# OpenTallas tools/mem_compiler/s81_pma_gen.py: S81 SerDes analog PMA ABSTRACT ot_s81_pma_txm (assumed footprint/timing)
VERSION 5.7 ;
BUSBITCHARS "[]" ;
DIVIDERCHAR "/" ;
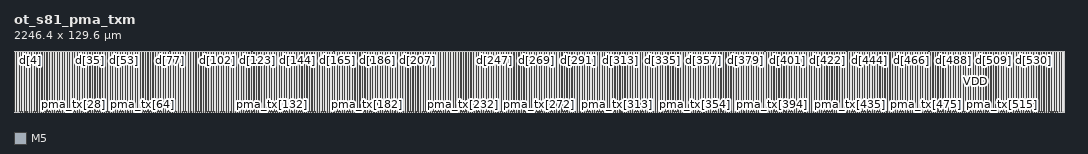
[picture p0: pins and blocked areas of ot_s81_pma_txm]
MACRO ot_s81_pma_txm
  FOREIGN ot_s81_pma_txm 0 0 ;
  SYMMETRY X Y ;
  SIZE 2246.400 BY 129.600 ;
  CLASS BLOCK ;
  PIN ck
    DIRECTION INPUT ;
    USE CLOCK ;
    SHAPE ABUTMENT ;
    PORT
      LAYER M5 ;
      RECT 11.412 129.408 11.436 129.600 ;
    END
  END ck
  PIN d_v
    DIRECTION INPUT ;
    USE SIGNAL ;
    SHAPE ABUTMENT ;
    PORT
      LAYER M5 ;
      RECT 15.492 129.408 15.516 129.600 ;
    END
  END d_v
  PIN d[0]
    DIRECTION INPUT ;
    USE SIGNAL ;
    SHAPE ABUTMENT ;
    PORT
      LAYER M5 ;
      RECT 19.572 129.408 19.596 129.600 ;
    END
  END d[0]
  PIN d[1]
    DIRECTION INPUT ;
    USE SIGNAL ;
    SHAPE ABUTMENT ;
    PORT
      LAYER M5 ;
      RECT 23.652 129.408 23.676 129.600 ;
    END
  END d[1]
  PIN d[2]
    DIRECTION INPUT ;
    USE SIGNAL ;
    SHAPE ABUTMENT ;
    PORT
      LAYER M5 ;
      RECT 27.732 129.408 27.756 129.600 ;
    END
  END d[2]
  PIN d[3]
    DIRECTION INPUT ;
    USE SIGNAL ;
    SHAPE ABUTMENT ;
    PORT
      LAYER M5 ;
      RECT 31.812 129.408 31.836 129.600 ;
    END
  END d[3]
  PIN d[4]
    DIRECTION INPUT ;
    USE SIGNAL ;
    SHAPE ABUTMENT ;
    PORT
      LAYER M5 ;
      RECT 35.892 129.408 35.916 129.600 ;
    END
  END d[4]
  PIN d[5]
    DIRECTION INPUT ;
    USE SIGNAL ;
    SHAPE ABUTMENT ;
    PORT
      LAYER M5 ;
      RECT 39.972 129.408 39.996 129.600 ;
    END
  END d[5]
  PIN d[6]
    DIRECTION INPUT ;
    USE SIGNAL ;
    SHAPE ABUTMENT ;
    PORT
      LAYER M5 ;
      RECT 44.052 129.408 44.076 129.600 ;
    END
  END d[6]
  PIN d[7]
    DIRECTION INPUT ;
    USE SIGNAL ;
    SHAPE ABUTMENT ;
    PORT
      LAYER M5 ;
      RECT 48.132 129.408 48.156 129.600 ;
    END
  END d[7]
  PIN d[8]
    DIRECTION INPUT ;
    USE SIGNAL ;
    SHAPE ABUTMENT ;
    PORT
      LAYER M5 ;
      RECT 52.212 129.408 52.236 129.600 ;
    END
  END d[8]
  PIN d[9]
    DIRECTION INPUT ;
    USE SIGNAL ;
    SHAPE ABUTMENT ;
    PORT
      LAYER M5 ;
      RECT 56.292 129.408 56.316 129.600 ;
    END
  END d[9]
  PIN d[10]
    DIRECTION INPUT ;
    USE SIGNAL ;
    SHAPE ABUTMENT ;
    PORT
      LAYER M5 ;
      RECT 60.372 129.408 60.396 129.600 ;
    END
  END d[10]
  PIN d[11]
    DIRECTION INPUT ;
    USE SIGNAL ;
    SHAPE ABUTMENT ;
    PORT
      LAYER M5 ;
      RECT 64.452 129.408 64.476 129.600 ;
    END
  END d[11]
  PIN d[12]
    DIRECTION INPUT ;
    USE SIGNAL ;
    SHAPE ABUTMENT ;
    PORT
      LAYER M5 ;
      RECT 68.532 129.408 68.556 129.600 ;
    END
  END d[12]
  PIN d[13]
    DIRECTION INPUT ;
    USE SIGNAL ;
    SHAPE ABUTMENT ;
    PORT
      LAYER M5 ;
      RECT 72.612 129.408 72.636 129.600 ;
    END
  END d[13]
  PIN d[14]
    DIRECTION INPUT ;
    USE SIGNAL ;
    SHAPE ABUTMENT ;
    PORT
      LAYER M5 ;
      RECT 76.692 129.408 76.716 129.600 ;
    END
  END d[14]
  PIN d[15]
    DIRECTION INPUT ;
    USE SIGNAL ;
    SHAPE ABUTMENT ;
    PORT
      LAYER M5 ;
      RECT 80.772 129.408 80.796 129.600 ;
    END
  END d[15]
  PIN d[16]
    DIRECTION INPUT ;
    USE SIGNAL ;
    SHAPE ABUTMENT ;
    PORT
      LAYER M5 ;
      RECT 84.852 129.408 84.876 129.600 ;
    END
  END d[16]
  PIN d[17]
    DIRECTION INPUT ;
    USE SIGNAL ;
    SHAPE ABUTMENT ;
    PORT
      LAYER M5 ;
      RECT 88.932 129.408 88.956 129.600 ;
    END
  END d[17]
  PIN d[18]
    DIRECTION INPUT ;
    USE SIGNAL ;
    SHAPE ABUTMENT ;
    PORT
      LAYER M5 ;
      RECT 93.012 129.408 93.036 129.600 ;
    END
  END d[18]
  PIN d[19]
    DIRECTION INPUT ;
    USE SIGNAL ;
    SHAPE ABUTMENT ;
    PORT
      LAYER M5 ;
      RECT 97.092 129.408 97.116 129.600 ;
    END
  END d[19]
  PIN d[20]
    DIRECTION INPUT ;
    USE SIGNAL ;
    SHAPE ABUTMENT ;
    PORT
      LAYER M5 ;
      RECT 101.172 129.408 101.196 129.600 ;
    END
  END d[20]
  PIN d[21]
    DIRECTION INPUT ;
    USE SIGNAL ;
    SHAPE ABUTMENT ;
    PORT
      LAYER M5 ;
      RECT 105.252 129.408 105.276 129.600 ;
    END
  END d[21]
  PIN d[22]
    DIRECTION INPUT ;
    USE SIGNAL ;
    SHAPE ABUTMENT ;
    PORT
      LAYER M5 ;
      RECT 109.332 129.408 109.356 129.600 ;
    END
  END d[22]
  PIN d[23]
    DIRECTION INPUT ;
    USE SIGNAL ;
    SHAPE ABUTMENT ;
    PORT
      LAYER M5 ;
      RECT 113.412 129.408 113.436 129.600 ;
    END
  END d[23]
  PIN d[24]
    DIRECTION INPUT ;
    USE SIGNAL ;
    SHAPE ABUTMENT ;
    PORT
      LAYER M5 ;
      RECT 117.492 129.408 117.516 129.600 ;
    END
  END d[24]
  PIN d[25]
    DIRECTION INPUT ;
    USE SIGNAL ;
    SHAPE ABUTMENT ;
    PORT
      LAYER M5 ;
      RECT 121.572 129.408 121.596 129.600 ;
    END
  END d[25]
  PIN d[26]
    DIRECTION INPUT ;
    USE SIGNAL ;
    SHAPE ABUTMENT ;
    PORT
      LAYER M5 ;
      RECT 125.652 129.408 125.676 129.600 ;
    END
  END d[26]
  PIN d[27]
    DIRECTION INPUT ;
    USE SIGNAL ;
    SHAPE ABUTMENT ;
    PORT
      LAYER M5 ;
      RECT 129.732 129.408 129.756 129.600 ;
    END
  END d[27]
  PIN d[28]
    DIRECTION INPUT ;
    USE SIGNAL ;
    SHAPE ABUTMENT ;
    PORT
      LAYER M5 ;
      RECT 133.812 129.408 133.836 129.600 ;
    END
  END d[28]
  PIN d[29]
    DIRECTION INPUT ;
    USE SIGNAL ;
    SHAPE ABUTMENT ;
    PORT
      LAYER M5 ;
      RECT 137.892 129.408 137.916 129.600 ;
    END
  END d[29]
  PIN d[30]
    DIRECTION INPUT ;
    USE SIGNAL ;
    SHAPE ABUTMENT ;
    PORT
      LAYER M5 ;
      RECT 141.972 129.408 141.996 129.600 ;
    END
  END d[30]
  PIN d[31]
    DIRECTION INPUT ;
    USE SIGNAL ;
    SHAPE ABUTMENT ;
    PORT
      LAYER M5 ;
      RECT 146.052 129.408 146.076 129.600 ;
    END
  END d[31]
  PIN d[32]
    DIRECTION INPUT ;
    USE SIGNAL ;
    SHAPE ABUTMENT ;
    PORT
      LAYER M5 ;
      RECT 150.132 129.408 150.156 129.600 ;
    END
  END d[32]
  PIN d[33]
    DIRECTION INPUT ;
    USE SIGNAL ;
    SHAPE ABUTMENT ;
    PORT
      LAYER M5 ;
      RECT 154.212 129.408 154.236 129.600 ;
    END
  END d[33]
  PIN d[34]
    DIRECTION INPUT ;
    USE SIGNAL ;
    SHAPE ABUTMENT ;
    PORT
      LAYER M5 ;
      RECT 158.292 129.408 158.316 129.600 ;
    END
  END d[34]
  PIN d[35]
    DIRECTION INPUT ;
    USE SIGNAL ;
    SHAPE ABUTMENT ;
    PORT
      LAYER M5 ;
      RECT 162.372 129.408 162.396 129.600 ;
    END
  END d[35]
  PIN d[36]
    DIRECTION INPUT ;
    USE SIGNAL ;
    SHAPE ABUTMENT ;
    PORT
      LAYER M5 ;
      RECT 166.452 129.408 166.476 129.600 ;
    END
  END d[36]
  PIN d[37]
    DIRECTION INPUT ;
    USE SIGNAL ;
    SHAPE ABUTMENT ;
    PORT
      LAYER M5 ;
      RECT 170.532 129.408 170.556 129.600 ;
    END
  END d[37]
  PIN d[38]
    DIRECTION INPUT ;
    USE SIGNAL ;
    SHAPE ABUTMENT ;
    PORT
      LAYER M5 ;
      RECT 174.612 129.408 174.636 129.600 ;
    END
  END d[38]
  PIN d[39]
    DIRECTION INPUT ;
    USE SIGNAL ;
    SHAPE ABUTMENT ;
    PORT
      LAYER M5 ;
      RECT 178.692 129.408 178.716 129.600 ;
    END
  END d[39]
  PIN d[40]
    DIRECTION INPUT ;
    USE SIGNAL ;
    SHAPE ABUTMENT ;
    PORT
      LAYER M5 ;
      RECT 182.772 129.408 182.796 129.600 ;
    END
  END d[40]
  PIN d[41]
    DIRECTION INPUT ;
    USE SIGNAL ;
    SHAPE ABUTMENT ;
    PORT
      LAYER M5 ;
      RECT 186.852 129.408 186.876 129.600 ;
    END
  END d[41]
  PIN d[42]
    DIRECTION INPUT ;
    USE SIGNAL ;
    SHAPE ABUTMENT ;
    PORT
      LAYER M5 ;
      RECT 190.932 129.408 190.956 129.600 ;
    END
  END d[42]
  PIN d[43]
    DIRECTION INPUT ;
    USE SIGNAL ;
    SHAPE ABUTMENT ;
    PORT
      LAYER M5 ;
      RECT 195.012 129.408 195.036 129.600 ;
    END
  END d[43]
  PIN d[44]
    DIRECTION INPUT ;
    USE SIGNAL ;
    SHAPE ABUTMENT ;
    PORT
      LAYER M5 ;
      RECT 199.092 129.408 199.116 129.600 ;
    END
  END d[44]
  PIN d[45]
    DIRECTION INPUT ;
    USE SIGNAL ;
    SHAPE ABUTMENT ;
    PORT
      LAYER M5 ;
      RECT 203.172 129.408 203.196 129.600 ;
    END
  END d[45]
  PIN d[46]
    DIRECTION INPUT ;
    USE SIGNAL ;
    SHAPE ABUTMENT ;
    PORT
      LAYER M5 ;
      RECT 207.252 129.408 207.276 129.600 ;
    END
  END d[46]
  PIN d[47]
    DIRECTION INPUT ;
    USE SIGNAL ;
    SHAPE ABUTMENT ;
    PORT
      LAYER M5 ;
      RECT 211.332 129.408 211.356 129.600 ;
    END
  END d[47]
  PIN d[48]
    DIRECTION INPUT ;
    USE SIGNAL ;
    SHAPE ABUTMENT ;
    PORT
      LAYER M5 ;
      RECT 215.412 129.408 215.436 129.600 ;
    END
  END d[48]
  PIN d[49]
    DIRECTION INPUT ;
    USE SIGNAL ;
    SHAPE ABUTMENT ;
    PORT
      LAYER M5 ;
      RECT 219.492 129.408 219.516 129.600 ;
    END
  END d[49]
  PIN d[50]
    DIRECTION INPUT ;
    USE SIGNAL ;
    SHAPE ABUTMENT ;
    PORT
      LAYER M5 ;
      RECT 223.572 129.408 223.596 129.600 ;
    END
  END d[50]
  PIN d[51]
    DIRECTION INPUT ;
    USE SIGNAL ;
    SHAPE ABUTMENT ;
    PORT
      LAYER M5 ;
      RECT 227.652 129.408 227.676 129.600 ;
    END
  END d[51]
  PIN d[52]
    DIRECTION INPUT ;
    USE SIGNAL ;
    SHAPE ABUTMENT ;
    PORT
      LAYER M5 ;
      RECT 231.732 129.408 231.756 129.600 ;
    END
  END d[52]
  PIN d[53]
    DIRECTION INPUT ;
    USE SIGNAL ;
    SHAPE ABUTMENT ;
    PORT
      LAYER M5 ;
      RECT 235.812 129.408 235.836 129.600 ;
    END
  END d[53]
  PIN d[54]
    DIRECTION INPUT ;
    USE SIGNAL ;
    SHAPE ABUTMENT ;
    PORT
      LAYER M5 ;
      RECT 239.892 129.408 239.916 129.600 ;
    END
  END d[54]
  PIN d[55]
    DIRECTION INPUT ;
    USE SIGNAL ;
    SHAPE ABUTMENT ;
    PORT
      LAYER M5 ;
      RECT 243.972 129.408 243.996 129.600 ;
    END
  END d[55]
  PIN d[56]
    DIRECTION INPUT ;
    USE SIGNAL ;
    SHAPE ABUTMENT ;
    PORT
      LAYER M5 ;
      RECT 248.052 129.408 248.076 129.600 ;
    END
  END d[56]
  PIN d[57]
    DIRECTION INPUT ;
    USE SIGNAL ;
    SHAPE ABUTMENT ;
    PORT
      LAYER M5 ;
      RECT 252.132 129.408 252.156 129.600 ;
    END
  END d[57]
  PIN d[58]
    DIRECTION INPUT ;
    USE SIGNAL ;
    SHAPE ABUTMENT ;
    PORT
      LAYER M5 ;
      RECT 256.212 129.408 256.236 129.600 ;
    END
  END d[58]
  PIN d[59]
    DIRECTION INPUT ;
    USE SIGNAL ;
    SHAPE ABUTMENT ;
    PORT
      LAYER M5 ;
      RECT 260.292 129.408 260.316 129.600 ;
    END
  END d[59]
  PIN d[60]
    DIRECTION INPUT ;
    USE SIGNAL ;
    SHAPE ABUTMENT ;
    PORT
      LAYER M5 ;
      RECT 264.372 129.408 264.396 129.600 ;
    END
  END d[60]
  PIN d[61]
    DIRECTION INPUT ;
    USE SIGNAL ;
    SHAPE ABUTMENT ;
    PORT
      LAYER M5 ;
      RECT 268.452 129.408 268.476 129.600 ;
    END
  END d[61]
  PIN d[62]
    DIRECTION INPUT ;
    USE SIGNAL ;
    SHAPE ABUTMENT ;
    PORT
      LAYER M5 ;
      RECT 272.532 129.408 272.556 129.600 ;
    END
  END d[62]
  PIN d[63]
    DIRECTION INPUT ;
    USE SIGNAL ;
    SHAPE ABUTMENT ;
    PORT
      LAYER M5 ;
      RECT 276.612 129.408 276.636 129.600 ;
    END
  END d[63]
  PIN d[64]
    DIRECTION INPUT ;
    USE SIGNAL ;
    SHAPE ABUTMENT ;
    PORT
      LAYER M5 ;
      RECT 280.692 129.408 280.716 129.600 ;
    END
  END d[64]
  PIN d[65]
    DIRECTION INPUT ;
    USE SIGNAL ;
    SHAPE ABUTMENT ;
    PORT
      LAYER M5 ;
      RECT 284.772 129.408 284.796 129.600 ;
    END
  END d[65]
  PIN d[66]
    DIRECTION INPUT ;
    USE SIGNAL ;
    SHAPE ABUTMENT ;
    PORT
      LAYER M5 ;
      RECT 288.852 129.408 288.876 129.600 ;
    END
  END d[66]
  PIN d[67]
    DIRECTION INPUT ;
    USE SIGNAL ;
    SHAPE ABUTMENT ;
    PORT
      LAYER M5 ;
      RECT 292.932 129.408 292.956 129.600 ;
    END
  END d[67]
  PIN d[68]
    DIRECTION INPUT ;
    USE SIGNAL ;
    SHAPE ABUTMENT ;
    PORT
      LAYER M5 ;
      RECT 297.012 129.408 297.036 129.600 ;
    END
  END d[68]
  PIN d[69]
    DIRECTION INPUT ;
    USE SIGNAL ;
    SHAPE ABUTMENT ;
    PORT
      LAYER M5 ;
      RECT 301.092 129.408 301.116 129.600 ;
    END
  END d[69]
  PIN d[70]
    DIRECTION INPUT ;
    USE SIGNAL ;
    SHAPE ABUTMENT ;
    PORT
      LAYER M5 ;
      RECT 305.172 129.408 305.196 129.600 ;
    END
  END d[70]
  PIN d[71]
    DIRECTION INPUT ;
    USE SIGNAL ;
    SHAPE ABUTMENT ;
    PORT
      LAYER M5 ;
      RECT 309.252 129.408 309.276 129.600 ;
    END
  END d[71]
  PIN d[72]
    DIRECTION INPUT ;
    USE SIGNAL ;
    SHAPE ABUTMENT ;
    PORT
      LAYER M5 ;
      RECT 313.332 129.408 313.356 129.600 ;
    END
  END d[72]
  PIN d[73]
    DIRECTION INPUT ;
    USE SIGNAL ;
    SHAPE ABUTMENT ;
    PORT
      LAYER M5 ;
      RECT 317.412 129.408 317.436 129.600 ;
    END
  END d[73]
  PIN d[74]
    DIRECTION INPUT ;
    USE SIGNAL ;
    SHAPE ABUTMENT ;
    PORT
      LAYER M5 ;
      RECT 321.492 129.408 321.516 129.600 ;
    END
  END d[74]
  PIN d[75]
    DIRECTION INPUT ;
    USE SIGNAL ;
    SHAPE ABUTMENT ;
    PORT
      LAYER M5 ;
      RECT 325.572 129.408 325.596 129.600 ;
    END
  END d[75]
  PIN d[76]
    DIRECTION INPUT ;
    USE SIGNAL ;
    SHAPE ABUTMENT ;
    PORT
      LAYER M5 ;
      RECT 329.652 129.408 329.676 129.600 ;
    END
  END d[76]
  PIN d[77]
    DIRECTION INPUT ;
    USE SIGNAL ;
    SHAPE ABUTMENT ;
    PORT
      LAYER M5 ;
      RECT 333.732 129.408 333.756 129.600 ;
    END
  END d[77]
  PIN d[78]
    DIRECTION INPUT ;
    USE SIGNAL ;
    SHAPE ABUTMENT ;
    PORT
      LAYER M5 ;
      RECT 337.812 129.408 337.836 129.600 ;
    END
  END d[78]
  PIN d[79]
    DIRECTION INPUT ;
    USE SIGNAL ;
    SHAPE ABUTMENT ;
    PORT
      LAYER M5 ;
      RECT 341.892 129.408 341.916 129.600 ;
    END
  END d[79]
  PIN d[80]
    DIRECTION INPUT ;
    USE SIGNAL ;
    SHAPE ABUTMENT ;
    PORT
      LAYER M5 ;
      RECT 345.972 129.408 345.996 129.600 ;
    END
  END d[80]
  PIN d[81]
    DIRECTION INPUT ;
    USE SIGNAL ;
    SHAPE ABUTMENT ;
    PORT
      LAYER M5 ;
      RECT 350.052 129.408 350.076 129.600 ;
    END
  END d[81]
  PIN d[82]
    DIRECTION INPUT ;
    USE SIGNAL ;
    SHAPE ABUTMENT ;
    PORT
      LAYER M5 ;
      RECT 354.132 129.408 354.156 129.600 ;
    END
  END d[82]
  PIN d[83]
    DIRECTION INPUT ;
    USE SIGNAL ;
    SHAPE ABUTMENT ;
    PORT
      LAYER M5 ;
      RECT 358.212 129.408 358.236 129.600 ;
    END
  END d[83]
  PIN d[84]
    DIRECTION INPUT ;
    USE SIGNAL ;
    SHAPE ABUTMENT ;
    PORT
      LAYER M5 ;
      RECT 362.292 129.408 362.316 129.600 ;
    END
  END d[84]
  PIN d[85]
    DIRECTION INPUT ;
    USE SIGNAL ;
    SHAPE ABUTMENT ;
    PORT
      LAYER M5 ;
      RECT 366.372 129.408 366.396 129.600 ;
    END
  END d[85]
  PIN d[86]
    DIRECTION INPUT ;
    USE SIGNAL ;
    SHAPE ABUTMENT ;
    PORT
      LAYER M5 ;
      RECT 370.452 129.408 370.476 129.600 ;
    END
  END d[86]
  PIN d[87]
    DIRECTION INPUT ;
    USE SIGNAL ;
    SHAPE ABUTMENT ;
    PORT
      LAYER M5 ;
      RECT 374.532 129.408 374.556 129.600 ;
    END
  END d[87]
  PIN d[88]
    DIRECTION INPUT ;
    USE SIGNAL ;
    SHAPE ABUTMENT ;
    PORT
      LAYER M5 ;
      RECT 378.612 129.408 378.636 129.600 ;
    END
  END d[88]
  PIN d[89]
    DIRECTION INPUT ;
    USE SIGNAL ;
    SHAPE ABUTMENT ;
    PORT
      LAYER M5 ;
      RECT 382.692 129.408 382.716 129.600 ;
    END
  END d[89]
  PIN d[90]
    DIRECTION INPUT ;
    USE SIGNAL ;
    SHAPE ABUTMENT ;
    PORT
      LAYER M5 ;
      RECT 386.772 129.408 386.796 129.600 ;
    END
  END d[90]
  PIN d[91]
    DIRECTION INPUT ;
    USE SIGNAL ;
    SHAPE ABUTMENT ;
    PORT
      LAYER M5 ;
      RECT 390.852 129.408 390.876 129.600 ;
    END
  END d[91]
  PIN d[92]
    DIRECTION INPUT ;
    USE SIGNAL ;
    SHAPE ABUTMENT ;
    PORT
      LAYER M5 ;
      RECT 394.932 129.408 394.956 129.600 ;
    END
  END d[92]
  PIN d[93]
    DIRECTION INPUT ;
    USE SIGNAL ;
    SHAPE ABUTMENT ;
    PORT
      LAYER M5 ;
      RECT 399.012 129.408 399.036 129.600 ;
    END
  END d[93]
  PIN d[94]
    DIRECTION INPUT ;
    USE SIGNAL ;
    SHAPE ABUTMENT ;
    PORT
      LAYER M5 ;
      RECT 403.092 129.408 403.116 129.600 ;
    END
  END d[94]
  PIN d[95]
    DIRECTION INPUT ;
    USE SIGNAL ;
    SHAPE ABUTMENT ;
    PORT
      LAYER M5 ;
      RECT 407.172 129.408 407.196 129.600 ;
    END
  END d[95]
  PIN d[96]
    DIRECTION INPUT ;
    USE SIGNAL ;
    SHAPE ABUTMENT ;
    PORT
      LAYER M5 ;
      RECT 411.252 129.408 411.276 129.600 ;
    END
  END d[96]
  PIN d[97]
    DIRECTION INPUT ;
    USE SIGNAL ;
    SHAPE ABUTMENT ;
    PORT
      LAYER M5 ;
      RECT 415.332 129.408 415.356 129.600 ;
    END
  END d[97]
  PIN d[98]
    DIRECTION INPUT ;
    USE SIGNAL ;
    SHAPE ABUTMENT ;
    PORT
      LAYER M5 ;
      RECT 419.412 129.408 419.436 129.600 ;
    END
  END d[98]
  PIN d[99]
    DIRECTION INPUT ;
    USE SIGNAL ;
    SHAPE ABUTMENT ;
    PORT
      LAYER M5 ;
      RECT 423.492 129.408 423.516 129.600 ;
    END
  END d[99]
  PIN d[100]
    DIRECTION INPUT ;
    USE SIGNAL ;
    SHAPE ABUTMENT ;
    PORT
      LAYER M5 ;
      RECT 427.572 129.408 427.596 129.600 ;
    END
  END d[100]
  PIN d[101]
    DIRECTION INPUT ;
    USE SIGNAL ;
    SHAPE ABUTMENT ;
    PORT
      LAYER M5 ;
      RECT 431.652 129.408 431.676 129.600 ;
    END
  END d[101]
  PIN d[102]
    DIRECTION INPUT ;
    USE SIGNAL ;
    SHAPE ABUTMENT ;
    PORT
      LAYER M5 ;
      RECT 435.732 129.408 435.756 129.600 ;
    END
  END d[102]
  PIN d[103]
    DIRECTION INPUT ;
    USE SIGNAL ;
    SHAPE ABUTMENT ;
    PORT
      LAYER M5 ;
      RECT 439.812 129.408 439.836 129.600 ;
    END
  END d[103]
  PIN d[104]
    DIRECTION INPUT ;
    USE SIGNAL ;
    SHAPE ABUTMENT ;
    PORT
      LAYER M5 ;
      RECT 443.892 129.408 443.916 129.600 ;
    END
  END d[104]
  PIN d[105]
    DIRECTION INPUT ;
    USE SIGNAL ;
    SHAPE ABUTMENT ;
    PORT
      LAYER M5 ;
      RECT 447.972 129.408 447.996 129.600 ;
    END
  END d[105]
  PIN d[106]
    DIRECTION INPUT ;
    USE SIGNAL ;
    SHAPE ABUTMENT ;
    PORT
      LAYER M5 ;
      RECT 452.052 129.408 452.076 129.600 ;
    END
  END d[106]
  PIN d[107]
    DIRECTION INPUT ;
    USE SIGNAL ;
    SHAPE ABUTMENT ;
    PORT
      LAYER M5 ;
      RECT 456.132 129.408 456.156 129.600 ;
    END
  END d[107]
  PIN d[108]
    DIRECTION INPUT ;
    USE SIGNAL ;
    SHAPE ABUTMENT ;
    PORT
      LAYER M5 ;
      RECT 460.212 129.408 460.236 129.600 ;
    END
  END d[108]
  PIN d[109]
    DIRECTION INPUT ;
    USE SIGNAL ;
    SHAPE ABUTMENT ;
    PORT
      LAYER M5 ;
      RECT 464.292 129.408 464.316 129.600 ;
    END
  END d[109]
  PIN d[110]
    DIRECTION INPUT ;
    USE SIGNAL ;
    SHAPE ABUTMENT ;
    PORT
      LAYER M5 ;
      RECT 468.372 129.408 468.396 129.600 ;
    END
  END d[110]
  PIN d[111]
    DIRECTION INPUT ;
    USE SIGNAL ;
    SHAPE ABUTMENT ;
    PORT
      LAYER M5 ;
      RECT 472.452 129.408 472.476 129.600 ;
    END
  END d[111]
  PIN d[112]
    DIRECTION INPUT ;
    USE SIGNAL ;
    SHAPE ABUTMENT ;
    PORT
      LAYER M5 ;
      RECT 476.532 129.408 476.556 129.600 ;
    END
  END d[112]
  PIN d[113]
    DIRECTION INPUT ;
    USE SIGNAL ;
    SHAPE ABUTMENT ;
    PORT
      LAYER M5 ;
      RECT 480.612 129.408 480.636 129.600 ;
    END
  END d[113]
  PIN d[114]
    DIRECTION INPUT ;
    USE SIGNAL ;
    SHAPE ABUTMENT ;
    PORT
      LAYER M5 ;
      RECT 484.692 129.408 484.716 129.600 ;
    END
  END d[114]
  PIN d[115]
    DIRECTION INPUT ;
    USE SIGNAL ;
    SHAPE ABUTMENT ;
    PORT
      LAYER M5 ;
      RECT 488.772 129.408 488.796 129.600 ;
    END
  END d[115]
  PIN d[116]
    DIRECTION INPUT ;
    USE SIGNAL ;
    SHAPE ABUTMENT ;
    PORT
      LAYER M5 ;
      RECT 492.852 129.408 492.876 129.600 ;
    END
  END d[116]
  PIN d[117]
    DIRECTION INPUT ;
    USE SIGNAL ;
    SHAPE ABUTMENT ;
    PORT
      LAYER M5 ;
      RECT 496.932 129.408 496.956 129.600 ;
    END
  END d[117]
  PIN d[118]
    DIRECTION INPUT ;
    USE SIGNAL ;
    SHAPE ABUTMENT ;
    PORT
      LAYER M5 ;
      RECT 501.012 129.408 501.036 129.600 ;
    END
  END d[118]
  PIN d[119]
    DIRECTION INPUT ;
    USE SIGNAL ;
    SHAPE ABUTMENT ;
    PORT
      LAYER M5 ;
      RECT 505.092 129.408 505.116 129.600 ;
    END
  END d[119]
  PIN d[120]
    DIRECTION INPUT ;
    USE SIGNAL ;
    SHAPE ABUTMENT ;
    PORT
      LAYER M5 ;
      RECT 509.172 129.408 509.196 129.600 ;
    END
  END d[120]
  PIN d[121]
    DIRECTION INPUT ;
    USE SIGNAL ;
    SHAPE ABUTMENT ;
    PORT
      LAYER M5 ;
      RECT 513.252 129.408 513.276 129.600 ;
    END
  END d[121]
  PIN d[122]
    DIRECTION INPUT ;
    USE SIGNAL ;
    SHAPE ABUTMENT ;
    PORT
      LAYER M5 ;
      RECT 517.332 129.408 517.356 129.600 ;
    END
  END d[122]
  PIN d[123]
    DIRECTION INPUT ;
    USE SIGNAL ;
    SHAPE ABUTMENT ;
    PORT
      LAYER M5 ;
      RECT 521.412 129.408 521.436 129.600 ;
    END
  END d[123]
  PIN d[124]
    DIRECTION INPUT ;
    USE SIGNAL ;
    SHAPE ABUTMENT ;
    PORT
      LAYER M5 ;
      RECT 525.492 129.408 525.516 129.600 ;
    END
  END d[124]
  PIN d[125]
    DIRECTION INPUT ;
    USE SIGNAL ;
    SHAPE ABUTMENT ;
    PORT
      LAYER M5 ;
      RECT 529.572 129.408 529.596 129.600 ;
    END
  END d[125]
  PIN d[126]
    DIRECTION INPUT ;
    USE SIGNAL ;
    SHAPE ABUTMENT ;
    PORT
      LAYER M5 ;
      RECT 533.652 129.408 533.676 129.600 ;
    END
  END d[126]
  PIN d[127]
    DIRECTION INPUT ;
    USE SIGNAL ;
    SHAPE ABUTMENT ;
    PORT
      LAYER M5 ;
      RECT 537.732 129.408 537.756 129.600 ;
    END
  END d[127]
  PIN d[128]
    DIRECTION INPUT ;
    USE SIGNAL ;
    SHAPE ABUTMENT ;
    PORT
      LAYER M5 ;
      RECT 541.812 129.408 541.836 129.600 ;
    END
  END d[128]
  PIN d[129]
    DIRECTION INPUT ;
    USE SIGNAL ;
    SHAPE ABUTMENT ;
    PORT
      LAYER M5 ;
      RECT 545.892 129.408 545.916 129.600 ;
    END
  END d[129]
  PIN d[130]
    DIRECTION INPUT ;
    USE SIGNAL ;
    SHAPE ABUTMENT ;
    PORT
      LAYER M5 ;
      RECT 549.972 129.408 549.996 129.600 ;
    END
  END d[130]
  PIN d[131]
    DIRECTION INPUT ;
    USE SIGNAL ;
    SHAPE ABUTMENT ;
    PORT
      LAYER M5 ;
      RECT 554.052 129.408 554.076 129.600 ;
    END
  END d[131]
  PIN d[132]
    DIRECTION INPUT ;
    USE SIGNAL ;
    SHAPE ABUTMENT ;
    PORT
      LAYER M5 ;
      RECT 558.132 129.408 558.156 129.600 ;
    END
  END d[132]
  PIN d[133]
    DIRECTION INPUT ;
    USE SIGNAL ;
    SHAPE ABUTMENT ;
    PORT
      LAYER M5 ;
      RECT 562.212 129.408 562.236 129.600 ;
    END
  END d[133]
  PIN d[134]
    DIRECTION INPUT ;
    USE SIGNAL ;
    SHAPE ABUTMENT ;
    PORT
      LAYER M5 ;
      RECT 566.292 129.408 566.316 129.600 ;
    END
  END d[134]
  PIN d[135]
    DIRECTION INPUT ;
    USE SIGNAL ;
    SHAPE ABUTMENT ;
    PORT
      LAYER M5 ;
      RECT 570.372 129.408 570.396 129.600 ;
    END
  END d[135]
  PIN d[136]
    DIRECTION INPUT ;
    USE SIGNAL ;
    SHAPE ABUTMENT ;
    PORT
      LAYER M5 ;
      RECT 574.452 129.408 574.476 129.600 ;
    END
  END d[136]
  PIN d[137]
    DIRECTION INPUT ;
    USE SIGNAL ;
    SHAPE ABUTMENT ;
    PORT
      LAYER M5 ;
      RECT 578.532 129.408 578.556 129.600 ;
    END
  END d[137]
  PIN d[138]
    DIRECTION INPUT ;
    USE SIGNAL ;
    SHAPE ABUTMENT ;
    PORT
      LAYER M5 ;
      RECT 582.612 129.408 582.636 129.600 ;
    END
  END d[138]
  PIN d[139]
    DIRECTION INPUT ;
    USE SIGNAL ;
    SHAPE ABUTMENT ;
    PORT
      LAYER M5 ;
      RECT 586.692 129.408 586.716 129.600 ;
    END
  END d[139]
  PIN d[140]
    DIRECTION INPUT ;
    USE SIGNAL ;
    SHAPE ABUTMENT ;
    PORT
      LAYER M5 ;
      RECT 590.772 129.408 590.796 129.600 ;
    END
  END d[140]
  PIN d[141]
    DIRECTION INPUT ;
    USE SIGNAL ;
    SHAPE ABUTMENT ;
    PORT
      LAYER M5 ;
      RECT 594.852 129.408 594.876 129.600 ;
    END
  END d[141]
  PIN d[142]
    DIRECTION INPUT ;
    USE SIGNAL ;
    SHAPE ABUTMENT ;
    PORT
      LAYER M5 ;
      RECT 598.932 129.408 598.956 129.600 ;
    END
  END d[142]
  PIN d[143]
    DIRECTION INPUT ;
    USE SIGNAL ;
    SHAPE ABUTMENT ;
    PORT
      LAYER M5 ;
      RECT 603.012 129.408 603.036 129.600 ;
    END
  END d[143]
  PIN d[144]
    DIRECTION INPUT ;
    USE SIGNAL ;
    SHAPE ABUTMENT ;
    PORT
      LAYER M5 ;
      RECT 607.092 129.408 607.116 129.600 ;
    END
  END d[144]
  PIN d[145]
    DIRECTION INPUT ;
    USE SIGNAL ;
    SHAPE ABUTMENT ;
    PORT
      LAYER M5 ;
      RECT 611.172 129.408 611.196 129.600 ;
    END
  END d[145]
  PIN d[146]
    DIRECTION INPUT ;
    USE SIGNAL ;
    SHAPE ABUTMENT ;
    PORT
      LAYER M5 ;
      RECT 615.252 129.408 615.276 129.600 ;
    END
  END d[146]
  PIN d[147]
    DIRECTION INPUT ;
    USE SIGNAL ;
    SHAPE ABUTMENT ;
    PORT
      LAYER M5 ;
      RECT 619.332 129.408 619.356 129.600 ;
    END
  END d[147]
  PIN d[148]
    DIRECTION INPUT ;
    USE SIGNAL ;
    SHAPE ABUTMENT ;
    PORT
      LAYER M5 ;
      RECT 623.412 129.408 623.436 129.600 ;
    END
  END d[148]
  PIN d[149]
    DIRECTION INPUT ;
    USE SIGNAL ;
    SHAPE ABUTMENT ;
    PORT
      LAYER M5 ;
      RECT 627.492 129.408 627.516 129.600 ;
    END
  END d[149]
  PIN d[150]
    DIRECTION INPUT ;
    USE SIGNAL ;
    SHAPE ABUTMENT ;
    PORT
      LAYER M5 ;
      RECT 631.572 129.408 631.596 129.600 ;
    END
  END d[150]
  PIN d[151]
    DIRECTION INPUT ;
    USE SIGNAL ;
    SHAPE ABUTMENT ;
    PORT
      LAYER M5 ;
      RECT 635.652 129.408 635.676 129.600 ;
    END
  END d[151]
  PIN d[152]
    DIRECTION INPUT ;
    USE SIGNAL ;
    SHAPE ABUTMENT ;
    PORT
      LAYER M5 ;
      RECT 639.732 129.408 639.756 129.600 ;
    END
  END d[152]
  PIN d[153]
    DIRECTION INPUT ;
    USE SIGNAL ;
    SHAPE ABUTMENT ;
    PORT
      LAYER M5 ;
      RECT 643.812 129.408 643.836 129.600 ;
    END
  END d[153]
  PIN d[154]
    DIRECTION INPUT ;
    USE SIGNAL ;
    SHAPE ABUTMENT ;
    PORT
      LAYER M5 ;
      RECT 647.892 129.408 647.916 129.600 ;
    END
  END d[154]
  PIN d[155]
    DIRECTION INPUT ;
    USE SIGNAL ;
    SHAPE ABUTMENT ;
    PORT
      LAYER M5 ;
      RECT 651.972 129.408 651.996 129.600 ;
    END
  END d[155]
  PIN d[156]
    DIRECTION INPUT ;
    USE SIGNAL ;
    SHAPE ABUTMENT ;
    PORT
      LAYER M5 ;
      RECT 656.052 129.408 656.076 129.600 ;
    END
  END d[156]
  PIN d[157]
    DIRECTION INPUT ;
    USE SIGNAL ;
    SHAPE ABUTMENT ;
    PORT
      LAYER M5 ;
      RECT 660.132 129.408 660.156 129.600 ;
    END
  END d[157]
  PIN d[158]
    DIRECTION INPUT ;
    USE SIGNAL ;
    SHAPE ABUTMENT ;
    PORT
      LAYER M5 ;
      RECT 664.212 129.408 664.236 129.600 ;
    END
  END d[158]
  PIN d[159]
    DIRECTION INPUT ;
    USE SIGNAL ;
    SHAPE ABUTMENT ;
    PORT
      LAYER M5 ;
      RECT 668.292 129.408 668.316 129.600 ;
    END
  END d[159]
  PIN d[160]
    DIRECTION INPUT ;
    USE SIGNAL ;
    SHAPE ABUTMENT ;
    PORT
      LAYER M5 ;
      RECT 672.372 129.408 672.396 129.600 ;
    END
  END d[160]
  PIN d[161]
    DIRECTION INPUT ;
    USE SIGNAL ;
    SHAPE ABUTMENT ;
    PORT
      LAYER M5 ;
      RECT 676.452 129.408 676.476 129.600 ;
    END
  END d[161]
  PIN d[162]
    DIRECTION INPUT ;
    USE SIGNAL ;
    SHAPE ABUTMENT ;
    PORT
      LAYER M5 ;
      RECT 680.532 129.408 680.556 129.600 ;
    END
  END d[162]
  PIN d[163]
    DIRECTION INPUT ;
    USE SIGNAL ;
    SHAPE ABUTMENT ;
    PORT
      LAYER M5 ;
      RECT 684.612 129.408 684.636 129.600 ;
    END
  END d[163]
  PIN d[164]
    DIRECTION INPUT ;
    USE SIGNAL ;
    SHAPE ABUTMENT ;
    PORT
      LAYER M5 ;
      RECT 688.692 129.408 688.716 129.600 ;
    END
  END d[164]
  PIN d[165]
    DIRECTION INPUT ;
    USE SIGNAL ;
    SHAPE ABUTMENT ;
    PORT
      LAYER M5 ;
      RECT 692.772 129.408 692.796 129.600 ;
    END
  END d[165]
  PIN d[166]
    DIRECTION INPUT ;
    USE SIGNAL ;
    SHAPE ABUTMENT ;
    PORT
      LAYER M5 ;
      RECT 696.852 129.408 696.876 129.600 ;
    END
  END d[166]
  PIN d[167]
    DIRECTION INPUT ;
    USE SIGNAL ;
    SHAPE ABUTMENT ;
    PORT
      LAYER M5 ;
      RECT 700.932 129.408 700.956 129.600 ;
    END
  END d[167]
  PIN d[168]
    DIRECTION INPUT ;
    USE SIGNAL ;
    SHAPE ABUTMENT ;
    PORT
      LAYER M5 ;
      RECT 705.012 129.408 705.036 129.600 ;
    END
  END d[168]
  PIN d[169]
    DIRECTION INPUT ;
    USE SIGNAL ;
    SHAPE ABUTMENT ;
    PORT
      LAYER M5 ;
      RECT 709.092 129.408 709.116 129.600 ;
    END
  END d[169]
  PIN d[170]
    DIRECTION INPUT ;
    USE SIGNAL ;
    SHAPE ABUTMENT ;
    PORT
      LAYER M5 ;
      RECT 713.172 129.408 713.196 129.600 ;
    END
  END d[170]
  PIN d[171]
    DIRECTION INPUT ;
    USE SIGNAL ;
    SHAPE ABUTMENT ;
    PORT
      LAYER M5 ;
      RECT 717.252 129.408 717.276 129.600 ;
    END
  END d[171]
  PIN d[172]
    DIRECTION INPUT ;
    USE SIGNAL ;
    SHAPE ABUTMENT ;
    PORT
      LAYER M5 ;
      RECT 721.332 129.408 721.356 129.600 ;
    END
  END d[172]
  PIN d[173]
    DIRECTION INPUT ;
    USE SIGNAL ;
    SHAPE ABUTMENT ;
    PORT
      LAYER M5 ;
      RECT 725.412 129.408 725.436 129.600 ;
    END
  END d[173]
  PIN d[174]
    DIRECTION INPUT ;
    USE SIGNAL ;
    SHAPE ABUTMENT ;
    PORT
      LAYER M5 ;
      RECT 729.492 129.408 729.516 129.600 ;
    END
  END d[174]
  PIN d[175]
    DIRECTION INPUT ;
    USE SIGNAL ;
    SHAPE ABUTMENT ;
    PORT
      LAYER M5 ;
      RECT 733.572 129.408 733.596 129.600 ;
    END
  END d[175]
  PIN d[176]
    DIRECTION INPUT ;
    USE SIGNAL ;
    SHAPE ABUTMENT ;
    PORT
      LAYER M5 ;
      RECT 737.652 129.408 737.676 129.600 ;
    END
  END d[176]
  PIN d[177]
    DIRECTION INPUT ;
    USE SIGNAL ;
    SHAPE ABUTMENT ;
    PORT
      LAYER M5 ;
      RECT 741.732 129.408 741.756 129.600 ;
    END
  END d[177]
  PIN d[178]
    DIRECTION INPUT ;
    USE SIGNAL ;
    SHAPE ABUTMENT ;
    PORT
      LAYER M5 ;
      RECT 745.812 129.408 745.836 129.600 ;
    END
  END d[178]
  PIN d[179]
    DIRECTION INPUT ;
    USE SIGNAL ;
    SHAPE ABUTMENT ;
    PORT
      LAYER M5 ;
      RECT 749.892 129.408 749.916 129.600 ;
    END
  END d[179]
  PIN d[180]
    DIRECTION INPUT ;
    USE SIGNAL ;
    SHAPE ABUTMENT ;
    PORT
      LAYER M5 ;
      RECT 753.972 129.408 753.996 129.600 ;
    END
  END d[180]
  PIN d[181]
    DIRECTION INPUT ;
    USE SIGNAL ;
    SHAPE ABUTMENT ;
    PORT
      LAYER M5 ;
      RECT 758.052 129.408 758.076 129.600 ;
    END
  END d[181]
  PIN d[182]
    DIRECTION INPUT ;
    USE SIGNAL ;
    SHAPE ABUTMENT ;
    PORT
      LAYER M5 ;
      RECT 762.132 129.408 762.156 129.600 ;
    END
  END d[182]
  PIN d[183]
    DIRECTION INPUT ;
    USE SIGNAL ;
    SHAPE ABUTMENT ;
    PORT
      LAYER M5 ;
      RECT 766.212 129.408 766.236 129.600 ;
    END
  END d[183]
  PIN d[184]
    DIRECTION INPUT ;
    USE SIGNAL ;
    SHAPE ABUTMENT ;
    PORT
      LAYER M5 ;
      RECT 770.292 129.408 770.316 129.600 ;
    END
  END d[184]
  PIN d[185]
    DIRECTION INPUT ;
    USE SIGNAL ;
    SHAPE ABUTMENT ;
    PORT
      LAYER M5 ;
      RECT 774.372 129.408 774.396 129.600 ;
    END
  END d[185]
  PIN d[186]
    DIRECTION INPUT ;
    USE SIGNAL ;
    SHAPE ABUTMENT ;
    PORT
      LAYER M5 ;
      RECT 778.452 129.408 778.476 129.600 ;
    END
  END d[186]
  PIN d[187]
    DIRECTION INPUT ;
    USE SIGNAL ;
    SHAPE ABUTMENT ;
    PORT
      LAYER M5 ;
      RECT 782.532 129.408 782.556 129.600 ;
    END
  END d[187]
  PIN d[188]
    DIRECTION INPUT ;
    USE SIGNAL ;
    SHAPE ABUTMENT ;
    PORT
      LAYER M5 ;
      RECT 786.612 129.408 786.636 129.600 ;
    END
  END d[188]
  PIN d[189]
    DIRECTION INPUT ;
    USE SIGNAL ;
    SHAPE ABUTMENT ;
    PORT
      LAYER M5 ;
      RECT 790.692 129.408 790.716 129.600 ;
    END
  END d[189]
  PIN d[190]
    DIRECTION INPUT ;
    USE SIGNAL ;
    SHAPE ABUTMENT ;
    PORT
      LAYER M5 ;
      RECT 794.772 129.408 794.796 129.600 ;
    END
  END d[190]
  PIN d[191]
    DIRECTION INPUT ;
    USE SIGNAL ;
    SHAPE ABUTMENT ;
    PORT
      LAYER M5 ;
      RECT 798.852 129.408 798.876 129.600 ;
    END
  END d[191]
  PIN d[192]
    DIRECTION INPUT ;
    USE SIGNAL ;
    SHAPE ABUTMENT ;
    PORT
      LAYER M5 ;
      RECT 802.932 129.408 802.956 129.600 ;
    END
  END d[192]
  PIN d[193]
    DIRECTION INPUT ;
    USE SIGNAL ;
    SHAPE ABUTMENT ;
    PORT
      LAYER M5 ;
      RECT 807.012 129.408 807.036 129.600 ;
    END
  END d[193]
  PIN d[194]
    DIRECTION INPUT ;
    USE SIGNAL ;
    SHAPE ABUTMENT ;
    PORT
      LAYER M5 ;
      RECT 811.092 129.408 811.116 129.600 ;
    END
  END d[194]
  PIN d[195]
    DIRECTION INPUT ;
    USE SIGNAL ;
    SHAPE ABUTMENT ;
    PORT
      LAYER M5 ;
      RECT 815.172 129.408 815.196 129.600 ;
    END
  END d[195]
  PIN d[196]
    DIRECTION INPUT ;
    USE SIGNAL ;
    SHAPE ABUTMENT ;
    PORT
      LAYER M5 ;
      RECT 819.252 129.408 819.276 129.600 ;
    END
  END d[196]
  PIN d[197]
    DIRECTION INPUT ;
    USE SIGNAL ;
    SHAPE ABUTMENT ;
    PORT
      LAYER M5 ;
      RECT 823.332 129.408 823.356 129.600 ;
    END
  END d[197]
  PIN d[198]
    DIRECTION INPUT ;
    USE SIGNAL ;
    SHAPE ABUTMENT ;
    PORT
      LAYER M5 ;
      RECT 827.412 129.408 827.436 129.600 ;
    END
  END d[198]
  PIN d[199]
    DIRECTION INPUT ;
    USE SIGNAL ;
    SHAPE ABUTMENT ;
    PORT
      LAYER M5 ;
      RECT 831.492 129.408 831.516 129.600 ;
    END
  END d[199]
  PIN d[200]
    DIRECTION INPUT ;
    USE SIGNAL ;
    SHAPE ABUTMENT ;
    PORT
      LAYER M5 ;
      RECT 835.572 129.408 835.596 129.600 ;
    END
  END d[200]
  PIN d[201]
    DIRECTION INPUT ;
    USE SIGNAL ;
    SHAPE ABUTMENT ;
    PORT
      LAYER M5 ;
      RECT 839.652 129.408 839.676 129.600 ;
    END
  END d[201]
  PIN d[202]
    DIRECTION INPUT ;
    USE SIGNAL ;
    SHAPE ABUTMENT ;
    PORT
      LAYER M5 ;
      RECT 843.732 129.408 843.756 129.600 ;
    END
  END d[202]
  PIN d[203]
    DIRECTION INPUT ;
    USE SIGNAL ;
    SHAPE ABUTMENT ;
    PORT
      LAYER M5 ;
      RECT 847.812 129.408 847.836 129.600 ;
    END
  END d[203]
  PIN d[204]
    DIRECTION INPUT ;
    USE SIGNAL ;
    SHAPE ABUTMENT ;
    PORT
      LAYER M5 ;
      RECT 851.892 129.408 851.916 129.600 ;
    END
  END d[204]
  PIN d[205]
    DIRECTION INPUT ;
    USE SIGNAL ;
    SHAPE ABUTMENT ;
    PORT
      LAYER M5 ;
      RECT 855.972 129.408 855.996 129.600 ;
    END
  END d[205]
  PIN d[206]
    DIRECTION INPUT ;
    USE SIGNAL ;
    SHAPE ABUTMENT ;
    PORT
      LAYER M5 ;
      RECT 860.052 129.408 860.076 129.600 ;
    END
  END d[206]
  PIN d[207]
    DIRECTION INPUT ;
    USE SIGNAL ;
    SHAPE ABUTMENT ;
    PORT
      LAYER M5 ;
      RECT 864.132 129.408 864.156 129.600 ;
    END
  END d[207]
  PIN d[208]
    DIRECTION INPUT ;
    USE SIGNAL ;
    SHAPE ABUTMENT ;
    PORT
      LAYER M5 ;
      RECT 868.212 129.408 868.236 129.600 ;
    END
  END d[208]
  PIN d[209]
    DIRECTION INPUT ;
    USE SIGNAL ;
    SHAPE ABUTMENT ;
    PORT
      LAYER M5 ;
      RECT 872.292 129.408 872.316 129.600 ;
    END
  END d[209]
  PIN d[210]
    DIRECTION INPUT ;
    USE SIGNAL ;
    SHAPE ABUTMENT ;
    PORT
      LAYER M5 ;
      RECT 876.372 129.408 876.396 129.600 ;
    END
  END d[210]
  PIN d[211]
    DIRECTION INPUT ;
    USE SIGNAL ;
    SHAPE ABUTMENT ;
    PORT
      LAYER M5 ;
      RECT 880.452 129.408 880.476 129.600 ;
    END
  END d[211]
  PIN d[212]
    DIRECTION INPUT ;
    USE SIGNAL ;
    SHAPE ABUTMENT ;
    PORT
      LAYER M5 ;
      RECT 884.532 129.408 884.556 129.600 ;
    END
  END d[212]
  PIN d[213]
    DIRECTION INPUT ;
    USE SIGNAL ;
    SHAPE ABUTMENT ;
    PORT
      LAYER M5 ;
      RECT 888.612 129.408 888.636 129.600 ;
    END
  END d[213]
  PIN d[214]
    DIRECTION INPUT ;
    USE SIGNAL ;
    SHAPE ABUTMENT ;
    PORT
      LAYER M5 ;
      RECT 892.692 129.408 892.716 129.600 ;
    END
  END d[214]
  PIN d[215]
    DIRECTION INPUT ;
    USE SIGNAL ;
    SHAPE ABUTMENT ;
    PORT
      LAYER M5 ;
      RECT 896.772 129.408 896.796 129.600 ;
    END
  END d[215]
  PIN d[216]
    DIRECTION INPUT ;
    USE SIGNAL ;
    SHAPE ABUTMENT ;
    PORT
      LAYER M5 ;
      RECT 900.852 129.408 900.876 129.600 ;
    END
  END d[216]
  PIN d[217]
    DIRECTION INPUT ;
    USE SIGNAL ;
    SHAPE ABUTMENT ;
    PORT
      LAYER M5 ;
      RECT 904.932 129.408 904.956 129.600 ;
    END
  END d[217]
  PIN d[218]
    DIRECTION INPUT ;
    USE SIGNAL ;
    SHAPE ABUTMENT ;
    PORT
      LAYER M5 ;
      RECT 909.012 129.408 909.036 129.600 ;
    END
  END d[218]
  PIN d[219]
    DIRECTION INPUT ;
    USE SIGNAL ;
    SHAPE ABUTMENT ;
    PORT
      LAYER M5 ;
      RECT 913.092 129.408 913.116 129.600 ;
    END
  END d[219]
  PIN d[220]
    DIRECTION INPUT ;
    USE SIGNAL ;
    SHAPE ABUTMENT ;
    PORT
      LAYER M5 ;
      RECT 917.172 129.408 917.196 129.600 ;
    END
  END d[220]
  PIN d[221]
    DIRECTION INPUT ;
    USE SIGNAL ;
    SHAPE ABUTMENT ;
    PORT
      LAYER M5 ;
      RECT 921.252 129.408 921.276 129.600 ;
    END
  END d[221]
  PIN d[222]
    DIRECTION INPUT ;
    USE SIGNAL ;
    SHAPE ABUTMENT ;
    PORT
      LAYER M5 ;
      RECT 925.332 129.408 925.356 129.600 ;
    END
  END d[222]
  PIN d[223]
    DIRECTION INPUT ;
    USE SIGNAL ;
    SHAPE ABUTMENT ;
    PORT
      LAYER M5 ;
      RECT 929.412 129.408 929.436 129.600 ;
    END
  END d[223]
  PIN d[224]
    DIRECTION INPUT ;
    USE SIGNAL ;
    SHAPE ABUTMENT ;
    PORT
      LAYER M5 ;
      RECT 933.492 129.408 933.516 129.600 ;
    END
  END d[224]
  PIN d[225]
    DIRECTION INPUT ;
    USE SIGNAL ;
    SHAPE ABUTMENT ;
    PORT
      LAYER M5 ;
      RECT 937.572 129.408 937.596 129.600 ;
    END
  END d[225]
  PIN d[226]
    DIRECTION INPUT ;
    USE SIGNAL ;
    SHAPE ABUTMENT ;
    PORT
      LAYER M5 ;
      RECT 941.652 129.408 941.676 129.600 ;
    END
  END d[226]
  PIN d[227]
    DIRECTION INPUT ;
    USE SIGNAL ;
    SHAPE ABUTMENT ;
    PORT
      LAYER M5 ;
      RECT 945.732 129.408 945.756 129.600 ;
    END
  END d[227]
  PIN d[228]
    DIRECTION INPUT ;
    USE SIGNAL ;
    SHAPE ABUTMENT ;
    PORT
      LAYER M5 ;
      RECT 949.812 129.408 949.836 129.600 ;
    END
  END d[228]
  PIN d[229]
    DIRECTION INPUT ;
    USE SIGNAL ;
    SHAPE ABUTMENT ;
    PORT
      LAYER M5 ;
      RECT 953.892 129.408 953.916 129.600 ;
    END
  END d[229]
  PIN d[230]
    DIRECTION INPUT ;
    USE SIGNAL ;
    SHAPE ABUTMENT ;
    PORT
      LAYER M5 ;
      RECT 957.972 129.408 957.996 129.600 ;
    END
  END d[230]
  PIN d[231]
    DIRECTION INPUT ;
    USE SIGNAL ;
    SHAPE ABUTMENT ;
    PORT
      LAYER M5 ;
      RECT 962.052 129.408 962.076 129.600 ;
    END
  END d[231]
  PIN d[232]
    DIRECTION INPUT ;
    USE SIGNAL ;
    SHAPE ABUTMENT ;
    PORT
      LAYER M5 ;
      RECT 966.132 129.408 966.156 129.600 ;
    END
  END d[232]
  PIN d[233]
    DIRECTION INPUT ;
    USE SIGNAL ;
    SHAPE ABUTMENT ;
    PORT
      LAYER M5 ;
      RECT 970.212 129.408 970.236 129.600 ;
    END
  END d[233]
  PIN d[234]
    DIRECTION INPUT ;
    USE SIGNAL ;
    SHAPE ABUTMENT ;
    PORT
      LAYER M5 ;
      RECT 974.292 129.408 974.316 129.600 ;
    END
  END d[234]
  PIN d[235]
    DIRECTION INPUT ;
    USE SIGNAL ;
    SHAPE ABUTMENT ;
    PORT
      LAYER M5 ;
      RECT 978.372 129.408 978.396 129.600 ;
    END
  END d[235]
  PIN d[236]
    DIRECTION INPUT ;
    USE SIGNAL ;
    SHAPE ABUTMENT ;
    PORT
      LAYER M5 ;
      RECT 982.452 129.408 982.476 129.600 ;
    END
  END d[236]
  PIN d[237]
    DIRECTION INPUT ;
    USE SIGNAL ;
    SHAPE ABUTMENT ;
    PORT
      LAYER M5 ;
      RECT 986.532 129.408 986.556 129.600 ;
    END
  END d[237]
  PIN d[238]
    DIRECTION INPUT ;
    USE SIGNAL ;
    SHAPE ABUTMENT ;
    PORT
      LAYER M5 ;
      RECT 990.612 129.408 990.636 129.600 ;
    END
  END d[238]
  PIN d[239]
    DIRECTION INPUT ;
    USE SIGNAL ;
    SHAPE ABUTMENT ;
    PORT
      LAYER M5 ;
      RECT 994.692 129.408 994.716 129.600 ;
    END
  END d[239]
  PIN d[240]
    DIRECTION INPUT ;
    USE SIGNAL ;
    SHAPE ABUTMENT ;
    PORT
      LAYER M5 ;
      RECT 998.772 129.408 998.796 129.600 ;
    END
  END d[240]
  PIN d[241]
    DIRECTION INPUT ;
    USE SIGNAL ;
    SHAPE ABUTMENT ;
    PORT
      LAYER M5 ;
      RECT 1002.852 129.408 1002.876 129.600 ;
    END
  END d[241]
  PIN d[242]
    DIRECTION INPUT ;
    USE SIGNAL ;
    SHAPE ABUTMENT ;
    PORT
      LAYER M5 ;
      RECT 1006.932 129.408 1006.956 129.600 ;
    END
  END d[242]
  PIN d[243]
    DIRECTION INPUT ;
    USE SIGNAL ;
    SHAPE ABUTMENT ;
    PORT
      LAYER M5 ;
      RECT 1011.012 129.408 1011.036 129.600 ;
    END
  END d[243]
  PIN d[244]
    DIRECTION INPUT ;
    USE SIGNAL ;
    SHAPE ABUTMENT ;
    PORT
      LAYER M5 ;
      RECT 1015.092 129.408 1015.116 129.600 ;
    END
  END d[244]
  PIN d[245]
    DIRECTION INPUT ;
    USE SIGNAL ;
    SHAPE ABUTMENT ;
    PORT
      LAYER M5 ;
      RECT 1019.172 129.408 1019.196 129.600 ;
    END
  END d[245]
  PIN d[246]
    DIRECTION INPUT ;
    USE SIGNAL ;
    SHAPE ABUTMENT ;
    PORT
      LAYER M5 ;
      RECT 1023.252 129.408 1023.276 129.600 ;
    END
  END d[246]
  PIN d[247]
    DIRECTION INPUT ;
    USE SIGNAL ;
    SHAPE ABUTMENT ;
    PORT
      LAYER M5 ;
      RECT 1027.332 129.408 1027.356 129.600 ;
    END
  END d[247]
  PIN d[248]
    DIRECTION INPUT ;
    USE SIGNAL ;
    SHAPE ABUTMENT ;
    PORT
      LAYER M5 ;
      RECT 1031.412 129.408 1031.436 129.600 ;
    END
  END d[248]
  PIN d[249]
    DIRECTION INPUT ;
    USE SIGNAL ;
    SHAPE ABUTMENT ;
    PORT
      LAYER M5 ;
      RECT 1035.492 129.408 1035.516 129.600 ;
    END
  END d[249]
  PIN d[250]
    DIRECTION INPUT ;
    USE SIGNAL ;
    SHAPE ABUTMENT ;
    PORT
      LAYER M5 ;
      RECT 1039.572 129.408 1039.596 129.600 ;
    END
  END d[250]
  PIN d[251]
    DIRECTION INPUT ;
    USE SIGNAL ;
    SHAPE ABUTMENT ;
    PORT
      LAYER M5 ;
      RECT 1043.652 129.408 1043.676 129.600 ;
    END
  END d[251]
  PIN d[252]
    DIRECTION INPUT ;
    USE SIGNAL ;
    SHAPE ABUTMENT ;
    PORT
      LAYER M5 ;
      RECT 1047.732 129.408 1047.756 129.600 ;
    END
  END d[252]
  PIN d[253]
    DIRECTION INPUT ;
    USE SIGNAL ;
    SHAPE ABUTMENT ;
    PORT
      LAYER M5 ;
      RECT 1051.812 129.408 1051.836 129.600 ;
    END
  END d[253]
  PIN d[254]
    DIRECTION INPUT ;
    USE SIGNAL ;
    SHAPE ABUTMENT ;
    PORT
      LAYER M5 ;
      RECT 1055.892 129.408 1055.916 129.600 ;
    END
  END d[254]
  PIN d[255]
    DIRECTION INPUT ;
    USE SIGNAL ;
    SHAPE ABUTMENT ;
    PORT
      LAYER M5 ;
      RECT 1059.972 129.408 1059.996 129.600 ;
    END
  END d[255]
  PIN d[256]
    DIRECTION INPUT ;
    USE SIGNAL ;
    SHAPE ABUTMENT ;
    PORT
      LAYER M5 ;
      RECT 1064.052 129.408 1064.076 129.600 ;
    END
  END d[256]
  PIN d[257]
    DIRECTION INPUT ;
    USE SIGNAL ;
    SHAPE ABUTMENT ;
    PORT
      LAYER M5 ;
      RECT 1068.132 129.408 1068.156 129.600 ;
    END
  END d[257]
  PIN d[258]
    DIRECTION INPUT ;
    USE SIGNAL ;
    SHAPE ABUTMENT ;
    PORT
      LAYER M5 ;
      RECT 1072.212 129.408 1072.236 129.600 ;
    END
  END d[258]
  PIN d[259]
    DIRECTION INPUT ;
    USE SIGNAL ;
    SHAPE ABUTMENT ;
    PORT
      LAYER M5 ;
      RECT 1076.292 129.408 1076.316 129.600 ;
    END
  END d[259]
  PIN d[260]
    DIRECTION INPUT ;
    USE SIGNAL ;
    SHAPE ABUTMENT ;
    PORT
      LAYER M5 ;
      RECT 1080.372 129.408 1080.396 129.600 ;
    END
  END d[260]
  PIN d[261]
    DIRECTION INPUT ;
    USE SIGNAL ;
    SHAPE ABUTMENT ;
    PORT
      LAYER M5 ;
      RECT 1084.452 129.408 1084.476 129.600 ;
    END
  END d[261]
  PIN d[262]
    DIRECTION INPUT ;
    USE SIGNAL ;
    SHAPE ABUTMENT ;
    PORT
      LAYER M5 ;
      RECT 1088.532 129.408 1088.556 129.600 ;
    END
  END d[262]
  PIN d[263]
    DIRECTION INPUT ;
    USE SIGNAL ;
    SHAPE ABUTMENT ;
    PORT
      LAYER M5 ;
      RECT 1092.612 129.408 1092.636 129.600 ;
    END
  END d[263]
  PIN d[264]
    DIRECTION INPUT ;
    USE SIGNAL ;
    SHAPE ABUTMENT ;
    PORT
      LAYER M5 ;
      RECT 1096.692 129.408 1096.716 129.600 ;
    END
  END d[264]
  PIN d[265]
    DIRECTION INPUT ;
    USE SIGNAL ;
    SHAPE ABUTMENT ;
    PORT
      LAYER M5 ;
      RECT 1100.772 129.408 1100.796 129.600 ;
    END
  END d[265]
  PIN d[266]
    DIRECTION INPUT ;
    USE SIGNAL ;
    SHAPE ABUTMENT ;
    PORT
      LAYER M5 ;
      RECT 1104.852 129.408 1104.876 129.600 ;
    END
  END d[266]
  PIN d[267]
    DIRECTION INPUT ;
    USE SIGNAL ;
    SHAPE ABUTMENT ;
    PORT
      LAYER M5 ;
      RECT 1108.932 129.408 1108.956 129.600 ;
    END
  END d[267]
  PIN d[268]
    DIRECTION INPUT ;
    USE SIGNAL ;
    SHAPE ABUTMENT ;
    PORT
      LAYER M5 ;
      RECT 1113.012 129.408 1113.036 129.600 ;
    END
  END d[268]
  PIN d[269]
    DIRECTION INPUT ;
    USE SIGNAL ;
    SHAPE ABUTMENT ;
    PORT
      LAYER M5 ;
      RECT 1117.092 129.408 1117.116 129.600 ;
    END
  END d[269]
  PIN d[270]
    DIRECTION INPUT ;
    USE SIGNAL ;
    SHAPE ABUTMENT ;
    PORT
      LAYER M5 ;
      RECT 1121.172 129.408 1121.196 129.600 ;
    END
  END d[270]
  PIN d[271]
    DIRECTION INPUT ;
    USE SIGNAL ;
    SHAPE ABUTMENT ;
    PORT
      LAYER M5 ;
      RECT 1125.252 129.408 1125.276 129.600 ;
    END
  END d[271]
  PIN d[272]
    DIRECTION INPUT ;
    USE SIGNAL ;
    SHAPE ABUTMENT ;
    PORT
      LAYER M5 ;
      RECT 1129.332 129.408 1129.356 129.600 ;
    END
  END d[272]
  PIN d[273]
    DIRECTION INPUT ;
    USE SIGNAL ;
    SHAPE ABUTMENT ;
    PORT
      LAYER M5 ;
      RECT 1133.412 129.408 1133.436 129.600 ;
    END
  END d[273]
  PIN d[274]
    DIRECTION INPUT ;
    USE SIGNAL ;
    SHAPE ABUTMENT ;
    PORT
      LAYER M5 ;
      RECT 1137.492 129.408 1137.516 129.600 ;
    END
  END d[274]
  PIN d[275]
    DIRECTION INPUT ;
    USE SIGNAL ;
    SHAPE ABUTMENT ;
    PORT
      LAYER M5 ;
      RECT 1141.572 129.408 1141.596 129.600 ;
    END
  END d[275]
  PIN d[276]
    DIRECTION INPUT ;
    USE SIGNAL ;
    SHAPE ABUTMENT ;
    PORT
      LAYER M5 ;
      RECT 1145.652 129.408 1145.676 129.600 ;
    END
  END d[276]
  PIN d[277]
    DIRECTION INPUT ;
    USE SIGNAL ;
    SHAPE ABUTMENT ;
    PORT
      LAYER M5 ;
      RECT 1149.732 129.408 1149.756 129.600 ;
    END
  END d[277]
  PIN d[278]
    DIRECTION INPUT ;
    USE SIGNAL ;
    SHAPE ABUTMENT ;
    PORT
      LAYER M5 ;
      RECT 1153.812 129.408 1153.836 129.600 ;
    END
  END d[278]
  PIN d[279]
    DIRECTION INPUT ;
    USE SIGNAL ;
    SHAPE ABUTMENT ;
    PORT
      LAYER M5 ;
      RECT 1157.892 129.408 1157.916 129.600 ;
    END
  END d[279]
  PIN d[280]
    DIRECTION INPUT ;
    USE SIGNAL ;
    SHAPE ABUTMENT ;
    PORT
      LAYER M5 ;
      RECT 1161.972 129.408 1161.996 129.600 ;
    END
  END d[280]
  PIN d[281]
    DIRECTION INPUT ;
    USE SIGNAL ;
    SHAPE ABUTMENT ;
    PORT
      LAYER M5 ;
      RECT 1166.052 129.408 1166.076 129.600 ;
    END
  END d[281]
  PIN d[282]
    DIRECTION INPUT ;
    USE SIGNAL ;
    SHAPE ABUTMENT ;
    PORT
      LAYER M5 ;
      RECT 1170.132 129.408 1170.156 129.600 ;
    END
  END d[282]
  PIN d[283]
    DIRECTION INPUT ;
    USE SIGNAL ;
    SHAPE ABUTMENT ;
    PORT
      LAYER M5 ;
      RECT 1174.212 129.408 1174.236 129.600 ;
    END
  END d[283]
  PIN d[284]
    DIRECTION INPUT ;
    USE SIGNAL ;
    SHAPE ABUTMENT ;
    PORT
      LAYER M5 ;
      RECT 1178.292 129.408 1178.316 129.600 ;
    END
  END d[284]
  PIN d[285]
    DIRECTION INPUT ;
    USE SIGNAL ;
    SHAPE ABUTMENT ;
    PORT
      LAYER M5 ;
      RECT 1182.372 129.408 1182.396 129.600 ;
    END
  END d[285]
  PIN d[286]
    DIRECTION INPUT ;
    USE SIGNAL ;
    SHAPE ABUTMENT ;
    PORT
      LAYER M5 ;
      RECT 1186.452 129.408 1186.476 129.600 ;
    END
  END d[286]
  PIN d[287]
    DIRECTION INPUT ;
    USE SIGNAL ;
    SHAPE ABUTMENT ;
    PORT
      LAYER M5 ;
      RECT 1190.532 129.408 1190.556 129.600 ;
    END
  END d[287]
  PIN d[288]
    DIRECTION INPUT ;
    USE SIGNAL ;
    SHAPE ABUTMENT ;
    PORT
      LAYER M5 ;
      RECT 1194.612 129.408 1194.636 129.600 ;
    END
  END d[288]
  PIN d[289]
    DIRECTION INPUT ;
    USE SIGNAL ;
    SHAPE ABUTMENT ;
    PORT
      LAYER M5 ;
      RECT 1198.692 129.408 1198.716 129.600 ;
    END
  END d[289]
  PIN d[290]
    DIRECTION INPUT ;
    USE SIGNAL ;
    SHAPE ABUTMENT ;
    PORT
      LAYER M5 ;
      RECT 1202.772 129.408 1202.796 129.600 ;
    END
  END d[290]
  PIN d[291]
    DIRECTION INPUT ;
    USE SIGNAL ;
    SHAPE ABUTMENT ;
    PORT
      LAYER M5 ;
      RECT 1206.852 129.408 1206.876 129.600 ;
    END
  END d[291]
  PIN d[292]
    DIRECTION INPUT ;
    USE SIGNAL ;
    SHAPE ABUTMENT ;
    PORT
      LAYER M5 ;
      RECT 1210.932 129.408 1210.956 129.600 ;
    END
  END d[292]
  PIN d[293]
    DIRECTION INPUT ;
    USE SIGNAL ;
    SHAPE ABUTMENT ;
    PORT
      LAYER M5 ;
      RECT 1215.012 129.408 1215.036 129.600 ;
    END
  END d[293]
  PIN d[294]
    DIRECTION INPUT ;
    USE SIGNAL ;
    SHAPE ABUTMENT ;
    PORT
      LAYER M5 ;
      RECT 1219.092 129.408 1219.116 129.600 ;
    END
  END d[294]
  PIN d[295]
    DIRECTION INPUT ;
    USE SIGNAL ;
    SHAPE ABUTMENT ;
    PORT
      LAYER M5 ;
      RECT 1223.172 129.408 1223.196 129.600 ;
    END
  END d[295]
  PIN d[296]
    DIRECTION INPUT ;
    USE SIGNAL ;
    SHAPE ABUTMENT ;
    PORT
      LAYER M5 ;
      RECT 1227.252 129.408 1227.276 129.600 ;
    END
  END d[296]
  PIN d[297]
    DIRECTION INPUT ;
    USE SIGNAL ;
    SHAPE ABUTMENT ;
    PORT
      LAYER M5 ;
      RECT 1231.332 129.408 1231.356 129.600 ;
    END
  END d[297]
  PIN d[298]
    DIRECTION INPUT ;
    USE SIGNAL ;
    SHAPE ABUTMENT ;
    PORT
      LAYER M5 ;
      RECT 1235.412 129.408 1235.436 129.600 ;
    END
  END d[298]
  PIN d[299]
    DIRECTION INPUT ;
    USE SIGNAL ;
    SHAPE ABUTMENT ;
    PORT
      LAYER M5 ;
      RECT 1239.492 129.408 1239.516 129.600 ;
    END
  END d[299]
  PIN d[300]
    DIRECTION INPUT ;
    USE SIGNAL ;
    SHAPE ABUTMENT ;
    PORT
      LAYER M5 ;
      RECT 1243.572 129.408 1243.596 129.600 ;
    END
  END d[300]
  PIN d[301]
    DIRECTION INPUT ;
    USE SIGNAL ;
    SHAPE ABUTMENT ;
    PORT
      LAYER M5 ;
      RECT 1247.652 129.408 1247.676 129.600 ;
    END
  END d[301]
  PIN d[302]
    DIRECTION INPUT ;
    USE SIGNAL ;
    SHAPE ABUTMENT ;
    PORT
      LAYER M5 ;
      RECT 1251.732 129.408 1251.756 129.600 ;
    END
  END d[302]
  PIN d[303]
    DIRECTION INPUT ;
    USE SIGNAL ;
    SHAPE ABUTMENT ;
    PORT
      LAYER M5 ;
      RECT 1255.812 129.408 1255.836 129.600 ;
    END
  END d[303]
  PIN d[304]
    DIRECTION INPUT ;
    USE SIGNAL ;
    SHAPE ABUTMENT ;
    PORT
      LAYER M5 ;
      RECT 1259.892 129.408 1259.916 129.600 ;
    END
  END d[304]
  PIN d[305]
    DIRECTION INPUT ;
    USE SIGNAL ;
    SHAPE ABUTMENT ;
    PORT
      LAYER M5 ;
      RECT 1263.972 129.408 1263.996 129.600 ;
    END
  END d[305]
  PIN d[306]
    DIRECTION INPUT ;
    USE SIGNAL ;
    SHAPE ABUTMENT ;
    PORT
      LAYER M5 ;
      RECT 1268.052 129.408 1268.076 129.600 ;
    END
  END d[306]
  PIN d[307]
    DIRECTION INPUT ;
    USE SIGNAL ;
    SHAPE ABUTMENT ;
    PORT
      LAYER M5 ;
      RECT 1272.132 129.408 1272.156 129.600 ;
    END
  END d[307]
  PIN d[308]
    DIRECTION INPUT ;
    USE SIGNAL ;
    SHAPE ABUTMENT ;
    PORT
      LAYER M5 ;
      RECT 1276.212 129.408 1276.236 129.600 ;
    END
  END d[308]
  PIN d[309]
    DIRECTION INPUT ;
    USE SIGNAL ;
    SHAPE ABUTMENT ;
    PORT
      LAYER M5 ;
      RECT 1280.292 129.408 1280.316 129.600 ;
    END
  END d[309]
  PIN d[310]
    DIRECTION INPUT ;
    USE SIGNAL ;
    SHAPE ABUTMENT ;
    PORT
      LAYER M5 ;
      RECT 1284.372 129.408 1284.396 129.600 ;
    END
  END d[310]
  PIN d[311]
    DIRECTION INPUT ;
    USE SIGNAL ;
    SHAPE ABUTMENT ;
    PORT
      LAYER M5 ;
      RECT 1288.452 129.408 1288.476 129.600 ;
    END
  END d[311]
  PIN d[312]
    DIRECTION INPUT ;
    USE SIGNAL ;
    SHAPE ABUTMENT ;
    PORT
      LAYER M5 ;
      RECT 1292.532 129.408 1292.556 129.600 ;
    END
  END d[312]
  PIN d[313]
    DIRECTION INPUT ;
    USE SIGNAL ;
    SHAPE ABUTMENT ;
    PORT
      LAYER M5 ;
      RECT 1296.612 129.408 1296.636 129.600 ;
    END
  END d[313]
  PIN d[314]
    DIRECTION INPUT ;
    USE SIGNAL ;
    SHAPE ABUTMENT ;
    PORT
      LAYER M5 ;
      RECT 1300.692 129.408 1300.716 129.600 ;
    END
  END d[314]
  PIN d[315]
    DIRECTION INPUT ;
    USE SIGNAL ;
    SHAPE ABUTMENT ;
    PORT
      LAYER M5 ;
      RECT 1304.772 129.408 1304.796 129.600 ;
    END
  END d[315]
  PIN d[316]
    DIRECTION INPUT ;
    USE SIGNAL ;
    SHAPE ABUTMENT ;
    PORT
      LAYER M5 ;
      RECT 1308.852 129.408 1308.876 129.600 ;
    END
  END d[316]
  PIN d[317]
    DIRECTION INPUT ;
    USE SIGNAL ;
    SHAPE ABUTMENT ;
    PORT
      LAYER M5 ;
      RECT 1312.932 129.408 1312.956 129.600 ;
    END
  END d[317]
  PIN d[318]
    DIRECTION INPUT ;
    USE SIGNAL ;
    SHAPE ABUTMENT ;
    PORT
      LAYER M5 ;
      RECT 1317.012 129.408 1317.036 129.600 ;
    END
  END d[318]
  PIN d[319]
    DIRECTION INPUT ;
    USE SIGNAL ;
    SHAPE ABUTMENT ;
    PORT
      LAYER M5 ;
      RECT 1321.092 129.408 1321.116 129.600 ;
    END
  END d[319]
  PIN d[320]
    DIRECTION INPUT ;
    USE SIGNAL ;
    SHAPE ABUTMENT ;
    PORT
      LAYER M5 ;
      RECT 1325.172 129.408 1325.196 129.600 ;
    END
  END d[320]
  PIN d[321]
    DIRECTION INPUT ;
    USE SIGNAL ;
    SHAPE ABUTMENT ;
    PORT
      LAYER M5 ;
      RECT 1329.252 129.408 1329.276 129.600 ;
    END
  END d[321]
  PIN d[322]
    DIRECTION INPUT ;
    USE SIGNAL ;
    SHAPE ABUTMENT ;
    PORT
      LAYER M5 ;
      RECT 1333.332 129.408 1333.356 129.600 ;
    END
  END d[322]
  PIN d[323]
    DIRECTION INPUT ;
    USE SIGNAL ;
    SHAPE ABUTMENT ;
    PORT
      LAYER M5 ;
      RECT 1337.412 129.408 1337.436 129.600 ;
    END
  END d[323]
  PIN d[324]
    DIRECTION INPUT ;
    USE SIGNAL ;
    SHAPE ABUTMENT ;
    PORT
      LAYER M5 ;
      RECT 1341.492 129.408 1341.516 129.600 ;
    END
  END d[324]
  PIN d[325]
    DIRECTION INPUT ;
    USE SIGNAL ;
    SHAPE ABUTMENT ;
    PORT
      LAYER M5 ;
      RECT 1345.572 129.408 1345.596 129.600 ;
    END
  END d[325]
  PIN d[326]
    DIRECTION INPUT ;
    USE SIGNAL ;
    SHAPE ABUTMENT ;
    PORT
      LAYER M5 ;
      RECT 1349.652 129.408 1349.676 129.600 ;
    END
  END d[326]
  PIN d[327]
    DIRECTION INPUT ;
    USE SIGNAL ;
    SHAPE ABUTMENT ;
    PORT
      LAYER M5 ;
      RECT 1353.732 129.408 1353.756 129.600 ;
    END
  END d[327]
  PIN d[328]
    DIRECTION INPUT ;
    USE SIGNAL ;
    SHAPE ABUTMENT ;
    PORT
      LAYER M5 ;
      RECT 1357.812 129.408 1357.836 129.600 ;
    END
  END d[328]
  PIN d[329]
    DIRECTION INPUT ;
    USE SIGNAL ;
    SHAPE ABUTMENT ;
    PORT
      LAYER M5 ;
      RECT 1361.892 129.408 1361.916 129.600 ;
    END
  END d[329]
  PIN d[330]
    DIRECTION INPUT ;
    USE SIGNAL ;
    SHAPE ABUTMENT ;
    PORT
      LAYER M5 ;
      RECT 1365.972 129.408 1365.996 129.600 ;
    END
  END d[330]
  PIN d[331]
    DIRECTION INPUT ;
    USE SIGNAL ;
    SHAPE ABUTMENT ;
    PORT
      LAYER M5 ;
      RECT 1370.052 129.408 1370.076 129.600 ;
    END
  END d[331]
  PIN d[332]
    DIRECTION INPUT ;
    USE SIGNAL ;
    SHAPE ABUTMENT ;
    PORT
      LAYER M5 ;
      RECT 1374.132 129.408 1374.156 129.600 ;
    END
  END d[332]
  PIN d[333]
    DIRECTION INPUT ;
    USE SIGNAL ;
    SHAPE ABUTMENT ;
    PORT
      LAYER M5 ;
      RECT 1378.212 129.408 1378.236 129.600 ;
    END
  END d[333]
  PIN d[334]
    DIRECTION INPUT ;
    USE SIGNAL ;
    SHAPE ABUTMENT ;
    PORT
      LAYER M5 ;
      RECT 1382.292 129.408 1382.316 129.600 ;
    END
  END d[334]
  PIN d[335]
    DIRECTION INPUT ;
    USE SIGNAL ;
    SHAPE ABUTMENT ;
    PORT
      LAYER M5 ;
      RECT 1386.372 129.408 1386.396 129.600 ;
    END
  END d[335]
  PIN d[336]
    DIRECTION INPUT ;
    USE SIGNAL ;
    SHAPE ABUTMENT ;
    PORT
      LAYER M5 ;
      RECT 1390.452 129.408 1390.476 129.600 ;
    END
  END d[336]
  PIN d[337]
    DIRECTION INPUT ;
    USE SIGNAL ;
    SHAPE ABUTMENT ;
    PORT
      LAYER M5 ;
      RECT 1394.532 129.408 1394.556 129.600 ;
    END
  END d[337]
  PIN d[338]
    DIRECTION INPUT ;
    USE SIGNAL ;
    SHAPE ABUTMENT ;
    PORT
      LAYER M5 ;
      RECT 1398.612 129.408 1398.636 129.600 ;
    END
  END d[338]
  PIN d[339]
    DIRECTION INPUT ;
    USE SIGNAL ;
    SHAPE ABUTMENT ;
    PORT
      LAYER M5 ;
      RECT 1402.692 129.408 1402.716 129.600 ;
    END
  END d[339]
  PIN d[340]
    DIRECTION INPUT ;
    USE SIGNAL ;
    SHAPE ABUTMENT ;
    PORT
      LAYER M5 ;
      RECT 1406.772 129.408 1406.796 129.600 ;
    END
  END d[340]
  PIN d[341]
    DIRECTION INPUT ;
    USE SIGNAL ;
    SHAPE ABUTMENT ;
    PORT
      LAYER M5 ;
      RECT 1410.852 129.408 1410.876 129.600 ;
    END
  END d[341]
  PIN d[342]
    DIRECTION INPUT ;
    USE SIGNAL ;
    SHAPE ABUTMENT ;
    PORT
      LAYER M5 ;
      RECT 1414.932 129.408 1414.956 129.600 ;
    END
  END d[342]
  PIN d[343]
    DIRECTION INPUT ;
    USE SIGNAL ;
    SHAPE ABUTMENT ;
    PORT
      LAYER M5 ;
      RECT 1419.012 129.408 1419.036 129.600 ;
    END
  END d[343]
  PIN d[344]
    DIRECTION INPUT ;
    USE SIGNAL ;
    SHAPE ABUTMENT ;
    PORT
      LAYER M5 ;
      RECT 1423.092 129.408 1423.116 129.600 ;
    END
  END d[344]
  PIN d[345]
    DIRECTION INPUT ;
    USE SIGNAL ;
    SHAPE ABUTMENT ;
    PORT
      LAYER M5 ;
      RECT 1427.172 129.408 1427.196 129.600 ;
    END
  END d[345]
  PIN d[346]
    DIRECTION INPUT ;
    USE SIGNAL ;
    SHAPE ABUTMENT ;
    PORT
      LAYER M5 ;
      RECT 1431.252 129.408 1431.276 129.600 ;
    END
  END d[346]
  PIN d[347]
    DIRECTION INPUT ;
    USE SIGNAL ;
    SHAPE ABUTMENT ;
    PORT
      LAYER M5 ;
      RECT 1435.332 129.408 1435.356 129.600 ;
    END
  END d[347]
  PIN d[348]
    DIRECTION INPUT ;
    USE SIGNAL ;
    SHAPE ABUTMENT ;
    PORT
      LAYER M5 ;
      RECT 1439.412 129.408 1439.436 129.600 ;
    END
  END d[348]
  PIN d[349]
    DIRECTION INPUT ;
    USE SIGNAL ;
    SHAPE ABUTMENT ;
    PORT
      LAYER M5 ;
      RECT 1443.492 129.408 1443.516 129.600 ;
    END
  END d[349]
  PIN d[350]
    DIRECTION INPUT ;
    USE SIGNAL ;
    SHAPE ABUTMENT ;
    PORT
      LAYER M5 ;
      RECT 1447.572 129.408 1447.596 129.600 ;
    END
  END d[350]
  PIN d[351]
    DIRECTION INPUT ;
    USE SIGNAL ;
    SHAPE ABUTMENT ;
    PORT
      LAYER M5 ;
      RECT 1451.652 129.408 1451.676 129.600 ;
    END
  END d[351]
  PIN d[352]
    DIRECTION INPUT ;
    USE SIGNAL ;
    SHAPE ABUTMENT ;
    PORT
      LAYER M5 ;
      RECT 1455.732 129.408 1455.756 129.600 ;
    END
  END d[352]
  PIN d[353]
    DIRECTION INPUT ;
    USE SIGNAL ;
    SHAPE ABUTMENT ;
    PORT
      LAYER M5 ;
      RECT 1459.812 129.408 1459.836 129.600 ;
    END
  END d[353]
  PIN d[354]
    DIRECTION INPUT ;
    USE SIGNAL ;
    SHAPE ABUTMENT ;
    PORT
      LAYER M5 ;
      RECT 1463.892 129.408 1463.916 129.600 ;
    END
  END d[354]
  PIN d[355]
    DIRECTION INPUT ;
    USE SIGNAL ;
    SHAPE ABUTMENT ;
    PORT
      LAYER M5 ;
      RECT 1467.972 129.408 1467.996 129.600 ;
    END
  END d[355]
  PIN d[356]
    DIRECTION INPUT ;
    USE SIGNAL ;
    SHAPE ABUTMENT ;
    PORT
      LAYER M5 ;
      RECT 1472.052 129.408 1472.076 129.600 ;
    END
  END d[356]
  PIN d[357]
    DIRECTION INPUT ;
    USE SIGNAL ;
    SHAPE ABUTMENT ;
    PORT
      LAYER M5 ;
      RECT 1476.132 129.408 1476.156 129.600 ;
    END
  END d[357]
  PIN d[358]
    DIRECTION INPUT ;
    USE SIGNAL ;
    SHAPE ABUTMENT ;
    PORT
      LAYER M5 ;
      RECT 1480.212 129.408 1480.236 129.600 ;
    END
  END d[358]
  PIN d[359]
    DIRECTION INPUT ;
    USE SIGNAL ;
    SHAPE ABUTMENT ;
    PORT
      LAYER M5 ;
      RECT 1484.292 129.408 1484.316 129.600 ;
    END
  END d[359]
  PIN d[360]
    DIRECTION INPUT ;
    USE SIGNAL ;
    SHAPE ABUTMENT ;
    PORT
      LAYER M5 ;
      RECT 1488.372 129.408 1488.396 129.600 ;
    END
  END d[360]
  PIN d[361]
    DIRECTION INPUT ;
    USE SIGNAL ;
    SHAPE ABUTMENT ;
    PORT
      LAYER M5 ;
      RECT 1492.452 129.408 1492.476 129.600 ;
    END
  END d[361]
  PIN d[362]
    DIRECTION INPUT ;
    USE SIGNAL ;
    SHAPE ABUTMENT ;
    PORT
      LAYER M5 ;
      RECT 1496.532 129.408 1496.556 129.600 ;
    END
  END d[362]
  PIN d[363]
    DIRECTION INPUT ;
    USE SIGNAL ;
    SHAPE ABUTMENT ;
    PORT
      LAYER M5 ;
      RECT 1500.612 129.408 1500.636 129.600 ;
    END
  END d[363]
  PIN d[364]
    DIRECTION INPUT ;
    USE SIGNAL ;
    SHAPE ABUTMENT ;
    PORT
      LAYER M5 ;
      RECT 1504.692 129.408 1504.716 129.600 ;
    END
  END d[364]
  PIN d[365]
    DIRECTION INPUT ;
    USE SIGNAL ;
    SHAPE ABUTMENT ;
    PORT
      LAYER M5 ;
      RECT 1508.772 129.408 1508.796 129.600 ;
    END
  END d[365]
  PIN d[366]
    DIRECTION INPUT ;
    USE SIGNAL ;
    SHAPE ABUTMENT ;
    PORT
      LAYER M5 ;
      RECT 1512.852 129.408 1512.876 129.600 ;
    END
  END d[366]
  PIN d[367]
    DIRECTION INPUT ;
    USE SIGNAL ;
    SHAPE ABUTMENT ;
    PORT
      LAYER M5 ;
      RECT 1516.932 129.408 1516.956 129.600 ;
    END
  END d[367]
  PIN d[368]
    DIRECTION INPUT ;
    USE SIGNAL ;
    SHAPE ABUTMENT ;
    PORT
      LAYER M5 ;
      RECT 1521.012 129.408 1521.036 129.600 ;
    END
  END d[368]
  PIN d[369]
    DIRECTION INPUT ;
    USE SIGNAL ;
    SHAPE ABUTMENT ;
    PORT
      LAYER M5 ;
      RECT 1525.092 129.408 1525.116 129.600 ;
    END
  END d[369]
  PIN d[370]
    DIRECTION INPUT ;
    USE SIGNAL ;
    SHAPE ABUTMENT ;
    PORT
      LAYER M5 ;
      RECT 1529.172 129.408 1529.196 129.600 ;
    END
  END d[370]
  PIN d[371]
    DIRECTION INPUT ;
    USE SIGNAL ;
    SHAPE ABUTMENT ;
    PORT
      LAYER M5 ;
      RECT 1533.252 129.408 1533.276 129.600 ;
    END
  END d[371]
  PIN d[372]
    DIRECTION INPUT ;
    USE SIGNAL ;
    SHAPE ABUTMENT ;
    PORT
      LAYER M5 ;
      RECT 1537.332 129.408 1537.356 129.600 ;
    END
  END d[372]
  PIN d[373]
    DIRECTION INPUT ;
    USE SIGNAL ;
    SHAPE ABUTMENT ;
    PORT
      LAYER M5 ;
      RECT 1541.412 129.408 1541.436 129.600 ;
    END
  END d[373]
  PIN d[374]
    DIRECTION INPUT ;
    USE SIGNAL ;
    SHAPE ABUTMENT ;
    PORT
      LAYER M5 ;
      RECT 1545.492 129.408 1545.516 129.600 ;
    END
  END d[374]
  PIN d[375]
    DIRECTION INPUT ;
    USE SIGNAL ;
    SHAPE ABUTMENT ;
    PORT
      LAYER M5 ;
      RECT 1549.572 129.408 1549.596 129.600 ;
    END
  END d[375]
  PIN d[376]
    DIRECTION INPUT ;
    USE SIGNAL ;
    SHAPE ABUTMENT ;
    PORT
      LAYER M5 ;
      RECT 1553.652 129.408 1553.676 129.600 ;
    END
  END d[376]
  PIN d[377]
    DIRECTION INPUT ;
    USE SIGNAL ;
    SHAPE ABUTMENT ;
    PORT
      LAYER M5 ;
      RECT 1557.732 129.408 1557.756 129.600 ;
    END
  END d[377]
  PIN d[378]
    DIRECTION INPUT ;
    USE SIGNAL ;
    SHAPE ABUTMENT ;
    PORT
      LAYER M5 ;
      RECT 1561.812 129.408 1561.836 129.600 ;
    END
  END d[378]
  PIN d[379]
    DIRECTION INPUT ;
    USE SIGNAL ;
    SHAPE ABUTMENT ;
    PORT
      LAYER M5 ;
      RECT 1565.892 129.408 1565.916 129.600 ;
    END
  END d[379]
  PIN d[380]
    DIRECTION INPUT ;
    USE SIGNAL ;
    SHAPE ABUTMENT ;
    PORT
      LAYER M5 ;
      RECT 1569.972 129.408 1569.996 129.600 ;
    END
  END d[380]
  PIN d[381]
    DIRECTION INPUT ;
    USE SIGNAL ;
    SHAPE ABUTMENT ;
    PORT
      LAYER M5 ;
      RECT 1574.052 129.408 1574.076 129.600 ;
    END
  END d[381]
  PIN d[382]
    DIRECTION INPUT ;
    USE SIGNAL ;
    SHAPE ABUTMENT ;
    PORT
      LAYER M5 ;
      RECT 1578.132 129.408 1578.156 129.600 ;
    END
  END d[382]
  PIN d[383]
    DIRECTION INPUT ;
    USE SIGNAL ;
    SHAPE ABUTMENT ;
    PORT
      LAYER M5 ;
      RECT 1582.212 129.408 1582.236 129.600 ;
    END
  END d[383]
  PIN d[384]
    DIRECTION INPUT ;
    USE SIGNAL ;
    SHAPE ABUTMENT ;
    PORT
      LAYER M5 ;
      RECT 1586.292 129.408 1586.316 129.600 ;
    END
  END d[384]
  PIN d[385]
    DIRECTION INPUT ;
    USE SIGNAL ;
    SHAPE ABUTMENT ;
    PORT
      LAYER M5 ;
      RECT 1590.372 129.408 1590.396 129.600 ;
    END
  END d[385]
  PIN d[386]
    DIRECTION INPUT ;
    USE SIGNAL ;
    SHAPE ABUTMENT ;
    PORT
      LAYER M5 ;
      RECT 1594.452 129.408 1594.476 129.600 ;
    END
  END d[386]
  PIN d[387]
    DIRECTION INPUT ;
    USE SIGNAL ;
    SHAPE ABUTMENT ;
    PORT
      LAYER M5 ;
      RECT 1598.532 129.408 1598.556 129.600 ;
    END
  END d[387]
  PIN d[388]
    DIRECTION INPUT ;
    USE SIGNAL ;
    SHAPE ABUTMENT ;
    PORT
      LAYER M5 ;
      RECT 1602.612 129.408 1602.636 129.600 ;
    END
  END d[388]
  PIN d[389]
    DIRECTION INPUT ;
    USE SIGNAL ;
    SHAPE ABUTMENT ;
    PORT
      LAYER M5 ;
      RECT 1606.692 129.408 1606.716 129.600 ;
    END
  END d[389]
  PIN d[390]
    DIRECTION INPUT ;
    USE SIGNAL ;
    SHAPE ABUTMENT ;
    PORT
      LAYER M5 ;
      RECT 1610.772 129.408 1610.796 129.600 ;
    END
  END d[390]
  PIN d[391]
    DIRECTION INPUT ;
    USE SIGNAL ;
    SHAPE ABUTMENT ;
    PORT
      LAYER M5 ;
      RECT 1614.852 129.408 1614.876 129.600 ;
    END
  END d[391]
  PIN d[392]
    DIRECTION INPUT ;
    USE SIGNAL ;
    SHAPE ABUTMENT ;
    PORT
      LAYER M5 ;
      RECT 1618.932 129.408 1618.956 129.600 ;
    END
  END d[392]
  PIN d[393]
    DIRECTION INPUT ;
    USE SIGNAL ;
    SHAPE ABUTMENT ;
    PORT
      LAYER M5 ;
      RECT 1623.012 129.408 1623.036 129.600 ;
    END
  END d[393]
  PIN d[394]
    DIRECTION INPUT ;
    USE SIGNAL ;
    SHAPE ABUTMENT ;
    PORT
      LAYER M5 ;
      RECT 1627.092 129.408 1627.116 129.600 ;
    END
  END d[394]
  PIN d[395]
    DIRECTION INPUT ;
    USE SIGNAL ;
    SHAPE ABUTMENT ;
    PORT
      LAYER M5 ;
      RECT 1631.172 129.408 1631.196 129.600 ;
    END
  END d[395]
  PIN d[396]
    DIRECTION INPUT ;
    USE SIGNAL ;
    SHAPE ABUTMENT ;
    PORT
      LAYER M5 ;
      RECT 1635.252 129.408 1635.276 129.600 ;
    END
  END d[396]
  PIN d[397]
    DIRECTION INPUT ;
    USE SIGNAL ;
    SHAPE ABUTMENT ;
    PORT
      LAYER M5 ;
      RECT 1639.332 129.408 1639.356 129.600 ;
    END
  END d[397]
  PIN d[398]
    DIRECTION INPUT ;
    USE SIGNAL ;
    SHAPE ABUTMENT ;
    PORT
      LAYER M5 ;
      RECT 1643.412 129.408 1643.436 129.600 ;
    END
  END d[398]
  PIN d[399]
    DIRECTION INPUT ;
    USE SIGNAL ;
    SHAPE ABUTMENT ;
    PORT
      LAYER M5 ;
      RECT 1647.492 129.408 1647.516 129.600 ;
    END
  END d[399]
  PIN d[400]
    DIRECTION INPUT ;
    USE SIGNAL ;
    SHAPE ABUTMENT ;
    PORT
      LAYER M5 ;
      RECT 1651.572 129.408 1651.596 129.600 ;
    END
  END d[400]
  PIN d[401]
    DIRECTION INPUT ;
    USE SIGNAL ;
    SHAPE ABUTMENT ;
    PORT
      LAYER M5 ;
      RECT 1655.652 129.408 1655.676 129.600 ;
    END
  END d[401]
  PIN d[402]
    DIRECTION INPUT ;
    USE SIGNAL ;
    SHAPE ABUTMENT ;
    PORT
      LAYER M5 ;
      RECT 1659.732 129.408 1659.756 129.600 ;
    END
  END d[402]
  PIN d[403]
    DIRECTION INPUT ;
    USE SIGNAL ;
    SHAPE ABUTMENT ;
    PORT
      LAYER M5 ;
      RECT 1663.812 129.408 1663.836 129.600 ;
    END
  END d[403]
  PIN d[404]
    DIRECTION INPUT ;
    USE SIGNAL ;
    SHAPE ABUTMENT ;
    PORT
      LAYER M5 ;
      RECT 1667.892 129.408 1667.916 129.600 ;
    END
  END d[404]
  PIN d[405]
    DIRECTION INPUT ;
    USE SIGNAL ;
    SHAPE ABUTMENT ;
    PORT
      LAYER M5 ;
      RECT 1671.972 129.408 1671.996 129.600 ;
    END
  END d[405]
  PIN d[406]
    DIRECTION INPUT ;
    USE SIGNAL ;
    SHAPE ABUTMENT ;
    PORT
      LAYER M5 ;
      RECT 1676.052 129.408 1676.076 129.600 ;
    END
  END d[406]
  PIN d[407]
    DIRECTION INPUT ;
    USE SIGNAL ;
    SHAPE ABUTMENT ;
    PORT
      LAYER M5 ;
      RECT 1680.132 129.408 1680.156 129.600 ;
    END
  END d[407]
  PIN d[408]
    DIRECTION INPUT ;
    USE SIGNAL ;
    SHAPE ABUTMENT ;
    PORT
      LAYER M5 ;
      RECT 1684.212 129.408 1684.236 129.600 ;
    END
  END d[408]
  PIN d[409]
    DIRECTION INPUT ;
    USE SIGNAL ;
    SHAPE ABUTMENT ;
    PORT
      LAYER M5 ;
      RECT 1688.292 129.408 1688.316 129.600 ;
    END
  END d[409]
  PIN d[410]
    DIRECTION INPUT ;
    USE SIGNAL ;
    SHAPE ABUTMENT ;
    PORT
      LAYER M5 ;
      RECT 1692.372 129.408 1692.396 129.600 ;
    END
  END d[410]
  PIN d[411]
    DIRECTION INPUT ;
    USE SIGNAL ;
    SHAPE ABUTMENT ;
    PORT
      LAYER M5 ;
      RECT 1696.452 129.408 1696.476 129.600 ;
    END
  END d[411]
  PIN d[412]
    DIRECTION INPUT ;
    USE SIGNAL ;
    SHAPE ABUTMENT ;
    PORT
      LAYER M5 ;
      RECT 1700.532 129.408 1700.556 129.600 ;
    END
  END d[412]
  PIN d[413]
    DIRECTION INPUT ;
    USE SIGNAL ;
    SHAPE ABUTMENT ;
    PORT
      LAYER M5 ;
      RECT 1704.612 129.408 1704.636 129.600 ;
    END
  END d[413]
  PIN d[414]
    DIRECTION INPUT ;
    USE SIGNAL ;
    SHAPE ABUTMENT ;
    PORT
      LAYER M5 ;
      RECT 1708.692 129.408 1708.716 129.600 ;
    END
  END d[414]
  PIN d[415]
    DIRECTION INPUT ;
    USE SIGNAL ;
    SHAPE ABUTMENT ;
    PORT
      LAYER M5 ;
      RECT 1712.772 129.408 1712.796 129.600 ;
    END
  END d[415]
  PIN d[416]
    DIRECTION INPUT ;
    USE SIGNAL ;
    SHAPE ABUTMENT ;
    PORT
      LAYER M5 ;
      RECT 1716.852 129.408 1716.876 129.600 ;
    END
  END d[416]
  PIN d[417]
    DIRECTION INPUT ;
    USE SIGNAL ;
    SHAPE ABUTMENT ;
    PORT
      LAYER M5 ;
      RECT 1720.932 129.408 1720.956 129.600 ;
    END
  END d[417]
  PIN d[418]
    DIRECTION INPUT ;
    USE SIGNAL ;
    SHAPE ABUTMENT ;
    PORT
      LAYER M5 ;
      RECT 1725.012 129.408 1725.036 129.600 ;
    END
  END d[418]
  PIN d[419]
    DIRECTION INPUT ;
    USE SIGNAL ;
    SHAPE ABUTMENT ;
    PORT
      LAYER M5 ;
      RECT 1729.092 129.408 1729.116 129.600 ;
    END
  END d[419]
  PIN d[420]
    DIRECTION INPUT ;
    USE SIGNAL ;
    SHAPE ABUTMENT ;
    PORT
      LAYER M5 ;
      RECT 1733.172 129.408 1733.196 129.600 ;
    END
  END d[420]
  PIN d[421]
    DIRECTION INPUT ;
    USE SIGNAL ;
    SHAPE ABUTMENT ;
    PORT
      LAYER M5 ;
      RECT 1737.252 129.408 1737.276 129.600 ;
    END
  END d[421]
  PIN d[422]
    DIRECTION INPUT ;
    USE SIGNAL ;
    SHAPE ABUTMENT ;
    PORT
      LAYER M5 ;
      RECT 1741.332 129.408 1741.356 129.600 ;
    END
  END d[422]
  PIN d[423]
    DIRECTION INPUT ;
    USE SIGNAL ;
    SHAPE ABUTMENT ;
    PORT
      LAYER M5 ;
      RECT 1745.412 129.408 1745.436 129.600 ;
    END
  END d[423]
  PIN d[424]
    DIRECTION INPUT ;
    USE SIGNAL ;
    SHAPE ABUTMENT ;
    PORT
      LAYER M5 ;
      RECT 1749.492 129.408 1749.516 129.600 ;
    END
  END d[424]
  PIN d[425]
    DIRECTION INPUT ;
    USE SIGNAL ;
    SHAPE ABUTMENT ;
    PORT
      LAYER M5 ;
      RECT 1753.572 129.408 1753.596 129.600 ;
    END
  END d[425]
  PIN d[426]
    DIRECTION INPUT ;
    USE SIGNAL ;
    SHAPE ABUTMENT ;
    PORT
      LAYER M5 ;
      RECT 1757.652 129.408 1757.676 129.600 ;
    END
  END d[426]
  PIN d[427]
    DIRECTION INPUT ;
    USE SIGNAL ;
    SHAPE ABUTMENT ;
    PORT
      LAYER M5 ;
      RECT 1761.732 129.408 1761.756 129.600 ;
    END
  END d[427]
  PIN d[428]
    DIRECTION INPUT ;
    USE SIGNAL ;
    SHAPE ABUTMENT ;
    PORT
      LAYER M5 ;
      RECT 1765.812 129.408 1765.836 129.600 ;
    END
  END d[428]
  PIN d[429]
    DIRECTION INPUT ;
    USE SIGNAL ;
    SHAPE ABUTMENT ;
    PORT
      LAYER M5 ;
      RECT 1769.892 129.408 1769.916 129.600 ;
    END
  END d[429]
  PIN d[430]
    DIRECTION INPUT ;
    USE SIGNAL ;
    SHAPE ABUTMENT ;
    PORT
      LAYER M5 ;
      RECT 1773.972 129.408 1773.996 129.600 ;
    END
  END d[430]
  PIN d[431]
    DIRECTION INPUT ;
    USE SIGNAL ;
    SHAPE ABUTMENT ;
    PORT
      LAYER M5 ;
      RECT 1778.052 129.408 1778.076 129.600 ;
    END
  END d[431]
  PIN d[432]
    DIRECTION INPUT ;
    USE SIGNAL ;
    SHAPE ABUTMENT ;
    PORT
      LAYER M5 ;
      RECT 1782.132 129.408 1782.156 129.600 ;
    END
  END d[432]
  PIN d[433]
    DIRECTION INPUT ;
    USE SIGNAL ;
    SHAPE ABUTMENT ;
    PORT
      LAYER M5 ;
      RECT 1786.212 129.408 1786.236 129.600 ;
    END
  END d[433]
  PIN d[434]
    DIRECTION INPUT ;
    USE SIGNAL ;
    SHAPE ABUTMENT ;
    PORT
      LAYER M5 ;
      RECT 1790.292 129.408 1790.316 129.600 ;
    END
  END d[434]
  PIN d[435]
    DIRECTION INPUT ;
    USE SIGNAL ;
    SHAPE ABUTMENT ;
    PORT
      LAYER M5 ;
      RECT 1794.372 129.408 1794.396 129.600 ;
    END
  END d[435]
  PIN d[436]
    DIRECTION INPUT ;
    USE SIGNAL ;
    SHAPE ABUTMENT ;
    PORT
      LAYER M5 ;
      RECT 1798.452 129.408 1798.476 129.600 ;
    END
  END d[436]
  PIN d[437]
    DIRECTION INPUT ;
    USE SIGNAL ;
    SHAPE ABUTMENT ;
    PORT
      LAYER M5 ;
      RECT 1802.532 129.408 1802.556 129.600 ;
    END
  END d[437]
  PIN d[438]
    DIRECTION INPUT ;
    USE SIGNAL ;
    SHAPE ABUTMENT ;
    PORT
      LAYER M5 ;
      RECT 1806.612 129.408 1806.636 129.600 ;
    END
  END d[438]
  PIN d[439]
    DIRECTION INPUT ;
    USE SIGNAL ;
    SHAPE ABUTMENT ;
    PORT
      LAYER M5 ;
      RECT 1810.692 129.408 1810.716 129.600 ;
    END
  END d[439]
  PIN d[440]
    DIRECTION INPUT ;
    USE SIGNAL ;
    SHAPE ABUTMENT ;
    PORT
      LAYER M5 ;
      RECT 1814.772 129.408 1814.796 129.600 ;
    END
  END d[440]
  PIN d[441]
    DIRECTION INPUT ;
    USE SIGNAL ;
    SHAPE ABUTMENT ;
    PORT
      LAYER M5 ;
      RECT 1818.852 129.408 1818.876 129.600 ;
    END
  END d[441]
  PIN d[442]
    DIRECTION INPUT ;
    USE SIGNAL ;
    SHAPE ABUTMENT ;
    PORT
      LAYER M5 ;
      RECT 1822.932 129.408 1822.956 129.600 ;
    END
  END d[442]
  PIN d[443]
    DIRECTION INPUT ;
    USE SIGNAL ;
    SHAPE ABUTMENT ;
    PORT
      LAYER M5 ;
      RECT 1827.012 129.408 1827.036 129.600 ;
    END
  END d[443]
  PIN d[444]
    DIRECTION INPUT ;
    USE SIGNAL ;
    SHAPE ABUTMENT ;
    PORT
      LAYER M5 ;
      RECT 1831.092 129.408 1831.116 129.600 ;
    END
  END d[444]
  PIN d[445]
    DIRECTION INPUT ;
    USE SIGNAL ;
    SHAPE ABUTMENT ;
    PORT
      LAYER M5 ;
      RECT 1835.172 129.408 1835.196 129.600 ;
    END
  END d[445]
  PIN d[446]
    DIRECTION INPUT ;
    USE SIGNAL ;
    SHAPE ABUTMENT ;
    PORT
      LAYER M5 ;
      RECT 1839.252 129.408 1839.276 129.600 ;
    END
  END d[446]
  PIN d[447]
    DIRECTION INPUT ;
    USE SIGNAL ;
    SHAPE ABUTMENT ;
    PORT
      LAYER M5 ;
      RECT 1843.332 129.408 1843.356 129.600 ;
    END
  END d[447]
  PIN d[448]
    DIRECTION INPUT ;
    USE SIGNAL ;
    SHAPE ABUTMENT ;
    PORT
      LAYER M5 ;
      RECT 1847.412 129.408 1847.436 129.600 ;
    END
  END d[448]
  PIN d[449]
    DIRECTION INPUT ;
    USE SIGNAL ;
    SHAPE ABUTMENT ;
    PORT
      LAYER M5 ;
      RECT 1851.492 129.408 1851.516 129.600 ;
    END
  END d[449]
  PIN d[450]
    DIRECTION INPUT ;
    USE SIGNAL ;
    SHAPE ABUTMENT ;
    PORT
      LAYER M5 ;
      RECT 1855.572 129.408 1855.596 129.600 ;
    END
  END d[450]
  PIN d[451]
    DIRECTION INPUT ;
    USE SIGNAL ;
    SHAPE ABUTMENT ;
    PORT
      LAYER M5 ;
      RECT 1859.652 129.408 1859.676 129.600 ;
    END
  END d[451]
  PIN d[452]
    DIRECTION INPUT ;
    USE SIGNAL ;
    SHAPE ABUTMENT ;
    PORT
      LAYER M5 ;
      RECT 1863.732 129.408 1863.756 129.600 ;
    END
  END d[452]
  PIN d[453]
    DIRECTION INPUT ;
    USE SIGNAL ;
    SHAPE ABUTMENT ;
    PORT
      LAYER M5 ;
      RECT 1867.812 129.408 1867.836 129.600 ;
    END
  END d[453]
  PIN d[454]
    DIRECTION INPUT ;
    USE SIGNAL ;
    SHAPE ABUTMENT ;
    PORT
      LAYER M5 ;
      RECT 1871.892 129.408 1871.916 129.600 ;
    END
  END d[454]
  PIN d[455]
    DIRECTION INPUT ;
    USE SIGNAL ;
    SHAPE ABUTMENT ;
    PORT
      LAYER M5 ;
      RECT 1875.972 129.408 1875.996 129.600 ;
    END
  END d[455]
  PIN d[456]
    DIRECTION INPUT ;
    USE SIGNAL ;
    SHAPE ABUTMENT ;
    PORT
      LAYER M5 ;
      RECT 1880.052 129.408 1880.076 129.600 ;
    END
  END d[456]
  PIN d[457]
    DIRECTION INPUT ;
    USE SIGNAL ;
    SHAPE ABUTMENT ;
    PORT
      LAYER M5 ;
      RECT 1884.132 129.408 1884.156 129.600 ;
    END
  END d[457]
  PIN d[458]
    DIRECTION INPUT ;
    USE SIGNAL ;
    SHAPE ABUTMENT ;
    PORT
      LAYER M5 ;
      RECT 1888.212 129.408 1888.236 129.600 ;
    END
  END d[458]
  PIN d[459]
    DIRECTION INPUT ;
    USE SIGNAL ;
    SHAPE ABUTMENT ;
    PORT
      LAYER M5 ;
      RECT 1892.292 129.408 1892.316 129.600 ;
    END
  END d[459]
  PIN d[460]
    DIRECTION INPUT ;
    USE SIGNAL ;
    SHAPE ABUTMENT ;
    PORT
      LAYER M5 ;
      RECT 1896.372 129.408 1896.396 129.600 ;
    END
  END d[460]
  PIN d[461]
    DIRECTION INPUT ;
    USE SIGNAL ;
    SHAPE ABUTMENT ;
    PORT
      LAYER M5 ;
      RECT 1900.452 129.408 1900.476 129.600 ;
    END
  END d[461]
  PIN d[462]
    DIRECTION INPUT ;
    USE SIGNAL ;
    SHAPE ABUTMENT ;
    PORT
      LAYER M5 ;
      RECT 1904.532 129.408 1904.556 129.600 ;
    END
  END d[462]
  PIN d[463]
    DIRECTION INPUT ;
    USE SIGNAL ;
    SHAPE ABUTMENT ;
    PORT
      LAYER M5 ;
      RECT 1908.612 129.408 1908.636 129.600 ;
    END
  END d[463]
  PIN d[464]
    DIRECTION INPUT ;
    USE SIGNAL ;
    SHAPE ABUTMENT ;
    PORT
      LAYER M5 ;
      RECT 1912.692 129.408 1912.716 129.600 ;
    END
  END d[464]
  PIN d[465]
    DIRECTION INPUT ;
    USE SIGNAL ;
    SHAPE ABUTMENT ;
    PORT
      LAYER M5 ;
      RECT 1916.772 129.408 1916.796 129.600 ;
    END
  END d[465]
  PIN d[466]
    DIRECTION INPUT ;
    USE SIGNAL ;
    SHAPE ABUTMENT ;
    PORT
      LAYER M5 ;
      RECT 1920.852 129.408 1920.876 129.600 ;
    END
  END d[466]
  PIN d[467]
    DIRECTION INPUT ;
    USE SIGNAL ;
    SHAPE ABUTMENT ;
    PORT
      LAYER M5 ;
      RECT 1924.932 129.408 1924.956 129.600 ;
    END
  END d[467]
  PIN d[468]
    DIRECTION INPUT ;
    USE SIGNAL ;
    SHAPE ABUTMENT ;
    PORT
      LAYER M5 ;
      RECT 1929.012 129.408 1929.036 129.600 ;
    END
  END d[468]
  PIN d[469]
    DIRECTION INPUT ;
    USE SIGNAL ;
    SHAPE ABUTMENT ;
    PORT
      LAYER M5 ;
      RECT 1933.092 129.408 1933.116 129.600 ;
    END
  END d[469]
  PIN d[470]
    DIRECTION INPUT ;
    USE SIGNAL ;
    SHAPE ABUTMENT ;
    PORT
      LAYER M5 ;
      RECT 1937.172 129.408 1937.196 129.600 ;
    END
  END d[470]
  PIN d[471]
    DIRECTION INPUT ;
    USE SIGNAL ;
    SHAPE ABUTMENT ;
    PORT
      LAYER M5 ;
      RECT 1941.252 129.408 1941.276 129.600 ;
    END
  END d[471]
  PIN d[472]
    DIRECTION INPUT ;
    USE SIGNAL ;
    SHAPE ABUTMENT ;
    PORT
      LAYER M5 ;
      RECT 1945.332 129.408 1945.356 129.600 ;
    END
  END d[472]
  PIN d[473]
    DIRECTION INPUT ;
    USE SIGNAL ;
    SHAPE ABUTMENT ;
    PORT
      LAYER M5 ;
      RECT 1949.412 129.408 1949.436 129.600 ;
    END
  END d[473]
  PIN d[474]
    DIRECTION INPUT ;
    USE SIGNAL ;
    SHAPE ABUTMENT ;
    PORT
      LAYER M5 ;
      RECT 1953.492 129.408 1953.516 129.600 ;
    END
  END d[474]
  PIN d[475]
    DIRECTION INPUT ;
    USE SIGNAL ;
    SHAPE ABUTMENT ;
    PORT
      LAYER M5 ;
      RECT 1957.572 129.408 1957.596 129.600 ;
    END
  END d[475]
  PIN d[476]
    DIRECTION INPUT ;
    USE SIGNAL ;
    SHAPE ABUTMENT ;
    PORT
      LAYER M5 ;
      RECT 1961.652 129.408 1961.676 129.600 ;
    END
  END d[476]
  PIN d[477]
    DIRECTION INPUT ;
    USE SIGNAL ;
    SHAPE ABUTMENT ;
    PORT
      LAYER M5 ;
      RECT 1965.732 129.408 1965.756 129.600 ;
    END
  END d[477]
  PIN d[478]
    DIRECTION INPUT ;
    USE SIGNAL ;
    SHAPE ABUTMENT ;
    PORT
      LAYER M5 ;
      RECT 1969.812 129.408 1969.836 129.600 ;
    END
  END d[478]
  PIN d[479]
    DIRECTION INPUT ;
    USE SIGNAL ;
    SHAPE ABUTMENT ;
    PORT
      LAYER M5 ;
      RECT 1973.892 129.408 1973.916 129.600 ;
    END
  END d[479]
  PIN d[480]
    DIRECTION INPUT ;
    USE SIGNAL ;
    SHAPE ABUTMENT ;
    PORT
      LAYER M5 ;
      RECT 1977.972 129.408 1977.996 129.600 ;
    END
  END d[480]
  PIN d[481]
    DIRECTION INPUT ;
    USE SIGNAL ;
    SHAPE ABUTMENT ;
    PORT
      LAYER M5 ;
      RECT 1982.052 129.408 1982.076 129.600 ;
    END
  END d[481]
  PIN d[482]
    DIRECTION INPUT ;
    USE SIGNAL ;
    SHAPE ABUTMENT ;
    PORT
      LAYER M5 ;
      RECT 1986.132 129.408 1986.156 129.600 ;
    END
  END d[482]
  PIN d[483]
    DIRECTION INPUT ;
    USE SIGNAL ;
    SHAPE ABUTMENT ;
    PORT
      LAYER M5 ;
      RECT 1990.212 129.408 1990.236 129.600 ;
    END
  END d[483]
  PIN d[484]
    DIRECTION INPUT ;
    USE SIGNAL ;
    SHAPE ABUTMENT ;
    PORT
      LAYER M5 ;
      RECT 1994.292 129.408 1994.316 129.600 ;
    END
  END d[484]
  PIN d[485]
    DIRECTION INPUT ;
    USE SIGNAL ;
    SHAPE ABUTMENT ;
    PORT
      LAYER M5 ;
      RECT 1998.372 129.408 1998.396 129.600 ;
    END
  END d[485]
  PIN d[486]
    DIRECTION INPUT ;
    USE SIGNAL ;
    SHAPE ABUTMENT ;
    PORT
      LAYER M5 ;
      RECT 2002.452 129.408 2002.476 129.600 ;
    END
  END d[486]
  PIN d[487]
    DIRECTION INPUT ;
    USE SIGNAL ;
    SHAPE ABUTMENT ;
    PORT
      LAYER M5 ;
      RECT 2006.532 129.408 2006.556 129.600 ;
    END
  END d[487]
  PIN d[488]
    DIRECTION INPUT ;
    USE SIGNAL ;
    SHAPE ABUTMENT ;
    PORT
      LAYER M5 ;
      RECT 2010.612 129.408 2010.636 129.600 ;
    END
  END d[488]
  PIN d[489]
    DIRECTION INPUT ;
    USE SIGNAL ;
    SHAPE ABUTMENT ;
    PORT
      LAYER M5 ;
      RECT 2014.692 129.408 2014.716 129.600 ;
    END
  END d[489]
  PIN d[490]
    DIRECTION INPUT ;
    USE SIGNAL ;
    SHAPE ABUTMENT ;
    PORT
      LAYER M5 ;
      RECT 2018.772 129.408 2018.796 129.600 ;
    END
  END d[490]
  PIN d[491]
    DIRECTION INPUT ;
    USE SIGNAL ;
    SHAPE ABUTMENT ;
    PORT
      LAYER M5 ;
      RECT 2022.852 129.408 2022.876 129.600 ;
    END
  END d[491]
  PIN d[492]
    DIRECTION INPUT ;
    USE SIGNAL ;
    SHAPE ABUTMENT ;
    PORT
      LAYER M5 ;
      RECT 2026.932 129.408 2026.956 129.600 ;
    END
  END d[492]
  PIN d[493]
    DIRECTION INPUT ;
    USE SIGNAL ;
    SHAPE ABUTMENT ;
    PORT
      LAYER M5 ;
      RECT 2031.012 129.408 2031.036 129.600 ;
    END
  END d[493]
  PIN d[494]
    DIRECTION INPUT ;
    USE SIGNAL ;
    SHAPE ABUTMENT ;
    PORT
      LAYER M5 ;
      RECT 2035.092 129.408 2035.116 129.600 ;
    END
  END d[494]
  PIN d[495]
    DIRECTION INPUT ;
    USE SIGNAL ;
    SHAPE ABUTMENT ;
    PORT
      LAYER M5 ;
      RECT 2039.172 129.408 2039.196 129.600 ;
    END
  END d[495]
  PIN d[496]
    DIRECTION INPUT ;
    USE SIGNAL ;
    SHAPE ABUTMENT ;
    PORT
      LAYER M5 ;
      RECT 2043.252 129.408 2043.276 129.600 ;
    END
  END d[496]
  PIN d[497]
    DIRECTION INPUT ;
    USE SIGNAL ;
    SHAPE ABUTMENT ;
    PORT
      LAYER M5 ;
      RECT 2047.332 129.408 2047.356 129.600 ;
    END
  END d[497]
  PIN d[498]
    DIRECTION INPUT ;
    USE SIGNAL ;
    SHAPE ABUTMENT ;
    PORT
      LAYER M5 ;
      RECT 2051.412 129.408 2051.436 129.600 ;
    END
  END d[498]
  PIN d[499]
    DIRECTION INPUT ;
    USE SIGNAL ;
    SHAPE ABUTMENT ;
    PORT
      LAYER M5 ;
      RECT 2055.492 129.408 2055.516 129.600 ;
    END
  END d[499]
  PIN d[500]
    DIRECTION INPUT ;
    USE SIGNAL ;
    SHAPE ABUTMENT ;
    PORT
      LAYER M5 ;
      RECT 2059.572 129.408 2059.596 129.600 ;
    END
  END d[500]
  PIN d[501]
    DIRECTION INPUT ;
    USE SIGNAL ;
    SHAPE ABUTMENT ;
    PORT
      LAYER M5 ;
      RECT 2063.652 129.408 2063.676 129.600 ;
    END
  END d[501]
  PIN d[502]
    DIRECTION INPUT ;
    USE SIGNAL ;
    SHAPE ABUTMENT ;
    PORT
      LAYER M5 ;
      RECT 2067.732 129.408 2067.756 129.600 ;
    END
  END d[502]
  PIN d[503]
    DIRECTION INPUT ;
    USE SIGNAL ;
    SHAPE ABUTMENT ;
    PORT
      LAYER M5 ;
      RECT 2071.812 129.408 2071.836 129.600 ;
    END
  END d[503]
  PIN d[504]
    DIRECTION INPUT ;
    USE SIGNAL ;
    SHAPE ABUTMENT ;
    PORT
      LAYER M5 ;
      RECT 2075.892 129.408 2075.916 129.600 ;
    END
  END d[504]
  PIN d[505]
    DIRECTION INPUT ;
    USE SIGNAL ;
    SHAPE ABUTMENT ;
    PORT
      LAYER M5 ;
      RECT 2079.972 129.408 2079.996 129.600 ;
    END
  END d[505]
  PIN d[506]
    DIRECTION INPUT ;
    USE SIGNAL ;
    SHAPE ABUTMENT ;
    PORT
      LAYER M5 ;
      RECT 2084.052 129.408 2084.076 129.600 ;
    END
  END d[506]
  PIN d[507]
    DIRECTION INPUT ;
    USE SIGNAL ;
    SHAPE ABUTMENT ;
    PORT
      LAYER M5 ;
      RECT 2088.132 129.408 2088.156 129.600 ;
    END
  END d[507]
  PIN d[508]
    DIRECTION INPUT ;
    USE SIGNAL ;
    SHAPE ABUTMENT ;
    PORT
      LAYER M5 ;
      RECT 2092.212 129.408 2092.236 129.600 ;
    END
  END d[508]
  PIN d[509]
    DIRECTION INPUT ;
    USE SIGNAL ;
    SHAPE ABUTMENT ;
    PORT
      LAYER M5 ;
      RECT 2096.292 129.408 2096.316 129.600 ;
    END
  END d[509]
  PIN d[510]
    DIRECTION INPUT ;
    USE SIGNAL ;
    SHAPE ABUTMENT ;
    PORT
      LAYER M5 ;
      RECT 2100.372 129.408 2100.396 129.600 ;
    END
  END d[510]
  PIN d[511]
    DIRECTION INPUT ;
    USE SIGNAL ;
    SHAPE ABUTMENT ;
    PORT
      LAYER M5 ;
      RECT 2104.452 129.408 2104.476 129.600 ;
    END
  END d[511]
  PIN d[512]
    DIRECTION INPUT ;
    USE SIGNAL ;
    SHAPE ABUTMENT ;
    PORT
      LAYER M5 ;
      RECT 2108.532 129.408 2108.556 129.600 ;
    END
  END d[512]
  PIN d[513]
    DIRECTION INPUT ;
    USE SIGNAL ;
    SHAPE ABUTMENT ;
    PORT
      LAYER M5 ;
      RECT 2112.612 129.408 2112.636 129.600 ;
    END
  END d[513]
  PIN d[514]
    DIRECTION INPUT ;
    USE SIGNAL ;
    SHAPE ABUTMENT ;
    PORT
      LAYER M5 ;
      RECT 2116.692 129.408 2116.716 129.600 ;
    END
  END d[514]
  PIN d[515]
    DIRECTION INPUT ;
    USE SIGNAL ;
    SHAPE ABUTMENT ;
    PORT
      LAYER M5 ;
      RECT 2120.772 129.408 2120.796 129.600 ;
    END
  END d[515]
  PIN d[516]
    DIRECTION INPUT ;
    USE SIGNAL ;
    SHAPE ABUTMENT ;
    PORT
      LAYER M5 ;
      RECT 2124.852 129.408 2124.876 129.600 ;
    END
  END d[516]
  PIN d[517]
    DIRECTION INPUT ;
    USE SIGNAL ;
    SHAPE ABUTMENT ;
    PORT
      LAYER M5 ;
      RECT 2128.932 129.408 2128.956 129.600 ;
    END
  END d[517]
  PIN d[518]
    DIRECTION INPUT ;
    USE SIGNAL ;
    SHAPE ABUTMENT ;
    PORT
      LAYER M5 ;
      RECT 2133.012 129.408 2133.036 129.600 ;
    END
  END d[518]
  PIN d[519]
    DIRECTION INPUT ;
    USE SIGNAL ;
    SHAPE ABUTMENT ;
    PORT
      LAYER M5 ;
      RECT 2137.092 129.408 2137.116 129.600 ;
    END
  END d[519]
  PIN d[520]
    DIRECTION INPUT ;
    USE SIGNAL ;
    SHAPE ABUTMENT ;
    PORT
      LAYER M5 ;
      RECT 2141.172 129.408 2141.196 129.600 ;
    END
  END d[520]
  PIN d[521]
    DIRECTION INPUT ;
    USE SIGNAL ;
    SHAPE ABUTMENT ;
    PORT
      LAYER M5 ;
      RECT 2145.252 129.408 2145.276 129.600 ;
    END
  END d[521]
  PIN d[522]
    DIRECTION INPUT ;
    USE SIGNAL ;
    SHAPE ABUTMENT ;
    PORT
      LAYER M5 ;
      RECT 2149.332 129.408 2149.356 129.600 ;
    END
  END d[522]
  PIN d[523]
    DIRECTION INPUT ;
    USE SIGNAL ;
    SHAPE ABUTMENT ;
    PORT
      LAYER M5 ;
      RECT 2153.412 129.408 2153.436 129.600 ;
    END
  END d[523]
  PIN d[524]
    DIRECTION INPUT ;
    USE SIGNAL ;
    SHAPE ABUTMENT ;
    PORT
      LAYER M5 ;
      RECT 2157.492 129.408 2157.516 129.600 ;
    END
  END d[524]
  PIN d[525]
    DIRECTION INPUT ;
    USE SIGNAL ;
    SHAPE ABUTMENT ;
    PORT
      LAYER M5 ;
      RECT 2161.572 129.408 2161.596 129.600 ;
    END
  END d[525]
  PIN d[526]
    DIRECTION INPUT ;
    USE SIGNAL ;
    SHAPE ABUTMENT ;
    PORT
      LAYER M5 ;
      RECT 2165.652 129.408 2165.676 129.600 ;
    END
  END d[526]
  PIN d[527]
    DIRECTION INPUT ;
    USE SIGNAL ;
    SHAPE ABUTMENT ;
    PORT
      LAYER M5 ;
      RECT 2169.732 129.408 2169.756 129.600 ;
    END
  END d[527]
  PIN d[528]
    DIRECTION INPUT ;
    USE SIGNAL ;
    SHAPE ABUTMENT ;
    PORT
      LAYER M5 ;
      RECT 2173.812 129.408 2173.836 129.600 ;
    END
  END d[528]
  PIN d[529]
    DIRECTION INPUT ;
    USE SIGNAL ;
    SHAPE ABUTMENT ;
    PORT
      LAYER M5 ;
      RECT 2177.892 129.408 2177.916 129.600 ;
    END
  END d[529]
  PIN d[530]
    DIRECTION INPUT ;
    USE SIGNAL ;
    SHAPE ABUTMENT ;
    PORT
      LAYER M5 ;
      RECT 2181.972 129.408 2181.996 129.600 ;
    END
  END d[530]
  PIN d[531]
    DIRECTION INPUT ;
    USE SIGNAL ;
    SHAPE ABUTMENT ;
    PORT
      LAYER M5 ;
      RECT 2186.052 129.408 2186.076 129.600 ;
    END
  END d[531]
  PIN d[532]
    DIRECTION INPUT ;
    USE SIGNAL ;
    SHAPE ABUTMENT ;
    PORT
      LAYER M5 ;
      RECT 2190.132 129.408 2190.156 129.600 ;
    END
  END d[532]
  PIN d[533]
    DIRECTION INPUT ;
    USE SIGNAL ;
    SHAPE ABUTMENT ;
    PORT
      LAYER M5 ;
      RECT 2194.212 129.408 2194.236 129.600 ;
    END
  END d[533]
  PIN d[534]
    DIRECTION INPUT ;
    USE SIGNAL ;
    SHAPE ABUTMENT ;
    PORT
      LAYER M5 ;
      RECT 2198.292 129.408 2198.316 129.600 ;
    END
  END d[534]
  PIN d[535]
    DIRECTION INPUT ;
    USE SIGNAL ;
    SHAPE ABUTMENT ;
    PORT
      LAYER M5 ;
      RECT 2202.372 129.408 2202.396 129.600 ;
    END
  END d[535]
  PIN d[536]
    DIRECTION INPUT ;
    USE SIGNAL ;
    SHAPE ABUTMENT ;
    PORT
      LAYER M5 ;
      RECT 2206.452 129.408 2206.476 129.600 ;
    END
  END d[536]
  PIN d[537]
    DIRECTION INPUT ;
    USE SIGNAL ;
    SHAPE ABUTMENT ;
    PORT
      LAYER M5 ;
      RECT 2210.532 129.408 2210.556 129.600 ;
    END
  END d[537]
  PIN d[538]
    DIRECTION INPUT ;
    USE SIGNAL ;
    SHAPE ABUTMENT ;
    PORT
      LAYER M5 ;
      RECT 2214.612 129.408 2214.636 129.600 ;
    END
  END d[538]
  PIN d[539]
    DIRECTION INPUT ;
    USE SIGNAL ;
    SHAPE ABUTMENT ;
    PORT
      LAYER M5 ;
      RECT 2218.692 129.408 2218.716 129.600 ;
    END
  END d[539]
  PIN d[540]
    DIRECTION INPUT ;
    USE SIGNAL ;
    SHAPE ABUTMENT ;
    PORT
      LAYER M5 ;
      RECT 2222.772 129.408 2222.796 129.600 ;
    END
  END d[540]
  PIN d[541]
    DIRECTION INPUT ;
    USE SIGNAL ;
    SHAPE ABUTMENT ;
    PORT
      LAYER M5 ;
      RECT 2226.852 129.408 2226.876 129.600 ;
    END
  END d[541]
  PIN d[542]
    DIRECTION INPUT ;
    USE SIGNAL ;
    SHAPE ABUTMENT ;
    PORT
      LAYER M5 ;
      RECT 2230.932 129.408 2230.956 129.600 ;
    END
  END d[542]
  PIN d[543]
    DIRECTION INPUT ;
    USE SIGNAL ;
    SHAPE ABUTMENT ;
    PORT
      LAYER M5 ;
      RECT 2235.012 129.408 2235.036 129.600 ;
    END
  END d[543]
  PIN pma_tx[0]
    DIRECTION OUTPUT ;
    USE SIGNAL ;
    SHAPE ABUTMENT ;
    PORT
      LAYER M5 ;
      RECT 13.428 0.000 13.452 0.192 ;
    END
  END pma_tx[0]
  PIN pma_tx[1]
    DIRECTION OUTPUT ;
    USE SIGNAL ;
    SHAPE ABUTMENT ;
    PORT
      LAYER M5 ;
      RECT 17.508 0.000 17.532 0.192 ;
    END
  END pma_tx[1]
  PIN pma_tx[2]
    DIRECTION OUTPUT ;
    USE SIGNAL ;
    SHAPE ABUTMENT ;
    PORT
      LAYER M5 ;
      RECT 21.588 0.000 21.612 0.192 ;
    END
  END pma_tx[2]
  PIN pma_tx[3]
    DIRECTION OUTPUT ;
    USE SIGNAL ;
    SHAPE ABUTMENT ;
    PORT
      LAYER M5 ;
      RECT 25.668 0.000 25.692 0.192 ;
    END
  END pma_tx[3]
  PIN pma_tx[4]
    DIRECTION OUTPUT ;
    USE SIGNAL ;
    SHAPE ABUTMENT ;
    PORT
      LAYER M5 ;
      RECT 29.748 0.000 29.772 0.192 ;
    END
  END pma_tx[4]
  PIN pma_tx[5]
    DIRECTION OUTPUT ;
    USE SIGNAL ;
    SHAPE ABUTMENT ;
    PORT
      LAYER M5 ;
      RECT 33.828 0.000 33.852 0.192 ;
    END
  END pma_tx[5]
  PIN pma_tx[6]
    DIRECTION OUTPUT ;
    USE SIGNAL ;
    SHAPE ABUTMENT ;
    PORT
      LAYER M5 ;
      RECT 37.908 0.000 37.932 0.192 ;
    END
  END pma_tx[6]
  PIN pma_tx[7]
    DIRECTION OUTPUT ;
    USE SIGNAL ;
    SHAPE ABUTMENT ;
    PORT
      LAYER M5 ;
      RECT 41.988 0.000 42.012 0.192 ;
    END
  END pma_tx[7]
  PIN pma_tx[8]
    DIRECTION OUTPUT ;
    USE SIGNAL ;
    SHAPE ABUTMENT ;
    PORT
      LAYER M5 ;
      RECT 46.068 0.000 46.092 0.192 ;
    END
  END pma_tx[8]
  PIN pma_tx[9]
    DIRECTION OUTPUT ;
    USE SIGNAL ;
    SHAPE ABUTMENT ;
    PORT
      LAYER M5 ;
      RECT 50.148 0.000 50.172 0.192 ;
    END
  END pma_tx[9]
  PIN pma_tx[10]
    DIRECTION OUTPUT ;
    USE SIGNAL ;
    SHAPE ABUTMENT ;
    PORT
      LAYER M5 ;
      RECT 54.228 0.000 54.252 0.192 ;
    END
  END pma_tx[10]
  PIN pma_tx[11]
    DIRECTION OUTPUT ;
    USE SIGNAL ;
    SHAPE ABUTMENT ;
    PORT
      LAYER M5 ;
      RECT 58.308 0.000 58.332 0.192 ;
    END
  END pma_tx[11]
  PIN pma_tx[12]
    DIRECTION OUTPUT ;
    USE SIGNAL ;
    SHAPE ABUTMENT ;
    PORT
      LAYER M5 ;
      RECT 62.388 0.000 62.412 0.192 ;
    END
  END pma_tx[12]
  PIN pma_tx[13]
    DIRECTION OUTPUT ;
    USE SIGNAL ;
    SHAPE ABUTMENT ;
    PORT
      LAYER M5 ;
      RECT 66.468 0.000 66.492 0.192 ;
    END
  END pma_tx[13]
  PIN pma_tx[14]
    DIRECTION OUTPUT ;
    USE SIGNAL ;
    SHAPE ABUTMENT ;
    PORT
      LAYER M5 ;
      RECT 70.548 0.000 70.572 0.192 ;
    END
  END pma_tx[14]
  PIN pma_tx[15]
    DIRECTION OUTPUT ;
    USE SIGNAL ;
    SHAPE ABUTMENT ;
    PORT
      LAYER M5 ;
      RECT 74.628 0.000 74.652 0.192 ;
    END
  END pma_tx[15]
  PIN pma_tx[16]
    DIRECTION OUTPUT ;
    USE SIGNAL ;
    SHAPE ABUTMENT ;
    PORT
      LAYER M5 ;
      RECT 78.708 0.000 78.732 0.192 ;
    END
  END pma_tx[16]
  PIN pma_tx[17]
    DIRECTION OUTPUT ;
    USE SIGNAL ;
    SHAPE ABUTMENT ;
    PORT
      LAYER M5 ;
      RECT 82.788 0.000 82.812 0.192 ;
    END
  END pma_tx[17]
  PIN pma_tx[18]
    DIRECTION OUTPUT ;
    USE SIGNAL ;
    SHAPE ABUTMENT ;
    PORT
      LAYER M5 ;
      RECT 86.868 0.000 86.892 0.192 ;
    END
  END pma_tx[18]
  PIN pma_tx[19]
    DIRECTION OUTPUT ;
    USE SIGNAL ;
    SHAPE ABUTMENT ;
    PORT
      LAYER M5 ;
      RECT 90.948 0.000 90.972 0.192 ;
    END
  END pma_tx[19]
  PIN pma_tx[20]
    DIRECTION OUTPUT ;
    USE SIGNAL ;
    SHAPE ABUTMENT ;
    PORT
      LAYER M5 ;
      RECT 95.028 0.000 95.052 0.192 ;
    END
  END pma_tx[20]
  PIN pma_tx[21]
    DIRECTION OUTPUT ;
    USE SIGNAL ;
    SHAPE ABUTMENT ;
    PORT
      LAYER M5 ;
      RECT 99.108 0.000 99.132 0.192 ;
    END
  END pma_tx[21]
  PIN pma_tx[22]
    DIRECTION OUTPUT ;
    USE SIGNAL ;
    SHAPE ABUTMENT ;
    PORT
      LAYER M5 ;
      RECT 103.188 0.000 103.212 0.192 ;
    END
  END pma_tx[22]
  PIN pma_tx[23]
    DIRECTION OUTPUT ;
    USE SIGNAL ;
    SHAPE ABUTMENT ;
    PORT
      LAYER M5 ;
      RECT 107.268 0.000 107.292 0.192 ;
    END
  END pma_tx[23]
  PIN pma_tx[24]
    DIRECTION OUTPUT ;
    USE SIGNAL ;
    SHAPE ABUTMENT ;
    PORT
      LAYER M5 ;
      RECT 111.348 0.000 111.372 0.192 ;
    END
  END pma_tx[24]
  PIN pma_tx[25]
    DIRECTION OUTPUT ;
    USE SIGNAL ;
    SHAPE ABUTMENT ;
    PORT
      LAYER M5 ;
      RECT 115.428 0.000 115.452 0.192 ;
    END
  END pma_tx[25]
  PIN pma_tx[26]
    DIRECTION OUTPUT ;
    USE SIGNAL ;
    SHAPE ABUTMENT ;
    PORT
      LAYER M5 ;
      RECT 119.508 0.000 119.532 0.192 ;
    END
  END pma_tx[26]
  PIN pma_tx[27]
    DIRECTION OUTPUT ;
    USE SIGNAL ;
    SHAPE ABUTMENT ;
    PORT
      LAYER M5 ;
      RECT 123.588 0.000 123.612 0.192 ;
    END
  END pma_tx[27]
  PIN pma_tx[28]
    DIRECTION OUTPUT ;
    USE SIGNAL ;
    SHAPE ABUTMENT ;
    PORT
      LAYER M5 ;
      RECT 127.668 0.000 127.692 0.192 ;
    END
  END pma_tx[28]
  PIN pma_tx[29]
    DIRECTION OUTPUT ;
    USE SIGNAL ;
    SHAPE ABUTMENT ;
    PORT
      LAYER M5 ;
      RECT 131.748 0.000 131.772 0.192 ;
    END
  END pma_tx[29]
  PIN pma_tx[30]
    DIRECTION OUTPUT ;
    USE SIGNAL ;
    SHAPE ABUTMENT ;
    PORT
      LAYER M5 ;
      RECT 135.828 0.000 135.852 0.192 ;
    END
  END pma_tx[30]
  PIN pma_tx[31]
    DIRECTION OUTPUT ;
    USE SIGNAL ;
    SHAPE ABUTMENT ;
    PORT
      LAYER M5 ;
      RECT 139.908 0.000 139.932 0.192 ;
    END
  END pma_tx[31]
  PIN pma_tx[32]
    DIRECTION OUTPUT ;
    USE SIGNAL ;
    SHAPE ABUTMENT ;
    PORT
      LAYER M5 ;
      RECT 143.988 0.000 144.012 0.192 ;
    END
  END pma_tx[32]
  PIN pma_tx[33]
    DIRECTION OUTPUT ;
    USE SIGNAL ;
    SHAPE ABUTMENT ;
    PORT
      LAYER M5 ;
      RECT 148.068 0.000 148.092 0.192 ;
    END
  END pma_tx[33]
  PIN pma_tx[34]
    DIRECTION OUTPUT ;
    USE SIGNAL ;
    SHAPE ABUTMENT ;
    PORT
      LAYER M5 ;
      RECT 152.148 0.000 152.172 0.192 ;
    END
  END pma_tx[34]
  PIN pma_tx[35]
    DIRECTION OUTPUT ;
    USE SIGNAL ;
    SHAPE ABUTMENT ;
    PORT
      LAYER M5 ;
      RECT 156.228 0.000 156.252 0.192 ;
    END
  END pma_tx[35]
  PIN pma_tx[36]
    DIRECTION OUTPUT ;
    USE SIGNAL ;
    SHAPE ABUTMENT ;
    PORT
      LAYER M5 ;
      RECT 160.308 0.000 160.332 0.192 ;
    END
  END pma_tx[36]
  PIN pma_tx[37]
    DIRECTION OUTPUT ;
    USE SIGNAL ;
    SHAPE ABUTMENT ;
    PORT
      LAYER M5 ;
      RECT 164.388 0.000 164.412 0.192 ;
    END
  END pma_tx[37]
  PIN pma_tx[38]
    DIRECTION OUTPUT ;
    USE SIGNAL ;
    SHAPE ABUTMENT ;
    PORT
      LAYER M5 ;
      RECT 168.468 0.000 168.492 0.192 ;
    END
  END pma_tx[38]
  PIN pma_tx[39]
    DIRECTION OUTPUT ;
    USE SIGNAL ;
    SHAPE ABUTMENT ;
    PORT
      LAYER M5 ;
      RECT 172.548 0.000 172.572 0.192 ;
    END
  END pma_tx[39]
  PIN pma_tx[40]
    DIRECTION OUTPUT ;
    USE SIGNAL ;
    SHAPE ABUTMENT ;
    PORT
      LAYER M5 ;
      RECT 176.628 0.000 176.652 0.192 ;
    END
  END pma_tx[40]
  PIN pma_tx[41]
    DIRECTION OUTPUT ;
    USE SIGNAL ;
    SHAPE ABUTMENT ;
    PORT
      LAYER M5 ;
      RECT 180.708 0.000 180.732 0.192 ;
    END
  END pma_tx[41]
  PIN pma_tx[42]
    DIRECTION OUTPUT ;
    USE SIGNAL ;
    SHAPE ABUTMENT ;
    PORT
      LAYER M5 ;
      RECT 184.788 0.000 184.812 0.192 ;
    END
  END pma_tx[42]
  PIN pma_tx[43]
    DIRECTION OUTPUT ;
    USE SIGNAL ;
    SHAPE ABUTMENT ;
    PORT
      LAYER M5 ;
      RECT 188.868 0.000 188.892 0.192 ;
    END
  END pma_tx[43]
  PIN pma_tx[44]
    DIRECTION OUTPUT ;
    USE SIGNAL ;
    SHAPE ABUTMENT ;
    PORT
      LAYER M5 ;
      RECT 192.948 0.000 192.972 0.192 ;
    END
  END pma_tx[44]
  PIN pma_tx[45]
    DIRECTION OUTPUT ;
    USE SIGNAL ;
    SHAPE ABUTMENT ;
    PORT
      LAYER M5 ;
      RECT 197.028 0.000 197.052 0.192 ;
    END
  END pma_tx[45]
  PIN pma_tx[46]
    DIRECTION OUTPUT ;
    USE SIGNAL ;
    SHAPE ABUTMENT ;
    PORT
      LAYER M5 ;
      RECT 201.108 0.000 201.132 0.192 ;
    END
  END pma_tx[46]
  PIN pma_tx[47]
    DIRECTION OUTPUT ;
    USE SIGNAL ;
    SHAPE ABUTMENT ;
    PORT
      LAYER M5 ;
      RECT 205.188 0.000 205.212 0.192 ;
    END
  END pma_tx[47]
  PIN pma_tx[48]
    DIRECTION OUTPUT ;
    USE SIGNAL ;
    SHAPE ABUTMENT ;
    PORT
      LAYER M5 ;
      RECT 209.268 0.000 209.292 0.192 ;
    END
  END pma_tx[48]
  PIN pma_tx[49]
    DIRECTION OUTPUT ;
    USE SIGNAL ;
    SHAPE ABUTMENT ;
    PORT
      LAYER M5 ;
      RECT 213.348 0.000 213.372 0.192 ;
    END
  END pma_tx[49]
  PIN pma_tx[50]
    DIRECTION OUTPUT ;
    USE SIGNAL ;
    SHAPE ABUTMENT ;
    PORT
      LAYER M5 ;
      RECT 217.428 0.000 217.452 0.192 ;
    END
  END pma_tx[50]
  PIN pma_tx[51]
    DIRECTION OUTPUT ;
    USE SIGNAL ;
    SHAPE ABUTMENT ;
    PORT
      LAYER M5 ;
      RECT 221.508 0.000 221.532 0.192 ;
    END
  END pma_tx[51]
  PIN pma_tx[52]
    DIRECTION OUTPUT ;
    USE SIGNAL ;
    SHAPE ABUTMENT ;
    PORT
      LAYER M5 ;
      RECT 225.588 0.000 225.612 0.192 ;
    END
  END pma_tx[52]
  PIN pma_tx[53]
    DIRECTION OUTPUT ;
    USE SIGNAL ;
    SHAPE ABUTMENT ;
    PORT
      LAYER M5 ;
      RECT 229.668 0.000 229.692 0.192 ;
    END
  END pma_tx[53]
  PIN pma_tx[54]
    DIRECTION OUTPUT ;
    USE SIGNAL ;
    SHAPE ABUTMENT ;
    PORT
      LAYER M5 ;
      RECT 233.748 0.000 233.772 0.192 ;
    END
  END pma_tx[54]
  PIN pma_tx[55]
    DIRECTION OUTPUT ;
    USE SIGNAL ;
    SHAPE ABUTMENT ;
    PORT
      LAYER M5 ;
      RECT 237.828 0.000 237.852 0.192 ;
    END
  END pma_tx[55]
  PIN pma_tx[56]
    DIRECTION OUTPUT ;
    USE SIGNAL ;
    SHAPE ABUTMENT ;
    PORT
      LAYER M5 ;
      RECT 241.908 0.000 241.932 0.192 ;
    END
  END pma_tx[56]
  PIN pma_tx[57]
    DIRECTION OUTPUT ;
    USE SIGNAL ;
    SHAPE ABUTMENT ;
    PORT
      LAYER M5 ;
      RECT 245.988 0.000 246.012 0.192 ;
    END
  END pma_tx[57]
  PIN pma_tx[58]
    DIRECTION OUTPUT ;
    USE SIGNAL ;
    SHAPE ABUTMENT ;
    PORT
      LAYER M5 ;
      RECT 250.068 0.000 250.092 0.192 ;
    END
  END pma_tx[58]
  PIN pma_tx[59]
    DIRECTION OUTPUT ;
    USE SIGNAL ;
    SHAPE ABUTMENT ;
    PORT
      LAYER M5 ;
      RECT 254.148 0.000 254.172 0.192 ;
    END
  END pma_tx[59]
  PIN pma_tx[60]
    DIRECTION OUTPUT ;
    USE SIGNAL ;
    SHAPE ABUTMENT ;
    PORT
      LAYER M5 ;
      RECT 258.228 0.000 258.252 0.192 ;
    END
  END pma_tx[60]
  PIN pma_tx[61]
    DIRECTION OUTPUT ;
    USE SIGNAL ;
    SHAPE ABUTMENT ;
    PORT
      LAYER M5 ;
      RECT 262.308 0.000 262.332 0.192 ;
    END
  END pma_tx[61]
  PIN pma_tx[62]
    DIRECTION OUTPUT ;
    USE SIGNAL ;
    SHAPE ABUTMENT ;
    PORT
      LAYER M5 ;
      RECT 266.388 0.000 266.412 0.192 ;
    END
  END pma_tx[62]
  PIN pma_tx[63]
    DIRECTION OUTPUT ;
    USE SIGNAL ;
    SHAPE ABUTMENT ;
    PORT
      LAYER M5 ;
      RECT 270.468 0.000 270.492 0.192 ;
    END
  END pma_tx[63]
  PIN pma_tx[64]
    DIRECTION OUTPUT ;
    USE SIGNAL ;
    SHAPE ABUTMENT ;
    PORT
      LAYER M5 ;
      RECT 274.548 0.000 274.572 0.192 ;
    END
  END pma_tx[64]
  PIN pma_tx[65]
    DIRECTION OUTPUT ;
    USE SIGNAL ;
    SHAPE ABUTMENT ;
    PORT
      LAYER M5 ;
      RECT 278.628 0.000 278.652 0.192 ;
    END
  END pma_tx[65]
  PIN pma_tx[66]
    DIRECTION OUTPUT ;
    USE SIGNAL ;
    SHAPE ABUTMENT ;
    PORT
      LAYER M5 ;
      RECT 282.708 0.000 282.732 0.192 ;
    END
  END pma_tx[66]
  PIN pma_tx[67]
    DIRECTION OUTPUT ;
    USE SIGNAL ;
    SHAPE ABUTMENT ;
    PORT
      LAYER M5 ;
      RECT 286.788 0.000 286.812 0.192 ;
    END
  END pma_tx[67]
  PIN pma_tx[68]
    DIRECTION OUTPUT ;
    USE SIGNAL ;
    SHAPE ABUTMENT ;
    PORT
      LAYER M5 ;
      RECT 290.868 0.000 290.892 0.192 ;
    END
  END pma_tx[68]
  PIN pma_tx[69]
    DIRECTION OUTPUT ;
    USE SIGNAL ;
    SHAPE ABUTMENT ;
    PORT
      LAYER M5 ;
      RECT 294.948 0.000 294.972 0.192 ;
    END
  END pma_tx[69]
  PIN pma_tx[70]
    DIRECTION OUTPUT ;
    USE SIGNAL ;
    SHAPE ABUTMENT ;
    PORT
      LAYER M5 ;
      RECT 299.028 0.000 299.052 0.192 ;
    END
  END pma_tx[70]
  PIN pma_tx[71]
    DIRECTION OUTPUT ;
    USE SIGNAL ;
    SHAPE ABUTMENT ;
    PORT
      LAYER M5 ;
      RECT 303.108 0.000 303.132 0.192 ;
    END
  END pma_tx[71]
  PIN pma_tx[72]
    DIRECTION OUTPUT ;
    USE SIGNAL ;
    SHAPE ABUTMENT ;
    PORT
      LAYER M5 ;
      RECT 307.188 0.000 307.212 0.192 ;
    END
  END pma_tx[72]
  PIN pma_tx[73]
    DIRECTION OUTPUT ;
    USE SIGNAL ;
    SHAPE ABUTMENT ;
    PORT
      LAYER M5 ;
      RECT 311.268 0.000 311.292 0.192 ;
    END
  END pma_tx[73]
  PIN pma_tx[74]
    DIRECTION OUTPUT ;
    USE SIGNAL ;
    SHAPE ABUTMENT ;
    PORT
      LAYER M5 ;
      RECT 315.348 0.000 315.372 0.192 ;
    END
  END pma_tx[74]
  PIN pma_tx[75]
    DIRECTION OUTPUT ;
    USE SIGNAL ;
    SHAPE ABUTMENT ;
    PORT
      LAYER M5 ;
      RECT 319.428 0.000 319.452 0.192 ;
    END
  END pma_tx[75]
  PIN pma_tx[76]
    DIRECTION OUTPUT ;
    USE SIGNAL ;
    SHAPE ABUTMENT ;
    PORT
      LAYER M5 ;
      RECT 323.508 0.000 323.532 0.192 ;
    END
  END pma_tx[76]
  PIN pma_tx[77]
    DIRECTION OUTPUT ;
    USE SIGNAL ;
    SHAPE ABUTMENT ;
    PORT
      LAYER M5 ;
      RECT 327.588 0.000 327.612 0.192 ;
    END
  END pma_tx[77]
  PIN pma_tx[78]
    DIRECTION OUTPUT ;
    USE SIGNAL ;
    SHAPE ABUTMENT ;
    PORT
      LAYER M5 ;
      RECT 331.668 0.000 331.692 0.192 ;
    END
  END pma_tx[78]
  PIN pma_tx[79]
    DIRECTION OUTPUT ;
    USE SIGNAL ;
    SHAPE ABUTMENT ;
    PORT
      LAYER M5 ;
      RECT 335.748 0.000 335.772 0.192 ;
    END
  END pma_tx[79]
  PIN pma_tx[80]
    DIRECTION OUTPUT ;
    USE SIGNAL ;
    SHAPE ABUTMENT ;
    PORT
      LAYER M5 ;
      RECT 339.828 0.000 339.852 0.192 ;
    END
  END pma_tx[80]
  PIN pma_tx[81]
    DIRECTION OUTPUT ;
    USE SIGNAL ;
    SHAPE ABUTMENT ;
    PORT
      LAYER M5 ;
      RECT 343.908 0.000 343.932 0.192 ;
    END
  END pma_tx[81]
  PIN pma_tx[82]
    DIRECTION OUTPUT ;
    USE SIGNAL ;
    SHAPE ABUTMENT ;
    PORT
      LAYER M5 ;
      RECT 347.988 0.000 348.012 0.192 ;
    END
  END pma_tx[82]
  PIN pma_tx[83]
    DIRECTION OUTPUT ;
    USE SIGNAL ;
    SHAPE ABUTMENT ;
    PORT
      LAYER M5 ;
      RECT 352.068 0.000 352.092 0.192 ;
    END
  END pma_tx[83]
  PIN pma_tx[84]
    DIRECTION OUTPUT ;
    USE SIGNAL ;
    SHAPE ABUTMENT ;
    PORT
      LAYER M5 ;
      RECT 356.148 0.000 356.172 0.192 ;
    END
  END pma_tx[84]
  PIN pma_tx[85]
    DIRECTION OUTPUT ;
    USE SIGNAL ;
    SHAPE ABUTMENT ;
    PORT
      LAYER M5 ;
      RECT 360.228 0.000 360.252 0.192 ;
    END
  END pma_tx[85]
  PIN pma_tx[86]
    DIRECTION OUTPUT ;
    USE SIGNAL ;
    SHAPE ABUTMENT ;
    PORT
      LAYER M5 ;
      RECT 364.308 0.000 364.332 0.192 ;
    END
  END pma_tx[86]
  PIN pma_tx[87]
    DIRECTION OUTPUT ;
    USE SIGNAL ;
    SHAPE ABUTMENT ;
    PORT
      LAYER M5 ;
      RECT 368.388 0.000 368.412 0.192 ;
    END
  END pma_tx[87]
  PIN pma_tx[88]
    DIRECTION OUTPUT ;
    USE SIGNAL ;
    SHAPE ABUTMENT ;
    PORT
      LAYER M5 ;
      RECT 372.468 0.000 372.492 0.192 ;
    END
  END pma_tx[88]
  PIN pma_tx[89]
    DIRECTION OUTPUT ;
    USE SIGNAL ;
    SHAPE ABUTMENT ;
    PORT
      LAYER M5 ;
      RECT 376.548 0.000 376.572 0.192 ;
    END
  END pma_tx[89]
  PIN pma_tx[90]
    DIRECTION OUTPUT ;
    USE SIGNAL ;
    SHAPE ABUTMENT ;
    PORT
      LAYER M5 ;
      RECT 380.628 0.000 380.652 0.192 ;
    END
  END pma_tx[90]
  PIN pma_tx[91]
    DIRECTION OUTPUT ;
    USE SIGNAL ;
    SHAPE ABUTMENT ;
    PORT
      LAYER M5 ;
      RECT 384.708 0.000 384.732 0.192 ;
    END
  END pma_tx[91]
  PIN pma_tx[92]
    DIRECTION OUTPUT ;
    USE SIGNAL ;
    SHAPE ABUTMENT ;
    PORT
      LAYER M5 ;
      RECT 388.788 0.000 388.812 0.192 ;
    END
  END pma_tx[92]
  PIN pma_tx[93]
    DIRECTION OUTPUT ;
    USE SIGNAL ;
    SHAPE ABUTMENT ;
    PORT
      LAYER M5 ;
      RECT 392.868 0.000 392.892 0.192 ;
    END
  END pma_tx[93]
  PIN pma_tx[94]
    DIRECTION OUTPUT ;
    USE SIGNAL ;
    SHAPE ABUTMENT ;
    PORT
      LAYER M5 ;
      RECT 396.948 0.000 396.972 0.192 ;
    END
  END pma_tx[94]
  PIN pma_tx[95]
    DIRECTION OUTPUT ;
    USE SIGNAL ;
    SHAPE ABUTMENT ;
    PORT
      LAYER M5 ;
      RECT 401.028 0.000 401.052 0.192 ;
    END
  END pma_tx[95]
  PIN pma_tx[96]
    DIRECTION OUTPUT ;
    USE SIGNAL ;
    SHAPE ABUTMENT ;
    PORT
      LAYER M5 ;
      RECT 405.108 0.000 405.132 0.192 ;
    END
  END pma_tx[96]
  PIN pma_tx[97]
    DIRECTION OUTPUT ;
    USE SIGNAL ;
    SHAPE ABUTMENT ;
    PORT
      LAYER M5 ;
      RECT 409.188 0.000 409.212 0.192 ;
    END
  END pma_tx[97]
  PIN pma_tx[98]
    DIRECTION OUTPUT ;
    USE SIGNAL ;
    SHAPE ABUTMENT ;
    PORT
      LAYER M5 ;
      RECT 413.268 0.000 413.292 0.192 ;
    END
  END pma_tx[98]
  PIN pma_tx[99]
    DIRECTION OUTPUT ;
    USE SIGNAL ;
    SHAPE ABUTMENT ;
    PORT
      LAYER M5 ;
      RECT 417.348 0.000 417.372 0.192 ;
    END
  END pma_tx[99]
  PIN pma_tx[100]
    DIRECTION OUTPUT ;
    USE SIGNAL ;
    SHAPE ABUTMENT ;
    PORT
      LAYER M5 ;
      RECT 421.428 0.000 421.452 0.192 ;
    END
  END pma_tx[100]
  PIN pma_tx[101]
    DIRECTION OUTPUT ;
    USE SIGNAL ;
    SHAPE ABUTMENT ;
    PORT
      LAYER M5 ;
      RECT 425.508 0.000 425.532 0.192 ;
    END
  END pma_tx[101]
  PIN pma_tx[102]
    DIRECTION OUTPUT ;
    USE SIGNAL ;
    SHAPE ABUTMENT ;
    PORT
      LAYER M5 ;
      RECT 429.588 0.000 429.612 0.192 ;
    END
  END pma_tx[102]
  PIN pma_tx[103]
    DIRECTION OUTPUT ;
    USE SIGNAL ;
    SHAPE ABUTMENT ;
    PORT
      LAYER M5 ;
      RECT 433.668 0.000 433.692 0.192 ;
    END
  END pma_tx[103]
  PIN pma_tx[104]
    DIRECTION OUTPUT ;
    USE SIGNAL ;
    SHAPE ABUTMENT ;
    PORT
      LAYER M5 ;
      RECT 437.748 0.000 437.772 0.192 ;
    END
  END pma_tx[104]
  PIN pma_tx[105]
    DIRECTION OUTPUT ;
    USE SIGNAL ;
    SHAPE ABUTMENT ;
    PORT
      LAYER M5 ;
      RECT 441.828 0.000 441.852 0.192 ;
    END
  END pma_tx[105]
  PIN pma_tx[106]
    DIRECTION OUTPUT ;
    USE SIGNAL ;
    SHAPE ABUTMENT ;
    PORT
      LAYER M5 ;
      RECT 445.908 0.000 445.932 0.192 ;
    END
  END pma_tx[106]
  PIN pma_tx[107]
    DIRECTION OUTPUT ;
    USE SIGNAL ;
    SHAPE ABUTMENT ;
    PORT
      LAYER M5 ;
      RECT 449.988 0.000 450.012 0.192 ;
    END
  END pma_tx[107]
  PIN pma_tx[108]
    DIRECTION OUTPUT ;
    USE SIGNAL ;
    SHAPE ABUTMENT ;
    PORT
      LAYER M5 ;
      RECT 454.068 0.000 454.092 0.192 ;
    END
  END pma_tx[108]
  PIN pma_tx[109]
    DIRECTION OUTPUT ;
    USE SIGNAL ;
    SHAPE ABUTMENT ;
    PORT
      LAYER M5 ;
      RECT 458.148 0.000 458.172 0.192 ;
    END
  END pma_tx[109]
  PIN pma_tx[110]
    DIRECTION OUTPUT ;
    USE SIGNAL ;
    SHAPE ABUTMENT ;
    PORT
      LAYER M5 ;
      RECT 462.228 0.000 462.252 0.192 ;
    END
  END pma_tx[110]
  PIN pma_tx[111]
    DIRECTION OUTPUT ;
    USE SIGNAL ;
    SHAPE ABUTMENT ;
    PORT
      LAYER M5 ;
      RECT 466.308 0.000 466.332 0.192 ;
    END
  END pma_tx[111]
  PIN pma_tx[112]
    DIRECTION OUTPUT ;
    USE SIGNAL ;
    SHAPE ABUTMENT ;
    PORT
      LAYER M5 ;
      RECT 470.388 0.000 470.412 0.192 ;
    END
  END pma_tx[112]
  PIN pma_tx[113]
    DIRECTION OUTPUT ;
    USE SIGNAL ;
    SHAPE ABUTMENT ;
    PORT
      LAYER M5 ;
      RECT 474.468 0.000 474.492 0.192 ;
    END
  END pma_tx[113]
  PIN pma_tx[114]
    DIRECTION OUTPUT ;
    USE SIGNAL ;
    SHAPE ABUTMENT ;
    PORT
      LAYER M5 ;
      RECT 478.548 0.000 478.572 0.192 ;
    END
  END pma_tx[114]
  PIN pma_tx[115]
    DIRECTION OUTPUT ;
    USE SIGNAL ;
    SHAPE ABUTMENT ;
    PORT
      LAYER M5 ;
      RECT 482.628 0.000 482.652 0.192 ;
    END
  END pma_tx[115]
  PIN pma_tx[116]
    DIRECTION OUTPUT ;
    USE SIGNAL ;
    SHAPE ABUTMENT ;
    PORT
      LAYER M5 ;
      RECT 486.708 0.000 486.732 0.192 ;
    END
  END pma_tx[116]
  PIN pma_tx[117]
    DIRECTION OUTPUT ;
    USE SIGNAL ;
    SHAPE ABUTMENT ;
    PORT
      LAYER M5 ;
      RECT 490.788 0.000 490.812 0.192 ;
    END
  END pma_tx[117]
  PIN pma_tx[118]
    DIRECTION OUTPUT ;
    USE SIGNAL ;
    SHAPE ABUTMENT ;
    PORT
      LAYER M5 ;
      RECT 494.868 0.000 494.892 0.192 ;
    END
  END pma_tx[118]
  PIN pma_tx[119]
    DIRECTION OUTPUT ;
    USE SIGNAL ;
    SHAPE ABUTMENT ;
    PORT
      LAYER M5 ;
      RECT 498.948 0.000 498.972 0.192 ;
    END
  END pma_tx[119]
  PIN pma_tx[120]
    DIRECTION OUTPUT ;
    USE SIGNAL ;
    SHAPE ABUTMENT ;
    PORT
      LAYER M5 ;
      RECT 503.028 0.000 503.052 0.192 ;
    END
  END pma_tx[120]
  PIN pma_tx[121]
    DIRECTION OUTPUT ;
    USE SIGNAL ;
    SHAPE ABUTMENT ;
    PORT
      LAYER M5 ;
      RECT 507.108 0.000 507.132 0.192 ;
    END
  END pma_tx[121]
  PIN pma_tx[122]
    DIRECTION OUTPUT ;
    USE SIGNAL ;
    SHAPE ABUTMENT ;
    PORT
      LAYER M5 ;
      RECT 511.188 0.000 511.212 0.192 ;
    END
  END pma_tx[122]
  PIN pma_tx[123]
    DIRECTION OUTPUT ;
    USE SIGNAL ;
    SHAPE ABUTMENT ;
    PORT
      LAYER M5 ;
      RECT 515.268 0.000 515.292 0.192 ;
    END
  END pma_tx[123]
  PIN pma_tx[124]
    DIRECTION OUTPUT ;
    USE SIGNAL ;
    SHAPE ABUTMENT ;
    PORT
      LAYER M5 ;
      RECT 519.348 0.000 519.372 0.192 ;
    END
  END pma_tx[124]
  PIN pma_tx[125]
    DIRECTION OUTPUT ;
    USE SIGNAL ;
    SHAPE ABUTMENT ;
    PORT
      LAYER M5 ;
      RECT 523.428 0.000 523.452 0.192 ;
    END
  END pma_tx[125]
  PIN pma_tx[126]
    DIRECTION OUTPUT ;
    USE SIGNAL ;
    SHAPE ABUTMENT ;
    PORT
      LAYER M5 ;
      RECT 527.508 0.000 527.532 0.192 ;
    END
  END pma_tx[126]
  PIN pma_tx[127]
    DIRECTION OUTPUT ;
    USE SIGNAL ;
    SHAPE ABUTMENT ;
    PORT
      LAYER M5 ;
      RECT 531.588 0.000 531.612 0.192 ;
    END
  END pma_tx[127]
  PIN pma_tx[128]
    DIRECTION OUTPUT ;
    USE SIGNAL ;
    SHAPE ABUTMENT ;
    PORT
      LAYER M5 ;
      RECT 535.668 0.000 535.692 0.192 ;
    END
  END pma_tx[128]
  PIN pma_tx[129]
    DIRECTION OUTPUT ;
    USE SIGNAL ;
    SHAPE ABUTMENT ;
    PORT
      LAYER M5 ;
      RECT 539.748 0.000 539.772 0.192 ;
    END
  END pma_tx[129]
  PIN pma_tx[130]
    DIRECTION OUTPUT ;
    USE SIGNAL ;
    SHAPE ABUTMENT ;
    PORT
      LAYER M5 ;
      RECT 543.828 0.000 543.852 0.192 ;
    END
  END pma_tx[130]
  PIN pma_tx[131]
    DIRECTION OUTPUT ;
    USE SIGNAL ;
    SHAPE ABUTMENT ;
    PORT
      LAYER M5 ;
      RECT 547.908 0.000 547.932 0.192 ;
    END
  END pma_tx[131]
  PIN pma_tx[132]
    DIRECTION OUTPUT ;
    USE SIGNAL ;
    SHAPE ABUTMENT ;
    PORT
      LAYER M5 ;
      RECT 551.988 0.000 552.012 0.192 ;
    END
  END pma_tx[132]
  PIN pma_tx[133]
    DIRECTION OUTPUT ;
    USE SIGNAL ;
    SHAPE ABUTMENT ;
    PORT
      LAYER M5 ;
      RECT 556.068 0.000 556.092 0.192 ;
    END
  END pma_tx[133]
  PIN pma_tx[134]
    DIRECTION OUTPUT ;
    USE SIGNAL ;
    SHAPE ABUTMENT ;
    PORT
      LAYER M5 ;
      RECT 560.148 0.000 560.172 0.192 ;
    END
  END pma_tx[134]
  PIN pma_tx[135]
    DIRECTION OUTPUT ;
    USE SIGNAL ;
    SHAPE ABUTMENT ;
    PORT
      LAYER M5 ;
      RECT 564.228 0.000 564.252 0.192 ;
    END
  END pma_tx[135]
  PIN pma_tx[136]
    DIRECTION OUTPUT ;
    USE SIGNAL ;
    SHAPE ABUTMENT ;
    PORT
      LAYER M5 ;
      RECT 568.308 0.000 568.332 0.192 ;
    END
  END pma_tx[136]
  PIN pma_tx[137]
    DIRECTION OUTPUT ;
    USE SIGNAL ;
    SHAPE ABUTMENT ;
    PORT
      LAYER M5 ;
      RECT 572.388 0.000 572.412 0.192 ;
    END
  END pma_tx[137]
  PIN pma_tx[138]
    DIRECTION OUTPUT ;
    USE SIGNAL ;
    SHAPE ABUTMENT ;
    PORT
      LAYER M5 ;
      RECT 576.468 0.000 576.492 0.192 ;
    END
  END pma_tx[138]
  PIN pma_tx[139]
    DIRECTION OUTPUT ;
    USE SIGNAL ;
    SHAPE ABUTMENT ;
    PORT
      LAYER M5 ;
      RECT 580.548 0.000 580.572 0.192 ;
    END
  END pma_tx[139]
  PIN pma_tx[140]
    DIRECTION OUTPUT ;
    USE SIGNAL ;
    SHAPE ABUTMENT ;
    PORT
      LAYER M5 ;
      RECT 584.628 0.000 584.652 0.192 ;
    END
  END pma_tx[140]
  PIN pma_tx[141]
    DIRECTION OUTPUT ;
    USE SIGNAL ;
    SHAPE ABUTMENT ;
    PORT
      LAYER M5 ;
      RECT 588.708 0.000 588.732 0.192 ;
    END
  END pma_tx[141]
  PIN pma_tx[142]
    DIRECTION OUTPUT ;
    USE SIGNAL ;
    SHAPE ABUTMENT ;
    PORT
      LAYER M5 ;
      RECT 592.788 0.000 592.812 0.192 ;
    END
  END pma_tx[142]
  PIN pma_tx[143]
    DIRECTION OUTPUT ;
    USE SIGNAL ;
    SHAPE ABUTMENT ;
    PORT
      LAYER M5 ;
      RECT 596.868 0.000 596.892 0.192 ;
    END
  END pma_tx[143]
  PIN pma_tx[144]
    DIRECTION OUTPUT ;
    USE SIGNAL ;
    SHAPE ABUTMENT ;
    PORT
      LAYER M5 ;
      RECT 600.948 0.000 600.972 0.192 ;
    END
  END pma_tx[144]
  PIN pma_tx[145]
    DIRECTION OUTPUT ;
    USE SIGNAL ;
    SHAPE ABUTMENT ;
    PORT
      LAYER M5 ;
      RECT 605.028 0.000 605.052 0.192 ;
    END
  END pma_tx[145]
  PIN pma_tx[146]
    DIRECTION OUTPUT ;
    USE SIGNAL ;
    SHAPE ABUTMENT ;
    PORT
      LAYER M5 ;
      RECT 609.108 0.000 609.132 0.192 ;
    END
  END pma_tx[146]
  PIN pma_tx[147]
    DIRECTION OUTPUT ;
    USE SIGNAL ;
    SHAPE ABUTMENT ;
    PORT
      LAYER M5 ;
      RECT 613.188 0.000 613.212 0.192 ;
    END
  END pma_tx[147]
  PIN pma_tx[148]
    DIRECTION OUTPUT ;
    USE SIGNAL ;
    SHAPE ABUTMENT ;
    PORT
      LAYER M5 ;
      RECT 617.268 0.000 617.292 0.192 ;
    END
  END pma_tx[148]
  PIN pma_tx[149]
    DIRECTION OUTPUT ;
    USE SIGNAL ;
    SHAPE ABUTMENT ;
    PORT
      LAYER M5 ;
      RECT 621.348 0.000 621.372 0.192 ;
    END
  END pma_tx[149]
  PIN pma_tx[150]
    DIRECTION OUTPUT ;
    USE SIGNAL ;
    SHAPE ABUTMENT ;
    PORT
      LAYER M5 ;
      RECT 625.428 0.000 625.452 0.192 ;
    END
  END pma_tx[150]
  PIN pma_tx[151]
    DIRECTION OUTPUT ;
    USE SIGNAL ;
    SHAPE ABUTMENT ;
    PORT
      LAYER M5 ;
      RECT 629.508 0.000 629.532 0.192 ;
    END
  END pma_tx[151]
  PIN pma_tx[152]
    DIRECTION OUTPUT ;
    USE SIGNAL ;
    SHAPE ABUTMENT ;
    PORT
      LAYER M5 ;
      RECT 633.588 0.000 633.612 0.192 ;
    END
  END pma_tx[152]
  PIN pma_tx[153]
    DIRECTION OUTPUT ;
    USE SIGNAL ;
    SHAPE ABUTMENT ;
    PORT
      LAYER M5 ;
      RECT 637.668 0.000 637.692 0.192 ;
    END
  END pma_tx[153]
  PIN pma_tx[154]
    DIRECTION OUTPUT ;
    USE SIGNAL ;
    SHAPE ABUTMENT ;
    PORT
      LAYER M5 ;
      RECT 641.748 0.000 641.772 0.192 ;
    END
  END pma_tx[154]
  PIN pma_tx[155]
    DIRECTION OUTPUT ;
    USE SIGNAL ;
    SHAPE ABUTMENT ;
    PORT
      LAYER M5 ;
      RECT 645.828 0.000 645.852 0.192 ;
    END
  END pma_tx[155]
  PIN pma_tx[156]
    DIRECTION OUTPUT ;
    USE SIGNAL ;
    SHAPE ABUTMENT ;
    PORT
      LAYER M5 ;
      RECT 649.908 0.000 649.932 0.192 ;
    END
  END pma_tx[156]
  PIN pma_tx[157]
    DIRECTION OUTPUT ;
    USE SIGNAL ;
    SHAPE ABUTMENT ;
    PORT
      LAYER M5 ;
      RECT 653.988 0.000 654.012 0.192 ;
    END
  END pma_tx[157]
  PIN pma_tx[158]
    DIRECTION OUTPUT ;
    USE SIGNAL ;
    SHAPE ABUTMENT ;
    PORT
      LAYER M5 ;
      RECT 658.068 0.000 658.092 0.192 ;
    END
  END pma_tx[158]
  PIN pma_tx[159]
    DIRECTION OUTPUT ;
    USE SIGNAL ;
    SHAPE ABUTMENT ;
    PORT
      LAYER M5 ;
      RECT 662.148 0.000 662.172 0.192 ;
    END
  END pma_tx[159]
  PIN pma_tx[160]
    DIRECTION OUTPUT ;
    USE SIGNAL ;
    SHAPE ABUTMENT ;
    PORT
      LAYER M5 ;
      RECT 666.228 0.000 666.252 0.192 ;
    END
  END pma_tx[160]
  PIN pma_tx[161]
    DIRECTION OUTPUT ;
    USE SIGNAL ;
    SHAPE ABUTMENT ;
    PORT
      LAYER M5 ;
      RECT 670.308 0.000 670.332 0.192 ;
    END
  END pma_tx[161]
  PIN pma_tx[162]
    DIRECTION OUTPUT ;
    USE SIGNAL ;
    SHAPE ABUTMENT ;
    PORT
      LAYER M5 ;
      RECT 674.388 0.000 674.412 0.192 ;
    END
  END pma_tx[162]
  PIN pma_tx[163]
    DIRECTION OUTPUT ;
    USE SIGNAL ;
    SHAPE ABUTMENT ;
    PORT
      LAYER M5 ;
      RECT 678.468 0.000 678.492 0.192 ;
    END
  END pma_tx[163]
  PIN pma_tx[164]
    DIRECTION OUTPUT ;
    USE SIGNAL ;
    SHAPE ABUTMENT ;
    PORT
      LAYER M5 ;
      RECT 682.548 0.000 682.572 0.192 ;
    END
  END pma_tx[164]
  PIN pma_tx[165]
    DIRECTION OUTPUT ;
    USE SIGNAL ;
    SHAPE ABUTMENT ;
    PORT
      LAYER M5 ;
      RECT 686.628 0.000 686.652 0.192 ;
    END
  END pma_tx[165]
  PIN pma_tx[166]
    DIRECTION OUTPUT ;
    USE SIGNAL ;
    SHAPE ABUTMENT ;
    PORT
      LAYER M5 ;
      RECT 690.708 0.000 690.732 0.192 ;
    END
  END pma_tx[166]
  PIN pma_tx[167]
    DIRECTION OUTPUT ;
    USE SIGNAL ;
    SHAPE ABUTMENT ;
    PORT
      LAYER M5 ;
      RECT 694.788 0.000 694.812 0.192 ;
    END
  END pma_tx[167]
  PIN pma_tx[168]
    DIRECTION OUTPUT ;
    USE SIGNAL ;
    SHAPE ABUTMENT ;
    PORT
      LAYER M5 ;
      RECT 698.868 0.000 698.892 0.192 ;
    END
  END pma_tx[168]
  PIN pma_tx[169]
    DIRECTION OUTPUT ;
    USE SIGNAL ;
    SHAPE ABUTMENT ;
    PORT
      LAYER M5 ;
      RECT 702.948 0.000 702.972 0.192 ;
    END
  END pma_tx[169]
  PIN pma_tx[170]
    DIRECTION OUTPUT ;
    USE SIGNAL ;
    SHAPE ABUTMENT ;
    PORT
      LAYER M5 ;
      RECT 707.028 0.000 707.052 0.192 ;
    END
  END pma_tx[170]
  PIN pma_tx[171]
    DIRECTION OUTPUT ;
    USE SIGNAL ;
    SHAPE ABUTMENT ;
    PORT
      LAYER M5 ;
      RECT 711.108 0.000 711.132 0.192 ;
    END
  END pma_tx[171]
  PIN pma_tx[172]
    DIRECTION OUTPUT ;
    USE SIGNAL ;
    SHAPE ABUTMENT ;
    PORT
      LAYER M5 ;
      RECT 715.188 0.000 715.212 0.192 ;
    END
  END pma_tx[172]
  PIN pma_tx[173]
    DIRECTION OUTPUT ;
    USE SIGNAL ;
    SHAPE ABUTMENT ;
    PORT
      LAYER M5 ;
      RECT 719.268 0.000 719.292 0.192 ;
    END
  END pma_tx[173]
  PIN pma_tx[174]
    DIRECTION OUTPUT ;
    USE SIGNAL ;
    SHAPE ABUTMENT ;
    PORT
      LAYER M5 ;
      RECT 723.348 0.000 723.372 0.192 ;
    END
  END pma_tx[174]
  PIN pma_tx[175]
    DIRECTION OUTPUT ;
    USE SIGNAL ;
    SHAPE ABUTMENT ;
    PORT
      LAYER M5 ;
      RECT 727.428 0.000 727.452 0.192 ;
    END
  END pma_tx[175]
  PIN pma_tx[176]
    DIRECTION OUTPUT ;
    USE SIGNAL ;
    SHAPE ABUTMENT ;
    PORT
      LAYER M5 ;
      RECT 731.508 0.000 731.532 0.192 ;
    END
  END pma_tx[176]
  PIN pma_tx[177]
    DIRECTION OUTPUT ;
    USE SIGNAL ;
    SHAPE ABUTMENT ;
    PORT
      LAYER M5 ;
      RECT 735.588 0.000 735.612 0.192 ;
    END
  END pma_tx[177]
  PIN pma_tx[178]
    DIRECTION OUTPUT ;
    USE SIGNAL ;
    SHAPE ABUTMENT ;
    PORT
      LAYER M5 ;
      RECT 739.668 0.000 739.692 0.192 ;
    END
  END pma_tx[178]
  PIN pma_tx[179]
    DIRECTION OUTPUT ;
    USE SIGNAL ;
    SHAPE ABUTMENT ;
    PORT
      LAYER M5 ;
      RECT 743.748 0.000 743.772 0.192 ;
    END
  END pma_tx[179]
  PIN pma_tx[180]
    DIRECTION OUTPUT ;
    USE SIGNAL ;
    SHAPE ABUTMENT ;
    PORT
      LAYER M5 ;
      RECT 747.828 0.000 747.852 0.192 ;
    END
  END pma_tx[180]
  PIN pma_tx[181]
    DIRECTION OUTPUT ;
    USE SIGNAL ;
    SHAPE ABUTMENT ;
    PORT
      LAYER M5 ;
      RECT 751.908 0.000 751.932 0.192 ;
    END
  END pma_tx[181]
  PIN pma_tx[182]
    DIRECTION OUTPUT ;
    USE SIGNAL ;
    SHAPE ABUTMENT ;
    PORT
      LAYER M5 ;
      RECT 755.988 0.000 756.012 0.192 ;
    END
  END pma_tx[182]
  PIN pma_tx[183]
    DIRECTION OUTPUT ;
    USE SIGNAL ;
    SHAPE ABUTMENT ;
    PORT
      LAYER M5 ;
      RECT 760.068 0.000 760.092 0.192 ;
    END
  END pma_tx[183]
  PIN pma_tx[184]
    DIRECTION OUTPUT ;
    USE SIGNAL ;
    SHAPE ABUTMENT ;
    PORT
      LAYER M5 ;
      RECT 764.148 0.000 764.172 0.192 ;
    END
  END pma_tx[184]
  PIN pma_tx[185]
    DIRECTION OUTPUT ;
    USE SIGNAL ;
    SHAPE ABUTMENT ;
    PORT
      LAYER M5 ;
      RECT 768.228 0.000 768.252 0.192 ;
    END
  END pma_tx[185]
  PIN pma_tx[186]
    DIRECTION OUTPUT ;
    USE SIGNAL ;
    SHAPE ABUTMENT ;
    PORT
      LAYER M5 ;
      RECT 772.308 0.000 772.332 0.192 ;
    END
  END pma_tx[186]
  PIN pma_tx[187]
    DIRECTION OUTPUT ;
    USE SIGNAL ;
    SHAPE ABUTMENT ;
    PORT
      LAYER M5 ;
      RECT 776.388 0.000 776.412 0.192 ;
    END
  END pma_tx[187]
  PIN pma_tx[188]
    DIRECTION OUTPUT ;
    USE SIGNAL ;
    SHAPE ABUTMENT ;
    PORT
      LAYER M5 ;
      RECT 780.468 0.000 780.492 0.192 ;
    END
  END pma_tx[188]
  PIN pma_tx[189]
    DIRECTION OUTPUT ;
    USE SIGNAL ;
    SHAPE ABUTMENT ;
    PORT
      LAYER M5 ;
      RECT 784.548 0.000 784.572 0.192 ;
    END
  END pma_tx[189]
  PIN pma_tx[190]
    DIRECTION OUTPUT ;
    USE SIGNAL ;
    SHAPE ABUTMENT ;
    PORT
      LAYER M5 ;
      RECT 788.628 0.000 788.652 0.192 ;
    END
  END pma_tx[190]
  PIN pma_tx[191]
    DIRECTION OUTPUT ;
    USE SIGNAL ;
    SHAPE ABUTMENT ;
    PORT
      LAYER M5 ;
      RECT 792.708 0.000 792.732 0.192 ;
    END
  END pma_tx[191]
  PIN pma_tx[192]
    DIRECTION OUTPUT ;
    USE SIGNAL ;
    SHAPE ABUTMENT ;
    PORT
      LAYER M5 ;
      RECT 796.788 0.000 796.812 0.192 ;
    END
  END pma_tx[192]
  PIN pma_tx[193]
    DIRECTION OUTPUT ;
    USE SIGNAL ;
    SHAPE ABUTMENT ;
    PORT
      LAYER M5 ;
      RECT 800.868 0.000 800.892 0.192 ;
    END
  END pma_tx[193]
  PIN pma_tx[194]
    DIRECTION OUTPUT ;
    USE SIGNAL ;
    SHAPE ABUTMENT ;
    PORT
      LAYER M5 ;
      RECT 804.948 0.000 804.972 0.192 ;
    END
  END pma_tx[194]
  PIN pma_tx[195]
    DIRECTION OUTPUT ;
    USE SIGNAL ;
    SHAPE ABUTMENT ;
    PORT
      LAYER M5 ;
      RECT 809.028 0.000 809.052 0.192 ;
    END
  END pma_tx[195]
  PIN pma_tx[196]
    DIRECTION OUTPUT ;
    USE SIGNAL ;
    SHAPE ABUTMENT ;
    PORT
      LAYER M5 ;
      RECT 813.108 0.000 813.132 0.192 ;
    END
  END pma_tx[196]
  PIN pma_tx[197]
    DIRECTION OUTPUT ;
    USE SIGNAL ;
    SHAPE ABUTMENT ;
    PORT
      LAYER M5 ;
      RECT 817.188 0.000 817.212 0.192 ;
    END
  END pma_tx[197]
  PIN pma_tx[198]
    DIRECTION OUTPUT ;
    USE SIGNAL ;
    SHAPE ABUTMENT ;
    PORT
      LAYER M5 ;
      RECT 821.268 0.000 821.292 0.192 ;
    END
  END pma_tx[198]
  PIN pma_tx[199]
    DIRECTION OUTPUT ;
    USE SIGNAL ;
    SHAPE ABUTMENT ;
    PORT
      LAYER M5 ;
      RECT 825.348 0.000 825.372 0.192 ;
    END
  END pma_tx[199]
  PIN pma_tx[200]
    DIRECTION OUTPUT ;
    USE SIGNAL ;
    SHAPE ABUTMENT ;
    PORT
      LAYER M5 ;
      RECT 829.428 0.000 829.452 0.192 ;
    END
  END pma_tx[200]
  PIN pma_tx[201]
    DIRECTION OUTPUT ;
    USE SIGNAL ;
    SHAPE ABUTMENT ;
    PORT
      LAYER M5 ;
      RECT 833.508 0.000 833.532 0.192 ;
    END
  END pma_tx[201]
  PIN pma_tx[202]
    DIRECTION OUTPUT ;
    USE SIGNAL ;
    SHAPE ABUTMENT ;
    PORT
      LAYER M5 ;
      RECT 837.588 0.000 837.612 0.192 ;
    END
  END pma_tx[202]
  PIN pma_tx[203]
    DIRECTION OUTPUT ;
    USE SIGNAL ;
    SHAPE ABUTMENT ;
    PORT
      LAYER M5 ;
      RECT 841.668 0.000 841.692 0.192 ;
    END
  END pma_tx[203]
  PIN pma_tx[204]
    DIRECTION OUTPUT ;
    USE SIGNAL ;
    SHAPE ABUTMENT ;
    PORT
      LAYER M5 ;
      RECT 845.748 0.000 845.772 0.192 ;
    END
  END pma_tx[204]
  PIN pma_tx[205]
    DIRECTION OUTPUT ;
    USE SIGNAL ;
    SHAPE ABUTMENT ;
    PORT
      LAYER M5 ;
      RECT 849.828 0.000 849.852 0.192 ;
    END
  END pma_tx[205]
  PIN pma_tx[206]
    DIRECTION OUTPUT ;
    USE SIGNAL ;
    SHAPE ABUTMENT ;
    PORT
      LAYER M5 ;
      RECT 853.908 0.000 853.932 0.192 ;
    END
  END pma_tx[206]
  PIN pma_tx[207]
    DIRECTION OUTPUT ;
    USE SIGNAL ;
    SHAPE ABUTMENT ;
    PORT
      LAYER M5 ;
      RECT 857.988 0.000 858.012 0.192 ;
    END
  END pma_tx[207]
  PIN pma_tx[208]
    DIRECTION OUTPUT ;
    USE SIGNAL ;
    SHAPE ABUTMENT ;
    PORT
      LAYER M5 ;
      RECT 862.068 0.000 862.092 0.192 ;
    END
  END pma_tx[208]
  PIN pma_tx[209]
    DIRECTION OUTPUT ;
    USE SIGNAL ;
    SHAPE ABUTMENT ;
    PORT
      LAYER M5 ;
      RECT 866.148 0.000 866.172 0.192 ;
    END
  END pma_tx[209]
  PIN pma_tx[210]
    DIRECTION OUTPUT ;
    USE SIGNAL ;
    SHAPE ABUTMENT ;
    PORT
      LAYER M5 ;
      RECT 870.228 0.000 870.252 0.192 ;
    END
  END pma_tx[210]
  PIN pma_tx[211]
    DIRECTION OUTPUT ;
    USE SIGNAL ;
    SHAPE ABUTMENT ;
    PORT
      LAYER M5 ;
      RECT 874.308 0.000 874.332 0.192 ;
    END
  END pma_tx[211]
  PIN pma_tx[212]
    DIRECTION OUTPUT ;
    USE SIGNAL ;
    SHAPE ABUTMENT ;
    PORT
      LAYER M5 ;
      RECT 878.388 0.000 878.412 0.192 ;
    END
  END pma_tx[212]
  PIN pma_tx[213]
    DIRECTION OUTPUT ;
    USE SIGNAL ;
    SHAPE ABUTMENT ;
    PORT
      LAYER M5 ;
      RECT 882.468 0.000 882.492 0.192 ;
    END
  END pma_tx[213]
  PIN pma_tx[214]
    DIRECTION OUTPUT ;
    USE SIGNAL ;
    SHAPE ABUTMENT ;
    PORT
      LAYER M5 ;
      RECT 886.548 0.000 886.572 0.192 ;
    END
  END pma_tx[214]
  PIN pma_tx[215]
    DIRECTION OUTPUT ;
    USE SIGNAL ;
    SHAPE ABUTMENT ;
    PORT
      LAYER M5 ;
      RECT 890.628 0.000 890.652 0.192 ;
    END
  END pma_tx[215]
  PIN pma_tx[216]
    DIRECTION OUTPUT ;
    USE SIGNAL ;
    SHAPE ABUTMENT ;
    PORT
      LAYER M5 ;
      RECT 894.708 0.000 894.732 0.192 ;
    END
  END pma_tx[216]
  PIN pma_tx[217]
    DIRECTION OUTPUT ;
    USE SIGNAL ;
    SHAPE ABUTMENT ;
    PORT
      LAYER M5 ;
      RECT 898.788 0.000 898.812 0.192 ;
    END
  END pma_tx[217]
  PIN pma_tx[218]
    DIRECTION OUTPUT ;
    USE SIGNAL ;
    SHAPE ABUTMENT ;
    PORT
      LAYER M5 ;
      RECT 902.868 0.000 902.892 0.192 ;
    END
  END pma_tx[218]
  PIN pma_tx[219]
    DIRECTION OUTPUT ;
    USE SIGNAL ;
    SHAPE ABUTMENT ;
    PORT
      LAYER M5 ;
      RECT 906.948 0.000 906.972 0.192 ;
    END
  END pma_tx[219]
  PIN pma_tx[220]
    DIRECTION OUTPUT ;
    USE SIGNAL ;
    SHAPE ABUTMENT ;
    PORT
      LAYER M5 ;
      RECT 911.028 0.000 911.052 0.192 ;
    END
  END pma_tx[220]
  PIN pma_tx[221]
    DIRECTION OUTPUT ;
    USE SIGNAL ;
    SHAPE ABUTMENT ;
    PORT
      LAYER M5 ;
      RECT 915.108 0.000 915.132 0.192 ;
    END
  END pma_tx[221]
  PIN pma_tx[222]
    DIRECTION OUTPUT ;
    USE SIGNAL ;
    SHAPE ABUTMENT ;
    PORT
      LAYER M5 ;
      RECT 919.188 0.000 919.212 0.192 ;
    END
  END pma_tx[222]
  PIN pma_tx[223]
    DIRECTION OUTPUT ;
    USE SIGNAL ;
    SHAPE ABUTMENT ;
    PORT
      LAYER M5 ;
      RECT 923.268 0.000 923.292 0.192 ;
    END
  END pma_tx[223]
  PIN pma_tx[224]
    DIRECTION OUTPUT ;
    USE SIGNAL ;
    SHAPE ABUTMENT ;
    PORT
      LAYER M5 ;
      RECT 927.348 0.000 927.372 0.192 ;
    END
  END pma_tx[224]
  PIN pma_tx[225]
    DIRECTION OUTPUT ;
    USE SIGNAL ;
    SHAPE ABUTMENT ;
    PORT
      LAYER M5 ;
      RECT 931.428 0.000 931.452 0.192 ;
    END
  END pma_tx[225]
  PIN pma_tx[226]
    DIRECTION OUTPUT ;
    USE SIGNAL ;
    SHAPE ABUTMENT ;
    PORT
      LAYER M5 ;
      RECT 935.508 0.000 935.532 0.192 ;
    END
  END pma_tx[226]
  PIN pma_tx[227]
    DIRECTION OUTPUT ;
    USE SIGNAL ;
    SHAPE ABUTMENT ;
    PORT
      LAYER M5 ;
      RECT 939.588 0.000 939.612 0.192 ;
    END
  END pma_tx[227]
  PIN pma_tx[228]
    DIRECTION OUTPUT ;
    USE SIGNAL ;
    SHAPE ABUTMENT ;
    PORT
      LAYER M5 ;
      RECT 943.668 0.000 943.692 0.192 ;
    END
  END pma_tx[228]
  PIN pma_tx[229]
    DIRECTION OUTPUT ;
    USE SIGNAL ;
    SHAPE ABUTMENT ;
    PORT
      LAYER M5 ;
      RECT 947.748 0.000 947.772 0.192 ;
    END
  END pma_tx[229]
  PIN pma_tx[230]
    DIRECTION OUTPUT ;
    USE SIGNAL ;
    SHAPE ABUTMENT ;
    PORT
      LAYER M5 ;
      RECT 951.828 0.000 951.852 0.192 ;
    END
  END pma_tx[230]
  PIN pma_tx[231]
    DIRECTION OUTPUT ;
    USE SIGNAL ;
    SHAPE ABUTMENT ;
    PORT
      LAYER M5 ;
      RECT 955.908 0.000 955.932 0.192 ;
    END
  END pma_tx[231]
  PIN pma_tx[232]
    DIRECTION OUTPUT ;
    USE SIGNAL ;
    SHAPE ABUTMENT ;
    PORT
      LAYER M5 ;
      RECT 959.988 0.000 960.012 0.192 ;
    END
  END pma_tx[232]
  PIN pma_tx[233]
    DIRECTION OUTPUT ;
    USE SIGNAL ;
    SHAPE ABUTMENT ;
    PORT
      LAYER M5 ;
      RECT 964.068 0.000 964.092 0.192 ;
    END
  END pma_tx[233]
  PIN pma_tx[234]
    DIRECTION OUTPUT ;
    USE SIGNAL ;
    SHAPE ABUTMENT ;
    PORT
      LAYER M5 ;
      RECT 968.148 0.000 968.172 0.192 ;
    END
  END pma_tx[234]
  PIN pma_tx[235]
    DIRECTION OUTPUT ;
    USE SIGNAL ;
    SHAPE ABUTMENT ;
    PORT
      LAYER M5 ;
      RECT 972.228 0.000 972.252 0.192 ;
    END
  END pma_tx[235]
  PIN pma_tx[236]
    DIRECTION OUTPUT ;
    USE SIGNAL ;
    SHAPE ABUTMENT ;
    PORT
      LAYER M5 ;
      RECT 976.308 0.000 976.332 0.192 ;
    END
  END pma_tx[236]
  PIN pma_tx[237]
    DIRECTION OUTPUT ;
    USE SIGNAL ;
    SHAPE ABUTMENT ;
    PORT
      LAYER M5 ;
      RECT 980.388 0.000 980.412 0.192 ;
    END
  END pma_tx[237]
  PIN pma_tx[238]
    DIRECTION OUTPUT ;
    USE SIGNAL ;
    SHAPE ABUTMENT ;
    PORT
      LAYER M5 ;
      RECT 984.468 0.000 984.492 0.192 ;
    END
  END pma_tx[238]
  PIN pma_tx[239]
    DIRECTION OUTPUT ;
    USE SIGNAL ;
    SHAPE ABUTMENT ;
    PORT
      LAYER M5 ;
      RECT 988.548 0.000 988.572 0.192 ;
    END
  END pma_tx[239]
  PIN pma_tx[240]
    DIRECTION OUTPUT ;
    USE SIGNAL ;
    SHAPE ABUTMENT ;
    PORT
      LAYER M5 ;
      RECT 992.628 0.000 992.652 0.192 ;
    END
  END pma_tx[240]
  PIN pma_tx[241]
    DIRECTION OUTPUT ;
    USE SIGNAL ;
    SHAPE ABUTMENT ;
    PORT
      LAYER M5 ;
      RECT 996.708 0.000 996.732 0.192 ;
    END
  END pma_tx[241]
  PIN pma_tx[242]
    DIRECTION OUTPUT ;
    USE SIGNAL ;
    SHAPE ABUTMENT ;
    PORT
      LAYER M5 ;
      RECT 1000.788 0.000 1000.812 0.192 ;
    END
  END pma_tx[242]
  PIN pma_tx[243]
    DIRECTION OUTPUT ;
    USE SIGNAL ;
    SHAPE ABUTMENT ;
    PORT
      LAYER M5 ;
      RECT 1004.868 0.000 1004.892 0.192 ;
    END
  END pma_tx[243]
  PIN pma_tx[244]
    DIRECTION OUTPUT ;
    USE SIGNAL ;
    SHAPE ABUTMENT ;
    PORT
      LAYER M5 ;
      RECT 1008.948 0.000 1008.972 0.192 ;
    END
  END pma_tx[244]
  PIN pma_tx[245]
    DIRECTION OUTPUT ;
    USE SIGNAL ;
    SHAPE ABUTMENT ;
    PORT
      LAYER M5 ;
      RECT 1013.028 0.000 1013.052 0.192 ;
    END
  END pma_tx[245]
  PIN pma_tx[246]
    DIRECTION OUTPUT ;
    USE SIGNAL ;
    SHAPE ABUTMENT ;
    PORT
      LAYER M5 ;
      RECT 1017.108 0.000 1017.132 0.192 ;
    END
  END pma_tx[246]
  PIN pma_tx[247]
    DIRECTION OUTPUT ;
    USE SIGNAL ;
    SHAPE ABUTMENT ;
    PORT
      LAYER M5 ;
      RECT 1021.188 0.000 1021.212 0.192 ;
    END
  END pma_tx[247]
  PIN pma_tx[248]
    DIRECTION OUTPUT ;
    USE SIGNAL ;
    SHAPE ABUTMENT ;
    PORT
      LAYER M5 ;
      RECT 1025.268 0.000 1025.292 0.192 ;
    END
  END pma_tx[248]
  PIN pma_tx[249]
    DIRECTION OUTPUT ;
    USE SIGNAL ;
    SHAPE ABUTMENT ;
    PORT
      LAYER M5 ;
      RECT 1029.348 0.000 1029.372 0.192 ;
    END
  END pma_tx[249]
  PIN pma_tx[250]
    DIRECTION OUTPUT ;
    USE SIGNAL ;
    SHAPE ABUTMENT ;
    PORT
      LAYER M5 ;
      RECT 1033.428 0.000 1033.452 0.192 ;
    END
  END pma_tx[250]
  PIN pma_tx[251]
    DIRECTION OUTPUT ;
    USE SIGNAL ;
    SHAPE ABUTMENT ;
    PORT
      LAYER M5 ;
      RECT 1037.508 0.000 1037.532 0.192 ;
    END
  END pma_tx[251]
  PIN pma_tx[252]
    DIRECTION OUTPUT ;
    USE SIGNAL ;
    SHAPE ABUTMENT ;
    PORT
      LAYER M5 ;
      RECT 1041.588 0.000 1041.612 0.192 ;
    END
  END pma_tx[252]
  PIN pma_tx[253]
    DIRECTION OUTPUT ;
    USE SIGNAL ;
    SHAPE ABUTMENT ;
    PORT
      LAYER M5 ;
      RECT 1045.668 0.000 1045.692 0.192 ;
    END
  END pma_tx[253]
  PIN pma_tx[254]
    DIRECTION OUTPUT ;
    USE SIGNAL ;
    SHAPE ABUTMENT ;
    PORT
      LAYER M5 ;
      RECT 1049.748 0.000 1049.772 0.192 ;
    END
  END pma_tx[254]
  PIN pma_tx[255]
    DIRECTION OUTPUT ;
    USE SIGNAL ;
    SHAPE ABUTMENT ;
    PORT
      LAYER M5 ;
      RECT 1053.828 0.000 1053.852 0.192 ;
    END
  END pma_tx[255]
  PIN pma_tx[256]
    DIRECTION OUTPUT ;
    USE SIGNAL ;
    SHAPE ABUTMENT ;
    PORT
      LAYER M5 ;
      RECT 1057.908 0.000 1057.932 0.192 ;
    END
  END pma_tx[256]
  PIN pma_tx[257]
    DIRECTION OUTPUT ;
    USE SIGNAL ;
    SHAPE ABUTMENT ;
    PORT
      LAYER M5 ;
      RECT 1061.988 0.000 1062.012 0.192 ;
    END
  END pma_tx[257]
  PIN pma_tx[258]
    DIRECTION OUTPUT ;
    USE SIGNAL ;
    SHAPE ABUTMENT ;
    PORT
      LAYER M5 ;
      RECT 1066.068 0.000 1066.092 0.192 ;
    END
  END pma_tx[258]
  PIN pma_tx[259]
    DIRECTION OUTPUT ;
    USE SIGNAL ;
    SHAPE ABUTMENT ;
    PORT
      LAYER M5 ;
      RECT 1070.148 0.000 1070.172 0.192 ;
    END
  END pma_tx[259]
  PIN pma_tx[260]
    DIRECTION OUTPUT ;
    USE SIGNAL ;
    SHAPE ABUTMENT ;
    PORT
      LAYER M5 ;
      RECT 1074.228 0.000 1074.252 0.192 ;
    END
  END pma_tx[260]
  PIN pma_tx[261]
    DIRECTION OUTPUT ;
    USE SIGNAL ;
    SHAPE ABUTMENT ;
    PORT
      LAYER M5 ;
      RECT 1078.308 0.000 1078.332 0.192 ;
    END
  END pma_tx[261]
  PIN pma_tx[262]
    DIRECTION OUTPUT ;
    USE SIGNAL ;
    SHAPE ABUTMENT ;
    PORT
      LAYER M5 ;
      RECT 1082.388 0.000 1082.412 0.192 ;
    END
  END pma_tx[262]
  PIN pma_tx[263]
    DIRECTION OUTPUT ;
    USE SIGNAL ;
    SHAPE ABUTMENT ;
    PORT
      LAYER M5 ;
      RECT 1086.468 0.000 1086.492 0.192 ;
    END
  END pma_tx[263]
  PIN pma_tx[264]
    DIRECTION OUTPUT ;
    USE SIGNAL ;
    SHAPE ABUTMENT ;
    PORT
      LAYER M5 ;
      RECT 1090.548 0.000 1090.572 0.192 ;
    END
  END pma_tx[264]
  PIN pma_tx[265]
    DIRECTION OUTPUT ;
    USE SIGNAL ;
    SHAPE ABUTMENT ;
    PORT
      LAYER M5 ;
      RECT 1094.628 0.000 1094.652 0.192 ;
    END
  END pma_tx[265]
  PIN pma_tx[266]
    DIRECTION OUTPUT ;
    USE SIGNAL ;
    SHAPE ABUTMENT ;
    PORT
      LAYER M5 ;
      RECT 1098.708 0.000 1098.732 0.192 ;
    END
  END pma_tx[266]
  PIN pma_tx[267]
    DIRECTION OUTPUT ;
    USE SIGNAL ;
    SHAPE ABUTMENT ;
    PORT
      LAYER M5 ;
      RECT 1102.788 0.000 1102.812 0.192 ;
    END
  END pma_tx[267]
  PIN pma_tx[268]
    DIRECTION OUTPUT ;
    USE SIGNAL ;
    SHAPE ABUTMENT ;
    PORT
      LAYER M5 ;
      RECT 1106.868 0.000 1106.892 0.192 ;
    END
  END pma_tx[268]
  PIN pma_tx[269]
    DIRECTION OUTPUT ;
    USE SIGNAL ;
    SHAPE ABUTMENT ;
    PORT
      LAYER M5 ;
      RECT 1110.948 0.000 1110.972 0.192 ;
    END
  END pma_tx[269]
  PIN pma_tx[270]
    DIRECTION OUTPUT ;
    USE SIGNAL ;
    SHAPE ABUTMENT ;
    PORT
      LAYER M5 ;
      RECT 1115.028 0.000 1115.052 0.192 ;
    END
  END pma_tx[270]
  PIN pma_tx[271]
    DIRECTION OUTPUT ;
    USE SIGNAL ;
    SHAPE ABUTMENT ;
    PORT
      LAYER M5 ;
      RECT 1119.108 0.000 1119.132 0.192 ;
    END
  END pma_tx[271]
  PIN pma_tx[272]
    DIRECTION OUTPUT ;
    USE SIGNAL ;
    SHAPE ABUTMENT ;
    PORT
      LAYER M5 ;
      RECT 1123.188 0.000 1123.212 0.192 ;
    END
  END pma_tx[272]
  PIN pma_tx[273]
    DIRECTION OUTPUT ;
    USE SIGNAL ;
    SHAPE ABUTMENT ;
    PORT
      LAYER M5 ;
      RECT 1127.268 0.000 1127.292 0.192 ;
    END
  END pma_tx[273]
  PIN pma_tx[274]
    DIRECTION OUTPUT ;
    USE SIGNAL ;
    SHAPE ABUTMENT ;
    PORT
      LAYER M5 ;
      RECT 1131.348 0.000 1131.372 0.192 ;
    END
  END pma_tx[274]
  PIN pma_tx[275]
    DIRECTION OUTPUT ;
    USE SIGNAL ;
    SHAPE ABUTMENT ;
    PORT
      LAYER M5 ;
      RECT 1135.428 0.000 1135.452 0.192 ;
    END
  END pma_tx[275]
  PIN pma_tx[276]
    DIRECTION OUTPUT ;
    USE SIGNAL ;
    SHAPE ABUTMENT ;
    PORT
      LAYER M5 ;
      RECT 1139.508 0.000 1139.532 0.192 ;
    END
  END pma_tx[276]
  PIN pma_tx[277]
    DIRECTION OUTPUT ;
    USE SIGNAL ;
    SHAPE ABUTMENT ;
    PORT
      LAYER M5 ;
      RECT 1143.588 0.000 1143.612 0.192 ;
    END
  END pma_tx[277]
  PIN pma_tx[278]
    DIRECTION OUTPUT ;
    USE SIGNAL ;
    SHAPE ABUTMENT ;
    PORT
      LAYER M5 ;
      RECT 1147.668 0.000 1147.692 0.192 ;
    END
  END pma_tx[278]
  PIN pma_tx[279]
    DIRECTION OUTPUT ;
    USE SIGNAL ;
    SHAPE ABUTMENT ;
    PORT
      LAYER M5 ;
      RECT 1151.748 0.000 1151.772 0.192 ;
    END
  END pma_tx[279]
  PIN pma_tx[280]
    DIRECTION OUTPUT ;
    USE SIGNAL ;
    SHAPE ABUTMENT ;
    PORT
      LAYER M5 ;
      RECT 1155.828 0.000 1155.852 0.192 ;
    END
  END pma_tx[280]
  PIN pma_tx[281]
    DIRECTION OUTPUT ;
    USE SIGNAL ;
    SHAPE ABUTMENT ;
    PORT
      LAYER M5 ;
      RECT 1159.908 0.000 1159.932 0.192 ;
    END
  END pma_tx[281]
  PIN pma_tx[282]
    DIRECTION OUTPUT ;
    USE SIGNAL ;
    SHAPE ABUTMENT ;
    PORT
      LAYER M5 ;
      RECT 1163.988 0.000 1164.012 0.192 ;
    END
  END pma_tx[282]
  PIN pma_tx[283]
    DIRECTION OUTPUT ;
    USE SIGNAL ;
    SHAPE ABUTMENT ;
    PORT
      LAYER M5 ;
      RECT 1168.068 0.000 1168.092 0.192 ;
    END
  END pma_tx[283]
  PIN pma_tx[284]
    DIRECTION OUTPUT ;
    USE SIGNAL ;
    SHAPE ABUTMENT ;
    PORT
      LAYER M5 ;
      RECT 1172.148 0.000 1172.172 0.192 ;
    END
  END pma_tx[284]
  PIN pma_tx[285]
    DIRECTION OUTPUT ;
    USE SIGNAL ;
    SHAPE ABUTMENT ;
    PORT
      LAYER M5 ;
      RECT 1176.228 0.000 1176.252 0.192 ;
    END
  END pma_tx[285]
  PIN pma_tx[286]
    DIRECTION OUTPUT ;
    USE SIGNAL ;
    SHAPE ABUTMENT ;
    PORT
      LAYER M5 ;
      RECT 1180.308 0.000 1180.332 0.192 ;
    END
  END pma_tx[286]
  PIN pma_tx[287]
    DIRECTION OUTPUT ;
    USE SIGNAL ;
    SHAPE ABUTMENT ;
    PORT
      LAYER M5 ;
      RECT 1184.388 0.000 1184.412 0.192 ;
    END
  END pma_tx[287]
  PIN pma_tx[288]
    DIRECTION OUTPUT ;
    USE SIGNAL ;
    SHAPE ABUTMENT ;
    PORT
      LAYER M5 ;
      RECT 1188.468 0.000 1188.492 0.192 ;
    END
  END pma_tx[288]
  PIN pma_tx[289]
    DIRECTION OUTPUT ;
    USE SIGNAL ;
    SHAPE ABUTMENT ;
    PORT
      LAYER M5 ;
      RECT 1192.548 0.000 1192.572 0.192 ;
    END
  END pma_tx[289]
  PIN pma_tx[290]
    DIRECTION OUTPUT ;
    USE SIGNAL ;
    SHAPE ABUTMENT ;
    PORT
      LAYER M5 ;
      RECT 1196.628 0.000 1196.652 0.192 ;
    END
  END pma_tx[290]
  PIN pma_tx[291]
    DIRECTION OUTPUT ;
    USE SIGNAL ;
    SHAPE ABUTMENT ;
    PORT
      LAYER M5 ;
      RECT 1200.708 0.000 1200.732 0.192 ;
    END
  END pma_tx[291]
  PIN pma_tx[292]
    DIRECTION OUTPUT ;
    USE SIGNAL ;
    SHAPE ABUTMENT ;
    PORT
      LAYER M5 ;
      RECT 1204.788 0.000 1204.812 0.192 ;
    END
  END pma_tx[292]
  PIN pma_tx[293]
    DIRECTION OUTPUT ;
    USE SIGNAL ;
    SHAPE ABUTMENT ;
    PORT
      LAYER M5 ;
      RECT 1208.868 0.000 1208.892 0.192 ;
    END
  END pma_tx[293]
  PIN pma_tx[294]
    DIRECTION OUTPUT ;
    USE SIGNAL ;
    SHAPE ABUTMENT ;
    PORT
      LAYER M5 ;
      RECT 1212.948 0.000 1212.972 0.192 ;
    END
  END pma_tx[294]
  PIN pma_tx[295]
    DIRECTION OUTPUT ;
    USE SIGNAL ;
    SHAPE ABUTMENT ;
    PORT
      LAYER M5 ;
      RECT 1217.028 0.000 1217.052 0.192 ;
    END
  END pma_tx[295]
  PIN pma_tx[296]
    DIRECTION OUTPUT ;
    USE SIGNAL ;
    SHAPE ABUTMENT ;
    PORT
      LAYER M5 ;
      RECT 1221.108 0.000 1221.132 0.192 ;
    END
  END pma_tx[296]
  PIN pma_tx[297]
    DIRECTION OUTPUT ;
    USE SIGNAL ;
    SHAPE ABUTMENT ;
    PORT
      LAYER M5 ;
      RECT 1225.188 0.000 1225.212 0.192 ;
    END
  END pma_tx[297]
  PIN pma_tx[298]
    DIRECTION OUTPUT ;
    USE SIGNAL ;
    SHAPE ABUTMENT ;
    PORT
      LAYER M5 ;
      RECT 1229.268 0.000 1229.292 0.192 ;
    END
  END pma_tx[298]
  PIN pma_tx[299]
    DIRECTION OUTPUT ;
    USE SIGNAL ;
    SHAPE ABUTMENT ;
    PORT
      LAYER M5 ;
      RECT 1233.348 0.000 1233.372 0.192 ;
    END
  END pma_tx[299]
  PIN pma_tx[300]
    DIRECTION OUTPUT ;
    USE SIGNAL ;
    SHAPE ABUTMENT ;
    PORT
      LAYER M5 ;
      RECT 1237.428 0.000 1237.452 0.192 ;
    END
  END pma_tx[300]
  PIN pma_tx[301]
    DIRECTION OUTPUT ;
    USE SIGNAL ;
    SHAPE ABUTMENT ;
    PORT
      LAYER M5 ;
      RECT 1241.508 0.000 1241.532 0.192 ;
    END
  END pma_tx[301]
  PIN pma_tx[302]
    DIRECTION OUTPUT ;
    USE SIGNAL ;
    SHAPE ABUTMENT ;
    PORT
      LAYER M5 ;
      RECT 1245.588 0.000 1245.612 0.192 ;
    END
  END pma_tx[302]
  PIN pma_tx[303]
    DIRECTION OUTPUT ;
    USE SIGNAL ;
    SHAPE ABUTMENT ;
    PORT
      LAYER M5 ;
      RECT 1249.668 0.000 1249.692 0.192 ;
    END
  END pma_tx[303]
  PIN pma_tx[304]
    DIRECTION OUTPUT ;
    USE SIGNAL ;
    SHAPE ABUTMENT ;
    PORT
      LAYER M5 ;
      RECT 1253.748 0.000 1253.772 0.192 ;
    END
  END pma_tx[304]
  PIN pma_tx[305]
    DIRECTION OUTPUT ;
    USE SIGNAL ;
    SHAPE ABUTMENT ;
    PORT
      LAYER M5 ;
      RECT 1257.828 0.000 1257.852 0.192 ;
    END
  END pma_tx[305]
  PIN pma_tx[306]
    DIRECTION OUTPUT ;
    USE SIGNAL ;
    SHAPE ABUTMENT ;
    PORT
      LAYER M5 ;
      RECT 1261.908 0.000 1261.932 0.192 ;
    END
  END pma_tx[306]
  PIN pma_tx[307]
    DIRECTION OUTPUT ;
    USE SIGNAL ;
    SHAPE ABUTMENT ;
    PORT
      LAYER M5 ;
      RECT 1265.988 0.000 1266.012 0.192 ;
    END
  END pma_tx[307]
  PIN pma_tx[308]
    DIRECTION OUTPUT ;
    USE SIGNAL ;
    SHAPE ABUTMENT ;
    PORT
      LAYER M5 ;
      RECT 1270.068 0.000 1270.092 0.192 ;
    END
  END pma_tx[308]
  PIN pma_tx[309]
    DIRECTION OUTPUT ;
    USE SIGNAL ;
    SHAPE ABUTMENT ;
    PORT
      LAYER M5 ;
      RECT 1274.148 0.000 1274.172 0.192 ;
    END
  END pma_tx[309]
  PIN pma_tx[310]
    DIRECTION OUTPUT ;
    USE SIGNAL ;
    SHAPE ABUTMENT ;
    PORT
      LAYER M5 ;
      RECT 1278.228 0.000 1278.252 0.192 ;
    END
  END pma_tx[310]
  PIN pma_tx[311]
    DIRECTION OUTPUT ;
    USE SIGNAL ;
    SHAPE ABUTMENT ;
    PORT
      LAYER M5 ;
      RECT 1282.308 0.000 1282.332 0.192 ;
    END
  END pma_tx[311]
  PIN pma_tx[312]
    DIRECTION OUTPUT ;
    USE SIGNAL ;
    SHAPE ABUTMENT ;
    PORT
      LAYER M5 ;
      RECT 1286.388 0.000 1286.412 0.192 ;
    END
  END pma_tx[312]
  PIN pma_tx[313]
    DIRECTION OUTPUT ;
    USE SIGNAL ;
    SHAPE ABUTMENT ;
    PORT
      LAYER M5 ;
      RECT 1290.468 0.000 1290.492 0.192 ;
    END
  END pma_tx[313]
  PIN pma_tx[314]
    DIRECTION OUTPUT ;
    USE SIGNAL ;
    SHAPE ABUTMENT ;
    PORT
      LAYER M5 ;
      RECT 1294.548 0.000 1294.572 0.192 ;
    END
  END pma_tx[314]
  PIN pma_tx[315]
    DIRECTION OUTPUT ;
    USE SIGNAL ;
    SHAPE ABUTMENT ;
    PORT
      LAYER M5 ;
      RECT 1298.628 0.000 1298.652 0.192 ;
    END
  END pma_tx[315]
  PIN pma_tx[316]
    DIRECTION OUTPUT ;
    USE SIGNAL ;
    SHAPE ABUTMENT ;
    PORT
      LAYER M5 ;
      RECT 1302.708 0.000 1302.732 0.192 ;
    END
  END pma_tx[316]
  PIN pma_tx[317]
    DIRECTION OUTPUT ;
    USE SIGNAL ;
    SHAPE ABUTMENT ;
    PORT
      LAYER M5 ;
      RECT 1306.788 0.000 1306.812 0.192 ;
    END
  END pma_tx[317]
  PIN pma_tx[318]
    DIRECTION OUTPUT ;
    USE SIGNAL ;
    SHAPE ABUTMENT ;
    PORT
      LAYER M5 ;
      RECT 1310.868 0.000 1310.892 0.192 ;
    END
  END pma_tx[318]
  PIN pma_tx[319]
    DIRECTION OUTPUT ;
    USE SIGNAL ;
    SHAPE ABUTMENT ;
    PORT
      LAYER M5 ;
      RECT 1314.948 0.000 1314.972 0.192 ;
    END
  END pma_tx[319]
  PIN pma_tx[320]
    DIRECTION OUTPUT ;
    USE SIGNAL ;
    SHAPE ABUTMENT ;
    PORT
      LAYER M5 ;
      RECT 1319.028 0.000 1319.052 0.192 ;
    END
  END pma_tx[320]
  PIN pma_tx[321]
    DIRECTION OUTPUT ;
    USE SIGNAL ;
    SHAPE ABUTMENT ;
    PORT
      LAYER M5 ;
      RECT 1323.108 0.000 1323.132 0.192 ;
    END
  END pma_tx[321]
  PIN pma_tx[322]
    DIRECTION OUTPUT ;
    USE SIGNAL ;
    SHAPE ABUTMENT ;
    PORT
      LAYER M5 ;
      RECT 1327.188 0.000 1327.212 0.192 ;
    END
  END pma_tx[322]
  PIN pma_tx[323]
    DIRECTION OUTPUT ;
    USE SIGNAL ;
    SHAPE ABUTMENT ;
    PORT
      LAYER M5 ;
      RECT 1331.268 0.000 1331.292 0.192 ;
    END
  END pma_tx[323]
  PIN pma_tx[324]
    DIRECTION OUTPUT ;
    USE SIGNAL ;
    SHAPE ABUTMENT ;
    PORT
      LAYER M5 ;
      RECT 1335.348 0.000 1335.372 0.192 ;
    END
  END pma_tx[324]
  PIN pma_tx[325]
    DIRECTION OUTPUT ;
    USE SIGNAL ;
    SHAPE ABUTMENT ;
    PORT
      LAYER M5 ;
      RECT 1339.428 0.000 1339.452 0.192 ;
    END
  END pma_tx[325]
  PIN pma_tx[326]
    DIRECTION OUTPUT ;
    USE SIGNAL ;
    SHAPE ABUTMENT ;
    PORT
      LAYER M5 ;
      RECT 1343.508 0.000 1343.532 0.192 ;
    END
  END pma_tx[326]
  PIN pma_tx[327]
    DIRECTION OUTPUT ;
    USE SIGNAL ;
    SHAPE ABUTMENT ;
    PORT
      LAYER M5 ;
      RECT 1347.588 0.000 1347.612 0.192 ;
    END
  END pma_tx[327]
  PIN pma_tx[328]
    DIRECTION OUTPUT ;
    USE SIGNAL ;
    SHAPE ABUTMENT ;
    PORT
      LAYER M5 ;
      RECT 1351.668 0.000 1351.692 0.192 ;
    END
  END pma_tx[328]
  PIN pma_tx[329]
    DIRECTION OUTPUT ;
    USE SIGNAL ;
    SHAPE ABUTMENT ;
    PORT
      LAYER M5 ;
      RECT 1355.748 0.000 1355.772 0.192 ;
    END
  END pma_tx[329]
  PIN pma_tx[330]
    DIRECTION OUTPUT ;
    USE SIGNAL ;
    SHAPE ABUTMENT ;
    PORT
      LAYER M5 ;
      RECT 1359.828 0.000 1359.852 0.192 ;
    END
  END pma_tx[330]
  PIN pma_tx[331]
    DIRECTION OUTPUT ;
    USE SIGNAL ;
    SHAPE ABUTMENT ;
    PORT
      LAYER M5 ;
      RECT 1363.908 0.000 1363.932 0.192 ;
    END
  END pma_tx[331]
  PIN pma_tx[332]
    DIRECTION OUTPUT ;
    USE SIGNAL ;
    SHAPE ABUTMENT ;
    PORT
      LAYER M5 ;
      RECT 1367.988 0.000 1368.012 0.192 ;
    END
  END pma_tx[332]
  PIN pma_tx[333]
    DIRECTION OUTPUT ;
    USE SIGNAL ;
    SHAPE ABUTMENT ;
    PORT
      LAYER M5 ;
      RECT 1372.068 0.000 1372.092 0.192 ;
    END
  END pma_tx[333]
  PIN pma_tx[334]
    DIRECTION OUTPUT ;
    USE SIGNAL ;
    SHAPE ABUTMENT ;
    PORT
      LAYER M5 ;
      RECT 1376.148 0.000 1376.172 0.192 ;
    END
  END pma_tx[334]
  PIN pma_tx[335]
    DIRECTION OUTPUT ;
    USE SIGNAL ;
    SHAPE ABUTMENT ;
    PORT
      LAYER M5 ;
      RECT 1380.228 0.000 1380.252 0.192 ;
    END
  END pma_tx[335]
  PIN pma_tx[336]
    DIRECTION OUTPUT ;
    USE SIGNAL ;
    SHAPE ABUTMENT ;
    PORT
      LAYER M5 ;
      RECT 1384.308 0.000 1384.332 0.192 ;
    END
  END pma_tx[336]
  PIN pma_tx[337]
    DIRECTION OUTPUT ;
    USE SIGNAL ;
    SHAPE ABUTMENT ;
    PORT
      LAYER M5 ;
      RECT 1388.388 0.000 1388.412 0.192 ;
    END
  END pma_tx[337]
  PIN pma_tx[338]
    DIRECTION OUTPUT ;
    USE SIGNAL ;
    SHAPE ABUTMENT ;
    PORT
      LAYER M5 ;
      RECT 1392.468 0.000 1392.492 0.192 ;
    END
  END pma_tx[338]
  PIN pma_tx[339]
    DIRECTION OUTPUT ;
    USE SIGNAL ;
    SHAPE ABUTMENT ;
    PORT
      LAYER M5 ;
      RECT 1396.548 0.000 1396.572 0.192 ;
    END
  END pma_tx[339]
  PIN pma_tx[340]
    DIRECTION OUTPUT ;
    USE SIGNAL ;
    SHAPE ABUTMENT ;
    PORT
      LAYER M5 ;
      RECT 1400.628 0.000 1400.652 0.192 ;
    END
  END pma_tx[340]
  PIN pma_tx[341]
    DIRECTION OUTPUT ;
    USE SIGNAL ;
    SHAPE ABUTMENT ;
    PORT
      LAYER M5 ;
      RECT 1404.708 0.000 1404.732 0.192 ;
    END
  END pma_tx[341]
  PIN pma_tx[342]
    DIRECTION OUTPUT ;
    USE SIGNAL ;
    SHAPE ABUTMENT ;
    PORT
      LAYER M5 ;
      RECT 1408.788 0.000 1408.812 0.192 ;
    END
  END pma_tx[342]
  PIN pma_tx[343]
    DIRECTION OUTPUT ;
    USE SIGNAL ;
    SHAPE ABUTMENT ;
    PORT
      LAYER M5 ;
      RECT 1412.868 0.000 1412.892 0.192 ;
    END
  END pma_tx[343]
  PIN pma_tx[344]
    DIRECTION OUTPUT ;
    USE SIGNAL ;
    SHAPE ABUTMENT ;
    PORT
      LAYER M5 ;
      RECT 1416.948 0.000 1416.972 0.192 ;
    END
  END pma_tx[344]
  PIN pma_tx[345]
    DIRECTION OUTPUT ;
    USE SIGNAL ;
    SHAPE ABUTMENT ;
    PORT
      LAYER M5 ;
      RECT 1421.028 0.000 1421.052 0.192 ;
    END
  END pma_tx[345]
  PIN pma_tx[346]
    DIRECTION OUTPUT ;
    USE SIGNAL ;
    SHAPE ABUTMENT ;
    PORT
      LAYER M5 ;
      RECT 1425.108 0.000 1425.132 0.192 ;
    END
  END pma_tx[346]
  PIN pma_tx[347]
    DIRECTION OUTPUT ;
    USE SIGNAL ;
    SHAPE ABUTMENT ;
    PORT
      LAYER M5 ;
      RECT 1429.188 0.000 1429.212 0.192 ;
    END
  END pma_tx[347]
  PIN pma_tx[348]
    DIRECTION OUTPUT ;
    USE SIGNAL ;
    SHAPE ABUTMENT ;
    PORT
      LAYER M5 ;
      RECT 1433.268 0.000 1433.292 0.192 ;
    END
  END pma_tx[348]
  PIN pma_tx[349]
    DIRECTION OUTPUT ;
    USE SIGNAL ;
    SHAPE ABUTMENT ;
    PORT
      LAYER M5 ;
      RECT 1437.348 0.000 1437.372 0.192 ;
    END
  END pma_tx[349]
  PIN pma_tx[350]
    DIRECTION OUTPUT ;
    USE SIGNAL ;
    SHAPE ABUTMENT ;
    PORT
      LAYER M5 ;
      RECT 1441.428 0.000 1441.452 0.192 ;
    END
  END pma_tx[350]
  PIN pma_tx[351]
    DIRECTION OUTPUT ;
    USE SIGNAL ;
    SHAPE ABUTMENT ;
    PORT
      LAYER M5 ;
      RECT 1445.508 0.000 1445.532 0.192 ;
    END
  END pma_tx[351]
  PIN pma_tx[352]
    DIRECTION OUTPUT ;
    USE SIGNAL ;
    SHAPE ABUTMENT ;
    PORT
      LAYER M5 ;
      RECT 1449.588 0.000 1449.612 0.192 ;
    END
  END pma_tx[352]
  PIN pma_tx[353]
    DIRECTION OUTPUT ;
    USE SIGNAL ;
    SHAPE ABUTMENT ;
    PORT
      LAYER M5 ;
      RECT 1453.668 0.000 1453.692 0.192 ;
    END
  END pma_tx[353]
  PIN pma_tx[354]
    DIRECTION OUTPUT ;
    USE SIGNAL ;
    SHAPE ABUTMENT ;
    PORT
      LAYER M5 ;
      RECT 1457.748 0.000 1457.772 0.192 ;
    END
  END pma_tx[354]
  PIN pma_tx[355]
    DIRECTION OUTPUT ;
    USE SIGNAL ;
    SHAPE ABUTMENT ;
    PORT
      LAYER M5 ;
      RECT 1461.828 0.000 1461.852 0.192 ;
    END
  END pma_tx[355]
  PIN pma_tx[356]
    DIRECTION OUTPUT ;
    USE SIGNAL ;
    SHAPE ABUTMENT ;
    PORT
      LAYER M5 ;
      RECT 1465.908 0.000 1465.932 0.192 ;
    END
  END pma_tx[356]
  PIN pma_tx[357]
    DIRECTION OUTPUT ;
    USE SIGNAL ;
    SHAPE ABUTMENT ;
    PORT
      LAYER M5 ;
      RECT 1469.988 0.000 1470.012 0.192 ;
    END
  END pma_tx[357]
  PIN pma_tx[358]
    DIRECTION OUTPUT ;
    USE SIGNAL ;
    SHAPE ABUTMENT ;
    PORT
      LAYER M5 ;
      RECT 1474.068 0.000 1474.092 0.192 ;
    END
  END pma_tx[358]
  PIN pma_tx[359]
    DIRECTION OUTPUT ;
    USE SIGNAL ;
    SHAPE ABUTMENT ;
    PORT
      LAYER M5 ;
      RECT 1478.148 0.000 1478.172 0.192 ;
    END
  END pma_tx[359]
  PIN pma_tx[360]
    DIRECTION OUTPUT ;
    USE SIGNAL ;
    SHAPE ABUTMENT ;
    PORT
      LAYER M5 ;
      RECT 1482.228 0.000 1482.252 0.192 ;
    END
  END pma_tx[360]
  PIN pma_tx[361]
    DIRECTION OUTPUT ;
    USE SIGNAL ;
    SHAPE ABUTMENT ;
    PORT
      LAYER M5 ;
      RECT 1486.308 0.000 1486.332 0.192 ;
    END
  END pma_tx[361]
  PIN pma_tx[362]
    DIRECTION OUTPUT ;
    USE SIGNAL ;
    SHAPE ABUTMENT ;
    PORT
      LAYER M5 ;
      RECT 1490.388 0.000 1490.412 0.192 ;
    END
  END pma_tx[362]
  PIN pma_tx[363]
    DIRECTION OUTPUT ;
    USE SIGNAL ;
    SHAPE ABUTMENT ;
    PORT
      LAYER M5 ;
      RECT 1494.468 0.000 1494.492 0.192 ;
    END
  END pma_tx[363]
  PIN pma_tx[364]
    DIRECTION OUTPUT ;
    USE SIGNAL ;
    SHAPE ABUTMENT ;
    PORT
      LAYER M5 ;
      RECT 1498.548 0.000 1498.572 0.192 ;
    END
  END pma_tx[364]
  PIN pma_tx[365]
    DIRECTION OUTPUT ;
    USE SIGNAL ;
    SHAPE ABUTMENT ;
    PORT
      LAYER M5 ;
      RECT 1502.628 0.000 1502.652 0.192 ;
    END
  END pma_tx[365]
  PIN pma_tx[366]
    DIRECTION OUTPUT ;
    USE SIGNAL ;
    SHAPE ABUTMENT ;
    PORT
      LAYER M5 ;
      RECT 1506.708 0.000 1506.732 0.192 ;
    END
  END pma_tx[366]
  PIN pma_tx[367]
    DIRECTION OUTPUT ;
    USE SIGNAL ;
    SHAPE ABUTMENT ;
    PORT
      LAYER M5 ;
      RECT 1510.788 0.000 1510.812 0.192 ;
    END
  END pma_tx[367]
  PIN pma_tx[368]
    DIRECTION OUTPUT ;
    USE SIGNAL ;
    SHAPE ABUTMENT ;
    PORT
      LAYER M5 ;
      RECT 1514.868 0.000 1514.892 0.192 ;
    END
  END pma_tx[368]
  PIN pma_tx[369]
    DIRECTION OUTPUT ;
    USE SIGNAL ;
    SHAPE ABUTMENT ;
    PORT
      LAYER M5 ;
      RECT 1518.948 0.000 1518.972 0.192 ;
    END
  END pma_tx[369]
  PIN pma_tx[370]
    DIRECTION OUTPUT ;
    USE SIGNAL ;
    SHAPE ABUTMENT ;
    PORT
      LAYER M5 ;
      RECT 1523.028 0.000 1523.052 0.192 ;
    END
  END pma_tx[370]
  PIN pma_tx[371]
    DIRECTION OUTPUT ;
    USE SIGNAL ;
    SHAPE ABUTMENT ;
    PORT
      LAYER M5 ;
      RECT 1527.108 0.000 1527.132 0.192 ;
    END
  END pma_tx[371]
  PIN pma_tx[372]
    DIRECTION OUTPUT ;
    USE SIGNAL ;
    SHAPE ABUTMENT ;
    PORT
      LAYER M5 ;
      RECT 1531.188 0.000 1531.212 0.192 ;
    END
  END pma_tx[372]
  PIN pma_tx[373]
    DIRECTION OUTPUT ;
    USE SIGNAL ;
    SHAPE ABUTMENT ;
    PORT
      LAYER M5 ;
      RECT 1535.268 0.000 1535.292 0.192 ;
    END
  END pma_tx[373]
  PIN pma_tx[374]
    DIRECTION OUTPUT ;
    USE SIGNAL ;
    SHAPE ABUTMENT ;
    PORT
      LAYER M5 ;
      RECT 1539.348 0.000 1539.372 0.192 ;
    END
  END pma_tx[374]
  PIN pma_tx[375]
    DIRECTION OUTPUT ;
    USE SIGNAL ;
    SHAPE ABUTMENT ;
    PORT
      LAYER M5 ;
      RECT 1543.428 0.000 1543.452 0.192 ;
    END
  END pma_tx[375]
  PIN pma_tx[376]
    DIRECTION OUTPUT ;
    USE SIGNAL ;
    SHAPE ABUTMENT ;
    PORT
      LAYER M5 ;
      RECT 1547.508 0.000 1547.532 0.192 ;
    END
  END pma_tx[376]
  PIN pma_tx[377]
    DIRECTION OUTPUT ;
    USE SIGNAL ;
    SHAPE ABUTMENT ;
    PORT
      LAYER M5 ;
      RECT 1551.588 0.000 1551.612 0.192 ;
    END
  END pma_tx[377]
  PIN pma_tx[378]
    DIRECTION OUTPUT ;
    USE SIGNAL ;
    SHAPE ABUTMENT ;
    PORT
      LAYER M5 ;
      RECT 1555.668 0.000 1555.692 0.192 ;
    END
  END pma_tx[378]
  PIN pma_tx[379]
    DIRECTION OUTPUT ;
    USE SIGNAL ;
    SHAPE ABUTMENT ;
    PORT
      LAYER M5 ;
      RECT 1559.748 0.000 1559.772 0.192 ;
    END
  END pma_tx[379]
  PIN pma_tx[380]
    DIRECTION OUTPUT ;
    USE SIGNAL ;
    SHAPE ABUTMENT ;
    PORT
      LAYER M5 ;
      RECT 1563.828 0.000 1563.852 0.192 ;
    END
  END pma_tx[380]
  PIN pma_tx[381]
    DIRECTION OUTPUT ;
    USE SIGNAL ;
    SHAPE ABUTMENT ;
    PORT
      LAYER M5 ;
      RECT 1567.908 0.000 1567.932 0.192 ;
    END
  END pma_tx[381]
  PIN pma_tx[382]
    DIRECTION OUTPUT ;
    USE SIGNAL ;
    SHAPE ABUTMENT ;
    PORT
      LAYER M5 ;
      RECT 1571.988 0.000 1572.012 0.192 ;
    END
  END pma_tx[382]
  PIN pma_tx[383]
    DIRECTION OUTPUT ;
    USE SIGNAL ;
    SHAPE ABUTMENT ;
    PORT
      LAYER M5 ;
      RECT 1576.068 0.000 1576.092 0.192 ;
    END
  END pma_tx[383]
  PIN pma_tx[384]
    DIRECTION OUTPUT ;
    USE SIGNAL ;
    SHAPE ABUTMENT ;
    PORT
      LAYER M5 ;
      RECT 1580.148 0.000 1580.172 0.192 ;
    END
  END pma_tx[384]
  PIN pma_tx[385]
    DIRECTION OUTPUT ;
    USE SIGNAL ;
    SHAPE ABUTMENT ;
    PORT
      LAYER M5 ;
      RECT 1584.228 0.000 1584.252 0.192 ;
    END
  END pma_tx[385]
  PIN pma_tx[386]
    DIRECTION OUTPUT ;
    USE SIGNAL ;
    SHAPE ABUTMENT ;
    PORT
      LAYER M5 ;
      RECT 1588.308 0.000 1588.332 0.192 ;
    END
  END pma_tx[386]
  PIN pma_tx[387]
    DIRECTION OUTPUT ;
    USE SIGNAL ;
    SHAPE ABUTMENT ;
    PORT
      LAYER M5 ;
      RECT 1592.388 0.000 1592.412 0.192 ;
    END
  END pma_tx[387]
  PIN pma_tx[388]
    DIRECTION OUTPUT ;
    USE SIGNAL ;
    SHAPE ABUTMENT ;
    PORT
      LAYER M5 ;
      RECT 1596.468 0.000 1596.492 0.192 ;
    END
  END pma_tx[388]
  PIN pma_tx[389]
    DIRECTION OUTPUT ;
    USE SIGNAL ;
    SHAPE ABUTMENT ;
    PORT
      LAYER M5 ;
      RECT 1600.548 0.000 1600.572 0.192 ;
    END
  END pma_tx[389]
  PIN pma_tx[390]
    DIRECTION OUTPUT ;
    USE SIGNAL ;
    SHAPE ABUTMENT ;
    PORT
      LAYER M5 ;
      RECT 1604.628 0.000 1604.652 0.192 ;
    END
  END pma_tx[390]
  PIN pma_tx[391]
    DIRECTION OUTPUT ;
    USE SIGNAL ;
    SHAPE ABUTMENT ;
    PORT
      LAYER M5 ;
      RECT 1608.708 0.000 1608.732 0.192 ;
    END
  END pma_tx[391]
  PIN pma_tx[392]
    DIRECTION OUTPUT ;
    USE SIGNAL ;
    SHAPE ABUTMENT ;
    PORT
      LAYER M5 ;
      RECT 1612.788 0.000 1612.812 0.192 ;
    END
  END pma_tx[392]
  PIN pma_tx[393]
    DIRECTION OUTPUT ;
    USE SIGNAL ;
    SHAPE ABUTMENT ;
    PORT
      LAYER M5 ;
      RECT 1616.868 0.000 1616.892 0.192 ;
    END
  END pma_tx[393]
  PIN pma_tx[394]
    DIRECTION OUTPUT ;
    USE SIGNAL ;
    SHAPE ABUTMENT ;
    PORT
      LAYER M5 ;
      RECT 1620.948 0.000 1620.972 0.192 ;
    END
  END pma_tx[394]
  PIN pma_tx[395]
    DIRECTION OUTPUT ;
    USE SIGNAL ;
    SHAPE ABUTMENT ;
    PORT
      LAYER M5 ;
      RECT 1625.028 0.000 1625.052 0.192 ;
    END
  END pma_tx[395]
  PIN pma_tx[396]
    DIRECTION OUTPUT ;
    USE SIGNAL ;
    SHAPE ABUTMENT ;
    PORT
      LAYER M5 ;
      RECT 1629.108 0.000 1629.132 0.192 ;
    END
  END pma_tx[396]
  PIN pma_tx[397]
    DIRECTION OUTPUT ;
    USE SIGNAL ;
    SHAPE ABUTMENT ;
    PORT
      LAYER M5 ;
      RECT 1633.188 0.000 1633.212 0.192 ;
    END
  END pma_tx[397]
  PIN pma_tx[398]
    DIRECTION OUTPUT ;
    USE SIGNAL ;
    SHAPE ABUTMENT ;
    PORT
      LAYER M5 ;
      RECT 1637.268 0.000 1637.292 0.192 ;
    END
  END pma_tx[398]
  PIN pma_tx[399]
    DIRECTION OUTPUT ;
    USE SIGNAL ;
    SHAPE ABUTMENT ;
    PORT
      LAYER M5 ;
      RECT 1641.348 0.000 1641.372 0.192 ;
    END
  END pma_tx[399]
  PIN pma_tx[400]
    DIRECTION OUTPUT ;
    USE SIGNAL ;
    SHAPE ABUTMENT ;
    PORT
      LAYER M5 ;
      RECT 1645.428 0.000 1645.452 0.192 ;
    END
  END pma_tx[400]
  PIN pma_tx[401]
    DIRECTION OUTPUT ;
    USE SIGNAL ;
    SHAPE ABUTMENT ;
    PORT
      LAYER M5 ;
      RECT 1649.508 0.000 1649.532 0.192 ;
    END
  END pma_tx[401]
  PIN pma_tx[402]
    DIRECTION OUTPUT ;
    USE SIGNAL ;
    SHAPE ABUTMENT ;
    PORT
      LAYER M5 ;
      RECT 1653.588 0.000 1653.612 0.192 ;
    END
  END pma_tx[402]
  PIN pma_tx[403]
    DIRECTION OUTPUT ;
    USE SIGNAL ;
    SHAPE ABUTMENT ;
    PORT
      LAYER M5 ;
      RECT 1657.668 0.000 1657.692 0.192 ;
    END
  END pma_tx[403]
  PIN pma_tx[404]
    DIRECTION OUTPUT ;
    USE SIGNAL ;
    SHAPE ABUTMENT ;
    PORT
      LAYER M5 ;
      RECT 1661.748 0.000 1661.772 0.192 ;
    END
  END pma_tx[404]
  PIN pma_tx[405]
    DIRECTION OUTPUT ;
    USE SIGNAL ;
    SHAPE ABUTMENT ;
    PORT
      LAYER M5 ;
      RECT 1665.828 0.000 1665.852 0.192 ;
    END
  END pma_tx[405]
  PIN pma_tx[406]
    DIRECTION OUTPUT ;
    USE SIGNAL ;
    SHAPE ABUTMENT ;
    PORT
      LAYER M5 ;
      RECT 1669.908 0.000 1669.932 0.192 ;
    END
  END pma_tx[406]
  PIN pma_tx[407]
    DIRECTION OUTPUT ;
    USE SIGNAL ;
    SHAPE ABUTMENT ;
    PORT
      LAYER M5 ;
      RECT 1673.988 0.000 1674.012 0.192 ;
    END
  END pma_tx[407]
  PIN pma_tx[408]
    DIRECTION OUTPUT ;
    USE SIGNAL ;
    SHAPE ABUTMENT ;
    PORT
      LAYER M5 ;
      RECT 1678.068 0.000 1678.092 0.192 ;
    END
  END pma_tx[408]
  PIN pma_tx[409]
    DIRECTION OUTPUT ;
    USE SIGNAL ;
    SHAPE ABUTMENT ;
    PORT
      LAYER M5 ;
      RECT 1682.148 0.000 1682.172 0.192 ;
    END
  END pma_tx[409]
  PIN pma_tx[410]
    DIRECTION OUTPUT ;
    USE SIGNAL ;
    SHAPE ABUTMENT ;
    PORT
      LAYER M5 ;
      RECT 1686.228 0.000 1686.252 0.192 ;
    END
  END pma_tx[410]
  PIN pma_tx[411]
    DIRECTION OUTPUT ;
    USE SIGNAL ;
    SHAPE ABUTMENT ;
    PORT
      LAYER M5 ;
      RECT 1690.308 0.000 1690.332 0.192 ;
    END
  END pma_tx[411]
  PIN pma_tx[412]
    DIRECTION OUTPUT ;
    USE SIGNAL ;
    SHAPE ABUTMENT ;
    PORT
      LAYER M5 ;
      RECT 1694.388 0.000 1694.412 0.192 ;
    END
  END pma_tx[412]
  PIN pma_tx[413]
    DIRECTION OUTPUT ;
    USE SIGNAL ;
    SHAPE ABUTMENT ;
    PORT
      LAYER M5 ;
      RECT 1698.468 0.000 1698.492 0.192 ;
    END
  END pma_tx[413]
  PIN pma_tx[414]
    DIRECTION OUTPUT ;
    USE SIGNAL ;
    SHAPE ABUTMENT ;
    PORT
      LAYER M5 ;
      RECT 1702.548 0.000 1702.572 0.192 ;
    END
  END pma_tx[414]
  PIN pma_tx[415]
    DIRECTION OUTPUT ;
    USE SIGNAL ;
    SHAPE ABUTMENT ;
    PORT
      LAYER M5 ;
      RECT 1706.628 0.000 1706.652 0.192 ;
    END
  END pma_tx[415]
  PIN pma_tx[416]
    DIRECTION OUTPUT ;
    USE SIGNAL ;
    SHAPE ABUTMENT ;
    PORT
      LAYER M5 ;
      RECT 1710.708 0.000 1710.732 0.192 ;
    END
  END pma_tx[416]
  PIN pma_tx[417]
    DIRECTION OUTPUT ;
    USE SIGNAL ;
    SHAPE ABUTMENT ;
    PORT
      LAYER M5 ;
      RECT 1714.788 0.000 1714.812 0.192 ;
    END
  END pma_tx[417]
  PIN pma_tx[418]
    DIRECTION OUTPUT ;
    USE SIGNAL ;
    SHAPE ABUTMENT ;
    PORT
      LAYER M5 ;
      RECT 1718.868 0.000 1718.892 0.192 ;
    END
  END pma_tx[418]
  PIN pma_tx[419]
    DIRECTION OUTPUT ;
    USE SIGNAL ;
    SHAPE ABUTMENT ;
    PORT
      LAYER M5 ;
      RECT 1722.948 0.000 1722.972 0.192 ;
    END
  END pma_tx[419]
  PIN pma_tx[420]
    DIRECTION OUTPUT ;
    USE SIGNAL ;
    SHAPE ABUTMENT ;
    PORT
      LAYER M5 ;
      RECT 1727.028 0.000 1727.052 0.192 ;
    END
  END pma_tx[420]
  PIN pma_tx[421]
    DIRECTION OUTPUT ;
    USE SIGNAL ;
    SHAPE ABUTMENT ;
    PORT
      LAYER M5 ;
      RECT 1731.108 0.000 1731.132 0.192 ;
    END
  END pma_tx[421]
  PIN pma_tx[422]
    DIRECTION OUTPUT ;
    USE SIGNAL ;
    SHAPE ABUTMENT ;
    PORT
      LAYER M5 ;
      RECT 1735.188 0.000 1735.212 0.192 ;
    END
  END pma_tx[422]
  PIN pma_tx[423]
    DIRECTION OUTPUT ;
    USE SIGNAL ;
    SHAPE ABUTMENT ;
    PORT
      LAYER M5 ;
      RECT 1739.268 0.000 1739.292 0.192 ;
    END
  END pma_tx[423]
  PIN pma_tx[424]
    DIRECTION OUTPUT ;
    USE SIGNAL ;
    SHAPE ABUTMENT ;
    PORT
      LAYER M5 ;
      RECT 1743.348 0.000 1743.372 0.192 ;
    END
  END pma_tx[424]
  PIN pma_tx[425]
    DIRECTION OUTPUT ;
    USE SIGNAL ;
    SHAPE ABUTMENT ;
    PORT
      LAYER M5 ;
      RECT 1747.428 0.000 1747.452 0.192 ;
    END
  END pma_tx[425]
  PIN pma_tx[426]
    DIRECTION OUTPUT ;
    USE SIGNAL ;
    SHAPE ABUTMENT ;
    PORT
      LAYER M5 ;
      RECT 1751.508 0.000 1751.532 0.192 ;
    END
  END pma_tx[426]
  PIN pma_tx[427]
    DIRECTION OUTPUT ;
    USE SIGNAL ;
    SHAPE ABUTMENT ;
    PORT
      LAYER M5 ;
      RECT 1755.588 0.000 1755.612 0.192 ;
    END
  END pma_tx[427]
  PIN pma_tx[428]
    DIRECTION OUTPUT ;
    USE SIGNAL ;
    SHAPE ABUTMENT ;
    PORT
      LAYER M5 ;
      RECT 1759.668 0.000 1759.692 0.192 ;
    END
  END pma_tx[428]
  PIN pma_tx[429]
    DIRECTION OUTPUT ;
    USE SIGNAL ;
    SHAPE ABUTMENT ;
    PORT
      LAYER M5 ;
      RECT 1763.748 0.000 1763.772 0.192 ;
    END
  END pma_tx[429]
  PIN pma_tx[430]
    DIRECTION OUTPUT ;
    USE SIGNAL ;
    SHAPE ABUTMENT ;
    PORT
      LAYER M5 ;
      RECT 1767.828 0.000 1767.852 0.192 ;
    END
  END pma_tx[430]
  PIN pma_tx[431]
    DIRECTION OUTPUT ;
    USE SIGNAL ;
    SHAPE ABUTMENT ;
    PORT
      LAYER M5 ;
      RECT 1771.908 0.000 1771.932 0.192 ;
    END
  END pma_tx[431]
  PIN pma_tx[432]
    DIRECTION OUTPUT ;
    USE SIGNAL ;
    SHAPE ABUTMENT ;
    PORT
      LAYER M5 ;
      RECT 1775.988 0.000 1776.012 0.192 ;
    END
  END pma_tx[432]
  PIN pma_tx[433]
    DIRECTION OUTPUT ;
    USE SIGNAL ;
    SHAPE ABUTMENT ;
    PORT
      LAYER M5 ;
      RECT 1780.068 0.000 1780.092 0.192 ;
    END
  END pma_tx[433]
  PIN pma_tx[434]
    DIRECTION OUTPUT ;
    USE SIGNAL ;
    SHAPE ABUTMENT ;
    PORT
      LAYER M5 ;
      RECT 1784.148 0.000 1784.172 0.192 ;
    END
  END pma_tx[434]
  PIN pma_tx[435]
    DIRECTION OUTPUT ;
    USE SIGNAL ;
    SHAPE ABUTMENT ;
    PORT
      LAYER M5 ;
      RECT 1788.228 0.000 1788.252 0.192 ;
    END
  END pma_tx[435]
  PIN pma_tx[436]
    DIRECTION OUTPUT ;
    USE SIGNAL ;
    SHAPE ABUTMENT ;
    PORT
      LAYER M5 ;
      RECT 1792.308 0.000 1792.332 0.192 ;
    END
  END pma_tx[436]
  PIN pma_tx[437]
    DIRECTION OUTPUT ;
    USE SIGNAL ;
    SHAPE ABUTMENT ;
    PORT
      LAYER M5 ;
      RECT 1796.388 0.000 1796.412 0.192 ;
    END
  END pma_tx[437]
  PIN pma_tx[438]
    DIRECTION OUTPUT ;
    USE SIGNAL ;
    SHAPE ABUTMENT ;
    PORT
      LAYER M5 ;
      RECT 1800.468 0.000 1800.492 0.192 ;
    END
  END pma_tx[438]
  PIN pma_tx[439]
    DIRECTION OUTPUT ;
    USE SIGNAL ;
    SHAPE ABUTMENT ;
    PORT
      LAYER M5 ;
      RECT 1804.548 0.000 1804.572 0.192 ;
    END
  END pma_tx[439]
  PIN pma_tx[440]
    DIRECTION OUTPUT ;
    USE SIGNAL ;
    SHAPE ABUTMENT ;
    PORT
      LAYER M5 ;
      RECT 1808.628 0.000 1808.652 0.192 ;
    END
  END pma_tx[440]
  PIN pma_tx[441]
    DIRECTION OUTPUT ;
    USE SIGNAL ;
    SHAPE ABUTMENT ;
    PORT
      LAYER M5 ;
      RECT 1812.708 0.000 1812.732 0.192 ;
    END
  END pma_tx[441]
  PIN pma_tx[442]
    DIRECTION OUTPUT ;
    USE SIGNAL ;
    SHAPE ABUTMENT ;
    PORT
      LAYER M5 ;
      RECT 1816.788 0.000 1816.812 0.192 ;
    END
  END pma_tx[442]
  PIN pma_tx[443]
    DIRECTION OUTPUT ;
    USE SIGNAL ;
    SHAPE ABUTMENT ;
    PORT
      LAYER M5 ;
      RECT 1820.868 0.000 1820.892 0.192 ;
    END
  END pma_tx[443]
  PIN pma_tx[444]
    DIRECTION OUTPUT ;
    USE SIGNAL ;
    SHAPE ABUTMENT ;
    PORT
      LAYER M5 ;
      RECT 1824.948 0.000 1824.972 0.192 ;
    END
  END pma_tx[444]
  PIN pma_tx[445]
    DIRECTION OUTPUT ;
    USE SIGNAL ;
    SHAPE ABUTMENT ;
    PORT
      LAYER M5 ;
      RECT 1829.028 0.000 1829.052 0.192 ;
    END
  END pma_tx[445]
  PIN pma_tx[446]
    DIRECTION OUTPUT ;
    USE SIGNAL ;
    SHAPE ABUTMENT ;
    PORT
      LAYER M5 ;
      RECT 1833.108 0.000 1833.132 0.192 ;
    END
  END pma_tx[446]
  PIN pma_tx[447]
    DIRECTION OUTPUT ;
    USE SIGNAL ;
    SHAPE ABUTMENT ;
    PORT
      LAYER M5 ;
      RECT 1837.188 0.000 1837.212 0.192 ;
    END
  END pma_tx[447]
  PIN pma_tx[448]
    DIRECTION OUTPUT ;
    USE SIGNAL ;
    SHAPE ABUTMENT ;
    PORT
      LAYER M5 ;
      RECT 1841.268 0.000 1841.292 0.192 ;
    END
  END pma_tx[448]
  PIN pma_tx[449]
    DIRECTION OUTPUT ;
    USE SIGNAL ;
    SHAPE ABUTMENT ;
    PORT
      LAYER M5 ;
      RECT 1845.348 0.000 1845.372 0.192 ;
    END
  END pma_tx[449]
  PIN pma_tx[450]
    DIRECTION OUTPUT ;
    USE SIGNAL ;
    SHAPE ABUTMENT ;
    PORT
      LAYER M5 ;
      RECT 1849.428 0.000 1849.452 0.192 ;
    END
  END pma_tx[450]
  PIN pma_tx[451]
    DIRECTION OUTPUT ;
    USE SIGNAL ;
    SHAPE ABUTMENT ;
    PORT
      LAYER M5 ;
      RECT 1853.508 0.000 1853.532 0.192 ;
    END
  END pma_tx[451]
  PIN pma_tx[452]
    DIRECTION OUTPUT ;
    USE SIGNAL ;
    SHAPE ABUTMENT ;
    PORT
      LAYER M5 ;
      RECT 1857.588 0.000 1857.612 0.192 ;
    END
  END pma_tx[452]
  PIN pma_tx[453]
    DIRECTION OUTPUT ;
    USE SIGNAL ;
    SHAPE ABUTMENT ;
    PORT
      LAYER M5 ;
      RECT 1861.668 0.000 1861.692 0.192 ;
    END
  END pma_tx[453]
  PIN pma_tx[454]
    DIRECTION OUTPUT ;
    USE SIGNAL ;
    SHAPE ABUTMENT ;
    PORT
      LAYER M5 ;
      RECT 1865.748 0.000 1865.772 0.192 ;
    END
  END pma_tx[454]
  PIN pma_tx[455]
    DIRECTION OUTPUT ;
    USE SIGNAL ;
    SHAPE ABUTMENT ;
    PORT
      LAYER M5 ;
      RECT 1869.828 0.000 1869.852 0.192 ;
    END
  END pma_tx[455]
  PIN pma_tx[456]
    DIRECTION OUTPUT ;
    USE SIGNAL ;
    SHAPE ABUTMENT ;
    PORT
      LAYER M5 ;
      RECT 1873.908 0.000 1873.932 0.192 ;
    END
  END pma_tx[456]
  PIN pma_tx[457]
    DIRECTION OUTPUT ;
    USE SIGNAL ;
    SHAPE ABUTMENT ;
    PORT
      LAYER M5 ;
      RECT 1877.988 0.000 1878.012 0.192 ;
    END
  END pma_tx[457]
  PIN pma_tx[458]
    DIRECTION OUTPUT ;
    USE SIGNAL ;
    SHAPE ABUTMENT ;
    PORT
      LAYER M5 ;
      RECT 1882.068 0.000 1882.092 0.192 ;
    END
  END pma_tx[458]
  PIN pma_tx[459]
    DIRECTION OUTPUT ;
    USE SIGNAL ;
    SHAPE ABUTMENT ;
    PORT
      LAYER M5 ;
      RECT 1886.148 0.000 1886.172 0.192 ;
    END
  END pma_tx[459]
  PIN pma_tx[460]
    DIRECTION OUTPUT ;
    USE SIGNAL ;
    SHAPE ABUTMENT ;
    PORT
      LAYER M5 ;
      RECT 1890.228 0.000 1890.252 0.192 ;
    END
  END pma_tx[460]
  PIN pma_tx[461]
    DIRECTION OUTPUT ;
    USE SIGNAL ;
    SHAPE ABUTMENT ;
    PORT
      LAYER M5 ;
      RECT 1894.308 0.000 1894.332 0.192 ;
    END
  END pma_tx[461]
  PIN pma_tx[462]
    DIRECTION OUTPUT ;
    USE SIGNAL ;
    SHAPE ABUTMENT ;
    PORT
      LAYER M5 ;
      RECT 1898.388 0.000 1898.412 0.192 ;
    END
  END pma_tx[462]
  PIN pma_tx[463]
    DIRECTION OUTPUT ;
    USE SIGNAL ;
    SHAPE ABUTMENT ;
    PORT
      LAYER M5 ;
      RECT 1902.468 0.000 1902.492 0.192 ;
    END
  END pma_tx[463]
  PIN pma_tx[464]
    DIRECTION OUTPUT ;
    USE SIGNAL ;
    SHAPE ABUTMENT ;
    PORT
      LAYER M5 ;
      RECT 1906.548 0.000 1906.572 0.192 ;
    END
  END pma_tx[464]
  PIN pma_tx[465]
    DIRECTION OUTPUT ;
    USE SIGNAL ;
    SHAPE ABUTMENT ;
    PORT
      LAYER M5 ;
      RECT 1910.628 0.000 1910.652 0.192 ;
    END
  END pma_tx[465]
  PIN pma_tx[466]
    DIRECTION OUTPUT ;
    USE SIGNAL ;
    SHAPE ABUTMENT ;
    PORT
      LAYER M5 ;
      RECT 1914.708 0.000 1914.732 0.192 ;
    END
  END pma_tx[466]
  PIN pma_tx[467]
    DIRECTION OUTPUT ;
    USE SIGNAL ;
    SHAPE ABUTMENT ;
    PORT
      LAYER M5 ;
      RECT 1918.788 0.000 1918.812 0.192 ;
    END
  END pma_tx[467]
  PIN pma_tx[468]
    DIRECTION OUTPUT ;
    USE SIGNAL ;
    SHAPE ABUTMENT ;
    PORT
      LAYER M5 ;
      RECT 1922.868 0.000 1922.892 0.192 ;
    END
  END pma_tx[468]
  PIN pma_tx[469]
    DIRECTION OUTPUT ;
    USE SIGNAL ;
    SHAPE ABUTMENT ;
    PORT
      LAYER M5 ;
      RECT 1926.948 0.000 1926.972 0.192 ;
    END
  END pma_tx[469]
  PIN pma_tx[470]
    DIRECTION OUTPUT ;
    USE SIGNAL ;
    SHAPE ABUTMENT ;
    PORT
      LAYER M5 ;
      RECT 1931.028 0.000 1931.052 0.192 ;
    END
  END pma_tx[470]
  PIN pma_tx[471]
    DIRECTION OUTPUT ;
    USE SIGNAL ;
    SHAPE ABUTMENT ;
    PORT
      LAYER M5 ;
      RECT 1935.108 0.000 1935.132 0.192 ;
    END
  END pma_tx[471]
  PIN pma_tx[472]
    DIRECTION OUTPUT ;
    USE SIGNAL ;
    SHAPE ABUTMENT ;
    PORT
      LAYER M5 ;
      RECT 1939.188 0.000 1939.212 0.192 ;
    END
  END pma_tx[472]
  PIN pma_tx[473]
    DIRECTION OUTPUT ;
    USE SIGNAL ;
    SHAPE ABUTMENT ;
    PORT
      LAYER M5 ;
      RECT 1943.268 0.000 1943.292 0.192 ;
    END
  END pma_tx[473]
  PIN pma_tx[474]
    DIRECTION OUTPUT ;
    USE SIGNAL ;
    SHAPE ABUTMENT ;
    PORT
      LAYER M5 ;
      RECT 1947.348 0.000 1947.372 0.192 ;
    END
  END pma_tx[474]
  PIN pma_tx[475]
    DIRECTION OUTPUT ;
    USE SIGNAL ;
    SHAPE ABUTMENT ;
    PORT
      LAYER M5 ;
      RECT 1951.428 0.000 1951.452 0.192 ;
    END
  END pma_tx[475]
  PIN pma_tx[476]
    DIRECTION OUTPUT ;
    USE SIGNAL ;
    SHAPE ABUTMENT ;
    PORT
      LAYER M5 ;
      RECT 1955.508 0.000 1955.532 0.192 ;
    END
  END pma_tx[476]
  PIN pma_tx[477]
    DIRECTION OUTPUT ;
    USE SIGNAL ;
    SHAPE ABUTMENT ;
    PORT
      LAYER M5 ;
      RECT 1959.588 0.000 1959.612 0.192 ;
    END
  END pma_tx[477]
  PIN pma_tx[478]
    DIRECTION OUTPUT ;
    USE SIGNAL ;
    SHAPE ABUTMENT ;
    PORT
      LAYER M5 ;
      RECT 1963.668 0.000 1963.692 0.192 ;
    END
  END pma_tx[478]
  PIN pma_tx[479]
    DIRECTION OUTPUT ;
    USE SIGNAL ;
    SHAPE ABUTMENT ;
    PORT
      LAYER M5 ;
      RECT 1967.748 0.000 1967.772 0.192 ;
    END
  END pma_tx[479]
  PIN pma_tx[480]
    DIRECTION OUTPUT ;
    USE SIGNAL ;
    SHAPE ABUTMENT ;
    PORT
      LAYER M5 ;
      RECT 1971.828 0.000 1971.852 0.192 ;
    END
  END pma_tx[480]
  PIN pma_tx[481]
    DIRECTION OUTPUT ;
    USE SIGNAL ;
    SHAPE ABUTMENT ;
    PORT
      LAYER M5 ;
      RECT 1975.908 0.000 1975.932 0.192 ;
    END
  END pma_tx[481]
  PIN pma_tx[482]
    DIRECTION OUTPUT ;
    USE SIGNAL ;
    SHAPE ABUTMENT ;
    PORT
      LAYER M5 ;
      RECT 1979.988 0.000 1980.012 0.192 ;
    END
  END pma_tx[482]
  PIN pma_tx[483]
    DIRECTION OUTPUT ;
    USE SIGNAL ;
    SHAPE ABUTMENT ;
    PORT
      LAYER M5 ;
      RECT 1984.068 0.000 1984.092 0.192 ;
    END
  END pma_tx[483]
  PIN pma_tx[484]
    DIRECTION OUTPUT ;
    USE SIGNAL ;
    SHAPE ABUTMENT ;
    PORT
      LAYER M5 ;
      RECT 1988.148 0.000 1988.172 0.192 ;
    END
  END pma_tx[484]
  PIN pma_tx[485]
    DIRECTION OUTPUT ;
    USE SIGNAL ;
    SHAPE ABUTMENT ;
    PORT
      LAYER M5 ;
      RECT 1992.228 0.000 1992.252 0.192 ;
    END
  END pma_tx[485]
  PIN pma_tx[486]
    DIRECTION OUTPUT ;
    USE SIGNAL ;
    SHAPE ABUTMENT ;
    PORT
      LAYER M5 ;
      RECT 1996.308 0.000 1996.332 0.192 ;
    END
  END pma_tx[486]
  PIN pma_tx[487]
    DIRECTION OUTPUT ;
    USE SIGNAL ;
    SHAPE ABUTMENT ;
    PORT
      LAYER M5 ;
      RECT 2000.388 0.000 2000.412 0.192 ;
    END
  END pma_tx[487]
  PIN pma_tx[488]
    DIRECTION OUTPUT ;
    USE SIGNAL ;
    SHAPE ABUTMENT ;
    PORT
      LAYER M5 ;
      RECT 2004.468 0.000 2004.492 0.192 ;
    END
  END pma_tx[488]
  PIN pma_tx[489]
    DIRECTION OUTPUT ;
    USE SIGNAL ;
    SHAPE ABUTMENT ;
    PORT
      LAYER M5 ;
      RECT 2008.548 0.000 2008.572 0.192 ;
    END
  END pma_tx[489]
  PIN pma_tx[490]
    DIRECTION OUTPUT ;
    USE SIGNAL ;
    SHAPE ABUTMENT ;
    PORT
      LAYER M5 ;
      RECT 2012.628 0.000 2012.652 0.192 ;
    END
  END pma_tx[490]
  PIN pma_tx[491]
    DIRECTION OUTPUT ;
    USE SIGNAL ;
    SHAPE ABUTMENT ;
    PORT
      LAYER M5 ;
      RECT 2016.708 0.000 2016.732 0.192 ;
    END
  END pma_tx[491]
  PIN pma_tx[492]
    DIRECTION OUTPUT ;
    USE SIGNAL ;
    SHAPE ABUTMENT ;
    PORT
      LAYER M5 ;
      RECT 2020.788 0.000 2020.812 0.192 ;
    END
  END pma_tx[492]
  PIN pma_tx[493]
    DIRECTION OUTPUT ;
    USE SIGNAL ;
    SHAPE ABUTMENT ;
    PORT
      LAYER M5 ;
      RECT 2024.868 0.000 2024.892 0.192 ;
    END
  END pma_tx[493]
  PIN pma_tx[494]
    DIRECTION OUTPUT ;
    USE SIGNAL ;
    SHAPE ABUTMENT ;
    PORT
      LAYER M5 ;
      RECT 2028.948 0.000 2028.972 0.192 ;
    END
  END pma_tx[494]
  PIN pma_tx[495]
    DIRECTION OUTPUT ;
    USE SIGNAL ;
    SHAPE ABUTMENT ;
    PORT
      LAYER M5 ;
      RECT 2033.028 0.000 2033.052 0.192 ;
    END
  END pma_tx[495]
  PIN pma_tx[496]
    DIRECTION OUTPUT ;
    USE SIGNAL ;
    SHAPE ABUTMENT ;
    PORT
      LAYER M5 ;
      RECT 2037.108 0.000 2037.132 0.192 ;
    END
  END pma_tx[496]
  PIN pma_tx[497]
    DIRECTION OUTPUT ;
    USE SIGNAL ;
    SHAPE ABUTMENT ;
    PORT
      LAYER M5 ;
      RECT 2041.188 0.000 2041.212 0.192 ;
    END
  END pma_tx[497]
  PIN pma_tx[498]
    DIRECTION OUTPUT ;
    USE SIGNAL ;
    SHAPE ABUTMENT ;
    PORT
      LAYER M5 ;
      RECT 2045.268 0.000 2045.292 0.192 ;
    END
  END pma_tx[498]
  PIN pma_tx[499]
    DIRECTION OUTPUT ;
    USE SIGNAL ;
    SHAPE ABUTMENT ;
    PORT
      LAYER M5 ;
      RECT 2049.348 0.000 2049.372 0.192 ;
    END
  END pma_tx[499]
  PIN pma_tx[500]
    DIRECTION OUTPUT ;
    USE SIGNAL ;
    SHAPE ABUTMENT ;
    PORT
      LAYER M5 ;
      RECT 2053.428 0.000 2053.452 0.192 ;
    END
  END pma_tx[500]
  PIN pma_tx[501]
    DIRECTION OUTPUT ;
    USE SIGNAL ;
    SHAPE ABUTMENT ;
    PORT
      LAYER M5 ;
      RECT 2057.508 0.000 2057.532 0.192 ;
    END
  END pma_tx[501]
  PIN pma_tx[502]
    DIRECTION OUTPUT ;
    USE SIGNAL ;
    SHAPE ABUTMENT ;
    PORT
      LAYER M5 ;
      RECT 2061.588 0.000 2061.612 0.192 ;
    END
  END pma_tx[502]
  PIN pma_tx[503]
    DIRECTION OUTPUT ;
    USE SIGNAL ;
    SHAPE ABUTMENT ;
    PORT
      LAYER M5 ;
      RECT 2065.668 0.000 2065.692 0.192 ;
    END
  END pma_tx[503]
  PIN pma_tx[504]
    DIRECTION OUTPUT ;
    USE SIGNAL ;
    SHAPE ABUTMENT ;
    PORT
      LAYER M5 ;
      RECT 2069.748 0.000 2069.772 0.192 ;
    END
  END pma_tx[504]
  PIN pma_tx[505]
    DIRECTION OUTPUT ;
    USE SIGNAL ;
    SHAPE ABUTMENT ;
    PORT
      LAYER M5 ;
      RECT 2073.828 0.000 2073.852 0.192 ;
    END
  END pma_tx[505]
  PIN pma_tx[506]
    DIRECTION OUTPUT ;
    USE SIGNAL ;
    SHAPE ABUTMENT ;
    PORT
      LAYER M5 ;
      RECT 2077.908 0.000 2077.932 0.192 ;
    END
  END pma_tx[506]
  PIN pma_tx[507]
    DIRECTION OUTPUT ;
    USE SIGNAL ;
    SHAPE ABUTMENT ;
    PORT
      LAYER M5 ;
      RECT 2081.988 0.000 2082.012 0.192 ;
    END
  END pma_tx[507]
  PIN pma_tx[508]
    DIRECTION OUTPUT ;
    USE SIGNAL ;
    SHAPE ABUTMENT ;
    PORT
      LAYER M5 ;
      RECT 2086.068 0.000 2086.092 0.192 ;
    END
  END pma_tx[508]
  PIN pma_tx[509]
    DIRECTION OUTPUT ;
    USE SIGNAL ;
    SHAPE ABUTMENT ;
    PORT
      LAYER M5 ;
      RECT 2090.148 0.000 2090.172 0.192 ;
    END
  END pma_tx[509]
  PIN pma_tx[510]
    DIRECTION OUTPUT ;
    USE SIGNAL ;
    SHAPE ABUTMENT ;
    PORT
      LAYER M5 ;
      RECT 2094.228 0.000 2094.252 0.192 ;
    END
  END pma_tx[510]
  PIN pma_tx[511]
    DIRECTION OUTPUT ;
    USE SIGNAL ;
    SHAPE ABUTMENT ;
    PORT
      LAYER M5 ;
      RECT 2098.308 0.000 2098.332 0.192 ;
    END
  END pma_tx[511]
  PIN pma_tx[512]
    DIRECTION OUTPUT ;
    USE SIGNAL ;
    SHAPE ABUTMENT ;
    PORT
      LAYER M5 ;
      RECT 2102.388 0.000 2102.412 0.192 ;
    END
  END pma_tx[512]
  PIN pma_tx[513]
    DIRECTION OUTPUT ;
    USE SIGNAL ;
    SHAPE ABUTMENT ;
    PORT
      LAYER M5 ;
      RECT 2106.468 0.000 2106.492 0.192 ;
    END
  END pma_tx[513]
  PIN pma_tx[514]
    DIRECTION OUTPUT ;
    USE SIGNAL ;
    SHAPE ABUTMENT ;
    PORT
      LAYER M5 ;
      RECT 2110.548 0.000 2110.572 0.192 ;
    END
  END pma_tx[514]
  PIN pma_tx[515]
    DIRECTION OUTPUT ;
    USE SIGNAL ;
    SHAPE ABUTMENT ;
    PORT
      LAYER M5 ;
      RECT 2114.628 0.000 2114.652 0.192 ;
    END
  END pma_tx[515]
  PIN pma_tx[516]
    DIRECTION OUTPUT ;
    USE SIGNAL ;
    SHAPE ABUTMENT ;
    PORT
      LAYER M5 ;
      RECT 2118.708 0.000 2118.732 0.192 ;
    END
  END pma_tx[516]
  PIN pma_tx[517]
    DIRECTION OUTPUT ;
    USE SIGNAL ;
    SHAPE ABUTMENT ;
    PORT
      LAYER M5 ;
      RECT 2122.788 0.000 2122.812 0.192 ;
    END
  END pma_tx[517]
  PIN pma_tx[518]
    DIRECTION OUTPUT ;
    USE SIGNAL ;
    SHAPE ABUTMENT ;
    PORT
      LAYER M5 ;
      RECT 2126.868 0.000 2126.892 0.192 ;
    END
  END pma_tx[518]
  PIN pma_tx[519]
    DIRECTION OUTPUT ;
    USE SIGNAL ;
    SHAPE ABUTMENT ;
    PORT
      LAYER M5 ;
      RECT 2130.948 0.000 2130.972 0.192 ;
    END
  END pma_tx[519]
  PIN pma_tx[520]
    DIRECTION OUTPUT ;
    USE SIGNAL ;
    SHAPE ABUTMENT ;
    PORT
      LAYER M5 ;
      RECT 2135.028 0.000 2135.052 0.192 ;
    END
  END pma_tx[520]
  PIN pma_tx[521]
    DIRECTION OUTPUT ;
    USE SIGNAL ;
    SHAPE ABUTMENT ;
    PORT
      LAYER M5 ;
      RECT 2139.108 0.000 2139.132 0.192 ;
    END
  END pma_tx[521]
  PIN pma_tx[522]
    DIRECTION OUTPUT ;
    USE SIGNAL ;
    SHAPE ABUTMENT ;
    PORT
      LAYER M5 ;
      RECT 2143.188 0.000 2143.212 0.192 ;
    END
  END pma_tx[522]
  PIN pma_tx[523]
    DIRECTION OUTPUT ;
    USE SIGNAL ;
    SHAPE ABUTMENT ;
    PORT
      LAYER M5 ;
      RECT 2147.268 0.000 2147.292 0.192 ;
    END
  END pma_tx[523]
  PIN pma_tx[524]
    DIRECTION OUTPUT ;
    USE SIGNAL ;
    SHAPE ABUTMENT ;
    PORT
      LAYER M5 ;
      RECT 2151.348 0.000 2151.372 0.192 ;
    END
  END pma_tx[524]
  PIN pma_tx[525]
    DIRECTION OUTPUT ;
    USE SIGNAL ;
    SHAPE ABUTMENT ;
    PORT
      LAYER M5 ;
      RECT 2155.428 0.000 2155.452 0.192 ;
    END
  END pma_tx[525]
  PIN pma_tx[526]
    DIRECTION OUTPUT ;
    USE SIGNAL ;
    SHAPE ABUTMENT ;
    PORT
      LAYER M5 ;
      RECT 2159.508 0.000 2159.532 0.192 ;
    END
  END pma_tx[526]
  PIN pma_tx[527]
    DIRECTION OUTPUT ;
    USE SIGNAL ;
    SHAPE ABUTMENT ;
    PORT
      LAYER M5 ;
      RECT 2163.588 0.000 2163.612 0.192 ;
    END
  END pma_tx[527]
  PIN pma_tx[528]
    DIRECTION OUTPUT ;
    USE SIGNAL ;
    SHAPE ABUTMENT ;
    PORT
      LAYER M5 ;
      RECT 2167.668 0.000 2167.692 0.192 ;
    END
  END pma_tx[528]
  PIN pma_tx[529]
    DIRECTION OUTPUT ;
    USE SIGNAL ;
    SHAPE ABUTMENT ;
    PORT
      LAYER M5 ;
      RECT 2171.748 0.000 2171.772 0.192 ;
    END
  END pma_tx[529]
  PIN pma_tx[530]
    DIRECTION OUTPUT ;
    USE SIGNAL ;
    SHAPE ABUTMENT ;
    PORT
      LAYER M5 ;
      RECT 2175.828 0.000 2175.852 0.192 ;
    END
  END pma_tx[530]
  PIN pma_tx[531]
    DIRECTION OUTPUT ;
    USE SIGNAL ;
    SHAPE ABUTMENT ;
    PORT
      LAYER M5 ;
      RECT 2179.908 0.000 2179.932 0.192 ;
    END
  END pma_tx[531]
  PIN pma_tx[532]
    DIRECTION OUTPUT ;
    USE SIGNAL ;
    SHAPE ABUTMENT ;
    PORT
      LAYER M5 ;
      RECT 2183.988 0.000 2184.012 0.192 ;
    END
  END pma_tx[532]
  PIN pma_tx[533]
    DIRECTION OUTPUT ;
    USE SIGNAL ;
    SHAPE ABUTMENT ;
    PORT
      LAYER M5 ;
      RECT 2188.068 0.000 2188.092 0.192 ;
    END
  END pma_tx[533]
  PIN pma_tx[534]
    DIRECTION OUTPUT ;
    USE SIGNAL ;
    SHAPE ABUTMENT ;
    PORT
      LAYER M5 ;
      RECT 2192.148 0.000 2192.172 0.192 ;
    END
  END pma_tx[534]
  PIN pma_tx[535]
    DIRECTION OUTPUT ;
    USE SIGNAL ;
    SHAPE ABUTMENT ;
    PORT
      LAYER M5 ;
      RECT 2196.228 0.000 2196.252 0.192 ;
    END
  END pma_tx[535]
  PIN pma_tx[536]
    DIRECTION OUTPUT ;
    USE SIGNAL ;
    SHAPE ABUTMENT ;
    PORT
      LAYER M5 ;
      RECT 2200.308 0.000 2200.332 0.192 ;
    END
  END pma_tx[536]
  PIN pma_tx[537]
    DIRECTION OUTPUT ;
    USE SIGNAL ;
    SHAPE ABUTMENT ;
    PORT
      LAYER M5 ;
      RECT 2204.388 0.000 2204.412 0.192 ;
    END
  END pma_tx[537]
  PIN pma_tx[538]
    DIRECTION OUTPUT ;
    USE SIGNAL ;
    SHAPE ABUTMENT ;
    PORT
      LAYER M5 ;
      RECT 2208.468 0.000 2208.492 0.192 ;
    END
  END pma_tx[538]
  PIN pma_tx[539]
    DIRECTION OUTPUT ;
    USE SIGNAL ;
    SHAPE ABUTMENT ;
    PORT
      LAYER M5 ;
      RECT 2212.548 0.000 2212.572 0.192 ;
    END
  END pma_tx[539]
  PIN pma_tx[540]
    DIRECTION OUTPUT ;
    USE SIGNAL ;
    SHAPE ABUTMENT ;
    PORT
      LAYER M5 ;
      RECT 2216.628 0.000 2216.652 0.192 ;
    END
  END pma_tx[540]
  PIN pma_tx[541]
    DIRECTION OUTPUT ;
    USE SIGNAL ;
    SHAPE ABUTMENT ;
    PORT
      LAYER M5 ;
      RECT 2220.708 0.000 2220.732 0.192 ;
    END
  END pma_tx[541]
  PIN pma_tx[542]
    DIRECTION OUTPUT ;
    USE SIGNAL ;
    SHAPE ABUTMENT ;
    PORT
      LAYER M5 ;
      RECT 2224.788 0.000 2224.812 0.192 ;
    END
  END pma_tx[542]
  PIN pma_tx[543]
    DIRECTION OUTPUT ;
    USE SIGNAL ;
    SHAPE ABUTMENT ;
    PORT
      LAYER M5 ;
      RECT 2228.868 0.000 2228.892 0.192 ;
    END
  END pma_tx[543]
  PIN pma_tck
    DIRECTION OUTPUT ;
    USE SIGNAL ;
    SHAPE ABUTMENT ;
    PORT
      LAYER M5 ;
      RECT 2232.948 0.000 2232.972 0.192 ;
    END
  END pma_tck
  PIN VDD
    DIRECTION INOUT ;
    USE POWER ;
    PORT
      LAYER M5 ;
      RECT 0.300 2.000 0.420 127.600 ;
      RECT 5.700 2.000 5.820 127.600 ;
      RECT 11.100 2.000 11.220 127.600 ;
      RECT 16.500 2.000 16.620 127.600 ;
      RECT 21.900 2.000 22.020 127.600 ;
      RECT 27.300 2.000 27.420 127.600 ;
      RECT 32.700 2.000 32.820 127.600 ;
      RECT 38.100 2.000 38.220 127.600 ;
      RECT 43.500 2.000 43.620 127.600 ;
      RECT 48.900 2.000 49.020 127.600 ;
      RECT 54.300 2.000 54.420 127.600 ;
      RECT 59.700 2.000 59.820 127.600 ;
      RECT 65.100 2.000 65.220 127.600 ;
      RECT 70.500 2.000 70.620 127.600 ;
      RECT 75.900 2.000 76.020 127.600 ;
      RECT 81.300 2.000 81.420 127.600 ;
      RECT 86.700 2.000 86.820 127.600 ;
      RECT 92.100 2.000 92.220 127.600 ;
      RECT 97.500 2.000 97.620 127.600 ;
      RECT 102.900 2.000 103.020 127.600 ;
      RECT 108.300 2.000 108.420 127.600 ;
      RECT 113.700 2.000 113.820 127.600 ;
      RECT 119.100 2.000 119.220 127.600 ;
      RECT 124.500 2.000 124.620 127.600 ;
      RECT 129.900 2.000 130.020 127.600 ;
      RECT 135.300 2.000 135.420 127.600 ;
      RECT 140.700 2.000 140.820 127.600 ;
      RECT 146.100 2.000 146.220 127.600 ;
      RECT 151.500 2.000 151.620 127.600 ;
      RECT 156.900 2.000 157.020 127.600 ;
      RECT 162.300 2.000 162.420 127.600 ;
      RECT 167.700 2.000 167.820 127.600 ;
      RECT 173.100 2.000 173.220 127.600 ;
      RECT 178.500 2.000 178.620 127.600 ;
      RECT 183.900 2.000 184.020 127.600 ;
      RECT 189.300 2.000 189.420 127.600 ;
      RECT 194.700 2.000 194.820 127.600 ;
      RECT 200.100 2.000 200.220 127.600 ;
      RECT 205.500 2.000 205.620 127.600 ;
      RECT 210.900 2.000 211.020 127.600 ;
      RECT 216.300 2.000 216.420 127.600 ;
      RECT 221.700 2.000 221.820 127.600 ;
      RECT 227.100 2.000 227.220 127.600 ;
      RECT 232.500 2.000 232.620 127.600 ;
      RECT 237.900 2.000 238.020 127.600 ;
      RECT 243.300 2.000 243.420 127.600 ;
      RECT 248.700 2.000 248.820 127.600 ;
      RECT 254.100 2.000 254.220 127.600 ;
      RECT 259.500 2.000 259.620 127.600 ;
      RECT 264.900 2.000 265.020 127.600 ;
      RECT 270.300 2.000 270.420 127.600 ;
      RECT 275.700 2.000 275.820 127.600 ;
      RECT 281.100 2.000 281.220 127.600 ;
      RECT 286.500 2.000 286.620 127.600 ;
      RECT 291.900 2.000 292.020 127.600 ;
      RECT 297.300 2.000 297.420 127.600 ;
      RECT 302.700 2.000 302.820 127.600 ;
      RECT 308.100 2.000 308.220 127.600 ;
      RECT 313.500 2.000 313.620 127.600 ;
      RECT 318.900 2.000 319.020 127.600 ;
      RECT 324.300 2.000 324.420 127.600 ;
      RECT 329.700 2.000 329.820 127.600 ;
      RECT 335.100 2.000 335.220 127.600 ;
      RECT 340.500 2.000 340.620 127.600 ;
      RECT 345.900 2.000 346.020 127.600 ;
      RECT 351.300 2.000 351.420 127.600 ;
      RECT 356.700 2.000 356.820 127.600 ;
      RECT 362.100 2.000 362.220 127.600 ;
      RECT 367.500 2.000 367.620 127.600 ;
      RECT 372.900 2.000 373.020 127.600 ;
      RECT 378.300 2.000 378.420 127.600 ;
      RECT 383.700 2.000 383.820 127.600 ;
      RECT 389.100 2.000 389.220 127.600 ;
      RECT 394.500 2.000 394.620 127.600 ;
      RECT 399.900 2.000 400.020 127.600 ;
      RECT 405.300 2.000 405.420 127.600 ;
      RECT 410.700 2.000 410.820 127.600 ;
      RECT 416.100 2.000 416.220 127.600 ;
      RECT 421.500 2.000 421.620 127.600 ;
      RECT 426.900 2.000 427.020 127.600 ;
      RECT 432.300 2.000 432.420 127.600 ;
      RECT 437.700 2.000 437.820 127.600 ;
      RECT 443.100 2.000 443.220 127.600 ;
      RECT 448.500 2.000 448.620 127.600 ;
      RECT 453.900 2.000 454.020 127.600 ;
      RECT 459.300 2.000 459.420 127.600 ;
      RECT 464.700 2.000 464.820 127.600 ;
      RECT 470.100 2.000 470.220 127.600 ;
      RECT 475.500 2.000 475.620 127.600 ;
      RECT 480.900 2.000 481.020 127.600 ;
      RECT 486.300 2.000 486.420 127.600 ;
      RECT 491.700 2.000 491.820 127.600 ;
      RECT 497.100 2.000 497.220 127.600 ;
      RECT 502.500 2.000 502.620 127.600 ;
      RECT 507.900 2.000 508.020 127.600 ;
      RECT 513.300 2.000 513.420 127.600 ;
      RECT 518.700 2.000 518.820 127.600 ;
      RECT 524.100 2.000 524.220 127.600 ;
      RECT 529.500 2.000 529.620 127.600 ;
      RECT 534.900 2.000 535.020 127.600 ;
      RECT 540.300 2.000 540.420 127.600 ;
      RECT 545.700 2.000 545.820 127.600 ;
      RECT 551.100 2.000 551.220 127.600 ;
      RECT 556.500 2.000 556.620 127.600 ;
      RECT 561.900 2.000 562.020 127.600 ;
      RECT 567.300 2.000 567.420 127.600 ;
      RECT 572.700 2.000 572.820 127.600 ;
      RECT 578.100 2.000 578.220 127.600 ;
      RECT 583.500 2.000 583.620 127.600 ;
      RECT 588.900 2.000 589.020 127.600 ;
      RECT 594.300 2.000 594.420 127.600 ;
      RECT 599.700 2.000 599.820 127.600 ;
      RECT 605.100 2.000 605.220 127.600 ;
      RECT 610.500 2.000 610.620 127.600 ;
      RECT 615.900 2.000 616.020 127.600 ;
      RECT 621.300 2.000 621.420 127.600 ;
      RECT 626.700 2.000 626.820 127.600 ;
      RECT 632.100 2.000 632.220 127.600 ;
      RECT 637.500 2.000 637.620 127.600 ;
      RECT 642.900 2.000 643.020 127.600 ;
      RECT 648.300 2.000 648.420 127.600 ;
      RECT 653.700 2.000 653.820 127.600 ;
      RECT 659.100 2.000 659.220 127.600 ;
      RECT 664.500 2.000 664.620 127.600 ;
      RECT 669.900 2.000 670.020 127.600 ;
      RECT 675.300 2.000 675.420 127.600 ;
      RECT 680.700 2.000 680.820 127.600 ;
      RECT 686.100 2.000 686.220 127.600 ;
      RECT 691.500 2.000 691.620 127.600 ;
      RECT 696.900 2.000 697.020 127.600 ;
      RECT 702.300 2.000 702.420 127.600 ;
      RECT 707.700 2.000 707.820 127.600 ;
      RECT 713.100 2.000 713.220 127.600 ;
      RECT 718.500 2.000 718.620 127.600 ;
      RECT 723.900 2.000 724.020 127.600 ;
      RECT 729.300 2.000 729.420 127.600 ;
      RECT 734.700 2.000 734.820 127.600 ;
      RECT 740.100 2.000 740.220 127.600 ;
      RECT 745.500 2.000 745.620 127.600 ;
      RECT 750.900 2.000 751.020 127.600 ;
      RECT 756.300 2.000 756.420 127.600 ;
      RECT 761.700 2.000 761.820 127.600 ;
      RECT 767.100 2.000 767.220 127.600 ;
      RECT 772.500 2.000 772.620 127.600 ;
      RECT 777.900 2.000 778.020 127.600 ;
      RECT 783.300 2.000 783.420 127.600 ;
      RECT 788.700 2.000 788.820 127.600 ;
      RECT 794.100 2.000 794.220 127.600 ;
      RECT 799.500 2.000 799.620 127.600 ;
      RECT 804.900 2.000 805.020 127.600 ;
      RECT 810.300 2.000 810.420 127.600 ;
      RECT 815.700 2.000 815.820 127.600 ;
      RECT 821.100 2.000 821.220 127.600 ;
      RECT 826.500 2.000 826.620 127.600 ;
      RECT 831.900 2.000 832.020 127.600 ;
      RECT 837.300 2.000 837.420 127.600 ;
      RECT 842.700 2.000 842.820 127.600 ;
      RECT 848.100 2.000 848.220 127.600 ;
      RECT 853.500 2.000 853.620 127.600 ;
      RECT 858.900 2.000 859.020 127.600 ;
      RECT 864.300 2.000 864.420 127.600 ;
      RECT 869.700 2.000 869.820 127.600 ;
      RECT 875.100 2.000 875.220 127.600 ;
      RECT 880.500 2.000 880.620 127.600 ;
      RECT 885.900 2.000 886.020 127.600 ;
      RECT 891.300 2.000 891.420 127.600 ;
      RECT 896.700 2.000 896.820 127.600 ;
      RECT 902.100 2.000 902.220 127.600 ;
      RECT 907.500 2.000 907.620 127.600 ;
      RECT 912.900 2.000 913.020 127.600 ;
      RECT 918.300 2.000 918.420 127.600 ;
      RECT 923.700 2.000 923.820 127.600 ;
      RECT 929.100 2.000 929.220 127.600 ;
      RECT 934.500 2.000 934.620 127.600 ;
      RECT 939.900 2.000 940.020 127.600 ;
      RECT 945.300 2.000 945.420 127.600 ;
      RECT 950.700 2.000 950.820 127.600 ;
      RECT 956.100 2.000 956.220 127.600 ;
      RECT 961.500 2.000 961.620 127.600 ;
      RECT 966.900 2.000 967.020 127.600 ;
      RECT 972.300 2.000 972.420 127.600 ;
      RECT 977.700 2.000 977.820 127.600 ;
      RECT 983.100 2.000 983.220 127.600 ;
      RECT 988.500 2.000 988.620 127.600 ;
      RECT 993.900 2.000 994.020 127.600 ;
      RECT 999.300 2.000 999.420 127.600 ;
      RECT 1004.700 2.000 1004.820 127.600 ;
      RECT 1010.100 2.000 1010.220 127.600 ;
      RECT 1015.500 2.000 1015.620 127.600 ;
      RECT 1020.900 2.000 1021.020 127.600 ;
      RECT 1026.300 2.000 1026.420 127.600 ;
      RECT 1031.700 2.000 1031.820 127.600 ;
      RECT 1037.100 2.000 1037.220 127.600 ;
      RECT 1042.500 2.000 1042.620 127.600 ;
      RECT 1047.900 2.000 1048.020 127.600 ;
      RECT 1053.300 2.000 1053.420 127.600 ;
      RECT 1058.700 2.000 1058.820 127.600 ;
      RECT 1064.100 2.000 1064.220 127.600 ;
      RECT 1069.500 2.000 1069.620 127.600 ;
      RECT 1074.900 2.000 1075.020 127.600 ;
      RECT 1080.300 2.000 1080.420 127.600 ;
      RECT 1085.700 2.000 1085.820 127.600 ;
      RECT 1091.100 2.000 1091.220 127.600 ;
      RECT 1096.500 2.000 1096.620 127.600 ;
      RECT 1101.900 2.000 1102.020 127.600 ;
      RECT 1107.300 2.000 1107.420 127.600 ;
      RECT 1112.700 2.000 1112.820 127.600 ;
      RECT 1118.100 2.000 1118.220 127.600 ;
      RECT 1123.500 2.000 1123.620 127.600 ;
      RECT 1128.900 2.000 1129.020 127.600 ;
      RECT 1134.300 2.000 1134.420 127.600 ;
      RECT 1139.700 2.000 1139.820 127.600 ;
      RECT 1145.100 2.000 1145.220 127.600 ;
      RECT 1150.500 2.000 1150.620 127.600 ;
      RECT 1155.900 2.000 1156.020 127.600 ;
      RECT 1161.300 2.000 1161.420 127.600 ;
      RECT 1166.700 2.000 1166.820 127.600 ;
      RECT 1172.100 2.000 1172.220 127.600 ;
      RECT 1177.500 2.000 1177.620 127.600 ;
      RECT 1182.900 2.000 1183.020 127.600 ;
      RECT 1188.300 2.000 1188.420 127.600 ;
      RECT 1193.700 2.000 1193.820 127.600 ;
      RECT 1199.100 2.000 1199.220 127.600 ;
      RECT 1204.500 2.000 1204.620 127.600 ;
      RECT 1209.900 2.000 1210.020 127.600 ;
      RECT 1215.300 2.000 1215.420 127.600 ;
      RECT 1220.700 2.000 1220.820 127.600 ;
      RECT 1226.100 2.000 1226.220 127.600 ;
      RECT 1231.500 2.000 1231.620 127.600 ;
      RECT 1236.900 2.000 1237.020 127.600 ;
      RECT 1242.300 2.000 1242.420 127.600 ;
      RECT 1247.700 2.000 1247.820 127.600 ;
      RECT 1253.100 2.000 1253.220 127.600 ;
      RECT 1258.500 2.000 1258.620 127.600 ;
      RECT 1263.900 2.000 1264.020 127.600 ;
      RECT 1269.300 2.000 1269.420 127.600 ;
      RECT 1274.700 2.000 1274.820 127.600 ;
      RECT 1280.100 2.000 1280.220 127.600 ;
      RECT 1285.500 2.000 1285.620 127.600 ;
      RECT 1290.900 2.000 1291.020 127.600 ;
      RECT 1296.300 2.000 1296.420 127.600 ;
      RECT 1301.700 2.000 1301.820 127.600 ;
      RECT 1307.100 2.000 1307.220 127.600 ;
      RECT 1312.500 2.000 1312.620 127.600 ;
      RECT 1317.900 2.000 1318.020 127.600 ;
      RECT 1323.300 2.000 1323.420 127.600 ;
      RECT 1328.700 2.000 1328.820 127.600 ;
      RECT 1334.100 2.000 1334.220 127.600 ;
      RECT 1339.500 2.000 1339.620 127.600 ;
      RECT 1344.900 2.000 1345.020 127.600 ;
      RECT 1350.300 2.000 1350.420 127.600 ;
      RECT 1355.700 2.000 1355.820 127.600 ;
      RECT 1361.100 2.000 1361.220 127.600 ;
      RECT 1366.500 2.000 1366.620 127.600 ;
      RECT 1371.900 2.000 1372.020 127.600 ;
      RECT 1377.300 2.000 1377.420 127.600 ;
      RECT 1382.700 2.000 1382.820 127.600 ;
      RECT 1388.100 2.000 1388.220 127.600 ;
      RECT 1393.500 2.000 1393.620 127.600 ;
      RECT 1398.900 2.000 1399.020 127.600 ;
      RECT 1404.300 2.000 1404.420 127.600 ;
      RECT 1409.700 2.000 1409.820 127.600 ;
      RECT 1415.100 2.000 1415.220 127.600 ;
      RECT 1420.500 2.000 1420.620 127.600 ;
      RECT 1425.900 2.000 1426.020 127.600 ;
      RECT 1431.300 2.000 1431.420 127.600 ;
      RECT 1436.700 2.000 1436.820 127.600 ;
      RECT 1442.100 2.000 1442.220 127.600 ;
      RECT 1447.500 2.000 1447.620 127.600 ;
      RECT 1452.900 2.000 1453.020 127.600 ;
      RECT 1458.300 2.000 1458.420 127.600 ;
      RECT 1463.700 2.000 1463.820 127.600 ;
      RECT 1469.100 2.000 1469.220 127.600 ;
      RECT 1474.500 2.000 1474.620 127.600 ;
      RECT 1479.900 2.000 1480.020 127.600 ;
      RECT 1485.300 2.000 1485.420 127.600 ;
      RECT 1490.700 2.000 1490.820 127.600 ;
      RECT 1496.100 2.000 1496.220 127.600 ;
      RECT 1501.500 2.000 1501.620 127.600 ;
      RECT 1506.900 2.000 1507.020 127.600 ;
      RECT 1512.300 2.000 1512.420 127.600 ;
      RECT 1517.700 2.000 1517.820 127.600 ;
      RECT 1523.100 2.000 1523.220 127.600 ;
      RECT 1528.500 2.000 1528.620 127.600 ;
      RECT 1533.900 2.000 1534.020 127.600 ;
      RECT 1539.300 2.000 1539.420 127.600 ;
      RECT 1544.700 2.000 1544.820 127.600 ;
      RECT 1550.100 2.000 1550.220 127.600 ;
      RECT 1555.500 2.000 1555.620 127.600 ;
      RECT 1560.900 2.000 1561.020 127.600 ;
      RECT 1566.300 2.000 1566.420 127.600 ;
      RECT 1571.700 2.000 1571.820 127.600 ;
      RECT 1577.100 2.000 1577.220 127.600 ;
      RECT 1582.500 2.000 1582.620 127.600 ;
      RECT 1587.900 2.000 1588.020 127.600 ;
      RECT 1593.300 2.000 1593.420 127.600 ;
      RECT 1598.700 2.000 1598.820 127.600 ;
      RECT 1604.100 2.000 1604.220 127.600 ;
      RECT 1609.500 2.000 1609.620 127.600 ;
      RECT 1614.900 2.000 1615.020 127.600 ;
      RECT 1620.300 2.000 1620.420 127.600 ;
      RECT 1625.700 2.000 1625.820 127.600 ;
      RECT 1631.100 2.000 1631.220 127.600 ;
      RECT 1636.500 2.000 1636.620 127.600 ;
      RECT 1641.900 2.000 1642.020 127.600 ;
      RECT 1647.300 2.000 1647.420 127.600 ;
      RECT 1652.700 2.000 1652.820 127.600 ;
      RECT 1658.100 2.000 1658.220 127.600 ;
      RECT 1663.500 2.000 1663.620 127.600 ;
      RECT 1668.900 2.000 1669.020 127.600 ;
      RECT 1674.300 2.000 1674.420 127.600 ;
      RECT 1679.700 2.000 1679.820 127.600 ;
      RECT 1685.100 2.000 1685.220 127.600 ;
      RECT 1690.500 2.000 1690.620 127.600 ;
      RECT 1695.900 2.000 1696.020 127.600 ;
      RECT 1701.300 2.000 1701.420 127.600 ;
      RECT 1706.700 2.000 1706.820 127.600 ;
      RECT 1712.100 2.000 1712.220 127.600 ;
      RECT 1717.500 2.000 1717.620 127.600 ;
      RECT 1722.900 2.000 1723.020 127.600 ;
      RECT 1728.300 2.000 1728.420 127.600 ;
      RECT 1733.700 2.000 1733.820 127.600 ;
      RECT 1739.100 2.000 1739.220 127.600 ;
      RECT 1744.500 2.000 1744.620 127.600 ;
      RECT 1749.900 2.000 1750.020 127.600 ;
      RECT 1755.300 2.000 1755.420 127.600 ;
      RECT 1760.700 2.000 1760.820 127.600 ;
      RECT 1766.100 2.000 1766.220 127.600 ;
      RECT 1771.500 2.000 1771.620 127.600 ;
      RECT 1776.900 2.000 1777.020 127.600 ;
      RECT 1782.300 2.000 1782.420 127.600 ;
      RECT 1787.700 2.000 1787.820 127.600 ;
      RECT 1793.100 2.000 1793.220 127.600 ;
      RECT 1798.500 2.000 1798.620 127.600 ;
      RECT 1803.900 2.000 1804.020 127.600 ;
      RECT 1809.300 2.000 1809.420 127.600 ;
      RECT 1814.700 2.000 1814.820 127.600 ;
      RECT 1820.100 2.000 1820.220 127.600 ;
      RECT 1825.500 2.000 1825.620 127.600 ;
      RECT 1830.900 2.000 1831.020 127.600 ;
      RECT 1836.300 2.000 1836.420 127.600 ;
      RECT 1841.700 2.000 1841.820 127.600 ;
      RECT 1847.100 2.000 1847.220 127.600 ;
      RECT 1852.500 2.000 1852.620 127.600 ;
      RECT 1857.900 2.000 1858.020 127.600 ;
      RECT 1863.300 2.000 1863.420 127.600 ;
      RECT 1868.700 2.000 1868.820 127.600 ;
      RECT 1874.100 2.000 1874.220 127.600 ;
      RECT 1879.500 2.000 1879.620 127.600 ;
      RECT 1884.900 2.000 1885.020 127.600 ;
      RECT 1890.300 2.000 1890.420 127.600 ;
      RECT 1895.700 2.000 1895.820 127.600 ;
      RECT 1901.100 2.000 1901.220 127.600 ;
      RECT 1906.500 2.000 1906.620 127.600 ;
      RECT 1911.900 2.000 1912.020 127.600 ;
      RECT 1917.300 2.000 1917.420 127.600 ;
      RECT 1922.700 2.000 1922.820 127.600 ;
      RECT 1928.100 2.000 1928.220 127.600 ;
      RECT 1933.500 2.000 1933.620 127.600 ;
      RECT 1938.900 2.000 1939.020 127.600 ;
      RECT 1944.300 2.000 1944.420 127.600 ;
      RECT 1949.700 2.000 1949.820 127.600 ;
      RECT 1955.100 2.000 1955.220 127.600 ;
      RECT 1960.500 2.000 1960.620 127.600 ;
      RECT 1965.900 2.000 1966.020 127.600 ;
      RECT 1971.300 2.000 1971.420 127.600 ;
      RECT 1976.700 2.000 1976.820 127.600 ;
      RECT 1982.100 2.000 1982.220 127.600 ;
      RECT 1987.500 2.000 1987.620 127.600 ;
      RECT 1992.900 2.000 1993.020 127.600 ;
      RECT 1998.300 2.000 1998.420 127.600 ;
      RECT 2003.700 2.000 2003.820 127.600 ;
      RECT 2009.100 2.000 2009.220 127.600 ;
      RECT 2014.500 2.000 2014.620 127.600 ;
      RECT 2019.900 2.000 2020.020 127.600 ;
      RECT 2025.300 2.000 2025.420 127.600 ;
      RECT 2030.700 2.000 2030.820 127.600 ;
      RECT 2036.100 2.000 2036.220 127.600 ;
      RECT 2041.500 2.000 2041.620 127.600 ;
      RECT 2046.900 2.000 2047.020 127.600 ;
      RECT 2052.300 2.000 2052.420 127.600 ;
      RECT 2057.700 2.000 2057.820 127.600 ;
      RECT 2063.100 2.000 2063.220 127.600 ;
      RECT 2068.500 2.000 2068.620 127.600 ;
      RECT 2073.900 2.000 2074.020 127.600 ;
      RECT 2079.300 2.000 2079.420 127.600 ;
      RECT 2084.700 2.000 2084.820 127.600 ;
      RECT 2090.100 2.000 2090.220 127.600 ;
      RECT 2095.500 2.000 2095.620 127.600 ;
      RECT 2100.900 2.000 2101.020 127.600 ;
      RECT 2106.300 2.000 2106.420 127.600 ;
      RECT 2111.700 2.000 2111.820 127.600 ;
      RECT 2117.100 2.000 2117.220 127.600 ;
      RECT 2122.500 2.000 2122.620 127.600 ;
      RECT 2127.900 2.000 2128.020 127.600 ;
      RECT 2133.300 2.000 2133.420 127.600 ;
      RECT 2138.700 2.000 2138.820 127.600 ;
      RECT 2144.100 2.000 2144.220 127.600 ;
      RECT 2149.500 2.000 2149.620 127.600 ;
      RECT 2154.900 2.000 2155.020 127.600 ;
      RECT 2160.300 2.000 2160.420 127.600 ;
      RECT 2165.700 2.000 2165.820 127.600 ;
      RECT 2171.100 2.000 2171.220 127.600 ;
      RECT 2176.500 2.000 2176.620 127.600 ;
      RECT 2181.900 2.000 2182.020 127.600 ;
      RECT 2187.300 2.000 2187.420 127.600 ;
      RECT 2192.700 2.000 2192.820 127.600 ;
      RECT 2198.100 2.000 2198.220 127.600 ;
      RECT 2203.500 2.000 2203.620 127.600 ;
      RECT 2208.900 2.000 2209.020 127.600 ;
      RECT 2214.300 2.000 2214.420 127.600 ;
      RECT 2219.700 2.000 2219.820 127.600 ;
      RECT 2225.100 2.000 2225.220 127.600 ;
      RECT 2230.500 2.000 2230.620 127.600 ;
      RECT 2235.900 2.000 2236.020 127.600 ;
      RECT 2241.300 2.000 2241.420 127.600 ;
    END
  END VDD
  PIN VSS
    DIRECTION INOUT ;
    USE GROUND ;
    PORT
      LAYER M5 ;
      RECT 0.492 2.000 0.612 127.600 ;
      RECT 5.892 2.000 6.012 127.600 ;
      RECT 11.292 2.000 11.412 127.600 ;
      RECT 16.692 2.000 16.812 127.600 ;
      RECT 22.092 2.000 22.212 127.600 ;
      RECT 27.492 2.000 27.612 127.600 ;
      RECT 32.892 2.000 33.012 127.600 ;
      RECT 38.292 2.000 38.412 127.600 ;
      RECT 43.692 2.000 43.812 127.600 ;
      RECT 49.092 2.000 49.212 127.600 ;
      RECT 54.492 2.000 54.612 127.600 ;
      RECT 59.892 2.000 60.012 127.600 ;
      RECT 65.292 2.000 65.412 127.600 ;
      RECT 70.692 2.000 70.812 127.600 ;
      RECT 76.092 2.000 76.212 127.600 ;
      RECT 81.492 2.000 81.612 127.600 ;
      RECT 86.892 2.000 87.012 127.600 ;
      RECT 92.292 2.000 92.412 127.600 ;
      RECT 97.692 2.000 97.812 127.600 ;
      RECT 103.092 2.000 103.212 127.600 ;
      RECT 108.492 2.000 108.612 127.600 ;
      RECT 113.892 2.000 114.012 127.600 ;
      RECT 119.292 2.000 119.412 127.600 ;
      RECT 124.692 2.000 124.812 127.600 ;
      RECT 130.092 2.000 130.212 127.600 ;
      RECT 135.492 2.000 135.612 127.600 ;
      RECT 140.892 2.000 141.012 127.600 ;
      RECT 146.292 2.000 146.412 127.600 ;
      RECT 151.692 2.000 151.812 127.600 ;
      RECT 157.092 2.000 157.212 127.600 ;
      RECT 162.492 2.000 162.612 127.600 ;
      RECT 167.892 2.000 168.012 127.600 ;
      RECT 173.292 2.000 173.412 127.600 ;
      RECT 178.692 2.000 178.812 127.600 ;
      RECT 184.092 2.000 184.212 127.600 ;
      RECT 189.492 2.000 189.612 127.600 ;
      RECT 194.892 2.000 195.012 127.600 ;
      RECT 200.292 2.000 200.412 127.600 ;
      RECT 205.692 2.000 205.812 127.600 ;
      RECT 211.092 2.000 211.212 127.600 ;
      RECT 216.492 2.000 216.612 127.600 ;
      RECT 221.892 2.000 222.012 127.600 ;
      RECT 227.292 2.000 227.412 127.600 ;
      RECT 232.692 2.000 232.812 127.600 ;
      RECT 238.092 2.000 238.212 127.600 ;
      RECT 243.492 2.000 243.612 127.600 ;
      RECT 248.892 2.000 249.012 127.600 ;
      RECT 254.292 2.000 254.412 127.600 ;
      RECT 259.692 2.000 259.812 127.600 ;
      RECT 265.092 2.000 265.212 127.600 ;
      RECT 270.492 2.000 270.612 127.600 ;
      RECT 275.892 2.000 276.012 127.600 ;
      RECT 281.292 2.000 281.412 127.600 ;
      RECT 286.692 2.000 286.812 127.600 ;
      RECT 292.092 2.000 292.212 127.600 ;
      RECT 297.492 2.000 297.612 127.600 ;
      RECT 302.892 2.000 303.012 127.600 ;
      RECT 308.292 2.000 308.412 127.600 ;
      RECT 313.692 2.000 313.812 127.600 ;
      RECT 319.092 2.000 319.212 127.600 ;
      RECT 324.492 2.000 324.612 127.600 ;
      RECT 329.892 2.000 330.012 127.600 ;
      RECT 335.292 2.000 335.412 127.600 ;
      RECT 340.692 2.000 340.812 127.600 ;
      RECT 346.092 2.000 346.212 127.600 ;
      RECT 351.492 2.000 351.612 127.600 ;
      RECT 356.892 2.000 357.012 127.600 ;
      RECT 362.292 2.000 362.412 127.600 ;
      RECT 367.692 2.000 367.812 127.600 ;
      RECT 373.092 2.000 373.212 127.600 ;
      RECT 378.492 2.000 378.612 127.600 ;
      RECT 383.892 2.000 384.012 127.600 ;
      RECT 389.292 2.000 389.412 127.600 ;
      RECT 394.692 2.000 394.812 127.600 ;
      RECT 400.092 2.000 400.212 127.600 ;
      RECT 405.492 2.000 405.612 127.600 ;
      RECT 410.892 2.000 411.012 127.600 ;
      RECT 416.292 2.000 416.412 127.600 ;
      RECT 421.692 2.000 421.812 127.600 ;
      RECT 427.092 2.000 427.212 127.600 ;
      RECT 432.492 2.000 432.612 127.600 ;
      RECT 437.892 2.000 438.012 127.600 ;
      RECT 443.292 2.000 443.412 127.600 ;
      RECT 448.692 2.000 448.812 127.600 ;
      RECT 454.092 2.000 454.212 127.600 ;
      RECT 459.492 2.000 459.612 127.600 ;
      RECT 464.892 2.000 465.012 127.600 ;
      RECT 470.292 2.000 470.412 127.600 ;
      RECT 475.692 2.000 475.812 127.600 ;
      RECT 481.092 2.000 481.212 127.600 ;
      RECT 486.492 2.000 486.612 127.600 ;
      RECT 491.892 2.000 492.012 127.600 ;
      RECT 497.292 2.000 497.412 127.600 ;
      RECT 502.692 2.000 502.812 127.600 ;
      RECT 508.092 2.000 508.212 127.600 ;
      RECT 513.492 2.000 513.612 127.600 ;
      RECT 518.892 2.000 519.012 127.600 ;
      RECT 524.292 2.000 524.412 127.600 ;
      RECT 529.692 2.000 529.812 127.600 ;
      RECT 535.092 2.000 535.212 127.600 ;
      RECT 540.492 2.000 540.612 127.600 ;
      RECT 545.892 2.000 546.012 127.600 ;
      RECT 551.292 2.000 551.412 127.600 ;
      RECT 556.692 2.000 556.812 127.600 ;
      RECT 562.092 2.000 562.212 127.600 ;
      RECT 567.492 2.000 567.612 127.600 ;
      RECT 572.892 2.000 573.012 127.600 ;
      RECT 578.292 2.000 578.412 127.600 ;
      RECT 583.692 2.000 583.812 127.600 ;
      RECT 589.092 2.000 589.212 127.600 ;
      RECT 594.492 2.000 594.612 127.600 ;
      RECT 599.892 2.000 600.012 127.600 ;
      RECT 605.292 2.000 605.412 127.600 ;
      RECT 610.692 2.000 610.812 127.600 ;
      RECT 616.092 2.000 616.212 127.600 ;
      RECT 621.492 2.000 621.612 127.600 ;
      RECT 626.892 2.000 627.012 127.600 ;
      RECT 632.292 2.000 632.412 127.600 ;
      RECT 637.692 2.000 637.812 127.600 ;
      RECT 643.092 2.000 643.212 127.600 ;
      RECT 648.492 2.000 648.612 127.600 ;
      RECT 653.892 2.000 654.012 127.600 ;
      RECT 659.292 2.000 659.412 127.600 ;
      RECT 664.692 2.000 664.812 127.600 ;
      RECT 670.092 2.000 670.212 127.600 ;
      RECT 675.492 2.000 675.612 127.600 ;
      RECT 680.892 2.000 681.012 127.600 ;
      RECT 686.292 2.000 686.412 127.600 ;
      RECT 691.692 2.000 691.812 127.600 ;
      RECT 697.092 2.000 697.212 127.600 ;
      RECT 702.492 2.000 702.612 127.600 ;
      RECT 707.892 2.000 708.012 127.600 ;
      RECT 713.292 2.000 713.412 127.600 ;
      RECT 718.692 2.000 718.812 127.600 ;
      RECT 724.092 2.000 724.212 127.600 ;
      RECT 729.492 2.000 729.612 127.600 ;
      RECT 734.892 2.000 735.012 127.600 ;
      RECT 740.292 2.000 740.412 127.600 ;
      RECT 745.692 2.000 745.812 127.600 ;
      RECT 751.092 2.000 751.212 127.600 ;
      RECT 756.492 2.000 756.612 127.600 ;
      RECT 761.892 2.000 762.012 127.600 ;
      RECT 767.292 2.000 767.412 127.600 ;
      RECT 772.692 2.000 772.812 127.600 ;
      RECT 778.092 2.000 778.212 127.600 ;
      RECT 783.492 2.000 783.612 127.600 ;
      RECT 788.892 2.000 789.012 127.600 ;
      RECT 794.292 2.000 794.412 127.600 ;
      RECT 799.692 2.000 799.812 127.600 ;
      RECT 805.092 2.000 805.212 127.600 ;
      RECT 810.492 2.000 810.612 127.600 ;
      RECT 815.892 2.000 816.012 127.600 ;
      RECT 821.292 2.000 821.412 127.600 ;
      RECT 826.692 2.000 826.812 127.600 ;
      RECT 832.092 2.000 832.212 127.600 ;
      RECT 837.492 2.000 837.612 127.600 ;
      RECT 842.892 2.000 843.012 127.600 ;
      RECT 848.292 2.000 848.412 127.600 ;
      RECT 853.692 2.000 853.812 127.600 ;
      RECT 859.092 2.000 859.212 127.600 ;
      RECT 864.492 2.000 864.612 127.600 ;
      RECT 869.892 2.000 870.012 127.600 ;
      RECT 875.292 2.000 875.412 127.600 ;
      RECT 880.692 2.000 880.812 127.600 ;
      RECT 886.092 2.000 886.212 127.600 ;
      RECT 891.492 2.000 891.612 127.600 ;
      RECT 896.892 2.000 897.012 127.600 ;
      RECT 902.292 2.000 902.412 127.600 ;
      RECT 907.692 2.000 907.812 127.600 ;
      RECT 913.092 2.000 913.212 127.600 ;
      RECT 918.492 2.000 918.612 127.600 ;
      RECT 923.892 2.000 924.012 127.600 ;
      RECT 929.292 2.000 929.412 127.600 ;
      RECT 934.692 2.000 934.812 127.600 ;
      RECT 940.092 2.000 940.212 127.600 ;
      RECT 945.492 2.000 945.612 127.600 ;
      RECT 950.892 2.000 951.012 127.600 ;
      RECT 956.292 2.000 956.412 127.600 ;
      RECT 961.692 2.000 961.812 127.600 ;
      RECT 967.092 2.000 967.212 127.600 ;
      RECT 972.492 2.000 972.612 127.600 ;
      RECT 977.892 2.000 978.012 127.600 ;
      RECT 983.292 2.000 983.412 127.600 ;
      RECT 988.692 2.000 988.812 127.600 ;
      RECT 994.092 2.000 994.212 127.600 ;
      RECT 999.492 2.000 999.612 127.600 ;
      RECT 1004.892 2.000 1005.012 127.600 ;
      RECT 1010.292 2.000 1010.412 127.600 ;
      RECT 1015.692 2.000 1015.812 127.600 ;
      RECT 1021.092 2.000 1021.212 127.600 ;
      RECT 1026.492 2.000 1026.612 127.600 ;
      RECT 1031.892 2.000 1032.012 127.600 ;
      RECT 1037.292 2.000 1037.412 127.600 ;
      RECT 1042.692 2.000 1042.812 127.600 ;
      RECT 1048.092 2.000 1048.212 127.600 ;
      RECT 1053.492 2.000 1053.612 127.600 ;
      RECT 1058.892 2.000 1059.012 127.600 ;
      RECT 1064.292 2.000 1064.412 127.600 ;
      RECT 1069.692 2.000 1069.812 127.600 ;
      RECT 1075.092 2.000 1075.212 127.600 ;
      RECT 1080.492 2.000 1080.612 127.600 ;
      RECT 1085.892 2.000 1086.012 127.600 ;
      RECT 1091.292 2.000 1091.412 127.600 ;
      RECT 1096.692 2.000 1096.812 127.600 ;
      RECT 1102.092 2.000 1102.212 127.600 ;
      RECT 1107.492 2.000 1107.612 127.600 ;
      RECT 1112.892 2.000 1113.012 127.600 ;
      RECT 1118.292 2.000 1118.412 127.600 ;
      RECT 1123.692 2.000 1123.812 127.600 ;
      RECT 1129.092 2.000 1129.212 127.600 ;
      RECT 1134.492 2.000 1134.612 127.600 ;
      RECT 1139.892 2.000 1140.012 127.600 ;
      RECT 1145.292 2.000 1145.412 127.600 ;
      RECT 1150.692 2.000 1150.812 127.600 ;
      RECT 1156.092 2.000 1156.212 127.600 ;
      RECT 1161.492 2.000 1161.612 127.600 ;
      RECT 1166.892 2.000 1167.012 127.600 ;
      RECT 1172.292 2.000 1172.412 127.600 ;
      RECT 1177.692 2.000 1177.812 127.600 ;
      RECT 1183.092 2.000 1183.212 127.600 ;
      RECT 1188.492 2.000 1188.612 127.600 ;
      RECT 1193.892 2.000 1194.012 127.600 ;
      RECT 1199.292 2.000 1199.412 127.600 ;
      RECT 1204.692 2.000 1204.812 127.600 ;
      RECT 1210.092 2.000 1210.212 127.600 ;
      RECT 1215.492 2.000 1215.612 127.600 ;
      RECT 1220.892 2.000 1221.012 127.600 ;
      RECT 1226.292 2.000 1226.412 127.600 ;
      RECT 1231.692 2.000 1231.812 127.600 ;
      RECT 1237.092 2.000 1237.212 127.600 ;
      RECT 1242.492 2.000 1242.612 127.600 ;
      RECT 1247.892 2.000 1248.012 127.600 ;
      RECT 1253.292 2.000 1253.412 127.600 ;
      RECT 1258.692 2.000 1258.812 127.600 ;
      RECT 1264.092 2.000 1264.212 127.600 ;
      RECT 1269.492 2.000 1269.612 127.600 ;
      RECT 1274.892 2.000 1275.012 127.600 ;
      RECT 1280.292 2.000 1280.412 127.600 ;
      RECT 1285.692 2.000 1285.812 127.600 ;
      RECT 1291.092 2.000 1291.212 127.600 ;
      RECT 1296.492 2.000 1296.612 127.600 ;
      RECT 1301.892 2.000 1302.012 127.600 ;
      RECT 1307.292 2.000 1307.412 127.600 ;
      RECT 1312.692 2.000 1312.812 127.600 ;
      RECT 1318.092 2.000 1318.212 127.600 ;
      RECT 1323.492 2.000 1323.612 127.600 ;
      RECT 1328.892 2.000 1329.012 127.600 ;
      RECT 1334.292 2.000 1334.412 127.600 ;
      RECT 1339.692 2.000 1339.812 127.600 ;
      RECT 1345.092 2.000 1345.212 127.600 ;
      RECT 1350.492 2.000 1350.612 127.600 ;
      RECT 1355.892 2.000 1356.012 127.600 ;
      RECT 1361.292 2.000 1361.412 127.600 ;
      RECT 1366.692 2.000 1366.812 127.600 ;
      RECT 1372.092 2.000 1372.212 127.600 ;
      RECT 1377.492 2.000 1377.612 127.600 ;
      RECT 1382.892 2.000 1383.012 127.600 ;
      RECT 1388.292 2.000 1388.412 127.600 ;
      RECT 1393.692 2.000 1393.812 127.600 ;
      RECT 1399.092 2.000 1399.212 127.600 ;
      RECT 1404.492 2.000 1404.612 127.600 ;
      RECT 1409.892 2.000 1410.012 127.600 ;
      RECT 1415.292 2.000 1415.412 127.600 ;
      RECT 1420.692 2.000 1420.812 127.600 ;
      RECT 1426.092 2.000 1426.212 127.600 ;
      RECT 1431.492 2.000 1431.612 127.600 ;
      RECT 1436.892 2.000 1437.012 127.600 ;
      RECT 1442.292 2.000 1442.412 127.600 ;
      RECT 1447.692 2.000 1447.812 127.600 ;
      RECT 1453.092 2.000 1453.212 127.600 ;
      RECT 1458.492 2.000 1458.612 127.600 ;
      RECT 1463.892 2.000 1464.012 127.600 ;
      RECT 1469.292 2.000 1469.412 127.600 ;
      RECT 1474.692 2.000 1474.812 127.600 ;
      RECT 1480.092 2.000 1480.212 127.600 ;
      RECT 1485.492 2.000 1485.612 127.600 ;
      RECT 1490.892 2.000 1491.012 127.600 ;
      RECT 1496.292 2.000 1496.412 127.600 ;
      RECT 1501.692 2.000 1501.812 127.600 ;
      RECT 1507.092 2.000 1507.212 127.600 ;
      RECT 1512.492 2.000 1512.612 127.600 ;
      RECT 1517.892 2.000 1518.012 127.600 ;
      RECT 1523.292 2.000 1523.412 127.600 ;
      RECT 1528.692 2.000 1528.812 127.600 ;
      RECT 1534.092 2.000 1534.212 127.600 ;
      RECT 1539.492 2.000 1539.612 127.600 ;
      RECT 1544.892 2.000 1545.012 127.600 ;
      RECT 1550.292 2.000 1550.412 127.600 ;
      RECT 1555.692 2.000 1555.812 127.600 ;
      RECT 1561.092 2.000 1561.212 127.600 ;
      RECT 1566.492 2.000 1566.612 127.600 ;
      RECT 1571.892 2.000 1572.012 127.600 ;
      RECT 1577.292 2.000 1577.412 127.600 ;
      RECT 1582.692 2.000 1582.812 127.600 ;
      RECT 1588.092 2.000 1588.212 127.600 ;
      RECT 1593.492 2.000 1593.612 127.600 ;
      RECT 1598.892 2.000 1599.012 127.600 ;
      RECT 1604.292 2.000 1604.412 127.600 ;
      RECT 1609.692 2.000 1609.812 127.600 ;
      RECT 1615.092 2.000 1615.212 127.600 ;
      RECT 1620.492 2.000 1620.612 127.600 ;
      RECT 1625.892 2.000 1626.012 127.600 ;
      RECT 1631.292 2.000 1631.412 127.600 ;
      RECT 1636.692 2.000 1636.812 127.600 ;
      RECT 1642.092 2.000 1642.212 127.600 ;
      RECT 1647.492 2.000 1647.612 127.600 ;
      RECT 1652.892 2.000 1653.012 127.600 ;
      RECT 1658.292 2.000 1658.412 127.600 ;
      RECT 1663.692 2.000 1663.812 127.600 ;
      RECT 1669.092 2.000 1669.212 127.600 ;
      RECT 1674.492 2.000 1674.612 127.600 ;
      RECT 1679.892 2.000 1680.012 127.600 ;
      RECT 1685.292 2.000 1685.412 127.600 ;
      RECT 1690.692 2.000 1690.812 127.600 ;
      RECT 1696.092 2.000 1696.212 127.600 ;
      RECT 1701.492 2.000 1701.612 127.600 ;
      RECT 1706.892 2.000 1707.012 127.600 ;
      RECT 1712.292 2.000 1712.412 127.600 ;
      RECT 1717.692 2.000 1717.812 127.600 ;
      RECT 1723.092 2.000 1723.212 127.600 ;
      RECT 1728.492 2.000 1728.612 127.600 ;
      RECT 1733.892 2.000 1734.012 127.600 ;
      RECT 1739.292 2.000 1739.412 127.600 ;
      RECT 1744.692 2.000 1744.812 127.600 ;
      RECT 1750.092 2.000 1750.212 127.600 ;
      RECT 1755.492 2.000 1755.612 127.600 ;
      RECT 1760.892 2.000 1761.012 127.600 ;
      RECT 1766.292 2.000 1766.412 127.600 ;
      RECT 1771.692 2.000 1771.812 127.600 ;
      RECT 1777.092 2.000 1777.212 127.600 ;
      RECT 1782.492 2.000 1782.612 127.600 ;
      RECT 1787.892 2.000 1788.012 127.600 ;
      RECT 1793.292 2.000 1793.412 127.600 ;
      RECT 1798.692 2.000 1798.812 127.600 ;
      RECT 1804.092 2.000 1804.212 127.600 ;
      RECT 1809.492 2.000 1809.612 127.600 ;
      RECT 1814.892 2.000 1815.012 127.600 ;
      RECT 1820.292 2.000 1820.412 127.600 ;
      RECT 1825.692 2.000 1825.812 127.600 ;
      RECT 1831.092 2.000 1831.212 127.600 ;
      RECT 1836.492 2.000 1836.612 127.600 ;
      RECT 1841.892 2.000 1842.012 127.600 ;
      RECT 1847.292 2.000 1847.412 127.600 ;
      RECT 1852.692 2.000 1852.812 127.600 ;
      RECT 1858.092 2.000 1858.212 127.600 ;
      RECT 1863.492 2.000 1863.612 127.600 ;
      RECT 1868.892 2.000 1869.012 127.600 ;
      RECT 1874.292 2.000 1874.412 127.600 ;
      RECT 1879.692 2.000 1879.812 127.600 ;
      RECT 1885.092 2.000 1885.212 127.600 ;
      RECT 1890.492 2.000 1890.612 127.600 ;
      RECT 1895.892 2.000 1896.012 127.600 ;
      RECT 1901.292 2.000 1901.412 127.600 ;
      RECT 1906.692 2.000 1906.812 127.600 ;
      RECT 1912.092 2.000 1912.212 127.600 ;
      RECT 1917.492 2.000 1917.612 127.600 ;
      RECT 1922.892 2.000 1923.012 127.600 ;
      RECT 1928.292 2.000 1928.412 127.600 ;
      RECT 1933.692 2.000 1933.812 127.600 ;
      RECT 1939.092 2.000 1939.212 127.600 ;
      RECT 1944.492 2.000 1944.612 127.600 ;
      RECT 1949.892 2.000 1950.012 127.600 ;
      RECT 1955.292 2.000 1955.412 127.600 ;
      RECT 1960.692 2.000 1960.812 127.600 ;
      RECT 1966.092 2.000 1966.212 127.600 ;
      RECT 1971.492 2.000 1971.612 127.600 ;
      RECT 1976.892 2.000 1977.012 127.600 ;
      RECT 1982.292 2.000 1982.412 127.600 ;
      RECT 1987.692 2.000 1987.812 127.600 ;
      RECT 1993.092 2.000 1993.212 127.600 ;
      RECT 1998.492 2.000 1998.612 127.600 ;
      RECT 2003.892 2.000 2004.012 127.600 ;
      RECT 2009.292 2.000 2009.412 127.600 ;
      RECT 2014.692 2.000 2014.812 127.600 ;
      RECT 2020.092 2.000 2020.212 127.600 ;
      RECT 2025.492 2.000 2025.612 127.600 ;
      RECT 2030.892 2.000 2031.012 127.600 ;
      RECT 2036.292 2.000 2036.412 127.600 ;
      RECT 2041.692 2.000 2041.812 127.600 ;
      RECT 2047.092 2.000 2047.212 127.600 ;
      RECT 2052.492 2.000 2052.612 127.600 ;
      RECT 2057.892 2.000 2058.012 127.600 ;
      RECT 2063.292 2.000 2063.412 127.600 ;
      RECT 2068.692 2.000 2068.812 127.600 ;
      RECT 2074.092 2.000 2074.212 127.600 ;
      RECT 2079.492 2.000 2079.612 127.600 ;
      RECT 2084.892 2.000 2085.012 127.600 ;
      RECT 2090.292 2.000 2090.412 127.600 ;
      RECT 2095.692 2.000 2095.812 127.600 ;
      RECT 2101.092 2.000 2101.212 127.600 ;
      RECT 2106.492 2.000 2106.612 127.600 ;
      RECT 2111.892 2.000 2112.012 127.600 ;
      RECT 2117.292 2.000 2117.412 127.600 ;
      RECT 2122.692 2.000 2122.812 127.600 ;
      RECT 2128.092 2.000 2128.212 127.600 ;
      RECT 2133.492 2.000 2133.612 127.600 ;
      RECT 2138.892 2.000 2139.012 127.600 ;
      RECT 2144.292 2.000 2144.412 127.600 ;
      RECT 2149.692 2.000 2149.812 127.600 ;
      RECT 2155.092 2.000 2155.212 127.600 ;
      RECT 2160.492 2.000 2160.612 127.600 ;
      RECT 2165.892 2.000 2166.012 127.600 ;
      RECT 2171.292 2.000 2171.412 127.600 ;
      RECT 2176.692 2.000 2176.812 127.600 ;
      RECT 2182.092 2.000 2182.212 127.600 ;
      RECT 2187.492 2.000 2187.612 127.600 ;
      RECT 2192.892 2.000 2193.012 127.600 ;
      RECT 2198.292 2.000 2198.412 127.600 ;
      RECT 2203.692 2.000 2203.812 127.600 ;
      RECT 2209.092 2.000 2209.212 127.600 ;
      RECT 2214.492 2.000 2214.612 127.600 ;
      RECT 2219.892 2.000 2220.012 127.600 ;
      RECT 2225.292 2.000 2225.412 127.600 ;
      RECT 2230.692 2.000 2230.812 127.600 ;
      RECT 2236.092 2.000 2236.212 127.600 ;
      RECT 2241.492 2.000 2241.612 127.600 ;
    END
  END VSS
  OBS
    LAYER M1 ;
    RECT 0 0 2246.400 129.600 ;
    LAYER M2 ;
    RECT 0 0 2246.400 129.600 ;
    LAYER M3 ;
    RECT 0 0 2246.400 129.600 ;
    LAYER M4 ;
    RECT 0 0 2246.400 129.600 ;
    LAYER M5 ;
    RECT 0.000 0.600 0.228 129.000 ;
    RECT 0.684 0.600 5.628 129.000 ;
    RECT 6.084 0.600 11.028 129.000 ;
    RECT 11.484 0.600 16.428 129.000 ;
    RECT 16.884 0.600 21.828 129.000 ;
    RECT 22.284 0.600 27.228 129.000 ;
    RECT 27.684 0.600 32.628 129.000 ;
    RECT 33.084 0.600 38.028 129.000 ;
    RECT 38.484 0.600 43.428 129.000 ;
    RECT 43.884 0.600 48.828 129.000 ;
    RECT 49.284 0.600 54.228 129.000 ;
    RECT 54.684 0.600 59.628 129.000 ;
    RECT 60.084 0.600 65.028 129.000 ;
    RECT 65.484 0.600 70.428 129.000 ;
    RECT 70.884 0.600 75.828 129.000 ;
    RECT 76.284 0.600 81.228 129.000 ;
    RECT 81.684 0.600 86.628 129.000 ;
    RECT 87.084 0.600 92.028 129.000 ;
    RECT 92.484 0.600 97.428 129.000 ;
    RECT 97.884 0.600 102.828 129.000 ;
    RECT 103.284 0.600 108.228 129.000 ;
    RECT 108.684 0.600 113.628 129.000 ;
    RECT 114.084 0.600 119.028 129.000 ;
    RECT 119.484 0.600 124.428 129.000 ;
    RECT 124.884 0.600 129.828 129.000 ;
    RECT 130.284 0.600 135.228 129.000 ;
    RECT 135.684 0.600 140.628 129.000 ;
    RECT 141.084 0.600 146.028 129.000 ;
    RECT 146.484 0.600 151.428 129.000 ;
    RECT 151.884 0.600 156.828 129.000 ;
    RECT 157.284 0.600 162.228 129.000 ;
    RECT 162.684 0.600 167.628 129.000 ;
    RECT 168.084 0.600 173.028 129.000 ;
    RECT 173.484 0.600 178.428 129.000 ;
    RECT 178.884 0.600 183.828 129.000 ;
    RECT 184.284 0.600 189.228 129.000 ;
    RECT 189.684 0.600 194.628 129.000 ;
    RECT 195.084 0.600 200.028 129.000 ;
    RECT 200.484 0.600 205.428 129.000 ;
    RECT 205.884 0.600 210.828 129.000 ;
    RECT 211.284 0.600 216.228 129.000 ;
    RECT 216.684 0.600 221.628 129.000 ;
    RECT 222.084 0.600 227.028 129.000 ;
    RECT 227.484 0.600 232.428 129.000 ;
    RECT 232.884 0.600 237.828 129.000 ;
    RECT 238.284 0.600 243.228 129.000 ;
    RECT 243.684 0.600 248.628 129.000 ;
    RECT 249.084 0.600 254.028 129.000 ;
    RECT 254.484 0.600 259.428 129.000 ;
    RECT 259.884 0.600 264.828 129.000 ;
    RECT 265.284 0.600 270.228 129.000 ;
    RECT 270.684 0.600 275.628 129.000 ;
    RECT 276.084 0.600 281.028 129.000 ;
    RECT 281.484 0.600 286.428 129.000 ;
    RECT 286.884 0.600 291.828 129.000 ;
    RECT 292.284 0.600 297.228 129.000 ;
    RECT 297.684 0.600 302.628 129.000 ;
    RECT 303.084 0.600 308.028 129.000 ;
    RECT 308.484 0.600 313.428 129.000 ;
    RECT 313.884 0.600 318.828 129.000 ;
    RECT 319.284 0.600 324.228 129.000 ;
    RECT 324.684 0.600 329.628 129.000 ;
    RECT 330.084 0.600 335.028 129.000 ;
    RECT 335.484 0.600 340.428 129.000 ;
    RECT 340.884 0.600 345.828 129.000 ;
    RECT 346.284 0.600 351.228 129.000 ;
    RECT 351.684 0.600 356.628 129.000 ;
    RECT 357.084 0.600 362.028 129.000 ;
    RECT 362.484 0.600 367.428 129.000 ;
    RECT 367.884 0.600 372.828 129.000 ;
    RECT 373.284 0.600 378.228 129.000 ;
    RECT 378.684 0.600 383.628 129.000 ;
    RECT 384.084 0.600 389.028 129.000 ;
    RECT 389.484 0.600 394.428 129.000 ;
    RECT 394.884 0.600 399.828 129.000 ;
    RECT 400.284 0.600 405.228 129.000 ;
    RECT 405.684 0.600 410.628 129.000 ;
    RECT 411.084 0.600 416.028 129.000 ;
    RECT 416.484 0.600 421.428 129.000 ;
    RECT 421.884 0.600 426.828 129.000 ;
    RECT 427.284 0.600 432.228 129.000 ;
    RECT 432.684 0.600 437.628 129.000 ;
    RECT 438.084 0.600 443.028 129.000 ;
    RECT 443.484 0.600 448.428 129.000 ;
    RECT 448.884 0.600 453.828 129.000 ;
    RECT 454.284 0.600 459.228 129.000 ;
    RECT 459.684 0.600 464.628 129.000 ;
    RECT 465.084 0.600 470.028 129.000 ;
    RECT 470.484 0.600 475.428 129.000 ;
    RECT 475.884 0.600 480.828 129.000 ;
    RECT 481.284 0.600 486.228 129.000 ;
    RECT 486.684 0.600 491.628 129.000 ;
    RECT 492.084 0.600 497.028 129.000 ;
    RECT 497.484 0.600 502.428 129.000 ;
    RECT 502.884 0.600 507.828 129.000 ;
    RECT 508.284 0.600 513.228 129.000 ;
    RECT 513.684 0.600 518.628 129.000 ;
    RECT 519.084 0.600 524.028 129.000 ;
    RECT 524.484 0.600 529.428 129.000 ;
    RECT 529.884 0.600 534.828 129.000 ;
    RECT 535.284 0.600 540.228 129.000 ;
    RECT 540.684 0.600 545.628 129.000 ;
    RECT 546.084 0.600 551.028 129.000 ;
    RECT 551.484 0.600 556.428 129.000 ;
    RECT 556.884 0.600 561.828 129.000 ;
    RECT 562.284 0.600 567.228 129.000 ;
    RECT 567.684 0.600 572.628 129.000 ;
    RECT 573.084 0.600 578.028 129.000 ;
    RECT 578.484 0.600 583.428 129.000 ;
    RECT 583.884 0.600 588.828 129.000 ;
    RECT 589.284 0.600 594.228 129.000 ;
    RECT 594.684 0.600 599.628 129.000 ;
    RECT 600.084 0.600 605.028 129.000 ;
    RECT 605.484 0.600 610.428 129.000 ;
    RECT 610.884 0.600 615.828 129.000 ;
    RECT 616.284 0.600 621.228 129.000 ;
    RECT 621.684 0.600 626.628 129.000 ;
    RECT 627.084 0.600 632.028 129.000 ;
    RECT 632.484 0.600 637.428 129.000 ;
    RECT 637.884 0.600 642.828 129.000 ;
    RECT 643.284 0.600 648.228 129.000 ;
    RECT 648.684 0.600 653.628 129.000 ;
    RECT 654.084 0.600 659.028 129.000 ;
    RECT 659.484 0.600 664.428 129.000 ;
    RECT 664.884 0.600 669.828 129.000 ;
    RECT 670.284 0.600 675.228 129.000 ;
    RECT 675.684 0.600 680.628 129.000 ;
    RECT 681.084 0.600 686.028 129.000 ;
    RECT 686.484 0.600 691.428 129.000 ;
    RECT 691.884 0.600 696.828 129.000 ;
    RECT 697.284 0.600 702.228 129.000 ;
    RECT 702.684 0.600 707.628 129.000 ;
    RECT 708.084 0.600 713.028 129.000 ;
    RECT 713.484 0.600 718.428 129.000 ;
    RECT 718.884 0.600 723.828 129.000 ;
    RECT 724.284 0.600 729.228 129.000 ;
    RECT 729.684 0.600 734.628 129.000 ;
    RECT 735.084 0.600 740.028 129.000 ;
    RECT 740.484 0.600 745.428 129.000 ;
    RECT 745.884 0.600 750.828 129.000 ;
    RECT 751.284 0.600 756.228 129.000 ;
    RECT 756.684 0.600 761.628 129.000 ;
    RECT 762.084 0.600 767.028 129.000 ;
    RECT 767.484 0.600 772.428 129.000 ;
    RECT 772.884 0.600 777.828 129.000 ;
    RECT 778.284 0.600 783.228 129.000 ;
    RECT 783.684 0.600 788.628 129.000 ;
    RECT 789.084 0.600 794.028 129.000 ;
    RECT 794.484 0.600 799.428 129.000 ;
    RECT 799.884 0.600 804.828 129.000 ;
    RECT 805.284 0.600 810.228 129.000 ;
    RECT 810.684 0.600 815.628 129.000 ;
    RECT 816.084 0.600 821.028 129.000 ;
    RECT 821.484 0.600 826.428 129.000 ;
    RECT 826.884 0.600 831.828 129.000 ;
    RECT 832.284 0.600 837.228 129.000 ;
    RECT 837.684 0.600 842.628 129.000 ;
    RECT 843.084 0.600 848.028 129.000 ;
    RECT 848.484 0.600 853.428 129.000 ;
    RECT 853.884 0.600 858.828 129.000 ;
    RECT 859.284 0.600 864.228 129.000 ;
    RECT 864.684 0.600 869.628 129.000 ;
    RECT 870.084 0.600 875.028 129.000 ;
    RECT 875.484 0.600 880.428 129.000 ;
    RECT 880.884 0.600 885.828 129.000 ;
    RECT 886.284 0.600 891.228 129.000 ;
    RECT 891.684 0.600 896.628 129.000 ;
    RECT 897.084 0.600 902.028 129.000 ;
    RECT 902.484 0.600 907.428 129.000 ;
    RECT 907.884 0.600 912.828 129.000 ;
    RECT 913.284 0.600 918.228 129.000 ;
    RECT 918.684 0.600 923.628 129.000 ;
    RECT 924.084 0.600 929.028 129.000 ;
    RECT 929.484 0.600 934.428 129.000 ;
    RECT 934.884 0.600 939.828 129.000 ;
    RECT 940.284 0.600 945.228 129.000 ;
    RECT 945.684 0.600 950.628 129.000 ;
    RECT 951.084 0.600 956.028 129.000 ;
    RECT 956.484 0.600 961.428 129.000 ;
    RECT 961.884 0.600 966.828 129.000 ;
    RECT 967.284 0.600 972.228 129.000 ;
    RECT 972.684 0.600 977.628 129.000 ;
    RECT 978.084 0.600 983.028 129.000 ;
    RECT 983.484 0.600 988.428 129.000 ;
    RECT 988.884 0.600 993.828 129.000 ;
    RECT 994.284 0.600 999.228 129.000 ;
    RECT 999.684 0.600 1004.628 129.000 ;
    RECT 1005.084 0.600 1010.028 129.000 ;
    RECT 1010.484 0.600 1015.428 129.000 ;
    RECT 1015.884 0.600 1020.828 129.000 ;
    RECT 1021.284 0.600 1026.228 129.000 ;
    RECT 1026.684 0.600 1031.628 129.000 ;
    RECT 1032.084 0.600 1037.028 129.000 ;
    RECT 1037.484 0.600 1042.428 129.000 ;
    RECT 1042.884 0.600 1047.828 129.000 ;
    RECT 1048.284 0.600 1053.228 129.000 ;
    RECT 1053.684 0.600 1058.628 129.000 ;
    RECT 1059.084 0.600 1064.028 129.000 ;
    RECT 1064.484 0.600 1069.428 129.000 ;
    RECT 1069.884 0.600 1074.828 129.000 ;
    RECT 1075.284 0.600 1080.228 129.000 ;
    RECT 1080.684 0.600 1085.628 129.000 ;
    RECT 1086.084 0.600 1091.028 129.000 ;
    RECT 1091.484 0.600 1096.428 129.000 ;
    RECT 1096.884 0.600 1101.828 129.000 ;
    RECT 1102.284 0.600 1107.228 129.000 ;
    RECT 1107.684 0.600 1112.628 129.000 ;
    RECT 1113.084 0.600 1118.028 129.000 ;
    RECT 1118.484 0.600 1123.428 129.000 ;
    RECT 1123.884 0.600 1128.828 129.000 ;
    RECT 1129.284 0.600 1134.228 129.000 ;
    RECT 1134.684 0.600 1139.628 129.000 ;
    RECT 1140.084 0.600 1145.028 129.000 ;
    RECT 1145.484 0.600 1150.428 129.000 ;
    RECT 1150.884 0.600 1155.828 129.000 ;
    RECT 1156.284 0.600 1161.228 129.000 ;
    RECT 1161.684 0.600 1166.628 129.000 ;
    RECT 1167.084 0.600 1172.028 129.000 ;
    RECT 1172.484 0.600 1177.428 129.000 ;
    RECT 1177.884 0.600 1182.828 129.000 ;
    RECT 1183.284 0.600 1188.228 129.000 ;
    RECT 1188.684 0.600 1193.628 129.000 ;
    RECT 1194.084 0.600 1199.028 129.000 ;
    RECT 1199.484 0.600 1204.428 129.000 ;
    RECT 1204.884 0.600 1209.828 129.000 ;
    RECT 1210.284 0.600 1215.228 129.000 ;
    RECT 1215.684 0.600 1220.628 129.000 ;
    RECT 1221.084 0.600 1226.028 129.000 ;
    RECT 1226.484 0.600 1231.428 129.000 ;
    RECT 1231.884 0.600 1236.828 129.000 ;
    RECT 1237.284 0.600 1242.228 129.000 ;
    RECT 1242.684 0.600 1247.628 129.000 ;
    RECT 1248.084 0.600 1253.028 129.000 ;
    RECT 1253.484 0.600 1258.428 129.000 ;
    RECT 1258.884 0.600 1263.828 129.000 ;
    RECT 1264.284 0.600 1269.228 129.000 ;
    RECT 1269.684 0.600 1274.628 129.000 ;
    RECT 1275.084 0.600 1280.028 129.000 ;
    RECT 1280.484 0.600 1285.428 129.000 ;
    RECT 1285.884 0.600 1290.828 129.000 ;
    RECT 1291.284 0.600 1296.228 129.000 ;
    RECT 1296.684 0.600 1301.628 129.000 ;
    RECT 1302.084 0.600 1307.028 129.000 ;
    RECT 1307.484 0.600 1312.428 129.000 ;
    RECT 1312.884 0.600 1317.828 129.000 ;
    RECT 1318.284 0.600 1323.228 129.000 ;
    RECT 1323.684 0.600 1328.628 129.000 ;
    RECT 1329.084 0.600 1334.028 129.000 ;
    RECT 1334.484 0.600 1339.428 129.000 ;
    RECT 1339.884 0.600 1344.828 129.000 ;
    RECT 1345.284 0.600 1350.228 129.000 ;
    RECT 1350.684 0.600 1355.628 129.000 ;
    RECT 1356.084 0.600 1361.028 129.000 ;
    RECT 1361.484 0.600 1366.428 129.000 ;
    RECT 1366.884 0.600 1371.828 129.000 ;
    RECT 1372.284 0.600 1377.228 129.000 ;
    RECT 1377.684 0.600 1382.628 129.000 ;
    RECT 1383.084 0.600 1388.028 129.000 ;
    RECT 1388.484 0.600 1393.428 129.000 ;
    RECT 1393.884 0.600 1398.828 129.000 ;
    RECT 1399.284 0.600 1404.228 129.000 ;
    RECT 1404.684 0.600 1409.628 129.000 ;
    RECT 1410.084 0.600 1415.028 129.000 ;
    RECT 1415.484 0.600 1420.428 129.000 ;
    RECT 1420.884 0.600 1425.828 129.000 ;
    RECT 1426.284 0.600 1431.228 129.000 ;
    RECT 1431.684 0.600 1436.628 129.000 ;
    RECT 1437.084 0.600 1442.028 129.000 ;
    RECT 1442.484 0.600 1447.428 129.000 ;
    RECT 1447.884 0.600 1452.828 129.000 ;
    RECT 1453.284 0.600 1458.228 129.000 ;
    RECT 1458.684 0.600 1463.628 129.000 ;
    RECT 1464.084 0.600 1469.028 129.000 ;
    RECT 1469.484 0.600 1474.428 129.000 ;
    RECT 1474.884 0.600 1479.828 129.000 ;
    RECT 1480.284 0.600 1485.228 129.000 ;
    RECT 1485.684 0.600 1490.628 129.000 ;
    RECT 1491.084 0.600 1496.028 129.000 ;
    RECT 1496.484 0.600 1501.428 129.000 ;
    RECT 1501.884 0.600 1506.828 129.000 ;
    RECT 1507.284 0.600 1512.228 129.000 ;
    RECT 1512.684 0.600 1517.628 129.000 ;
    RECT 1518.084 0.600 1523.028 129.000 ;
    RECT 1523.484 0.600 1528.428 129.000 ;
    RECT 1528.884 0.600 1533.828 129.000 ;
    RECT 1534.284 0.600 1539.228 129.000 ;
    RECT 1539.684 0.600 1544.628 129.000 ;
    RECT 1545.084 0.600 1550.028 129.000 ;
    RECT 1550.484 0.600 1555.428 129.000 ;
    RECT 1555.884 0.600 1560.828 129.000 ;
    RECT 1561.284 0.600 1566.228 129.000 ;
    RECT 1566.684 0.600 1571.628 129.000 ;
    RECT 1572.084 0.600 1577.028 129.000 ;
    RECT 1577.484 0.600 1582.428 129.000 ;
    RECT 1582.884 0.600 1587.828 129.000 ;
    RECT 1588.284 0.600 1593.228 129.000 ;
    RECT 1593.684 0.600 1598.628 129.000 ;
    RECT 1599.084 0.600 1604.028 129.000 ;
    RECT 1604.484 0.600 1609.428 129.000 ;
    RECT 1609.884 0.600 1614.828 129.000 ;
    RECT 1615.284 0.600 1620.228 129.000 ;
    RECT 1620.684 0.600 1625.628 129.000 ;
    RECT 1626.084 0.600 1631.028 129.000 ;
    RECT 1631.484 0.600 1636.428 129.000 ;
    RECT 1636.884 0.600 1641.828 129.000 ;
    RECT 1642.284 0.600 1647.228 129.000 ;
    RECT 1647.684 0.600 1652.628 129.000 ;
    RECT 1653.084 0.600 1658.028 129.000 ;
    RECT 1658.484 0.600 1663.428 129.000 ;
    RECT 1663.884 0.600 1668.828 129.000 ;
    RECT 1669.284 0.600 1674.228 129.000 ;
    RECT 1674.684 0.600 1679.628 129.000 ;
    RECT 1680.084 0.600 1685.028 129.000 ;
    RECT 1685.484 0.600 1690.428 129.000 ;
    RECT 1690.884 0.600 1695.828 129.000 ;
    RECT 1696.284 0.600 1701.228 129.000 ;
    RECT 1701.684 0.600 1706.628 129.000 ;
    RECT 1707.084 0.600 1712.028 129.000 ;
    RECT 1712.484 0.600 1717.428 129.000 ;
    RECT 1717.884 0.600 1722.828 129.000 ;
    RECT 1723.284 0.600 1728.228 129.000 ;
    RECT 1728.684 0.600 1733.628 129.000 ;
    RECT 1734.084 0.600 1739.028 129.000 ;
    RECT 1739.484 0.600 1744.428 129.000 ;
    RECT 1744.884 0.600 1749.828 129.000 ;
    RECT 1750.284 0.600 1755.228 129.000 ;
    RECT 1755.684 0.600 1760.628 129.000 ;
    RECT 1761.084 0.600 1766.028 129.000 ;
    RECT 1766.484 0.600 1771.428 129.000 ;
    RECT 1771.884 0.600 1776.828 129.000 ;
    RECT 1777.284 0.600 1782.228 129.000 ;
    RECT 1782.684 0.600 1787.628 129.000 ;
    RECT 1788.084 0.600 1793.028 129.000 ;
    RECT 1793.484 0.600 1798.428 129.000 ;
    RECT 1798.884 0.600 1803.828 129.000 ;
    RECT 1804.284 0.600 1809.228 129.000 ;
    RECT 1809.684 0.600 1814.628 129.000 ;
    RECT 1815.084 0.600 1820.028 129.000 ;
    RECT 1820.484 0.600 1825.428 129.000 ;
    RECT 1825.884 0.600 1830.828 129.000 ;
    RECT 1831.284 0.600 1836.228 129.000 ;
    RECT 1836.684 0.600 1841.628 129.000 ;
    RECT 1842.084 0.600 1847.028 129.000 ;
    RECT 1847.484 0.600 1852.428 129.000 ;
    RECT 1852.884 0.600 1857.828 129.000 ;
    RECT 1858.284 0.600 1863.228 129.000 ;
    RECT 1863.684 0.600 1868.628 129.000 ;
    RECT 1869.084 0.600 1874.028 129.000 ;
    RECT 1874.484 0.600 1879.428 129.000 ;
    RECT 1879.884 0.600 1884.828 129.000 ;
    RECT 1885.284 0.600 1890.228 129.000 ;
    RECT 1890.684 0.600 1895.628 129.000 ;
    RECT 1896.084 0.600 1901.028 129.000 ;
    RECT 1901.484 0.600 1906.428 129.000 ;
    RECT 1906.884 0.600 1911.828 129.000 ;
    RECT 1912.284 0.600 1917.228 129.000 ;
    RECT 1917.684 0.600 1922.628 129.000 ;
    RECT 1923.084 0.600 1928.028 129.000 ;
    RECT 1928.484 0.600 1933.428 129.000 ;
    RECT 1933.884 0.600 1938.828 129.000 ;
    RECT 1939.284 0.600 1944.228 129.000 ;
    RECT 1944.684 0.600 1949.628 129.000 ;
    RECT 1950.084 0.600 1955.028 129.000 ;
    RECT 1955.484 0.600 1960.428 129.000 ;
    RECT 1960.884 0.600 1965.828 129.000 ;
    RECT 1966.284 0.600 1971.228 129.000 ;
    RECT 1971.684 0.600 1976.628 129.000 ;
    RECT 1977.084 0.600 1982.028 129.000 ;
    RECT 1982.484 0.600 1987.428 129.000 ;
    RECT 1987.884 0.600 1992.828 129.000 ;
    RECT 1993.284 0.600 1998.228 129.000 ;
    RECT 1998.684 0.600 2003.628 129.000 ;
    RECT 2004.084 0.600 2009.028 129.000 ;
    RECT 2009.484 0.600 2014.428 129.000 ;
    RECT 2014.884 0.600 2019.828 129.000 ;
    RECT 2020.284 0.600 2025.228 129.000 ;
    RECT 2025.684 0.600 2030.628 129.000 ;
    RECT 2031.084 0.600 2036.028 129.000 ;
    RECT 2036.484 0.600 2041.428 129.000 ;
    RECT 2041.884 0.600 2046.828 129.000 ;
    RECT 2047.284 0.600 2052.228 129.000 ;
    RECT 2052.684 0.600 2057.628 129.000 ;
    RECT 2058.084 0.600 2063.028 129.000 ;
    RECT 2063.484 0.600 2068.428 129.000 ;
    RECT 2068.884 0.600 2073.828 129.000 ;
    RECT 2074.284 0.600 2079.228 129.000 ;
    RECT 2079.684 0.600 2084.628 129.000 ;
    RECT 2085.084 0.600 2090.028 129.000 ;
    RECT 2090.484 0.600 2095.428 129.000 ;
    RECT 2095.884 0.600 2100.828 129.000 ;
    RECT 2101.284 0.600 2106.228 129.000 ;
    RECT 2106.684 0.600 2111.628 129.000 ;
    RECT 2112.084 0.600 2117.028 129.000 ;
    RECT 2117.484 0.600 2122.428 129.000 ;
    RECT 2122.884 0.600 2127.828 129.000 ;
    RECT 2128.284 0.600 2133.228 129.000 ;
    RECT 2133.684 0.600 2138.628 129.000 ;
    RECT 2139.084 0.600 2144.028 129.000 ;
    RECT 2144.484 0.600 2149.428 129.000 ;
    RECT 2149.884 0.600 2154.828 129.000 ;
    RECT 2155.284 0.600 2160.228 129.000 ;
    RECT 2160.684 0.600 2165.628 129.000 ;
    RECT 2166.084 0.600 2171.028 129.000 ;
    RECT 2171.484 0.600 2176.428 129.000 ;
    RECT 2176.884 0.600 2181.828 129.000 ;
    RECT 2182.284 0.600 2187.228 129.000 ;
    RECT 2187.684 0.600 2192.628 129.000 ;
    RECT 2193.084 0.600 2198.028 129.000 ;
    RECT 2198.484 0.600 2203.428 129.000 ;
    RECT 2203.884 0.600 2208.828 129.000 ;
    RECT 2209.284 0.600 2214.228 129.000 ;
    RECT 2214.684 0.600 2219.628 129.000 ;
    RECT 2220.084 0.600 2225.028 129.000 ;
    RECT 2225.484 0.600 2230.428 129.000 ;
    RECT 2230.884 0.600 2235.828 129.000 ;
    RECT 2236.284 0.600 2241.228 129.000 ;
    RECT 2241.684 0.600 2246.400 129.000 ;
    RECT 0.300 0.600 0.420 1.928 ;
    RECT 0.300 127.672 0.420 129.000 ;
    RECT 0.492 0.600 0.612 1.928 ;
    RECT 0.492 127.672 0.612 129.000 ;
    RECT 5.700 0.600 5.820 1.928 ;
    RECT 5.700 127.672 5.820 129.000 ;
    RECT 5.892 0.600 6.012 1.928 ;
    RECT 5.892 127.672 6.012 129.000 ;
    RECT 11.100 0.600 11.220 1.928 ;
    RECT 11.100 127.672 11.220 129.000 ;
    RECT 11.292 0.600 11.412 1.928 ;
    RECT 11.292 127.672 11.412 129.000 ;
    RECT 16.500 0.600 16.620 1.928 ;
    RECT 16.500 127.672 16.620 129.000 ;
    RECT 16.692 0.600 16.812 1.928 ;
    RECT 16.692 127.672 16.812 129.000 ;
    RECT 21.900 0.600 22.020 1.928 ;
    RECT 21.900 127.672 22.020 129.000 ;
    RECT 22.092 0.600 22.212 1.928 ;
    RECT 22.092 127.672 22.212 129.000 ;
    RECT 27.300 0.600 27.420 1.928 ;
    RECT 27.300 127.672 27.420 129.000 ;
    RECT 27.492 0.600 27.612 1.928 ;
    RECT 27.492 127.672 27.612 129.000 ;
    RECT 32.700 0.600 32.820 1.928 ;
    RECT 32.700 127.672 32.820 129.000 ;
    RECT 32.892 0.600 33.012 1.928 ;
    RECT 32.892 127.672 33.012 129.000 ;
    RECT 38.100 0.600 38.220 1.928 ;
    RECT 38.100 127.672 38.220 129.000 ;
    RECT 38.292 0.600 38.412 1.928 ;
    RECT 38.292 127.672 38.412 129.000 ;
    RECT 43.500 0.600 43.620 1.928 ;
    RECT 43.500 127.672 43.620 129.000 ;
    RECT 43.692 0.600 43.812 1.928 ;
    RECT 43.692 127.672 43.812 129.000 ;
    RECT 48.900 0.600 49.020 1.928 ;
    RECT 48.900 127.672 49.020 129.000 ;
    RECT 49.092 0.600 49.212 1.928 ;
    RECT 49.092 127.672 49.212 129.000 ;
    RECT 54.300 0.600 54.420 1.928 ;
    RECT 54.300 127.672 54.420 129.000 ;
    RECT 54.492 0.600 54.612 1.928 ;
    RECT 54.492 127.672 54.612 129.000 ;
    RECT 59.700 0.600 59.820 1.928 ;
    RECT 59.700 127.672 59.820 129.000 ;
    RECT 59.892 0.600 60.012 1.928 ;
    RECT 59.892 127.672 60.012 129.000 ;
    RECT 65.100 0.600 65.220 1.928 ;
    RECT 65.100 127.672 65.220 129.000 ;
    RECT 65.292 0.600 65.412 1.928 ;
    RECT 65.292 127.672 65.412 129.000 ;
    RECT 70.500 0.600 70.620 1.928 ;
    RECT 70.500 127.672 70.620 129.000 ;
    RECT 70.692 0.600 70.812 1.928 ;
    RECT 70.692 127.672 70.812 129.000 ;
    RECT 75.900 0.600 76.020 1.928 ;
    RECT 75.900 127.672 76.020 129.000 ;
    RECT 76.092 0.600 76.212 1.928 ;
    RECT 76.092 127.672 76.212 129.000 ;
    RECT 81.300 0.600 81.420 1.928 ;
    RECT 81.300 127.672 81.420 129.000 ;
    RECT 81.492 0.600 81.612 1.928 ;
    RECT 81.492 127.672 81.612 129.000 ;
    RECT 86.700 0.600 86.820 1.928 ;
    RECT 86.700 127.672 86.820 129.000 ;
    RECT 86.892 0.600 87.012 1.928 ;
    RECT 86.892 127.672 87.012 129.000 ;
    RECT 92.100 0.600 92.220 1.928 ;
    RECT 92.100 127.672 92.220 129.000 ;
    RECT 92.292 0.600 92.412 1.928 ;
    RECT 92.292 127.672 92.412 129.000 ;
    RECT 97.500 0.600 97.620 1.928 ;
    RECT 97.500 127.672 97.620 129.000 ;
    RECT 97.692 0.600 97.812 1.928 ;
    RECT 97.692 127.672 97.812 129.000 ;
    RECT 102.900 0.600 103.020 1.928 ;
    RECT 102.900 127.672 103.020 129.000 ;
    RECT 103.092 0.600 103.212 1.928 ;
    RECT 103.092 127.672 103.212 129.000 ;
    RECT 108.300 0.600 108.420 1.928 ;
    RECT 108.300 127.672 108.420 129.000 ;
    RECT 108.492 0.600 108.612 1.928 ;
    RECT 108.492 127.672 108.612 129.000 ;
    RECT 113.700 0.600 113.820 1.928 ;
    RECT 113.700 127.672 113.820 129.000 ;
    RECT 113.892 0.600 114.012 1.928 ;
    RECT 113.892 127.672 114.012 129.000 ;
    RECT 119.100 0.600 119.220 1.928 ;
    RECT 119.100 127.672 119.220 129.000 ;
    RECT 119.292 0.600 119.412 1.928 ;
    RECT 119.292 127.672 119.412 129.000 ;
    RECT 124.500 0.600 124.620 1.928 ;
    RECT 124.500 127.672 124.620 129.000 ;
    RECT 124.692 0.600 124.812 1.928 ;
    RECT 124.692 127.672 124.812 129.000 ;
    RECT 129.900 0.600 130.020 1.928 ;
    RECT 129.900 127.672 130.020 129.000 ;
    RECT 130.092 0.600 130.212 1.928 ;
    RECT 130.092 127.672 130.212 129.000 ;
    RECT 135.300 0.600 135.420 1.928 ;
    RECT 135.300 127.672 135.420 129.000 ;
    RECT 135.492 0.600 135.612 1.928 ;
    RECT 135.492 127.672 135.612 129.000 ;
    RECT 140.700 0.600 140.820 1.928 ;
    RECT 140.700 127.672 140.820 129.000 ;
    RECT 140.892 0.600 141.012 1.928 ;
    RECT 140.892 127.672 141.012 129.000 ;
    RECT 146.100 0.600 146.220 1.928 ;
    RECT 146.100 127.672 146.220 129.000 ;
    RECT 146.292 0.600 146.412 1.928 ;
    RECT 146.292 127.672 146.412 129.000 ;
    RECT 151.500 0.600 151.620 1.928 ;
    RECT 151.500 127.672 151.620 129.000 ;
    RECT 151.692 0.600 151.812 1.928 ;
    RECT 151.692 127.672 151.812 129.000 ;
    RECT 156.900 0.600 157.020 1.928 ;
    RECT 156.900 127.672 157.020 129.000 ;
    RECT 157.092 0.600 157.212 1.928 ;
    RECT 157.092 127.672 157.212 129.000 ;
    RECT 162.300 0.600 162.420 1.928 ;
    RECT 162.300 127.672 162.420 129.000 ;
    RECT 162.492 0.600 162.612 1.928 ;
    RECT 162.492 127.672 162.612 129.000 ;
    RECT 167.700 0.600 167.820 1.928 ;
    RECT 167.700 127.672 167.820 129.000 ;
    RECT 167.892 0.600 168.012 1.928 ;
    RECT 167.892 127.672 168.012 129.000 ;
    RECT 173.100 0.600 173.220 1.928 ;
    RECT 173.100 127.672 173.220 129.000 ;
    RECT 173.292 0.600 173.412 1.928 ;
    RECT 173.292 127.672 173.412 129.000 ;
    RECT 178.500 0.600 178.620 1.928 ;
    RECT 178.500 127.672 178.620 129.000 ;
    RECT 178.692 0.600 178.812 1.928 ;
    RECT 178.692 127.672 178.812 129.000 ;
    RECT 183.900 0.600 184.020 1.928 ;
    RECT 183.900 127.672 184.020 129.000 ;
    RECT 184.092 0.600 184.212 1.928 ;
    RECT 184.092 127.672 184.212 129.000 ;
    RECT 189.300 0.600 189.420 1.928 ;
    RECT 189.300 127.672 189.420 129.000 ;
    RECT 189.492 0.600 189.612 1.928 ;
    RECT 189.492 127.672 189.612 129.000 ;
    RECT 194.700 0.600 194.820 1.928 ;
    RECT 194.700 127.672 194.820 129.000 ;
    RECT 194.892 0.600 195.012 1.928 ;
    RECT 194.892 127.672 195.012 129.000 ;
    RECT 200.100 0.600 200.220 1.928 ;
    RECT 200.100 127.672 200.220 129.000 ;
    RECT 200.292 0.600 200.412 1.928 ;
    RECT 200.292 127.672 200.412 129.000 ;
    RECT 205.500 0.600 205.620 1.928 ;
    RECT 205.500 127.672 205.620 129.000 ;
    RECT 205.692 0.600 205.812 1.928 ;
    RECT 205.692 127.672 205.812 129.000 ;
    RECT 210.900 0.600 211.020 1.928 ;
    RECT 210.900 127.672 211.020 129.000 ;
    RECT 211.092 0.600 211.212 1.928 ;
    RECT 211.092 127.672 211.212 129.000 ;
    RECT 216.300 0.600 216.420 1.928 ;
    RECT 216.300 127.672 216.420 129.000 ;
    RECT 216.492 0.600 216.612 1.928 ;
    RECT 216.492 127.672 216.612 129.000 ;
    RECT 221.700 0.600 221.820 1.928 ;
    RECT 221.700 127.672 221.820 129.000 ;
    RECT 221.892 0.600 222.012 1.928 ;
    RECT 221.892 127.672 222.012 129.000 ;
    RECT 227.100 0.600 227.220 1.928 ;
    RECT 227.100 127.672 227.220 129.000 ;
    RECT 227.292 0.600 227.412 1.928 ;
    RECT 227.292 127.672 227.412 129.000 ;
    RECT 232.500 0.600 232.620 1.928 ;
    RECT 232.500 127.672 232.620 129.000 ;
    RECT 232.692 0.600 232.812 1.928 ;
    RECT 232.692 127.672 232.812 129.000 ;
    RECT 237.900 0.600 238.020 1.928 ;
    RECT 237.900 127.672 238.020 129.000 ;
    RECT 238.092 0.600 238.212 1.928 ;
    RECT 238.092 127.672 238.212 129.000 ;
    RECT 243.300 0.600 243.420 1.928 ;
    RECT 243.300 127.672 243.420 129.000 ;
    RECT 243.492 0.600 243.612 1.928 ;
    RECT 243.492 127.672 243.612 129.000 ;
    RECT 248.700 0.600 248.820 1.928 ;
    RECT 248.700 127.672 248.820 129.000 ;
    RECT 248.892 0.600 249.012 1.928 ;
    RECT 248.892 127.672 249.012 129.000 ;
    RECT 254.100 0.600 254.220 1.928 ;
    RECT 254.100 127.672 254.220 129.000 ;
    RECT 254.292 0.600 254.412 1.928 ;
    RECT 254.292 127.672 254.412 129.000 ;
    RECT 259.500 0.600 259.620 1.928 ;
    RECT 259.500 127.672 259.620 129.000 ;
    RECT 259.692 0.600 259.812 1.928 ;
    RECT 259.692 127.672 259.812 129.000 ;
    RECT 264.900 0.600 265.020 1.928 ;
    RECT 264.900 127.672 265.020 129.000 ;
    RECT 265.092 0.600 265.212 1.928 ;
    RECT 265.092 127.672 265.212 129.000 ;
    RECT 270.300 0.600 270.420 1.928 ;
    RECT 270.300 127.672 270.420 129.000 ;
    RECT 270.492 0.600 270.612 1.928 ;
    RECT 270.492 127.672 270.612 129.000 ;
    RECT 275.700 0.600 275.820 1.928 ;
    RECT 275.700 127.672 275.820 129.000 ;
    RECT 275.892 0.600 276.012 1.928 ;
    RECT 275.892 127.672 276.012 129.000 ;
    RECT 281.100 0.600 281.220 1.928 ;
    RECT 281.100 127.672 281.220 129.000 ;
    RECT 281.292 0.600 281.412 1.928 ;
    RECT 281.292 127.672 281.412 129.000 ;
    RECT 286.500 0.600 286.620 1.928 ;
    RECT 286.500 127.672 286.620 129.000 ;
    RECT 286.692 0.600 286.812 1.928 ;
    RECT 286.692 127.672 286.812 129.000 ;
    RECT 291.900 0.600 292.020 1.928 ;
    RECT 291.900 127.672 292.020 129.000 ;
    RECT 292.092 0.600 292.212 1.928 ;
    RECT 292.092 127.672 292.212 129.000 ;
    RECT 297.300 0.600 297.420 1.928 ;
    RECT 297.300 127.672 297.420 129.000 ;
    RECT 297.492 0.600 297.612 1.928 ;
    RECT 297.492 127.672 297.612 129.000 ;
    RECT 302.700 0.600 302.820 1.928 ;
    RECT 302.700 127.672 302.820 129.000 ;
    RECT 302.892 0.600 303.012 1.928 ;
    RECT 302.892 127.672 303.012 129.000 ;
    RECT 308.100 0.600 308.220 1.928 ;
    RECT 308.100 127.672 308.220 129.000 ;
    RECT 308.292 0.600 308.412 1.928 ;
    RECT 308.292 127.672 308.412 129.000 ;
    RECT 313.500 0.600 313.620 1.928 ;
    RECT 313.500 127.672 313.620 129.000 ;
    RECT 313.692 0.600 313.812 1.928 ;
    RECT 313.692 127.672 313.812 129.000 ;
    RECT 318.900 0.600 319.020 1.928 ;
    RECT 318.900 127.672 319.020 129.000 ;
    RECT 319.092 0.600 319.212 1.928 ;
    RECT 319.092 127.672 319.212 129.000 ;
    RECT 324.300 0.600 324.420 1.928 ;
    RECT 324.300 127.672 324.420 129.000 ;
    RECT 324.492 0.600 324.612 1.928 ;
    RECT 324.492 127.672 324.612 129.000 ;
    RECT 329.700 0.600 329.820 1.928 ;
    RECT 329.700 127.672 329.820 129.000 ;
    RECT 329.892 0.600 330.012 1.928 ;
    RECT 329.892 127.672 330.012 129.000 ;
    RECT 335.100 0.600 335.220 1.928 ;
    RECT 335.100 127.672 335.220 129.000 ;
    RECT 335.292 0.600 335.412 1.928 ;
    RECT 335.292 127.672 335.412 129.000 ;
    RECT 340.500 0.600 340.620 1.928 ;
    RECT 340.500 127.672 340.620 129.000 ;
    RECT 340.692 0.600 340.812 1.928 ;
    RECT 340.692 127.672 340.812 129.000 ;
    RECT 345.900 0.600 346.020 1.928 ;
    RECT 345.900 127.672 346.020 129.000 ;
    RECT 346.092 0.600 346.212 1.928 ;
    RECT 346.092 127.672 346.212 129.000 ;
    RECT 351.300 0.600 351.420 1.928 ;
    RECT 351.300 127.672 351.420 129.000 ;
    RECT 351.492 0.600 351.612 1.928 ;
    RECT 351.492 127.672 351.612 129.000 ;
    RECT 356.700 0.600 356.820 1.928 ;
    RECT 356.700 127.672 356.820 129.000 ;
    RECT 356.892 0.600 357.012 1.928 ;
    RECT 356.892 127.672 357.012 129.000 ;
    RECT 362.100 0.600 362.220 1.928 ;
    RECT 362.100 127.672 362.220 129.000 ;
    RECT 362.292 0.600 362.412 1.928 ;
    RECT 362.292 127.672 362.412 129.000 ;
    RECT 367.500 0.600 367.620 1.928 ;
    RECT 367.500 127.672 367.620 129.000 ;
    RECT 367.692 0.600 367.812 1.928 ;
    RECT 367.692 127.672 367.812 129.000 ;
    RECT 372.900 0.600 373.020 1.928 ;
    RECT 372.900 127.672 373.020 129.000 ;
    RECT 373.092 0.600 373.212 1.928 ;
    RECT 373.092 127.672 373.212 129.000 ;
    RECT 378.300 0.600 378.420 1.928 ;
    RECT 378.300 127.672 378.420 129.000 ;
    RECT 378.492 0.600 378.612 1.928 ;
    RECT 378.492 127.672 378.612 129.000 ;
    RECT 383.700 0.600 383.820 1.928 ;
    RECT 383.700 127.672 383.820 129.000 ;
    RECT 383.892 0.600 384.012 1.928 ;
    RECT 383.892 127.672 384.012 129.000 ;
    RECT 389.100 0.600 389.220 1.928 ;
    RECT 389.100 127.672 389.220 129.000 ;
    RECT 389.292 0.600 389.412 1.928 ;
    RECT 389.292 127.672 389.412 129.000 ;
    RECT 394.500 0.600 394.620 1.928 ;
    RECT 394.500 127.672 394.620 129.000 ;
    RECT 394.692 0.600 394.812 1.928 ;
    RECT 394.692 127.672 394.812 129.000 ;
    RECT 399.900 0.600 400.020 1.928 ;
    RECT 399.900 127.672 400.020 129.000 ;
    RECT 400.092 0.600 400.212 1.928 ;
    RECT 400.092 127.672 400.212 129.000 ;
    RECT 405.300 0.600 405.420 1.928 ;
    RECT 405.300 127.672 405.420 129.000 ;
    RECT 405.492 0.600 405.612 1.928 ;
    RECT 405.492 127.672 405.612 129.000 ;
    RECT 410.700 0.600 410.820 1.928 ;
    RECT 410.700 127.672 410.820 129.000 ;
    RECT 410.892 0.600 411.012 1.928 ;
    RECT 410.892 127.672 411.012 129.000 ;
    RECT 416.100 0.600 416.220 1.928 ;
    RECT 416.100 127.672 416.220 129.000 ;
    RECT 416.292 0.600 416.412 1.928 ;
    RECT 416.292 127.672 416.412 129.000 ;
    RECT 421.500 0.600 421.620 1.928 ;
    RECT 421.500 127.672 421.620 129.000 ;
    RECT 421.692 0.600 421.812 1.928 ;
    RECT 421.692 127.672 421.812 129.000 ;
    RECT 426.900 0.600 427.020 1.928 ;
    RECT 426.900 127.672 427.020 129.000 ;
    RECT 427.092 0.600 427.212 1.928 ;
    RECT 427.092 127.672 427.212 129.000 ;
    RECT 432.300 0.600 432.420 1.928 ;
    RECT 432.300 127.672 432.420 129.000 ;
    RECT 432.492 0.600 432.612 1.928 ;
    RECT 432.492 127.672 432.612 129.000 ;
    RECT 437.700 0.600 437.820 1.928 ;
    RECT 437.700 127.672 437.820 129.000 ;
    RECT 437.892 0.600 438.012 1.928 ;
    RECT 437.892 127.672 438.012 129.000 ;
    RECT 443.100 0.600 443.220 1.928 ;
    RECT 443.100 127.672 443.220 129.000 ;
    RECT 443.292 0.600 443.412 1.928 ;
    RECT 443.292 127.672 443.412 129.000 ;
    RECT 448.500 0.600 448.620 1.928 ;
    RECT 448.500 127.672 448.620 129.000 ;
    RECT 448.692 0.600 448.812 1.928 ;
    RECT 448.692 127.672 448.812 129.000 ;
    RECT 453.900 0.600 454.020 1.928 ;
    RECT 453.900 127.672 454.020 129.000 ;
    RECT 454.092 0.600 454.212 1.928 ;
    RECT 454.092 127.672 454.212 129.000 ;
    RECT 459.300 0.600 459.420 1.928 ;
    RECT 459.300 127.672 459.420 129.000 ;
    RECT 459.492 0.600 459.612 1.928 ;
    RECT 459.492 127.672 459.612 129.000 ;
    RECT 464.700 0.600 464.820 1.928 ;
    RECT 464.700 127.672 464.820 129.000 ;
    RECT 464.892 0.600 465.012 1.928 ;
    RECT 464.892 127.672 465.012 129.000 ;
    RECT 470.100 0.600 470.220 1.928 ;
    RECT 470.100 127.672 470.220 129.000 ;
    RECT 470.292 0.600 470.412 1.928 ;
    RECT 470.292 127.672 470.412 129.000 ;
    RECT 475.500 0.600 475.620 1.928 ;
    RECT 475.500 127.672 475.620 129.000 ;
    RECT 475.692 0.600 475.812 1.928 ;
    RECT 475.692 127.672 475.812 129.000 ;
    RECT 480.900 0.600 481.020 1.928 ;
    RECT 480.900 127.672 481.020 129.000 ;
    RECT 481.092 0.600 481.212 1.928 ;
    RECT 481.092 127.672 481.212 129.000 ;
    RECT 486.300 0.600 486.420 1.928 ;
    RECT 486.300 127.672 486.420 129.000 ;
    RECT 486.492 0.600 486.612 1.928 ;
    RECT 486.492 127.672 486.612 129.000 ;
    RECT 491.700 0.600 491.820 1.928 ;
    RECT 491.700 127.672 491.820 129.000 ;
    RECT 491.892 0.600 492.012 1.928 ;
    RECT 491.892 127.672 492.012 129.000 ;
    RECT 497.100 0.600 497.220 1.928 ;
    RECT 497.100 127.672 497.220 129.000 ;
    RECT 497.292 0.600 497.412 1.928 ;
    RECT 497.292 127.672 497.412 129.000 ;
    RECT 502.500 0.600 502.620 1.928 ;
    RECT 502.500 127.672 502.620 129.000 ;
    RECT 502.692 0.600 502.812 1.928 ;
    RECT 502.692 127.672 502.812 129.000 ;
    RECT 507.900 0.600 508.020 1.928 ;
    RECT 507.900 127.672 508.020 129.000 ;
    RECT 508.092 0.600 508.212 1.928 ;
    RECT 508.092 127.672 508.212 129.000 ;
    RECT 513.300 0.600 513.420 1.928 ;
    RECT 513.300 127.672 513.420 129.000 ;
    RECT 513.492 0.600 513.612 1.928 ;
    RECT 513.492 127.672 513.612 129.000 ;
    RECT 518.700 0.600 518.820 1.928 ;
    RECT 518.700 127.672 518.820 129.000 ;
    RECT 518.892 0.600 519.012 1.928 ;
    RECT 518.892 127.672 519.012 129.000 ;
    RECT 524.100 0.600 524.220 1.928 ;
    RECT 524.100 127.672 524.220 129.000 ;
    RECT 524.292 0.600 524.412 1.928 ;
    RECT 524.292 127.672 524.412 129.000 ;
    RECT 529.500 0.600 529.620 1.928 ;
    RECT 529.500 127.672 529.620 129.000 ;
    RECT 529.692 0.600 529.812 1.928 ;
    RECT 529.692 127.672 529.812 129.000 ;
    RECT 534.900 0.600 535.020 1.928 ;
    RECT 534.900 127.672 535.020 129.000 ;
    RECT 535.092 0.600 535.212 1.928 ;
    RECT 535.092 127.672 535.212 129.000 ;
    RECT 540.300 0.600 540.420 1.928 ;
    RECT 540.300 127.672 540.420 129.000 ;
    RECT 540.492 0.600 540.612 1.928 ;
    RECT 540.492 127.672 540.612 129.000 ;
    RECT 545.700 0.600 545.820 1.928 ;
    RECT 545.700 127.672 545.820 129.000 ;
    RECT 545.892 0.600 546.012 1.928 ;
    RECT 545.892 127.672 546.012 129.000 ;
    RECT 551.100 0.600 551.220 1.928 ;
    RECT 551.100 127.672 551.220 129.000 ;
    RECT 551.292 0.600 551.412 1.928 ;
    RECT 551.292 127.672 551.412 129.000 ;
    RECT 556.500 0.600 556.620 1.928 ;
    RECT 556.500 127.672 556.620 129.000 ;
    RECT 556.692 0.600 556.812 1.928 ;
    RECT 556.692 127.672 556.812 129.000 ;
    RECT 561.900 0.600 562.020 1.928 ;
    RECT 561.900 127.672 562.020 129.000 ;
    RECT 562.092 0.600 562.212 1.928 ;
    RECT 562.092 127.672 562.212 129.000 ;
    RECT 567.300 0.600 567.420 1.928 ;
    RECT 567.300 127.672 567.420 129.000 ;
    RECT 567.492 0.600 567.612 1.928 ;
    RECT 567.492 127.672 567.612 129.000 ;
    RECT 572.700 0.600 572.820 1.928 ;
    RECT 572.700 127.672 572.820 129.000 ;
    RECT 572.892 0.600 573.012 1.928 ;
    RECT 572.892 127.672 573.012 129.000 ;
    RECT 578.100 0.600 578.220 1.928 ;
    RECT 578.100 127.672 578.220 129.000 ;
    RECT 578.292 0.600 578.412 1.928 ;
    RECT 578.292 127.672 578.412 129.000 ;
    RECT 583.500 0.600 583.620 1.928 ;
    RECT 583.500 127.672 583.620 129.000 ;
    RECT 583.692 0.600 583.812 1.928 ;
    RECT 583.692 127.672 583.812 129.000 ;
    RECT 588.900 0.600 589.020 1.928 ;
    RECT 588.900 127.672 589.020 129.000 ;
    RECT 589.092 0.600 589.212 1.928 ;
    RECT 589.092 127.672 589.212 129.000 ;
    RECT 594.300 0.600 594.420 1.928 ;
    RECT 594.300 127.672 594.420 129.000 ;
    RECT 594.492 0.600 594.612 1.928 ;
    RECT 594.492 127.672 594.612 129.000 ;
    RECT 599.700 0.600 599.820 1.928 ;
    RECT 599.700 127.672 599.820 129.000 ;
    RECT 599.892 0.600 600.012 1.928 ;
    RECT 599.892 127.672 600.012 129.000 ;
    RECT 605.100 0.600 605.220 1.928 ;
    RECT 605.100 127.672 605.220 129.000 ;
    RECT 605.292 0.600 605.412 1.928 ;
    RECT 605.292 127.672 605.412 129.000 ;
    RECT 610.500 0.600 610.620 1.928 ;
    RECT 610.500 127.672 610.620 129.000 ;
    RECT 610.692 0.600 610.812 1.928 ;
    RECT 610.692 127.672 610.812 129.000 ;
    RECT 615.900 0.600 616.020 1.928 ;
    RECT 615.900 127.672 616.020 129.000 ;
    RECT 616.092 0.600 616.212 1.928 ;
    RECT 616.092 127.672 616.212 129.000 ;
    RECT 621.300 0.600 621.420 1.928 ;
    RECT 621.300 127.672 621.420 129.000 ;
    RECT 621.492 0.600 621.612 1.928 ;
    RECT 621.492 127.672 621.612 129.000 ;
    RECT 626.700 0.600 626.820 1.928 ;
    RECT 626.700 127.672 626.820 129.000 ;
    RECT 626.892 0.600 627.012 1.928 ;
    RECT 626.892 127.672 627.012 129.000 ;
    RECT 632.100 0.600 632.220 1.928 ;
    RECT 632.100 127.672 632.220 129.000 ;
    RECT 632.292 0.600 632.412 1.928 ;
    RECT 632.292 127.672 632.412 129.000 ;
    RECT 637.500 0.600 637.620 1.928 ;
    RECT 637.500 127.672 637.620 129.000 ;
    RECT 637.692 0.600 637.812 1.928 ;
    RECT 637.692 127.672 637.812 129.000 ;
    RECT 642.900 0.600 643.020 1.928 ;
    RECT 642.900 127.672 643.020 129.000 ;
    RECT 643.092 0.600 643.212 1.928 ;
    RECT 643.092 127.672 643.212 129.000 ;
    RECT 648.300 0.600 648.420 1.928 ;
    RECT 648.300 127.672 648.420 129.000 ;
    RECT 648.492 0.600 648.612 1.928 ;
    RECT 648.492 127.672 648.612 129.000 ;
    RECT 653.700 0.600 653.820 1.928 ;
    RECT 653.700 127.672 653.820 129.000 ;
    RECT 653.892 0.600 654.012 1.928 ;
    RECT 653.892 127.672 654.012 129.000 ;
    RECT 659.100 0.600 659.220 1.928 ;
    RECT 659.100 127.672 659.220 129.000 ;
    RECT 659.292 0.600 659.412 1.928 ;
    RECT 659.292 127.672 659.412 129.000 ;
    RECT 664.500 0.600 664.620 1.928 ;
    RECT 664.500 127.672 664.620 129.000 ;
    RECT 664.692 0.600 664.812 1.928 ;
    RECT 664.692 127.672 664.812 129.000 ;
    RECT 669.900 0.600 670.020 1.928 ;
    RECT 669.900 127.672 670.020 129.000 ;
    RECT 670.092 0.600 670.212 1.928 ;
    RECT 670.092 127.672 670.212 129.000 ;
    RECT 675.300 0.600 675.420 1.928 ;
    RECT 675.300 127.672 675.420 129.000 ;
    RECT 675.492 0.600 675.612 1.928 ;
    RECT 675.492 127.672 675.612 129.000 ;
    RECT 680.700 0.600 680.820 1.928 ;
    RECT 680.700 127.672 680.820 129.000 ;
    RECT 680.892 0.600 681.012 1.928 ;
    RECT 680.892 127.672 681.012 129.000 ;
    RECT 686.100 0.600 686.220 1.928 ;
    RECT 686.100 127.672 686.220 129.000 ;
    RECT 686.292 0.600 686.412 1.928 ;
    RECT 686.292 127.672 686.412 129.000 ;
    RECT 691.500 0.600 691.620 1.928 ;
    RECT 691.500 127.672 691.620 129.000 ;
    RECT 691.692 0.600 691.812 1.928 ;
    RECT 691.692 127.672 691.812 129.000 ;
    RECT 696.900 0.600 697.020 1.928 ;
    RECT 696.900 127.672 697.020 129.000 ;
    RECT 697.092 0.600 697.212 1.928 ;
    RECT 697.092 127.672 697.212 129.000 ;
    RECT 702.300 0.600 702.420 1.928 ;
    RECT 702.300 127.672 702.420 129.000 ;
    RECT 702.492 0.600 702.612 1.928 ;
    RECT 702.492 127.672 702.612 129.000 ;
    RECT 707.700 0.600 707.820 1.928 ;
    RECT 707.700 127.672 707.820 129.000 ;
    RECT 707.892 0.600 708.012 1.928 ;
    RECT 707.892 127.672 708.012 129.000 ;
    RECT 713.100 0.600 713.220 1.928 ;
    RECT 713.100 127.672 713.220 129.000 ;
    RECT 713.292 0.600 713.412 1.928 ;
    RECT 713.292 127.672 713.412 129.000 ;
    RECT 718.500 0.600 718.620 1.928 ;
    RECT 718.500 127.672 718.620 129.000 ;
    RECT 718.692 0.600 718.812 1.928 ;
    RECT 718.692 127.672 718.812 129.000 ;
    RECT 723.900 0.600 724.020 1.928 ;
    RECT 723.900 127.672 724.020 129.000 ;
    RECT 724.092 0.600 724.212 1.928 ;
    RECT 724.092 127.672 724.212 129.000 ;
    RECT 729.300 0.600 729.420 1.928 ;
    RECT 729.300 127.672 729.420 129.000 ;
    RECT 729.492 0.600 729.612 1.928 ;
    RECT 729.492 127.672 729.612 129.000 ;
    RECT 734.700 0.600 734.820 1.928 ;
    RECT 734.700 127.672 734.820 129.000 ;
    RECT 734.892 0.600 735.012 1.928 ;
    RECT 734.892 127.672 735.012 129.000 ;
    RECT 740.100 0.600 740.220 1.928 ;
    RECT 740.100 127.672 740.220 129.000 ;
    RECT 740.292 0.600 740.412 1.928 ;
    RECT 740.292 127.672 740.412 129.000 ;
    RECT 745.500 0.600 745.620 1.928 ;
    RECT 745.500 127.672 745.620 129.000 ;
    RECT 745.692 0.600 745.812 1.928 ;
    RECT 745.692 127.672 745.812 129.000 ;
    RECT 750.900 0.600 751.020 1.928 ;
    RECT 750.900 127.672 751.020 129.000 ;
    RECT 751.092 0.600 751.212 1.928 ;
    RECT 751.092 127.672 751.212 129.000 ;
    RECT 756.300 0.600 756.420 1.928 ;
    RECT 756.300 127.672 756.420 129.000 ;
    RECT 756.492 0.600 756.612 1.928 ;
    RECT 756.492 127.672 756.612 129.000 ;
    RECT 761.700 0.600 761.820 1.928 ;
    RECT 761.700 127.672 761.820 129.000 ;
    RECT 761.892 0.600 762.012 1.928 ;
    RECT 761.892 127.672 762.012 129.000 ;
    RECT 767.100 0.600 767.220 1.928 ;
    RECT 767.100 127.672 767.220 129.000 ;
    RECT 767.292 0.600 767.412 1.928 ;
    RECT 767.292 127.672 767.412 129.000 ;
    RECT 772.500 0.600 772.620 1.928 ;
    RECT 772.500 127.672 772.620 129.000 ;
    RECT 772.692 0.600 772.812 1.928 ;
    RECT 772.692 127.672 772.812 129.000 ;
    RECT 777.900 0.600 778.020 1.928 ;
    RECT 777.900 127.672 778.020 129.000 ;
    RECT 778.092 0.600 778.212 1.928 ;
    RECT 778.092 127.672 778.212 129.000 ;
    RECT 783.300 0.600 783.420 1.928 ;
    RECT 783.300 127.672 783.420 129.000 ;
    RECT 783.492 0.600 783.612 1.928 ;
    RECT 783.492 127.672 783.612 129.000 ;
    RECT 788.700 0.600 788.820 1.928 ;
    RECT 788.700 127.672 788.820 129.000 ;
    RECT 788.892 0.600 789.012 1.928 ;
    RECT 788.892 127.672 789.012 129.000 ;
    RECT 794.100 0.600 794.220 1.928 ;
    RECT 794.100 127.672 794.220 129.000 ;
    RECT 794.292 0.600 794.412 1.928 ;
    RECT 794.292 127.672 794.412 129.000 ;
    RECT 799.500 0.600 799.620 1.928 ;
    RECT 799.500 127.672 799.620 129.000 ;
    RECT 799.692 0.600 799.812 1.928 ;
    RECT 799.692 127.672 799.812 129.000 ;
    RECT 804.900 0.600 805.020 1.928 ;
    RECT 804.900 127.672 805.020 129.000 ;
    RECT 805.092 0.600 805.212 1.928 ;
    RECT 805.092 127.672 805.212 129.000 ;
    RECT 810.300 0.600 810.420 1.928 ;
    RECT 810.300 127.672 810.420 129.000 ;
    RECT 810.492 0.600 810.612 1.928 ;
    RECT 810.492 127.672 810.612 129.000 ;
    RECT 815.700 0.600 815.820 1.928 ;
    RECT 815.700 127.672 815.820 129.000 ;
    RECT 815.892 0.600 816.012 1.928 ;
    RECT 815.892 127.672 816.012 129.000 ;
    RECT 821.100 0.600 821.220 1.928 ;
    RECT 821.100 127.672 821.220 129.000 ;
    RECT 821.292 0.600 821.412 1.928 ;
    RECT 821.292 127.672 821.412 129.000 ;
    RECT 826.500 0.600 826.620 1.928 ;
    RECT 826.500 127.672 826.620 129.000 ;
    RECT 826.692 0.600 826.812 1.928 ;
    RECT 826.692 127.672 826.812 129.000 ;
    RECT 831.900 0.600 832.020 1.928 ;
    RECT 831.900 127.672 832.020 129.000 ;
    RECT 832.092 0.600 832.212 1.928 ;
    RECT 832.092 127.672 832.212 129.000 ;
    RECT 837.300 0.600 837.420 1.928 ;
    RECT 837.300 127.672 837.420 129.000 ;
    RECT 837.492 0.600 837.612 1.928 ;
    RECT 837.492 127.672 837.612 129.000 ;
    RECT 842.700 0.600 842.820 1.928 ;
    RECT 842.700 127.672 842.820 129.000 ;
    RECT 842.892 0.600 843.012 1.928 ;
    RECT 842.892 127.672 843.012 129.000 ;
    RECT 848.100 0.600 848.220 1.928 ;
    RECT 848.100 127.672 848.220 129.000 ;
    RECT 848.292 0.600 848.412 1.928 ;
    RECT 848.292 127.672 848.412 129.000 ;
    RECT 853.500 0.600 853.620 1.928 ;
    RECT 853.500 127.672 853.620 129.000 ;
    RECT 853.692 0.600 853.812 1.928 ;
    RECT 853.692 127.672 853.812 129.000 ;
    RECT 858.900 0.600 859.020 1.928 ;
    RECT 858.900 127.672 859.020 129.000 ;
    RECT 859.092 0.600 859.212 1.928 ;
    RECT 859.092 127.672 859.212 129.000 ;
    RECT 864.300 0.600 864.420 1.928 ;
    RECT 864.300 127.672 864.420 129.000 ;
    RECT 864.492 0.600 864.612 1.928 ;
    RECT 864.492 127.672 864.612 129.000 ;
    RECT 869.700 0.600 869.820 1.928 ;
    RECT 869.700 127.672 869.820 129.000 ;
    RECT 869.892 0.600 870.012 1.928 ;
    RECT 869.892 127.672 870.012 129.000 ;
    RECT 875.100 0.600 875.220 1.928 ;
    RECT 875.100 127.672 875.220 129.000 ;
    RECT 875.292 0.600 875.412 1.928 ;
    RECT 875.292 127.672 875.412 129.000 ;
    RECT 880.500 0.600 880.620 1.928 ;
    RECT 880.500 127.672 880.620 129.000 ;
    RECT 880.692 0.600 880.812 1.928 ;
    RECT 880.692 127.672 880.812 129.000 ;
    RECT 885.900 0.600 886.020 1.928 ;
    RECT 885.900 127.672 886.020 129.000 ;
    RECT 886.092 0.600 886.212 1.928 ;
    RECT 886.092 127.672 886.212 129.000 ;
    RECT 891.300 0.600 891.420 1.928 ;
    RECT 891.300 127.672 891.420 129.000 ;
    RECT 891.492 0.600 891.612 1.928 ;
    RECT 891.492 127.672 891.612 129.000 ;
    RECT 896.700 0.600 896.820 1.928 ;
    RECT 896.700 127.672 896.820 129.000 ;
    RECT 896.892 0.600 897.012 1.928 ;
    RECT 896.892 127.672 897.012 129.000 ;
    RECT 902.100 0.600 902.220 1.928 ;
    RECT 902.100 127.672 902.220 129.000 ;
    RECT 902.292 0.600 902.412 1.928 ;
    RECT 902.292 127.672 902.412 129.000 ;
    RECT 907.500 0.600 907.620 1.928 ;
    RECT 907.500 127.672 907.620 129.000 ;
    RECT 907.692 0.600 907.812 1.928 ;
    RECT 907.692 127.672 907.812 129.000 ;
    RECT 912.900 0.600 913.020 1.928 ;
    RECT 912.900 127.672 913.020 129.000 ;
    RECT 913.092 0.600 913.212 1.928 ;
    RECT 913.092 127.672 913.212 129.000 ;
    RECT 918.300 0.600 918.420 1.928 ;
    RECT 918.300 127.672 918.420 129.000 ;
    RECT 918.492 0.600 918.612 1.928 ;
    RECT 918.492 127.672 918.612 129.000 ;
    RECT 923.700 0.600 923.820 1.928 ;
    RECT 923.700 127.672 923.820 129.000 ;
    RECT 923.892 0.600 924.012 1.928 ;
    RECT 923.892 127.672 924.012 129.000 ;
    RECT 929.100 0.600 929.220 1.928 ;
    RECT 929.100 127.672 929.220 129.000 ;
    RECT 929.292 0.600 929.412 1.928 ;
    RECT 929.292 127.672 929.412 129.000 ;
    RECT 934.500 0.600 934.620 1.928 ;
    RECT 934.500 127.672 934.620 129.000 ;
    RECT 934.692 0.600 934.812 1.928 ;
    RECT 934.692 127.672 934.812 129.000 ;
    RECT 939.900 0.600 940.020 1.928 ;
    RECT 939.900 127.672 940.020 129.000 ;
    RECT 940.092 0.600 940.212 1.928 ;
    RECT 940.092 127.672 940.212 129.000 ;
    RECT 945.300 0.600 945.420 1.928 ;
    RECT 945.300 127.672 945.420 129.000 ;
    RECT 945.492 0.600 945.612 1.928 ;
    RECT 945.492 127.672 945.612 129.000 ;
    RECT 950.700 0.600 950.820 1.928 ;
    RECT 950.700 127.672 950.820 129.000 ;
    RECT 950.892 0.600 951.012 1.928 ;
    RECT 950.892 127.672 951.012 129.000 ;
    RECT 956.100 0.600 956.220 1.928 ;
    RECT 956.100 127.672 956.220 129.000 ;
    RECT 956.292 0.600 956.412 1.928 ;
    RECT 956.292 127.672 956.412 129.000 ;
    RECT 961.500 0.600 961.620 1.928 ;
    RECT 961.500 127.672 961.620 129.000 ;
    RECT 961.692 0.600 961.812 1.928 ;
    RECT 961.692 127.672 961.812 129.000 ;
    RECT 966.900 0.600 967.020 1.928 ;
    RECT 966.900 127.672 967.020 129.000 ;
    RECT 967.092 0.600 967.212 1.928 ;
    RECT 967.092 127.672 967.212 129.000 ;
    RECT 972.300 0.600 972.420 1.928 ;
    RECT 972.300 127.672 972.420 129.000 ;
    RECT 972.492 0.600 972.612 1.928 ;
    RECT 972.492 127.672 972.612 129.000 ;
    RECT 977.700 0.600 977.820 1.928 ;
    RECT 977.700 127.672 977.820 129.000 ;
    RECT 977.892 0.600 978.012 1.928 ;
    RECT 977.892 127.672 978.012 129.000 ;
    RECT 983.100 0.600 983.220 1.928 ;
    RECT 983.100 127.672 983.220 129.000 ;
    RECT 983.292 0.600 983.412 1.928 ;
    RECT 983.292 127.672 983.412 129.000 ;
    RECT 988.500 0.600 988.620 1.928 ;
    RECT 988.500 127.672 988.620 129.000 ;
    RECT 988.692 0.600 988.812 1.928 ;
    RECT 988.692 127.672 988.812 129.000 ;
    RECT 993.900 0.600 994.020 1.928 ;
    RECT 993.900 127.672 994.020 129.000 ;
    RECT 994.092 0.600 994.212 1.928 ;
    RECT 994.092 127.672 994.212 129.000 ;
    RECT 999.300 0.600 999.420 1.928 ;
    RECT 999.300 127.672 999.420 129.000 ;
    RECT 999.492 0.600 999.612 1.928 ;
    RECT 999.492 127.672 999.612 129.000 ;
    RECT 1004.700 0.600 1004.820 1.928 ;
    RECT 1004.700 127.672 1004.820 129.000 ;
    RECT 1004.892 0.600 1005.012 1.928 ;
    RECT 1004.892 127.672 1005.012 129.000 ;
    RECT 1010.100 0.600 1010.220 1.928 ;
    RECT 1010.100 127.672 1010.220 129.000 ;
    RECT 1010.292 0.600 1010.412 1.928 ;
    RECT 1010.292 127.672 1010.412 129.000 ;
    RECT 1015.500 0.600 1015.620 1.928 ;
    RECT 1015.500 127.672 1015.620 129.000 ;
    RECT 1015.692 0.600 1015.812 1.928 ;
    RECT 1015.692 127.672 1015.812 129.000 ;
    RECT 1020.900 0.600 1021.020 1.928 ;
    RECT 1020.900 127.672 1021.020 129.000 ;
    RECT 1021.092 0.600 1021.212 1.928 ;
    RECT 1021.092 127.672 1021.212 129.000 ;
    RECT 1026.300 0.600 1026.420 1.928 ;
    RECT 1026.300 127.672 1026.420 129.000 ;
    RECT 1026.492 0.600 1026.612 1.928 ;
    RECT 1026.492 127.672 1026.612 129.000 ;
    RECT 1031.700 0.600 1031.820 1.928 ;
    RECT 1031.700 127.672 1031.820 129.000 ;
    RECT 1031.892 0.600 1032.012 1.928 ;
    RECT 1031.892 127.672 1032.012 129.000 ;
    RECT 1037.100 0.600 1037.220 1.928 ;
    RECT 1037.100 127.672 1037.220 129.000 ;
    RECT 1037.292 0.600 1037.412 1.928 ;
    RECT 1037.292 127.672 1037.412 129.000 ;
    RECT 1042.500 0.600 1042.620 1.928 ;
    RECT 1042.500 127.672 1042.620 129.000 ;
    RECT 1042.692 0.600 1042.812 1.928 ;
    RECT 1042.692 127.672 1042.812 129.000 ;
    RECT 1047.900 0.600 1048.020 1.928 ;
    RECT 1047.900 127.672 1048.020 129.000 ;
    RECT 1048.092 0.600 1048.212 1.928 ;
    RECT 1048.092 127.672 1048.212 129.000 ;
    RECT 1053.300 0.600 1053.420 1.928 ;
    RECT 1053.300 127.672 1053.420 129.000 ;
    RECT 1053.492 0.600 1053.612 1.928 ;
    RECT 1053.492 127.672 1053.612 129.000 ;
    RECT 1058.700 0.600 1058.820 1.928 ;
    RECT 1058.700 127.672 1058.820 129.000 ;
    RECT 1058.892 0.600 1059.012 1.928 ;
    RECT 1058.892 127.672 1059.012 129.000 ;
    RECT 1064.100 0.600 1064.220 1.928 ;
    RECT 1064.100 127.672 1064.220 129.000 ;
    RECT 1064.292 0.600 1064.412 1.928 ;
    RECT 1064.292 127.672 1064.412 129.000 ;
    RECT 1069.500 0.600 1069.620 1.928 ;
    RECT 1069.500 127.672 1069.620 129.000 ;
    RECT 1069.692 0.600 1069.812 1.928 ;
    RECT 1069.692 127.672 1069.812 129.000 ;
    RECT 1074.900 0.600 1075.020 1.928 ;
    RECT 1074.900 127.672 1075.020 129.000 ;
    RECT 1075.092 0.600 1075.212 1.928 ;
    RECT 1075.092 127.672 1075.212 129.000 ;
    RECT 1080.300 0.600 1080.420 1.928 ;
    RECT 1080.300 127.672 1080.420 129.000 ;
    RECT 1080.492 0.600 1080.612 1.928 ;
    RECT 1080.492 127.672 1080.612 129.000 ;
    RECT 1085.700 0.600 1085.820 1.928 ;
    RECT 1085.700 127.672 1085.820 129.000 ;
    RECT 1085.892 0.600 1086.012 1.928 ;
    RECT 1085.892 127.672 1086.012 129.000 ;
    RECT 1091.100 0.600 1091.220 1.928 ;
    RECT 1091.100 127.672 1091.220 129.000 ;
    RECT 1091.292 0.600 1091.412 1.928 ;
    RECT 1091.292 127.672 1091.412 129.000 ;
    RECT 1096.500 0.600 1096.620 1.928 ;
    RECT 1096.500 127.672 1096.620 129.000 ;
    RECT 1096.692 0.600 1096.812 1.928 ;
    RECT 1096.692 127.672 1096.812 129.000 ;
    RECT 1101.900 0.600 1102.020 1.928 ;
    RECT 1101.900 127.672 1102.020 129.000 ;
    RECT 1102.092 0.600 1102.212 1.928 ;
    RECT 1102.092 127.672 1102.212 129.000 ;
    RECT 1107.300 0.600 1107.420 1.928 ;
    RECT 1107.300 127.672 1107.420 129.000 ;
    RECT 1107.492 0.600 1107.612 1.928 ;
    RECT 1107.492 127.672 1107.612 129.000 ;
    RECT 1112.700 0.600 1112.820 1.928 ;
    RECT 1112.700 127.672 1112.820 129.000 ;
    RECT 1112.892 0.600 1113.012 1.928 ;
    RECT 1112.892 127.672 1113.012 129.000 ;
    RECT 1118.100 0.600 1118.220 1.928 ;
    RECT 1118.100 127.672 1118.220 129.000 ;
    RECT 1118.292 0.600 1118.412 1.928 ;
    RECT 1118.292 127.672 1118.412 129.000 ;
    RECT 1123.500 0.600 1123.620 1.928 ;
    RECT 1123.500 127.672 1123.620 129.000 ;
    RECT 1123.692 0.600 1123.812 1.928 ;
    RECT 1123.692 127.672 1123.812 129.000 ;
    RECT 1128.900 0.600 1129.020 1.928 ;
    RECT 1128.900 127.672 1129.020 129.000 ;
    RECT 1129.092 0.600 1129.212 1.928 ;
    RECT 1129.092 127.672 1129.212 129.000 ;
    RECT 1134.300 0.600 1134.420 1.928 ;
    RECT 1134.300 127.672 1134.420 129.000 ;
    RECT 1134.492 0.600 1134.612 1.928 ;
    RECT 1134.492 127.672 1134.612 129.000 ;
    RECT 1139.700 0.600 1139.820 1.928 ;
    RECT 1139.700 127.672 1139.820 129.000 ;
    RECT 1139.892 0.600 1140.012 1.928 ;
    RECT 1139.892 127.672 1140.012 129.000 ;
    RECT 1145.100 0.600 1145.220 1.928 ;
    RECT 1145.100 127.672 1145.220 129.000 ;
    RECT 1145.292 0.600 1145.412 1.928 ;
    RECT 1145.292 127.672 1145.412 129.000 ;
    RECT 1150.500 0.600 1150.620 1.928 ;
    RECT 1150.500 127.672 1150.620 129.000 ;
    RECT 1150.692 0.600 1150.812 1.928 ;
    RECT 1150.692 127.672 1150.812 129.000 ;
    RECT 1155.900 0.600 1156.020 1.928 ;
    RECT 1155.900 127.672 1156.020 129.000 ;
    RECT 1156.092 0.600 1156.212 1.928 ;
    RECT 1156.092 127.672 1156.212 129.000 ;
    RECT 1161.300 0.600 1161.420 1.928 ;
    RECT 1161.300 127.672 1161.420 129.000 ;
    RECT 1161.492 0.600 1161.612 1.928 ;
    RECT 1161.492 127.672 1161.612 129.000 ;
    RECT 1166.700 0.600 1166.820 1.928 ;
    RECT 1166.700 127.672 1166.820 129.000 ;
    RECT 1166.892 0.600 1167.012 1.928 ;
    RECT 1166.892 127.672 1167.012 129.000 ;
    RECT 1172.100 0.600 1172.220 1.928 ;
    RECT 1172.100 127.672 1172.220 129.000 ;
    RECT 1172.292 0.600 1172.412 1.928 ;
    RECT 1172.292 127.672 1172.412 129.000 ;
    RECT 1177.500 0.600 1177.620 1.928 ;
    RECT 1177.500 127.672 1177.620 129.000 ;
    RECT 1177.692 0.600 1177.812 1.928 ;
    RECT 1177.692 127.672 1177.812 129.000 ;
    RECT 1182.900 0.600 1183.020 1.928 ;
    RECT 1182.900 127.672 1183.020 129.000 ;
    RECT 1183.092 0.600 1183.212 1.928 ;
    RECT 1183.092 127.672 1183.212 129.000 ;
    RECT 1188.300 0.600 1188.420 1.928 ;
    RECT 1188.300 127.672 1188.420 129.000 ;
    RECT 1188.492 0.600 1188.612 1.928 ;
    RECT 1188.492 127.672 1188.612 129.000 ;
    RECT 1193.700 0.600 1193.820 1.928 ;
    RECT 1193.700 127.672 1193.820 129.000 ;
    RECT 1193.892 0.600 1194.012 1.928 ;
    RECT 1193.892 127.672 1194.012 129.000 ;
    RECT 1199.100 0.600 1199.220 1.928 ;
    RECT 1199.100 127.672 1199.220 129.000 ;
    RECT 1199.292 0.600 1199.412 1.928 ;
    RECT 1199.292 127.672 1199.412 129.000 ;
    RECT 1204.500 0.600 1204.620 1.928 ;
    RECT 1204.500 127.672 1204.620 129.000 ;
    RECT 1204.692 0.600 1204.812 1.928 ;
    RECT 1204.692 127.672 1204.812 129.000 ;
    RECT 1209.900 0.600 1210.020 1.928 ;
    RECT 1209.900 127.672 1210.020 129.000 ;
    RECT 1210.092 0.600 1210.212 1.928 ;
    RECT 1210.092 127.672 1210.212 129.000 ;
    RECT 1215.300 0.600 1215.420 1.928 ;
    RECT 1215.300 127.672 1215.420 129.000 ;
    RECT 1215.492 0.600 1215.612 1.928 ;
    RECT 1215.492 127.672 1215.612 129.000 ;
    RECT 1220.700 0.600 1220.820 1.928 ;
    RECT 1220.700 127.672 1220.820 129.000 ;
    RECT 1220.892 0.600 1221.012 1.928 ;
    RECT 1220.892 127.672 1221.012 129.000 ;
    RECT 1226.100 0.600 1226.220 1.928 ;
    RECT 1226.100 127.672 1226.220 129.000 ;
    RECT 1226.292 0.600 1226.412 1.928 ;
    RECT 1226.292 127.672 1226.412 129.000 ;
    RECT 1231.500 0.600 1231.620 1.928 ;
    RECT 1231.500 127.672 1231.620 129.000 ;
    RECT 1231.692 0.600 1231.812 1.928 ;
    RECT 1231.692 127.672 1231.812 129.000 ;
    RECT 1236.900 0.600 1237.020 1.928 ;
    RECT 1236.900 127.672 1237.020 129.000 ;
    RECT 1237.092 0.600 1237.212 1.928 ;
    RECT 1237.092 127.672 1237.212 129.000 ;
    RECT 1242.300 0.600 1242.420 1.928 ;
    RECT 1242.300 127.672 1242.420 129.000 ;
    RECT 1242.492 0.600 1242.612 1.928 ;
    RECT 1242.492 127.672 1242.612 129.000 ;
    RECT 1247.700 0.600 1247.820 1.928 ;
    RECT 1247.700 127.672 1247.820 129.000 ;
    RECT 1247.892 0.600 1248.012 1.928 ;
    RECT 1247.892 127.672 1248.012 129.000 ;
    RECT 1253.100 0.600 1253.220 1.928 ;
    RECT 1253.100 127.672 1253.220 129.000 ;
    RECT 1253.292 0.600 1253.412 1.928 ;
    RECT 1253.292 127.672 1253.412 129.000 ;
    RECT 1258.500 0.600 1258.620 1.928 ;
    RECT 1258.500 127.672 1258.620 129.000 ;
    RECT 1258.692 0.600 1258.812 1.928 ;
    RECT 1258.692 127.672 1258.812 129.000 ;
    RECT 1263.900 0.600 1264.020 1.928 ;
    RECT 1263.900 127.672 1264.020 129.000 ;
    RECT 1264.092 0.600 1264.212 1.928 ;
    RECT 1264.092 127.672 1264.212 129.000 ;
    RECT 1269.300 0.600 1269.420 1.928 ;
    RECT 1269.300 127.672 1269.420 129.000 ;
    RECT 1269.492 0.600 1269.612 1.928 ;
    RECT 1269.492 127.672 1269.612 129.000 ;
    RECT 1274.700 0.600 1274.820 1.928 ;
    RECT 1274.700 127.672 1274.820 129.000 ;
    RECT 1274.892 0.600 1275.012 1.928 ;
    RECT 1274.892 127.672 1275.012 129.000 ;
    RECT 1280.100 0.600 1280.220 1.928 ;
    RECT 1280.100 127.672 1280.220 129.000 ;
    RECT 1280.292 0.600 1280.412 1.928 ;
    RECT 1280.292 127.672 1280.412 129.000 ;
    RECT 1285.500 0.600 1285.620 1.928 ;
    RECT 1285.500 127.672 1285.620 129.000 ;
    RECT 1285.692 0.600 1285.812 1.928 ;
    RECT 1285.692 127.672 1285.812 129.000 ;
    RECT 1290.900 0.600 1291.020 1.928 ;
    RECT 1290.900 127.672 1291.020 129.000 ;
    RECT 1291.092 0.600 1291.212 1.928 ;
    RECT 1291.092 127.672 1291.212 129.000 ;
    RECT 1296.300 0.600 1296.420 1.928 ;
    RECT 1296.300 127.672 1296.420 129.000 ;
    RECT 1296.492 0.600 1296.612 1.928 ;
    RECT 1296.492 127.672 1296.612 129.000 ;
    RECT 1301.700 0.600 1301.820 1.928 ;
    RECT 1301.700 127.672 1301.820 129.000 ;
    RECT 1301.892 0.600 1302.012 1.928 ;
    RECT 1301.892 127.672 1302.012 129.000 ;
    RECT 1307.100 0.600 1307.220 1.928 ;
    RECT 1307.100 127.672 1307.220 129.000 ;
    RECT 1307.292 0.600 1307.412 1.928 ;
    RECT 1307.292 127.672 1307.412 129.000 ;
    RECT 1312.500 0.600 1312.620 1.928 ;
    RECT 1312.500 127.672 1312.620 129.000 ;
    RECT 1312.692 0.600 1312.812 1.928 ;
    RECT 1312.692 127.672 1312.812 129.000 ;
    RECT 1317.900 0.600 1318.020 1.928 ;
    RECT 1317.900 127.672 1318.020 129.000 ;
    RECT 1318.092 0.600 1318.212 1.928 ;
    RECT 1318.092 127.672 1318.212 129.000 ;
    RECT 1323.300 0.600 1323.420 1.928 ;
    RECT 1323.300 127.672 1323.420 129.000 ;
    RECT 1323.492 0.600 1323.612 1.928 ;
    RECT 1323.492 127.672 1323.612 129.000 ;
    RECT 1328.700 0.600 1328.820 1.928 ;
    RECT 1328.700 127.672 1328.820 129.000 ;
    RECT 1328.892 0.600 1329.012 1.928 ;
    RECT 1328.892 127.672 1329.012 129.000 ;
    RECT 1334.100 0.600 1334.220 1.928 ;
    RECT 1334.100 127.672 1334.220 129.000 ;
    RECT 1334.292 0.600 1334.412 1.928 ;
    RECT 1334.292 127.672 1334.412 129.000 ;
    RECT 1339.500 0.600 1339.620 1.928 ;
    RECT 1339.500 127.672 1339.620 129.000 ;
    RECT 1339.692 0.600 1339.812 1.928 ;
    RECT 1339.692 127.672 1339.812 129.000 ;
    RECT 1344.900 0.600 1345.020 1.928 ;
    RECT 1344.900 127.672 1345.020 129.000 ;
    RECT 1345.092 0.600 1345.212 1.928 ;
    RECT 1345.092 127.672 1345.212 129.000 ;
    RECT 1350.300 0.600 1350.420 1.928 ;
    RECT 1350.300 127.672 1350.420 129.000 ;
    RECT 1350.492 0.600 1350.612 1.928 ;
    RECT 1350.492 127.672 1350.612 129.000 ;
    RECT 1355.700 0.600 1355.820 1.928 ;
    RECT 1355.700 127.672 1355.820 129.000 ;
    RECT 1355.892 0.600 1356.012 1.928 ;
    RECT 1355.892 127.672 1356.012 129.000 ;
    RECT 1361.100 0.600 1361.220 1.928 ;
    RECT 1361.100 127.672 1361.220 129.000 ;
    RECT 1361.292 0.600 1361.412 1.928 ;
    RECT 1361.292 127.672 1361.412 129.000 ;
    RECT 1366.500 0.600 1366.620 1.928 ;
    RECT 1366.500 127.672 1366.620 129.000 ;
    RECT 1366.692 0.600 1366.812 1.928 ;
    RECT 1366.692 127.672 1366.812 129.000 ;
    RECT 1371.900 0.600 1372.020 1.928 ;
    RECT 1371.900 127.672 1372.020 129.000 ;
    RECT 1372.092 0.600 1372.212 1.928 ;
    RECT 1372.092 127.672 1372.212 129.000 ;
    RECT 1377.300 0.600 1377.420 1.928 ;
    RECT 1377.300 127.672 1377.420 129.000 ;
    RECT 1377.492 0.600 1377.612 1.928 ;
    RECT 1377.492 127.672 1377.612 129.000 ;
    RECT 1382.700 0.600 1382.820 1.928 ;
    RECT 1382.700 127.672 1382.820 129.000 ;
    RECT 1382.892 0.600 1383.012 1.928 ;
    RECT 1382.892 127.672 1383.012 129.000 ;
    RECT 1388.100 0.600 1388.220 1.928 ;
    RECT 1388.100 127.672 1388.220 129.000 ;
    RECT 1388.292 0.600 1388.412 1.928 ;
    RECT 1388.292 127.672 1388.412 129.000 ;
    RECT 1393.500 0.600 1393.620 1.928 ;
    RECT 1393.500 127.672 1393.620 129.000 ;
    RECT 1393.692 0.600 1393.812 1.928 ;
    RECT 1393.692 127.672 1393.812 129.000 ;
    RECT 1398.900 0.600 1399.020 1.928 ;
    RECT 1398.900 127.672 1399.020 129.000 ;
    RECT 1399.092 0.600 1399.212 1.928 ;
    RECT 1399.092 127.672 1399.212 129.000 ;
    RECT 1404.300 0.600 1404.420 1.928 ;
    RECT 1404.300 127.672 1404.420 129.000 ;
    RECT 1404.492 0.600 1404.612 1.928 ;
    RECT 1404.492 127.672 1404.612 129.000 ;
    RECT 1409.700 0.600 1409.820 1.928 ;
    RECT 1409.700 127.672 1409.820 129.000 ;
    RECT 1409.892 0.600 1410.012 1.928 ;
    RECT 1409.892 127.672 1410.012 129.000 ;
    RECT 1415.100 0.600 1415.220 1.928 ;
    RECT 1415.100 127.672 1415.220 129.000 ;
    RECT 1415.292 0.600 1415.412 1.928 ;
    RECT 1415.292 127.672 1415.412 129.000 ;
    RECT 1420.500 0.600 1420.620 1.928 ;
    RECT 1420.500 127.672 1420.620 129.000 ;
    RECT 1420.692 0.600 1420.812 1.928 ;
    RECT 1420.692 127.672 1420.812 129.000 ;
    RECT 1425.900 0.600 1426.020 1.928 ;
    RECT 1425.900 127.672 1426.020 129.000 ;
    RECT 1426.092 0.600 1426.212 1.928 ;
    RECT 1426.092 127.672 1426.212 129.000 ;
    RECT 1431.300 0.600 1431.420 1.928 ;
    RECT 1431.300 127.672 1431.420 129.000 ;
    RECT 1431.492 0.600 1431.612 1.928 ;
    RECT 1431.492 127.672 1431.612 129.000 ;
    RECT 1436.700 0.600 1436.820 1.928 ;
    RECT 1436.700 127.672 1436.820 129.000 ;
    RECT 1436.892 0.600 1437.012 1.928 ;
    RECT 1436.892 127.672 1437.012 129.000 ;
    RECT 1442.100 0.600 1442.220 1.928 ;
    RECT 1442.100 127.672 1442.220 129.000 ;
    RECT 1442.292 0.600 1442.412 1.928 ;
    RECT 1442.292 127.672 1442.412 129.000 ;
    RECT 1447.500 0.600 1447.620 1.928 ;
    RECT 1447.500 127.672 1447.620 129.000 ;
    RECT 1447.692 0.600 1447.812 1.928 ;
    RECT 1447.692 127.672 1447.812 129.000 ;
    RECT 1452.900 0.600 1453.020 1.928 ;
    RECT 1452.900 127.672 1453.020 129.000 ;
    RECT 1453.092 0.600 1453.212 1.928 ;
    RECT 1453.092 127.672 1453.212 129.000 ;
    RECT 1458.300 0.600 1458.420 1.928 ;
    RECT 1458.300 127.672 1458.420 129.000 ;
    RECT 1458.492 0.600 1458.612 1.928 ;
    RECT 1458.492 127.672 1458.612 129.000 ;
    RECT 1463.700 0.600 1463.820 1.928 ;
    RECT 1463.700 127.672 1463.820 129.000 ;
    RECT 1463.892 0.600 1464.012 1.928 ;
    RECT 1463.892 127.672 1464.012 129.000 ;
    RECT 1469.100 0.600 1469.220 1.928 ;
    RECT 1469.100 127.672 1469.220 129.000 ;
    RECT 1469.292 0.600 1469.412 1.928 ;
    RECT 1469.292 127.672 1469.412 129.000 ;
    RECT 1474.500 0.600 1474.620 1.928 ;
    RECT 1474.500 127.672 1474.620 129.000 ;
    RECT 1474.692 0.600 1474.812 1.928 ;
    RECT 1474.692 127.672 1474.812 129.000 ;
    RECT 1479.900 0.600 1480.020 1.928 ;
    RECT 1479.900 127.672 1480.020 129.000 ;
    RECT 1480.092 0.600 1480.212 1.928 ;
    RECT 1480.092 127.672 1480.212 129.000 ;
    RECT 1485.300 0.600 1485.420 1.928 ;
    RECT 1485.300 127.672 1485.420 129.000 ;
    RECT 1485.492 0.600 1485.612 1.928 ;
    RECT 1485.492 127.672 1485.612 129.000 ;
    RECT 1490.700 0.600 1490.820 1.928 ;
    RECT 1490.700 127.672 1490.820 129.000 ;
    RECT 1490.892 0.600 1491.012 1.928 ;
    RECT 1490.892 127.672 1491.012 129.000 ;
    RECT 1496.100 0.600 1496.220 1.928 ;
    RECT 1496.100 127.672 1496.220 129.000 ;
    RECT 1496.292 0.600 1496.412 1.928 ;
    RECT 1496.292 127.672 1496.412 129.000 ;
    RECT 1501.500 0.600 1501.620 1.928 ;
    RECT 1501.500 127.672 1501.620 129.000 ;
    RECT 1501.692 0.600 1501.812 1.928 ;
    RECT 1501.692 127.672 1501.812 129.000 ;
    RECT 1506.900 0.600 1507.020 1.928 ;
    RECT 1506.900 127.672 1507.020 129.000 ;
    RECT 1507.092 0.600 1507.212 1.928 ;
    RECT 1507.092 127.672 1507.212 129.000 ;
    RECT 1512.300 0.600 1512.420 1.928 ;
    RECT 1512.300 127.672 1512.420 129.000 ;
    RECT 1512.492 0.600 1512.612 1.928 ;
    RECT 1512.492 127.672 1512.612 129.000 ;
    RECT 1517.700 0.600 1517.820 1.928 ;
    RECT 1517.700 127.672 1517.820 129.000 ;
    RECT 1517.892 0.600 1518.012 1.928 ;
    RECT 1517.892 127.672 1518.012 129.000 ;
    RECT 1523.100 0.600 1523.220 1.928 ;
    RECT 1523.100 127.672 1523.220 129.000 ;
    RECT 1523.292 0.600 1523.412 1.928 ;
    RECT 1523.292 127.672 1523.412 129.000 ;
    RECT 1528.500 0.600 1528.620 1.928 ;
    RECT 1528.500 127.672 1528.620 129.000 ;
    RECT 1528.692 0.600 1528.812 1.928 ;
    RECT 1528.692 127.672 1528.812 129.000 ;
    RECT 1533.900 0.600 1534.020 1.928 ;
    RECT 1533.900 127.672 1534.020 129.000 ;
    RECT 1534.092 0.600 1534.212 1.928 ;
    RECT 1534.092 127.672 1534.212 129.000 ;
    RECT 1539.300 0.600 1539.420 1.928 ;
    RECT 1539.300 127.672 1539.420 129.000 ;
    RECT 1539.492 0.600 1539.612 1.928 ;
    RECT 1539.492 127.672 1539.612 129.000 ;
    RECT 1544.700 0.600 1544.820 1.928 ;
    RECT 1544.700 127.672 1544.820 129.000 ;
    RECT 1544.892 0.600 1545.012 1.928 ;
    RECT 1544.892 127.672 1545.012 129.000 ;
    RECT 1550.100 0.600 1550.220 1.928 ;
    RECT 1550.100 127.672 1550.220 129.000 ;
    RECT 1550.292 0.600 1550.412 1.928 ;
    RECT 1550.292 127.672 1550.412 129.000 ;
    RECT 1555.500 0.600 1555.620 1.928 ;
    RECT 1555.500 127.672 1555.620 129.000 ;
    RECT 1555.692 0.600 1555.812 1.928 ;
    RECT 1555.692 127.672 1555.812 129.000 ;
    RECT 1560.900 0.600 1561.020 1.928 ;
    RECT 1560.900 127.672 1561.020 129.000 ;
    RECT 1561.092 0.600 1561.212 1.928 ;
    RECT 1561.092 127.672 1561.212 129.000 ;
    RECT 1566.300 0.600 1566.420 1.928 ;
    RECT 1566.300 127.672 1566.420 129.000 ;
    RECT 1566.492 0.600 1566.612 1.928 ;
    RECT 1566.492 127.672 1566.612 129.000 ;
    RECT 1571.700 0.600 1571.820 1.928 ;
    RECT 1571.700 127.672 1571.820 129.000 ;
    RECT 1571.892 0.600 1572.012 1.928 ;
    RECT 1571.892 127.672 1572.012 129.000 ;
    RECT 1577.100 0.600 1577.220 1.928 ;
    RECT 1577.100 127.672 1577.220 129.000 ;
    RECT 1577.292 0.600 1577.412 1.928 ;
    RECT 1577.292 127.672 1577.412 129.000 ;
    RECT 1582.500 0.600 1582.620 1.928 ;
    RECT 1582.500 127.672 1582.620 129.000 ;
    RECT 1582.692 0.600 1582.812 1.928 ;
    RECT 1582.692 127.672 1582.812 129.000 ;
    RECT 1587.900 0.600 1588.020 1.928 ;
    RECT 1587.900 127.672 1588.020 129.000 ;
    RECT 1588.092 0.600 1588.212 1.928 ;
    RECT 1588.092 127.672 1588.212 129.000 ;
    RECT 1593.300 0.600 1593.420 1.928 ;
    RECT 1593.300 127.672 1593.420 129.000 ;
    RECT 1593.492 0.600 1593.612 1.928 ;
    RECT 1593.492 127.672 1593.612 129.000 ;
    RECT 1598.700 0.600 1598.820 1.928 ;
    RECT 1598.700 127.672 1598.820 129.000 ;
    RECT 1598.892 0.600 1599.012 1.928 ;
    RECT 1598.892 127.672 1599.012 129.000 ;
    RECT 1604.100 0.600 1604.220 1.928 ;
    RECT 1604.100 127.672 1604.220 129.000 ;
    RECT 1604.292 0.600 1604.412 1.928 ;
    RECT 1604.292 127.672 1604.412 129.000 ;
    RECT 1609.500 0.600 1609.620 1.928 ;
    RECT 1609.500 127.672 1609.620 129.000 ;
    RECT 1609.692 0.600 1609.812 1.928 ;
    RECT 1609.692 127.672 1609.812 129.000 ;
    RECT 1614.900 0.600 1615.020 1.928 ;
    RECT 1614.900 127.672 1615.020 129.000 ;
    RECT 1615.092 0.600 1615.212 1.928 ;
    RECT 1615.092 127.672 1615.212 129.000 ;
    RECT 1620.300 0.600 1620.420 1.928 ;
    RECT 1620.300 127.672 1620.420 129.000 ;
    RECT 1620.492 0.600 1620.612 1.928 ;
    RECT 1620.492 127.672 1620.612 129.000 ;
    RECT 1625.700 0.600 1625.820 1.928 ;
    RECT 1625.700 127.672 1625.820 129.000 ;
    RECT 1625.892 0.600 1626.012 1.928 ;
    RECT 1625.892 127.672 1626.012 129.000 ;
    RECT 1631.100 0.600 1631.220 1.928 ;
    RECT 1631.100 127.672 1631.220 129.000 ;
    RECT 1631.292 0.600 1631.412 1.928 ;
    RECT 1631.292 127.672 1631.412 129.000 ;
    RECT 1636.500 0.600 1636.620 1.928 ;
    RECT 1636.500 127.672 1636.620 129.000 ;
    RECT 1636.692 0.600 1636.812 1.928 ;
    RECT 1636.692 127.672 1636.812 129.000 ;
    RECT 1641.900 0.600 1642.020 1.928 ;
    RECT 1641.900 127.672 1642.020 129.000 ;
    RECT 1642.092 0.600 1642.212 1.928 ;
    RECT 1642.092 127.672 1642.212 129.000 ;
    RECT 1647.300 0.600 1647.420 1.928 ;
    RECT 1647.300 127.672 1647.420 129.000 ;
    RECT 1647.492 0.600 1647.612 1.928 ;
    RECT 1647.492 127.672 1647.612 129.000 ;
    RECT 1652.700 0.600 1652.820 1.928 ;
    RECT 1652.700 127.672 1652.820 129.000 ;
    RECT 1652.892 0.600 1653.012 1.928 ;
    RECT 1652.892 127.672 1653.012 129.000 ;
    RECT 1658.100 0.600 1658.220 1.928 ;
    RECT 1658.100 127.672 1658.220 129.000 ;
    RECT 1658.292 0.600 1658.412 1.928 ;
    RECT 1658.292 127.672 1658.412 129.000 ;
    RECT 1663.500 0.600 1663.620 1.928 ;
    RECT 1663.500 127.672 1663.620 129.000 ;
    RECT 1663.692 0.600 1663.812 1.928 ;
    RECT 1663.692 127.672 1663.812 129.000 ;
    RECT 1668.900 0.600 1669.020 1.928 ;
    RECT 1668.900 127.672 1669.020 129.000 ;
    RECT 1669.092 0.600 1669.212 1.928 ;
    RECT 1669.092 127.672 1669.212 129.000 ;
    RECT 1674.300 0.600 1674.420 1.928 ;
    RECT 1674.300 127.672 1674.420 129.000 ;
    RECT 1674.492 0.600 1674.612 1.928 ;
    RECT 1674.492 127.672 1674.612 129.000 ;
    RECT 1679.700 0.600 1679.820 1.928 ;
    RECT 1679.700 127.672 1679.820 129.000 ;
    RECT 1679.892 0.600 1680.012 1.928 ;
    RECT 1679.892 127.672 1680.012 129.000 ;
    RECT 1685.100 0.600 1685.220 1.928 ;
    RECT 1685.100 127.672 1685.220 129.000 ;
    RECT 1685.292 0.600 1685.412 1.928 ;
    RECT 1685.292 127.672 1685.412 129.000 ;
    RECT 1690.500 0.600 1690.620 1.928 ;
    RECT 1690.500 127.672 1690.620 129.000 ;
    RECT 1690.692 0.600 1690.812 1.928 ;
    RECT 1690.692 127.672 1690.812 129.000 ;
    RECT 1695.900 0.600 1696.020 1.928 ;
    RECT 1695.900 127.672 1696.020 129.000 ;
    RECT 1696.092 0.600 1696.212 1.928 ;
    RECT 1696.092 127.672 1696.212 129.000 ;
    RECT 1701.300 0.600 1701.420 1.928 ;
    RECT 1701.300 127.672 1701.420 129.000 ;
    RECT 1701.492 0.600 1701.612 1.928 ;
    RECT 1701.492 127.672 1701.612 129.000 ;
    RECT 1706.700 0.600 1706.820 1.928 ;
    RECT 1706.700 127.672 1706.820 129.000 ;
    RECT 1706.892 0.600 1707.012 1.928 ;
    RECT 1706.892 127.672 1707.012 129.000 ;
    RECT 1712.100 0.600 1712.220 1.928 ;
    RECT 1712.100 127.672 1712.220 129.000 ;
    RECT 1712.292 0.600 1712.412 1.928 ;
    RECT 1712.292 127.672 1712.412 129.000 ;
    RECT 1717.500 0.600 1717.620 1.928 ;
    RECT 1717.500 127.672 1717.620 129.000 ;
    RECT 1717.692 0.600 1717.812 1.928 ;
    RECT 1717.692 127.672 1717.812 129.000 ;
    RECT 1722.900 0.600 1723.020 1.928 ;
    RECT 1722.900 127.672 1723.020 129.000 ;
    RECT 1723.092 0.600 1723.212 1.928 ;
    RECT 1723.092 127.672 1723.212 129.000 ;
    RECT 1728.300 0.600 1728.420 1.928 ;
    RECT 1728.300 127.672 1728.420 129.000 ;
    RECT 1728.492 0.600 1728.612 1.928 ;
    RECT 1728.492 127.672 1728.612 129.000 ;
    RECT 1733.700 0.600 1733.820 1.928 ;
    RECT 1733.700 127.672 1733.820 129.000 ;
    RECT 1733.892 0.600 1734.012 1.928 ;
    RECT 1733.892 127.672 1734.012 129.000 ;
    RECT 1739.100 0.600 1739.220 1.928 ;
    RECT 1739.100 127.672 1739.220 129.000 ;
    RECT 1739.292 0.600 1739.412 1.928 ;
    RECT 1739.292 127.672 1739.412 129.000 ;
    RECT 1744.500 0.600 1744.620 1.928 ;
    RECT 1744.500 127.672 1744.620 129.000 ;
    RECT 1744.692 0.600 1744.812 1.928 ;
    RECT 1744.692 127.672 1744.812 129.000 ;
    RECT 1749.900 0.600 1750.020 1.928 ;
    RECT 1749.900 127.672 1750.020 129.000 ;
    RECT 1750.092 0.600 1750.212 1.928 ;
    RECT 1750.092 127.672 1750.212 129.000 ;
    RECT 1755.300 0.600 1755.420 1.928 ;
    RECT 1755.300 127.672 1755.420 129.000 ;
    RECT 1755.492 0.600 1755.612 1.928 ;
    RECT 1755.492 127.672 1755.612 129.000 ;
    RECT 1760.700 0.600 1760.820 1.928 ;
    RECT 1760.700 127.672 1760.820 129.000 ;
    RECT 1760.892 0.600 1761.012 1.928 ;
    RECT 1760.892 127.672 1761.012 129.000 ;
    RECT 1766.100 0.600 1766.220 1.928 ;
    RECT 1766.100 127.672 1766.220 129.000 ;
    RECT 1766.292 0.600 1766.412 1.928 ;
    RECT 1766.292 127.672 1766.412 129.000 ;
    RECT 1771.500 0.600 1771.620 1.928 ;
    RECT 1771.500 127.672 1771.620 129.000 ;
    RECT 1771.692 0.600 1771.812 1.928 ;
    RECT 1771.692 127.672 1771.812 129.000 ;
    RECT 1776.900 0.600 1777.020 1.928 ;
    RECT 1776.900 127.672 1777.020 129.000 ;
    RECT 1777.092 0.600 1777.212 1.928 ;
    RECT 1777.092 127.672 1777.212 129.000 ;
    RECT 1782.300 0.600 1782.420 1.928 ;
    RECT 1782.300 127.672 1782.420 129.000 ;
    RECT 1782.492 0.600 1782.612 1.928 ;
    RECT 1782.492 127.672 1782.612 129.000 ;
    RECT 1787.700 0.600 1787.820 1.928 ;
    RECT 1787.700 127.672 1787.820 129.000 ;
    RECT 1787.892 0.600 1788.012 1.928 ;
    RECT 1787.892 127.672 1788.012 129.000 ;
    RECT 1793.100 0.600 1793.220 1.928 ;
    RECT 1793.100 127.672 1793.220 129.000 ;
    RECT 1793.292 0.600 1793.412 1.928 ;
    RECT 1793.292 127.672 1793.412 129.000 ;
    RECT 1798.500 0.600 1798.620 1.928 ;
    RECT 1798.500 127.672 1798.620 129.000 ;
    RECT 1798.692 0.600 1798.812 1.928 ;
    RECT 1798.692 127.672 1798.812 129.000 ;
    RECT 1803.900 0.600 1804.020 1.928 ;
    RECT 1803.900 127.672 1804.020 129.000 ;
    RECT 1804.092 0.600 1804.212 1.928 ;
    RECT 1804.092 127.672 1804.212 129.000 ;
    RECT 1809.300 0.600 1809.420 1.928 ;
    RECT 1809.300 127.672 1809.420 129.000 ;
    RECT 1809.492 0.600 1809.612 1.928 ;
    RECT 1809.492 127.672 1809.612 129.000 ;
    RECT 1814.700 0.600 1814.820 1.928 ;
    RECT 1814.700 127.672 1814.820 129.000 ;
    RECT 1814.892 0.600 1815.012 1.928 ;
    RECT 1814.892 127.672 1815.012 129.000 ;
    RECT 1820.100 0.600 1820.220 1.928 ;
    RECT 1820.100 127.672 1820.220 129.000 ;
    RECT 1820.292 0.600 1820.412 1.928 ;
    RECT 1820.292 127.672 1820.412 129.000 ;
    RECT 1825.500 0.600 1825.620 1.928 ;
    RECT 1825.500 127.672 1825.620 129.000 ;
    RECT 1825.692 0.600 1825.812 1.928 ;
    RECT 1825.692 127.672 1825.812 129.000 ;
    RECT 1830.900 0.600 1831.020 1.928 ;
    RECT 1830.900 127.672 1831.020 129.000 ;
    RECT 1831.092 0.600 1831.212 1.928 ;
    RECT 1831.092 127.672 1831.212 129.000 ;
    RECT 1836.300 0.600 1836.420 1.928 ;
    RECT 1836.300 127.672 1836.420 129.000 ;
    RECT 1836.492 0.600 1836.612 1.928 ;
    RECT 1836.492 127.672 1836.612 129.000 ;
    RECT 1841.700 0.600 1841.820 1.928 ;
    RECT 1841.700 127.672 1841.820 129.000 ;
    RECT 1841.892 0.600 1842.012 1.928 ;
    RECT 1841.892 127.672 1842.012 129.000 ;
    RECT 1847.100 0.600 1847.220 1.928 ;
    RECT 1847.100 127.672 1847.220 129.000 ;
    RECT 1847.292 0.600 1847.412 1.928 ;
    RECT 1847.292 127.672 1847.412 129.000 ;
    RECT 1852.500 0.600 1852.620 1.928 ;
    RECT 1852.500 127.672 1852.620 129.000 ;
    RECT 1852.692 0.600 1852.812 1.928 ;
    RECT 1852.692 127.672 1852.812 129.000 ;
    RECT 1857.900 0.600 1858.020 1.928 ;
    RECT 1857.900 127.672 1858.020 129.000 ;
    RECT 1858.092 0.600 1858.212 1.928 ;
    RECT 1858.092 127.672 1858.212 129.000 ;
    RECT 1863.300 0.600 1863.420 1.928 ;
    RECT 1863.300 127.672 1863.420 129.000 ;
    RECT 1863.492 0.600 1863.612 1.928 ;
    RECT 1863.492 127.672 1863.612 129.000 ;
    RECT 1868.700 0.600 1868.820 1.928 ;
    RECT 1868.700 127.672 1868.820 129.000 ;
    RECT 1868.892 0.600 1869.012 1.928 ;
    RECT 1868.892 127.672 1869.012 129.000 ;
    RECT 1874.100 0.600 1874.220 1.928 ;
    RECT 1874.100 127.672 1874.220 129.000 ;
    RECT 1874.292 0.600 1874.412 1.928 ;
    RECT 1874.292 127.672 1874.412 129.000 ;
    RECT 1879.500 0.600 1879.620 1.928 ;
    RECT 1879.500 127.672 1879.620 129.000 ;
    RECT 1879.692 0.600 1879.812 1.928 ;
    RECT 1879.692 127.672 1879.812 129.000 ;
    RECT 1884.900 0.600 1885.020 1.928 ;
    RECT 1884.900 127.672 1885.020 129.000 ;
    RECT 1885.092 0.600 1885.212 1.928 ;
    RECT 1885.092 127.672 1885.212 129.000 ;
    RECT 1890.300 0.600 1890.420 1.928 ;
    RECT 1890.300 127.672 1890.420 129.000 ;
    RECT 1890.492 0.600 1890.612 1.928 ;
    RECT 1890.492 127.672 1890.612 129.000 ;
    RECT 1895.700 0.600 1895.820 1.928 ;
    RECT 1895.700 127.672 1895.820 129.000 ;
    RECT 1895.892 0.600 1896.012 1.928 ;
    RECT 1895.892 127.672 1896.012 129.000 ;
    RECT 1901.100 0.600 1901.220 1.928 ;
    RECT 1901.100 127.672 1901.220 129.000 ;
    RECT 1901.292 0.600 1901.412 1.928 ;
    RECT 1901.292 127.672 1901.412 129.000 ;
    RECT 1906.500 0.600 1906.620 1.928 ;
    RECT 1906.500 127.672 1906.620 129.000 ;
    RECT 1906.692 0.600 1906.812 1.928 ;
    RECT 1906.692 127.672 1906.812 129.000 ;
    RECT 1911.900 0.600 1912.020 1.928 ;
    RECT 1911.900 127.672 1912.020 129.000 ;
    RECT 1912.092 0.600 1912.212 1.928 ;
    RECT 1912.092 127.672 1912.212 129.000 ;
    RECT 1917.300 0.600 1917.420 1.928 ;
    RECT 1917.300 127.672 1917.420 129.000 ;
    RECT 1917.492 0.600 1917.612 1.928 ;
    RECT 1917.492 127.672 1917.612 129.000 ;
    RECT 1922.700 0.600 1922.820 1.928 ;
    RECT 1922.700 127.672 1922.820 129.000 ;
    RECT 1922.892 0.600 1923.012 1.928 ;
    RECT 1922.892 127.672 1923.012 129.000 ;
    RECT 1928.100 0.600 1928.220 1.928 ;
    RECT 1928.100 127.672 1928.220 129.000 ;
    RECT 1928.292 0.600 1928.412 1.928 ;
    RECT 1928.292 127.672 1928.412 129.000 ;
    RECT 1933.500 0.600 1933.620 1.928 ;
    RECT 1933.500 127.672 1933.620 129.000 ;
    RECT 1933.692 0.600 1933.812 1.928 ;
    RECT 1933.692 127.672 1933.812 129.000 ;
    RECT 1938.900 0.600 1939.020 1.928 ;
    RECT 1938.900 127.672 1939.020 129.000 ;
    RECT 1939.092 0.600 1939.212 1.928 ;
    RECT 1939.092 127.672 1939.212 129.000 ;
    RECT 1944.300 0.600 1944.420 1.928 ;
    RECT 1944.300 127.672 1944.420 129.000 ;
    RECT 1944.492 0.600 1944.612 1.928 ;
    RECT 1944.492 127.672 1944.612 129.000 ;
    RECT 1949.700 0.600 1949.820 1.928 ;
    RECT 1949.700 127.672 1949.820 129.000 ;
    RECT 1949.892 0.600 1950.012 1.928 ;
    RECT 1949.892 127.672 1950.012 129.000 ;
    RECT 1955.100 0.600 1955.220 1.928 ;
    RECT 1955.100 127.672 1955.220 129.000 ;
    RECT 1955.292 0.600 1955.412 1.928 ;
    RECT 1955.292 127.672 1955.412 129.000 ;
    RECT 1960.500 0.600 1960.620 1.928 ;
    RECT 1960.500 127.672 1960.620 129.000 ;
    RECT 1960.692 0.600 1960.812 1.928 ;
    RECT 1960.692 127.672 1960.812 129.000 ;
    RECT 1965.900 0.600 1966.020 1.928 ;
    RECT 1965.900 127.672 1966.020 129.000 ;
    RECT 1966.092 0.600 1966.212 1.928 ;
    RECT 1966.092 127.672 1966.212 129.000 ;
    RECT 1971.300 0.600 1971.420 1.928 ;
    RECT 1971.300 127.672 1971.420 129.000 ;
    RECT 1971.492 0.600 1971.612 1.928 ;
    RECT 1971.492 127.672 1971.612 129.000 ;
    RECT 1976.700 0.600 1976.820 1.928 ;
    RECT 1976.700 127.672 1976.820 129.000 ;
    RECT 1976.892 0.600 1977.012 1.928 ;
    RECT 1976.892 127.672 1977.012 129.000 ;
    RECT 1982.100 0.600 1982.220 1.928 ;
    RECT 1982.100 127.672 1982.220 129.000 ;
    RECT 1982.292 0.600 1982.412 1.928 ;
    RECT 1982.292 127.672 1982.412 129.000 ;
    RECT 1987.500 0.600 1987.620 1.928 ;
    RECT 1987.500 127.672 1987.620 129.000 ;
    RECT 1987.692 0.600 1987.812 1.928 ;
    RECT 1987.692 127.672 1987.812 129.000 ;
    RECT 1992.900 0.600 1993.020 1.928 ;
    RECT 1992.900 127.672 1993.020 129.000 ;
    RECT 1993.092 0.600 1993.212 1.928 ;
    RECT 1993.092 127.672 1993.212 129.000 ;
    RECT 1998.300 0.600 1998.420 1.928 ;
    RECT 1998.300 127.672 1998.420 129.000 ;
    RECT 1998.492 0.600 1998.612 1.928 ;
    RECT 1998.492 127.672 1998.612 129.000 ;
    RECT 2003.700 0.600 2003.820 1.928 ;
    RECT 2003.700 127.672 2003.820 129.000 ;
    RECT 2003.892 0.600 2004.012 1.928 ;
    RECT 2003.892 127.672 2004.012 129.000 ;
    RECT 2009.100 0.600 2009.220 1.928 ;
    RECT 2009.100 127.672 2009.220 129.000 ;
    RECT 2009.292 0.600 2009.412 1.928 ;
    RECT 2009.292 127.672 2009.412 129.000 ;
    RECT 2014.500 0.600 2014.620 1.928 ;
    RECT 2014.500 127.672 2014.620 129.000 ;
    RECT 2014.692 0.600 2014.812 1.928 ;
    RECT 2014.692 127.672 2014.812 129.000 ;
    RECT 2019.900 0.600 2020.020 1.928 ;
    RECT 2019.900 127.672 2020.020 129.000 ;
    RECT 2020.092 0.600 2020.212 1.928 ;
    RECT 2020.092 127.672 2020.212 129.000 ;
    RECT 2025.300 0.600 2025.420 1.928 ;
    RECT 2025.300 127.672 2025.420 129.000 ;
    RECT 2025.492 0.600 2025.612 1.928 ;
    RECT 2025.492 127.672 2025.612 129.000 ;
    RECT 2030.700 0.600 2030.820 1.928 ;
    RECT 2030.700 127.672 2030.820 129.000 ;
    RECT 2030.892 0.600 2031.012 1.928 ;
    RECT 2030.892 127.672 2031.012 129.000 ;
    RECT 2036.100 0.600 2036.220 1.928 ;
    RECT 2036.100 127.672 2036.220 129.000 ;
    RECT 2036.292 0.600 2036.412 1.928 ;
    RECT 2036.292 127.672 2036.412 129.000 ;
    RECT 2041.500 0.600 2041.620 1.928 ;
    RECT 2041.500 127.672 2041.620 129.000 ;
    RECT 2041.692 0.600 2041.812 1.928 ;
    RECT 2041.692 127.672 2041.812 129.000 ;
    RECT 2046.900 0.600 2047.020 1.928 ;
    RECT 2046.900 127.672 2047.020 129.000 ;
    RECT 2047.092 0.600 2047.212 1.928 ;
    RECT 2047.092 127.672 2047.212 129.000 ;
    RECT 2052.300 0.600 2052.420 1.928 ;
    RECT 2052.300 127.672 2052.420 129.000 ;
    RECT 2052.492 0.600 2052.612 1.928 ;
    RECT 2052.492 127.672 2052.612 129.000 ;
    RECT 2057.700 0.600 2057.820 1.928 ;
    RECT 2057.700 127.672 2057.820 129.000 ;
    RECT 2057.892 0.600 2058.012 1.928 ;
    RECT 2057.892 127.672 2058.012 129.000 ;
    RECT 2063.100 0.600 2063.220 1.928 ;
    RECT 2063.100 127.672 2063.220 129.000 ;
    RECT 2063.292 0.600 2063.412 1.928 ;
    RECT 2063.292 127.672 2063.412 129.000 ;
    RECT 2068.500 0.600 2068.620 1.928 ;
    RECT 2068.500 127.672 2068.620 129.000 ;
    RECT 2068.692 0.600 2068.812 1.928 ;
    RECT 2068.692 127.672 2068.812 129.000 ;
    RECT 2073.900 0.600 2074.020 1.928 ;
    RECT 2073.900 127.672 2074.020 129.000 ;
    RECT 2074.092 0.600 2074.212 1.928 ;
    RECT 2074.092 127.672 2074.212 129.000 ;
    RECT 2079.300 0.600 2079.420 1.928 ;
    RECT 2079.300 127.672 2079.420 129.000 ;
    RECT 2079.492 0.600 2079.612 1.928 ;
    RECT 2079.492 127.672 2079.612 129.000 ;
    RECT 2084.700 0.600 2084.820 1.928 ;
    RECT 2084.700 127.672 2084.820 129.000 ;
    RECT 2084.892 0.600 2085.012 1.928 ;
    RECT 2084.892 127.672 2085.012 129.000 ;
    RECT 2090.100 0.600 2090.220 1.928 ;
    RECT 2090.100 127.672 2090.220 129.000 ;
    RECT 2090.292 0.600 2090.412 1.928 ;
    RECT 2090.292 127.672 2090.412 129.000 ;
    RECT 2095.500 0.600 2095.620 1.928 ;
    RECT 2095.500 127.672 2095.620 129.000 ;
    RECT 2095.692 0.600 2095.812 1.928 ;
    RECT 2095.692 127.672 2095.812 129.000 ;
    RECT 2100.900 0.600 2101.020 1.928 ;
    RECT 2100.900 127.672 2101.020 129.000 ;
    RECT 2101.092 0.600 2101.212 1.928 ;
    RECT 2101.092 127.672 2101.212 129.000 ;
    RECT 2106.300 0.600 2106.420 1.928 ;
    RECT 2106.300 127.672 2106.420 129.000 ;
    RECT 2106.492 0.600 2106.612 1.928 ;
    RECT 2106.492 127.672 2106.612 129.000 ;
    RECT 2111.700 0.600 2111.820 1.928 ;
    RECT 2111.700 127.672 2111.820 129.000 ;
    RECT 2111.892 0.600 2112.012 1.928 ;
    RECT 2111.892 127.672 2112.012 129.000 ;
    RECT 2117.100 0.600 2117.220 1.928 ;
    RECT 2117.100 127.672 2117.220 129.000 ;
    RECT 2117.292 0.600 2117.412 1.928 ;
    RECT 2117.292 127.672 2117.412 129.000 ;
    RECT 2122.500 0.600 2122.620 1.928 ;
    RECT 2122.500 127.672 2122.620 129.000 ;
    RECT 2122.692 0.600 2122.812 1.928 ;
    RECT 2122.692 127.672 2122.812 129.000 ;
    RECT 2127.900 0.600 2128.020 1.928 ;
    RECT 2127.900 127.672 2128.020 129.000 ;
    RECT 2128.092 0.600 2128.212 1.928 ;
    RECT 2128.092 127.672 2128.212 129.000 ;
    RECT 2133.300 0.600 2133.420 1.928 ;
    RECT 2133.300 127.672 2133.420 129.000 ;
    RECT 2133.492 0.600 2133.612 1.928 ;
    RECT 2133.492 127.672 2133.612 129.000 ;
    RECT 2138.700 0.600 2138.820 1.928 ;
    RECT 2138.700 127.672 2138.820 129.000 ;
    RECT 2138.892 0.600 2139.012 1.928 ;
    RECT 2138.892 127.672 2139.012 129.000 ;
    RECT 2144.100 0.600 2144.220 1.928 ;
    RECT 2144.100 127.672 2144.220 129.000 ;
    RECT 2144.292 0.600 2144.412 1.928 ;
    RECT 2144.292 127.672 2144.412 129.000 ;
    RECT 2149.500 0.600 2149.620 1.928 ;
    RECT 2149.500 127.672 2149.620 129.000 ;
    RECT 2149.692 0.600 2149.812 1.928 ;
    RECT 2149.692 127.672 2149.812 129.000 ;
    RECT 2154.900 0.600 2155.020 1.928 ;
    RECT 2154.900 127.672 2155.020 129.000 ;
    RECT 2155.092 0.600 2155.212 1.928 ;
    RECT 2155.092 127.672 2155.212 129.000 ;
    RECT 2160.300 0.600 2160.420 1.928 ;
    RECT 2160.300 127.672 2160.420 129.000 ;
    RECT 2160.492 0.600 2160.612 1.928 ;
    RECT 2160.492 127.672 2160.612 129.000 ;
    RECT 2165.700 0.600 2165.820 1.928 ;
    RECT 2165.700 127.672 2165.820 129.000 ;
    RECT 2165.892 0.600 2166.012 1.928 ;
    RECT 2165.892 127.672 2166.012 129.000 ;
    RECT 2171.100 0.600 2171.220 1.928 ;
    RECT 2171.100 127.672 2171.220 129.000 ;
    RECT 2171.292 0.600 2171.412 1.928 ;
    RECT 2171.292 127.672 2171.412 129.000 ;
    RECT 2176.500 0.600 2176.620 1.928 ;
    RECT 2176.500 127.672 2176.620 129.000 ;
    RECT 2176.692 0.600 2176.812 1.928 ;
    RECT 2176.692 127.672 2176.812 129.000 ;
    RECT 2181.900 0.600 2182.020 1.928 ;
    RECT 2181.900 127.672 2182.020 129.000 ;
    RECT 2182.092 0.600 2182.212 1.928 ;
    RECT 2182.092 127.672 2182.212 129.000 ;
    RECT 2187.300 0.600 2187.420 1.928 ;
    RECT 2187.300 127.672 2187.420 129.000 ;
    RECT 2187.492 0.600 2187.612 1.928 ;
    RECT 2187.492 127.672 2187.612 129.000 ;
    RECT 2192.700 0.600 2192.820 1.928 ;
    RECT 2192.700 127.672 2192.820 129.000 ;
    RECT 2192.892 0.600 2193.012 1.928 ;
    RECT 2192.892 127.672 2193.012 129.000 ;
    RECT 2198.100 0.600 2198.220 1.928 ;
    RECT 2198.100 127.672 2198.220 129.000 ;
    RECT 2198.292 0.600 2198.412 1.928 ;
    RECT 2198.292 127.672 2198.412 129.000 ;
    RECT 2203.500 0.600 2203.620 1.928 ;
    RECT 2203.500 127.672 2203.620 129.000 ;
    RECT 2203.692 0.600 2203.812 1.928 ;
    RECT 2203.692 127.672 2203.812 129.000 ;
    RECT 2208.900 0.600 2209.020 1.928 ;
    RECT 2208.900 127.672 2209.020 129.000 ;
    RECT 2209.092 0.600 2209.212 1.928 ;
    RECT 2209.092 127.672 2209.212 129.000 ;
    RECT 2214.300 0.600 2214.420 1.928 ;
    RECT 2214.300 127.672 2214.420 129.000 ;
    RECT 2214.492 0.600 2214.612 1.928 ;
    RECT 2214.492 127.672 2214.612 129.000 ;
    RECT 2219.700 0.600 2219.820 1.928 ;
    RECT 2219.700 127.672 2219.820 129.000 ;
    RECT 2219.892 0.600 2220.012 1.928 ;
    RECT 2219.892 127.672 2220.012 129.000 ;
    RECT 2225.100 0.600 2225.220 1.928 ;
    RECT 2225.100 127.672 2225.220 129.000 ;
    RECT 2225.292 0.600 2225.412 1.928 ;
    RECT 2225.292 127.672 2225.412 129.000 ;
    RECT 2230.500 0.600 2230.620 1.928 ;
    RECT 2230.500 127.672 2230.620 129.000 ;
    RECT 2230.692 0.600 2230.812 1.928 ;
    RECT 2230.692 127.672 2230.812 129.000 ;
    RECT 2235.900 0.600 2236.020 1.928 ;
    RECT 2235.900 127.672 2236.020 129.000 ;
    RECT 2236.092 0.600 2236.212 1.928 ;
    RECT 2236.092 127.672 2236.212 129.000 ;
    RECT 2241.300 0.600 2241.420 1.928 ;
    RECT 2241.300 127.672 2241.420 129.000 ;
    RECT 2241.492 0.600 2241.612 1.928 ;
    RECT 2241.492 127.672 2241.612 129.000 ;
  END
END ot_s81_pma_txm

END LIBRARY
